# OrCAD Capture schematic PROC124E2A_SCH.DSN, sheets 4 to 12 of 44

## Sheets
4 12. SOC POWER SUPPLY PMIC: size C; title: SOC POWER SUPPLY PMIC
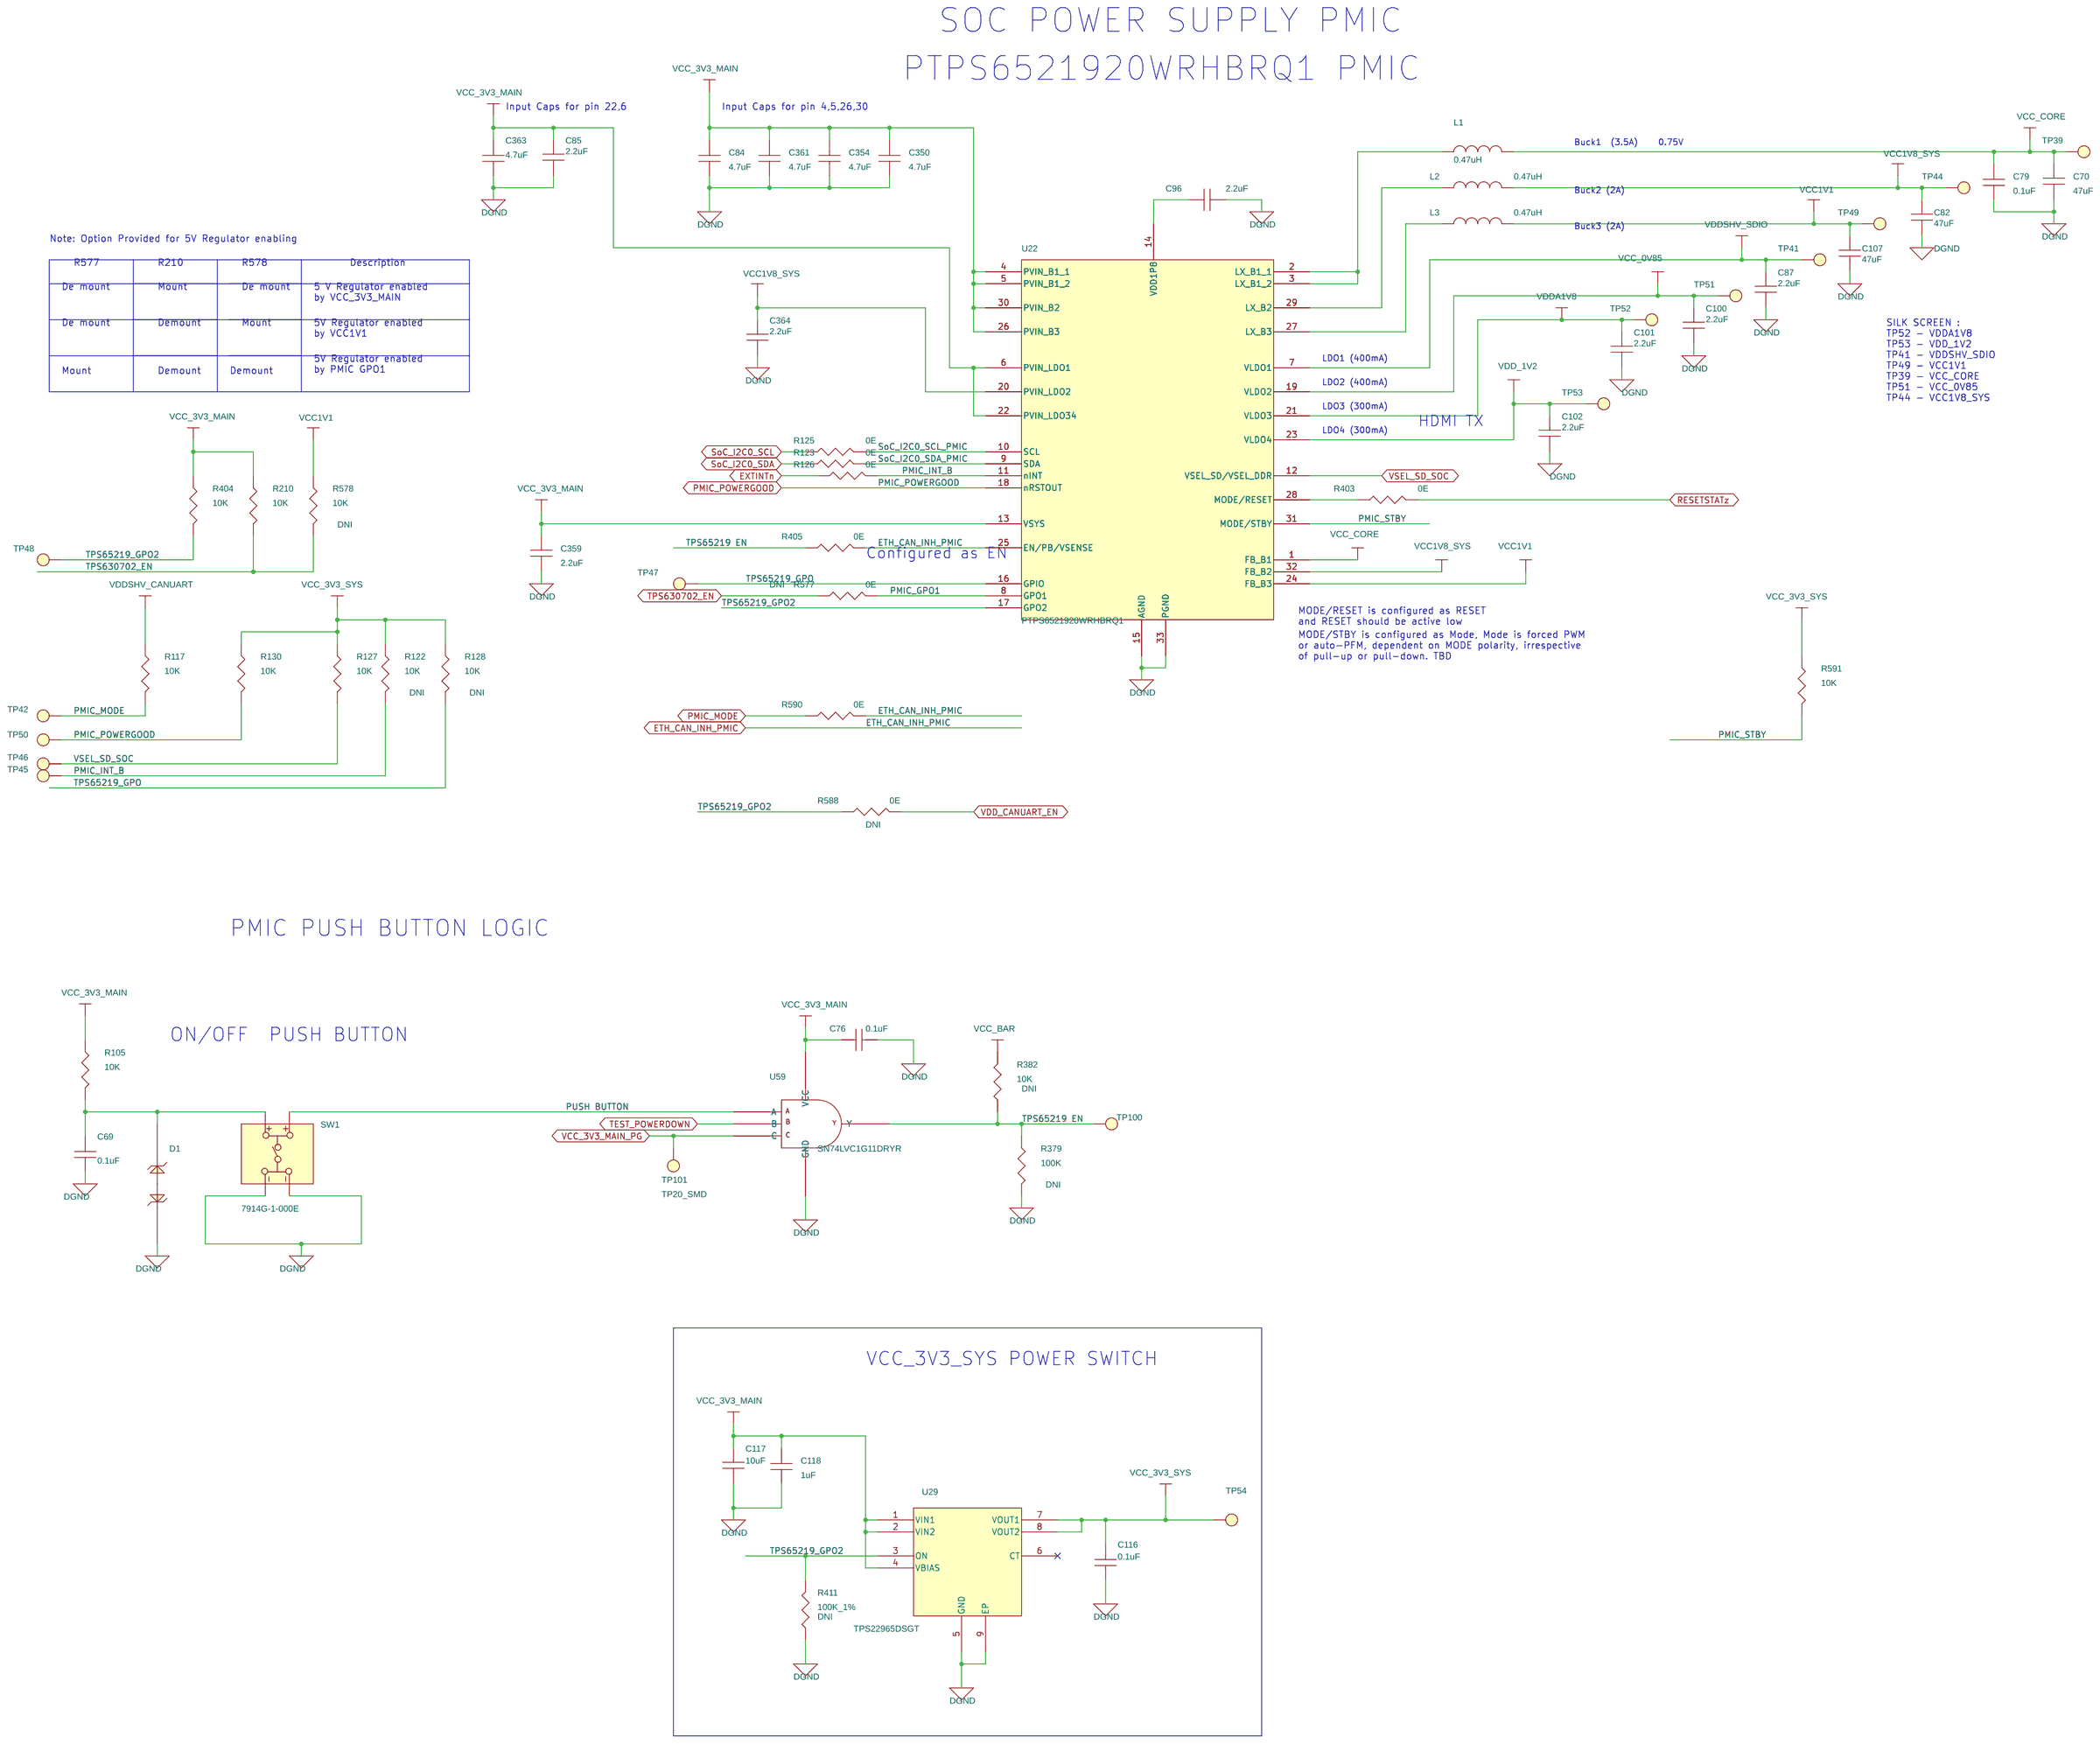
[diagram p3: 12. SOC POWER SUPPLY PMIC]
5 01. TABLE OF CONTENTS: title: TABLE OF CONTENTS
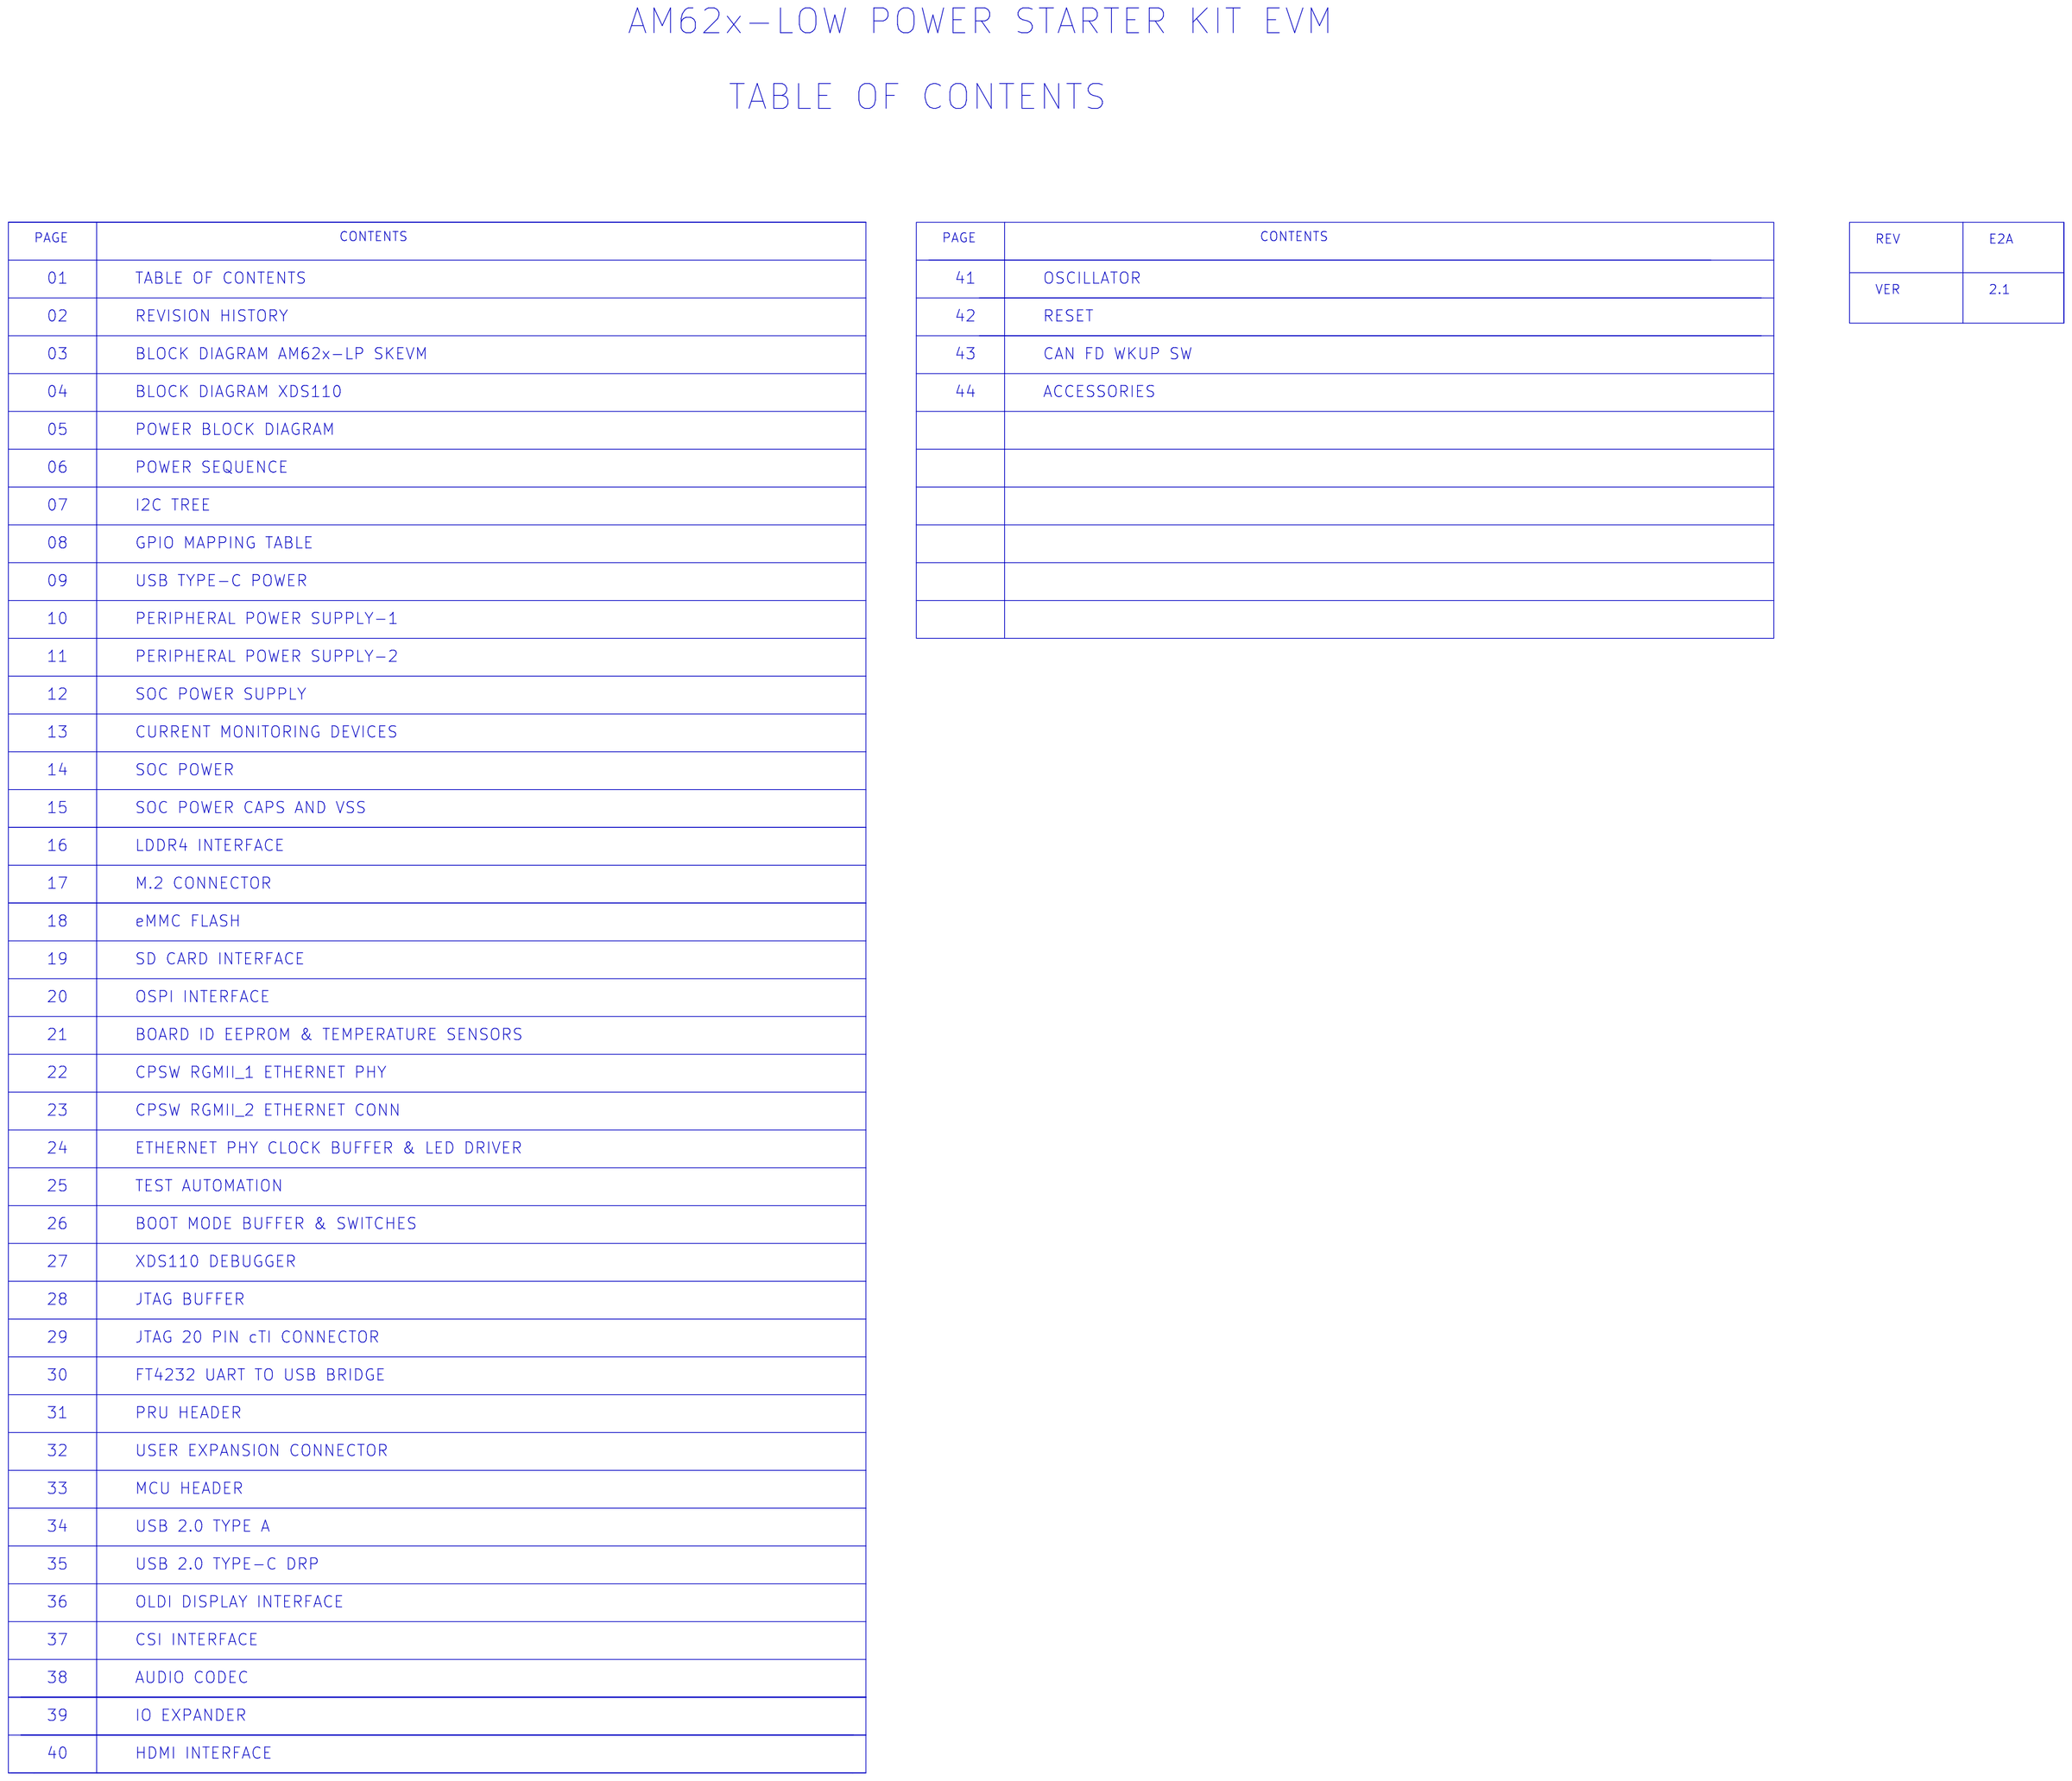
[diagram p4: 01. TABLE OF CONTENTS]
6 02. REVISION HISTORY: title: REVISION HISTORY
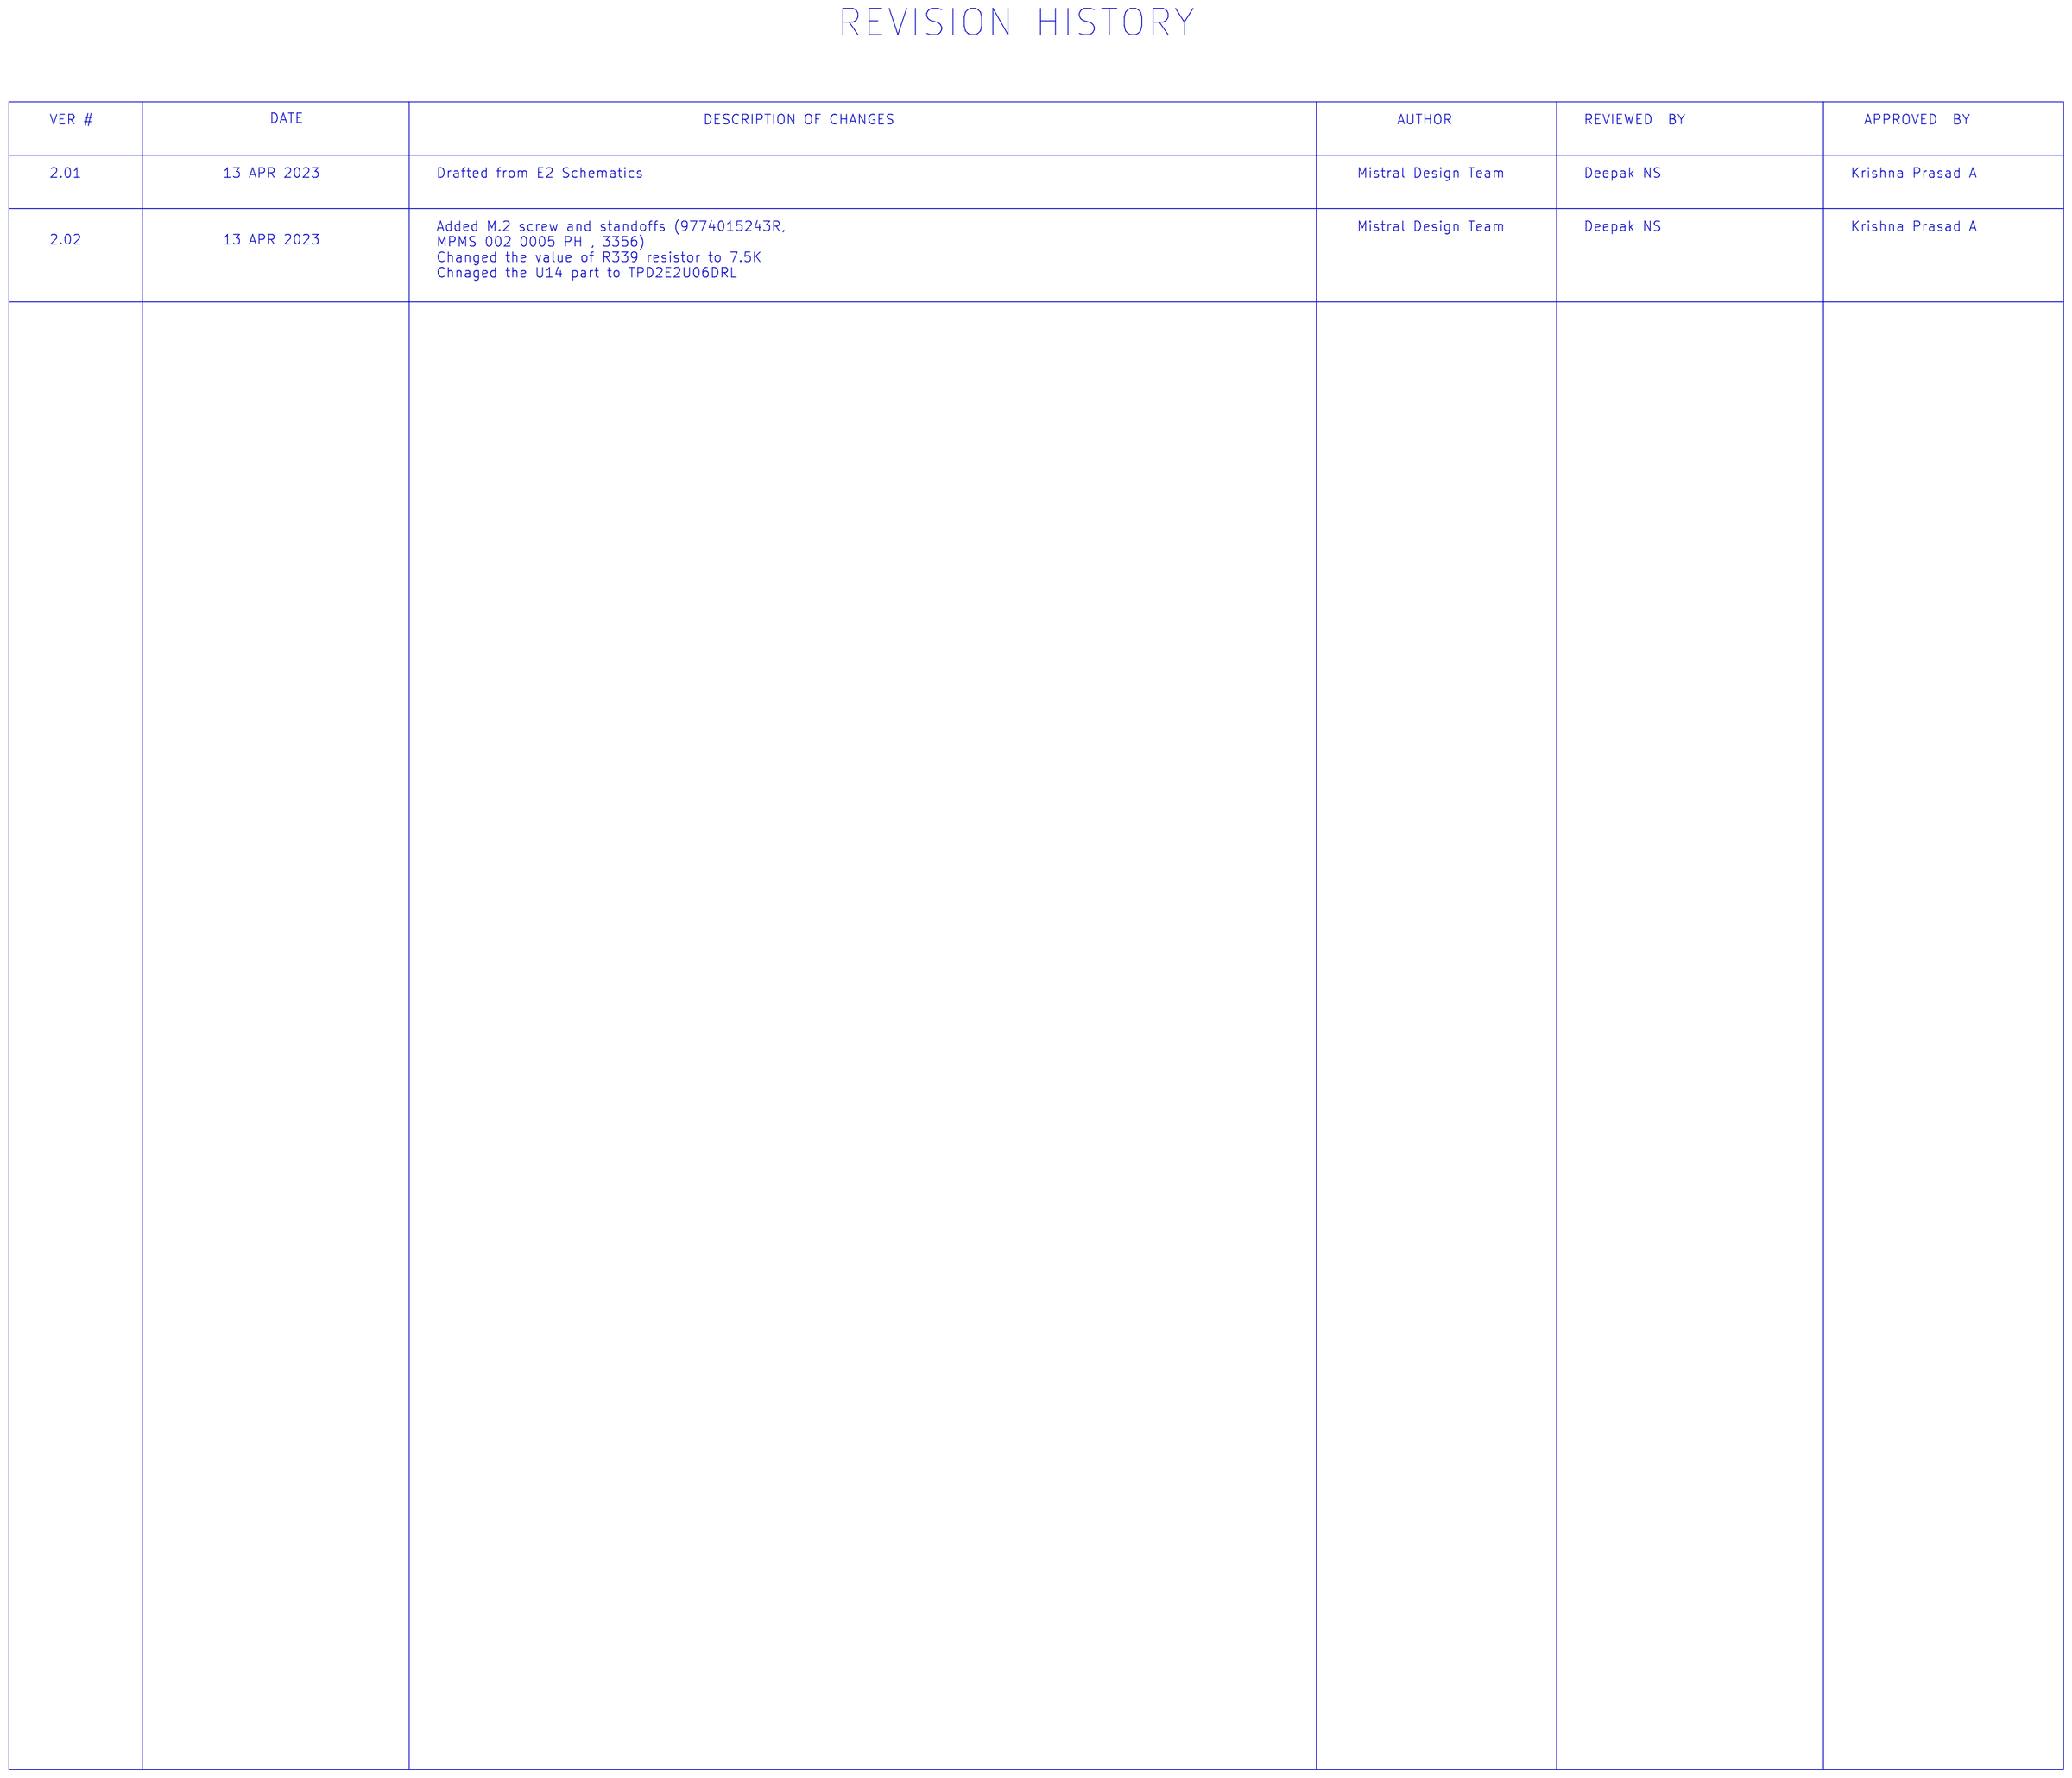
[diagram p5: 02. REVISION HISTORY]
7 03. BLOCK DGM AM62X-LP-SKEVM: title: BLOCK DIAGRAM AM62Q-LP_ SKEVM
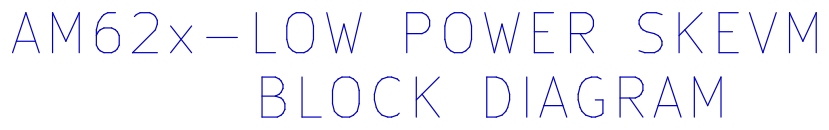
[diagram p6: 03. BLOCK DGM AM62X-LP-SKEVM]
8 04. BLOCK DIAGRAM_XDS110: title: BLOCK DIAGRAM_XDS110
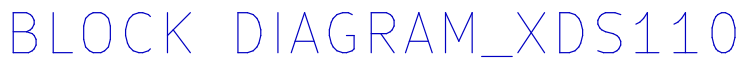
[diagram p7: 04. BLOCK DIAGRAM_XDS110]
9 05. POWER BLOCK DGM: title: POWER BLOCK DGM
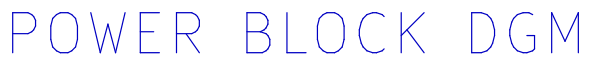
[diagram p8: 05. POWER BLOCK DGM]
10 06. POWER SEQUENCE: title: POWER SEQUENCE
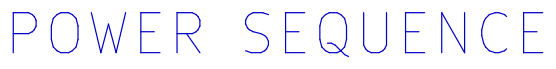
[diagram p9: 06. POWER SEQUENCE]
11 07. I2C TREE: title: I2C TREE
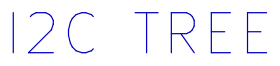
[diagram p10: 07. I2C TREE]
12 08. GPIO MAPPING TABLE: title: GPIO MAPPING TABLE

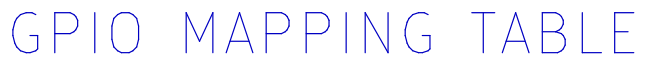
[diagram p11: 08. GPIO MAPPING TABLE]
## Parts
C69  0.1uF  [CAP0201_0-5]
C70  47uF  [CAP1206_2]
C76  0.1uF  [CAP0402_0-75]
C79  0.1uF  [CAP0201_0-5]
C82  47uF  [CAP1206_2]
C84  4.7uF  [CAP0402_0-75]
C85  2.2uF  [CAP0201_0-5]
C87  2.2uF  [CAP0201_0-5]
C96  2.2uF  [CAP0201_0-5]
C100  2.2uF  [CAP0201_0-5]
C101  2.2uF  [CAP0201_0-5]
C102  2.2uF  [CAP0201_0-5]
C107  47uF  [CAP1206_2]
C116  0.1uF  [CAP0201_0-5]
C117  10uF  [CAP0402_0-75]
C118  1uF  [CAP0201_0-5]
C350  4.7uF  [CAP0402_0-75]
C354  4.7uF  [CAP0402_0-75]
C359  2.2uF  [CAP0201_0-5]
C361  4.7uF  [CAP0402_0-75]
C363  4.7uF  [CAP0402_0-75]
C364  2.2uF  [CAP0201_0-5]
D1  TPD1E10B06DPYR  [DIO_DFN0402_0-5]
L1  0.47uH  [IND1008_1-2]
L2  0.47uH  [IND0806_1-2]
L3  0.47uH  [IND0806_1-2]
R105  10K  [RES0201_0-5]
R117  10K  [RES0201_0-5]
R122  10K  [RES0201_0-5]
R123  0E  [RES0201_0-5]
R125  0E  [RES0201_0-5]
R126  0E  [RES0201_0-5]
R127  10K  [RES0201_0-5]
R128  10K  [RES0201_0-5]
R130  10K  [RES0201_0-5]
R210  10K  [RES0201_0-5]
R379  100K  [RES0201_0-5]
R382  10K  [RES0201_0-5]
R403  0E  [RES0201_0-5]
R404  10K  [RES0201_0-5]
R405  0E  [RES0201_0-5]
R411  100K_1%  [RES0402_0-5]
R577  0E  [RES0201_0-5]
R578  10K  [RES0201_0-5]
R588  0E  [RES0201_0-5]
R590  0E  [RES0201_0-5]
R591  10K  [RES0201_0-5]
SW1  7914G-1-000E  [SW4_100X216_200X200_SMD_4-2]
TP39  TP20_SMD  [TP20_SMD]
TP41  TP20_SMD  [TP20_SMD]
TP42  TP20_SMD  [TP20_SMD]
TP44  TP20_SMD  [TP20_SMD]
TP45  TP20_SMD  [TP20_SMD]
TP46  TP20_SMD  [TP20_SMD]
TP47  TP20_SMD  [TP20_SMD]
TP48  TP20_SMD  [TP20_SMD]
TP49  TP20_SMD  [TP20_SMD]
TP50  TP20_SMD  [TP20_SMD]
TP51  TP20_SMD  [TP20_SMD]
TP52  TP20_SMD  [TP20_SMD]
TP53  TP20_SMD  [TP20_SMD]
TP54  TP20_SMD  [TP20_SMD]
TP100  TP20_SMD  [TP20_SMD]
TP101  TP20_SMD  [TP20_SMD]
U22  PTPS6521920WRHBRQ1  [QFN32_19-68_200X200_1_EP3-8]
U29  TPS22965DSGT  [WSON8_19-68_80X80_0-8]
U59  SN74LVC1G11DRYR  [SON6_SN74LVC2G17_40X60_0-6]

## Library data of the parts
C69 C116 = CAP: CAP CERAMIC 0.1uF 16V 10% X5R 0201; Alt_Mfr_name: YAGEO AMERICA; Alt_Mfr_part_number: CC0402KRX5R8BB104; Chkd/date: MANIRAJA/230118; Crtd /date: MANIRAJA/230118; Custom_Duty: 15%; Customs_HS_Code: 85322990; Distributor_name: DIGIKEY; Distributor_part_number: 490-14305-1-ND; Footprint Path: Y:\MIS_DATABASE\Library\ALTIUM_TOOL\PCB_FOOTPRINTS\Altium_Footprint_Lib.PcbLib; Height: 0.33MM; Library Path: Y:\MIS_DATABASE\Library\ALTIUM_TOOL\SCHEMATICS_PARTS\MS_DISCRETE_Library.schlib; Mfr_name: MURATA; Mfr_part_number: GRM033R61C104KE14D; Mistral Part No: 120009030072-R; Package: 0201; Part_type: CAPACITORS\CERAMIC; Project: TI_MAXIE_CPB; RoHS: RoHS; Temperature: -55°C+85°C; Tolerance: 10%; Voltage: 16V; Wattage: NA; Weight: 0.33mg; Datasheet: Y:\MIS_DATABASE\DATASHEETS\CAPACITORS\GRM033R61C104KE14.PDF
C70 = CAP: CAP CERAMIC 47uF 10V 10% X5R 1206; Chkd/date: MANIRAJA/260219; Crtd /date: JEBRAN/090316; Custom_Duty: 15%; Customs_HS_Code: 85322990; Distributor_name: DIGIKEY; Distributor_part_number: 490-9673-1-ND; Footprint Path: Y:\MIS_DATABASE\Library\ALTIUM_TOOL\PCB_FOOTPRINTS\Altium_Footprint_Lib.PcbLib; Height: 1.80MM; Library Path: Y:\MIS_DATABASE\Library\ALTIUM_TOOL\SCHEMATICS_PARTS\MS_DISCRETE_Library.schlib; Manufacturer: MURATA; Mfr_name: MURATA; Mfr_part_number: GRM31CR61A476KE15L; Mistral Part No: 120019020018-R; Package: 1206; Part_type: CAPACITORS\CERAMIC; Project: RCI_DLS_CARD; RoHS: RoHS; Temperature: -55°C+85°C; Tolerance: 10%; Voltage: 10V; Wattage: NA; Weight: 40mg; Datasheet: Y:\MIS_DATABASE\DATASHEETS\CAPACITORS\MURATA-GXX-SER_NOV17.PDF
C76 = CAP: CAP CERAMIC 0.1uF 50V 10% X7R 0402; Alt_Mfr_name: YAGEO AMERICA; Alt_Mfr_part_number: CC0402KRX5R8BB104; Chkd/date: MANIRAJA/261020; Crtd /date: ALVY/211020; Custom_Duty: 15%; Customs_HS_Code: 85322990; Distributor_name: DIGIKEY; Distributor_part_number: 490-10700-1-ND; Footprint Path: Y:\MIS_DATABASE\Library\ALTIUM_TOOL\PCB_FOOTPRINTS\Altium_Footprint_Lib.PcbLib; Height: 0.55MM; Library Path: Y:\MIS_DATABASE\Library\ALTIUM_TOOL\SCHEMATICS_PARTS\MS_DISCRETE_Library.schlib; Mfr_name: MURATA; Mfr_part_number: GRM155R71H104KE14D; Mistral Part No: 120011100014-R; Package: 0402; Part_type: CAPACITORS\CERAMIC; Project: J7_CP; RoHS: RoHS; Temperature: -55°C+125°C; Tolerance: 10%; Voltage: 50V; Wattage: NA; Weight: 3.1mg; Datasheet: Y:\MIS_DATABASE\DATASHEETS\CAPACITORS\GRM155R71H104KE14.PDF
C79 = CAP: CAP CERAMIC 0.1uF 16V 10% X5R 0201; Chkd/date: MANIRAJA/230118; Crtd /date: MANIRAJA/230118; Custom_Duty: 15%; Customs_HS_Code: 85322990; Distributor_name: DIGIKEY; Distributor_part_number: 490-14305-1-ND; Footprint Path: Y:\MIS_DATABASE\Library\ALTIUM_TOOL\PCB_FOOTPRINTS\Altium_Footprint_Lib.PcbLib; Height: 0.33MM; Library Path: Y:\MIS_DATABASE\Library\ALTIUM_TOOL\SCHEMATICS_PARTS\MS_DISCRETE_Library.schlib; Mfr_name: MURATA; Mfr_part_number: GRM033R61C104KE14D; Mistral Part No: 120009030072-R; Package: 0201; Part_type: CAPACITORS\CERAMIC; Project: TI_MAXIE_CPB; RoHS: RoHS; Temperature: -55°C+85°C; Tolerance: 10%; Voltage: 16V; Wattage: NA; Weight: 0.33mg; Datasheet: Y:\MIS_DATABASE\DATASHEETS\CAPACITORS\GRM033R61C104KE14.PDF
C82 C107 = CAP: CAP CERAMIC 47uF 10V 10% X5R 1206; Chkd/date: MANIRAJA/260219; Crtd /date: JEBRAN/090316; Custom_Duty: 15%; Customs_HS_Code: 85322990; Distributor_name: DIGIKEY; Distributor_part_number: 490-9673-1-ND; Footprint Path: Y:\MIS_DATABASE\Library\ALTIUM_TOOL\PCB_FOOTPRINTS\Altium_Footprint_Lib.PcbLib; Height: 1.80MM; Library Path: Y:\MIS_DATABASE\Library\ALTIUM_TOOL\SCHEMATICS_PARTS\MS_DISCRETE_Library.schlib; Mfr_name: MURATA; Mfr_part_number: GRM31CR61A476KE15L; Mistral Part No: 120019020018-R; Package: 1206; Part_type: CAPACITORS\CERAMIC; Project: RCI_DLS_CARD; RoHS: RoHS; Temperature: -55°C+85°C; Tolerance: 10%; Voltage: 10V; Wattage: NA; Weight: 40mg; Datasheet: Y:\MIS_DATABASE\DATASHEETS\CAPACITORS\MURATA-GXX-SER_NOV17.PDF
C84 C350 C354 C361 C363 = CAP: CAP CERAMIC 4.7uF 10V 20% X5R 0402; Chkd/date: MANIRAJA/110718; Crtd /date: ALVY/110718; Custom_Duty: 15%; Customs_HS_Code: 85322990; Distributor_name: DIGIKEY; Distributor_part_number: 490-14306-1-ND; Footprint Path: Y:\MIS_DATABASE\Library\ALTIUM_TOOL\PCB_FOOTPRINTS\Altium_Footprint_Lib.PcbLib; Height: 0.65MM; Library Path: Y:\MIS_DATABASE\Library\ALTIUM_TOOL\SCHEMATICS_PARTS\MS_DISCRETE_Library.schlib; Mfr_name: MURATA; Mfr_part_number: GRM155R61A475MEAAD; Mistral Part No: 120012060002-R; Package: 0402; Part_type: CAPACITORS\CERAMIC; Project: TI_J7SVB_PCIE_ADD-ON-CARD; RoHS: RoHS; Temperature: -55°C+85°C; Tolerance: 20%; Voltage: 10V; Wattage: NA; Weight: 14mg; Datasheet: Y:\MIS_DATABASE\DATASHEETS\CAPACITORS\GRM155R61A475MEAAD.PDF
C85 C87 C96 C100-C102 C364 = CAP: CAP CERAMIC 2.2uF 10V 10% X5R 0201; Chkd/date: MANIRAJA/220918; Crtd /date: MANIRAJA/220918; Custom_Duty: 15%; Customs_HS_Code: 85322990; Distributor_name: DIGIKEY; Distributor_part_number: 490-13227-1-ND; Footprint Path: Y:\MIS_DATABASE\Library\ALTIUM_TOOL\PCB_FOOTPRINTS\Altium_Footprint_Lib.PcbLib; Height: 0.39MM; Library Path: Y:\MIS_DATABASE\Library\ALTIUM_TOOL\SCHEMATICS_PARTS\MS_DISCRETE_Library.schlib; Mfr_name: MURATA; Mfr_part_number: GRM033R61A225KE47D; Mistral Part No: 120018090044-R; Package: 0201; Part_type: CAPACITORS\CERAMIC; Project: TI_60GHz-AOP; RoHS: RoHS; Temperature: -55°C+85°C; Tolerance: 10%; Voltage: 10V; Wattage: NA; Weight: 0.33mg; Datasheet: Y:\MIS_DATABASE\DATASHEETS\CAPACITORS\GRM033R61A225KE47D.PDF
C117 = CAP: CAP CERAMIC 10uF 10V 20% X5R 0402; Chkd/date: MANIRAJA/300520; Crtd /date: ALVY/260520; Custom_Duty: 15%; Customs_HS_Code: 85322990; Distributor_name: DIGIKEY; Distributor_part_number: 490-GRM155R61A106ME11DTR-ND; Footprint Path: Y:\MIS_DATABASE\Library\ALTIUM_TOOL\PCB_FOOTPRINTS\Altium_Footprint_Lib.PcbLib; Height: 0.55MM; Library Path: Y:\MIS_DATABASE\Library\ALTIUM_TOOL\SCHEMATICS_PARTS\MS_DISCRETE_Library.schlib; Mfr_name: MURATA; Mfr_part_number: GRM155R61A106ME11D; Mistral Part No: 120013110019-R; Package: 0402; Part_type: CAPACITORS\CERAMIC; Project: QCS610_NANOSOM; RoHS: RoHS; Temperature: -55°C+85°C; Tolerance: 20%; Voltage: 10V; Wattage: NA; Weight: 3.1mg; Datasheet: Y:\MIS_DATABASE\DATASHEETS\CAPACITORS\MURATA-GXX-SER_NOV17.PDF
C118 = CAP: CAP CERAMIC 1uF 16V 20% X5R 0201; Chkd/date: MANIRAJA/300520; Crtd /date: ALVY/260520; Custom_Duty: 15%; Customs_HS_Code: 85322990; Distributor_name: DIGIKEY; Distributor_part_number: 490-18654-1-ND; Footprint Path: Y:\MIS_DATABASE\Library\ALTIUM_TOOL\PCB_FOOTPRINTS\Altium_Footprint_Lib.PcbLib; Height: 0.39MM; Library Path: Y:\MIS_DATABASE\Library\ALTIUM_TOOL\SCHEMATICS_PARTS\MS_DISCRETE_Library.schlib; Mfr_name: MURATA; Mfr_part_number: GRM033R61C105ME15D; Mistral Part No: 120018090038-R; Package: 0201; Part_type: CAPACITORS\CERAMIC; Project: QCS610_NANOSOM; RoHS: RoHS; Temperature: -55°C+85°C; Tolerance: 20%; Voltage: 16V; Wattage: NA; Weight: 0.33mg; Datasheet: Y:\MIS_DATABASE\DATASHEETS\CAPACITORS\GRM033R61C105ME15.PDF
C359 = CAP: CAP CERAMIC 2.2uF 10V 10% X5R 0201; Alt_Mfr_name: YAGEO AMERICA; Alt_Mfr_part_number: CC0402KRX5R8BB104; Chkd/date: MANIRAJA/220918; Crtd /date: MANIRAJA/220918; Custom_Duty: 15%; Customs_HS_Code: 85322990; Distributor_name: DIGIKEY; Distributor_part_number: 490-13227-1-ND; Footprint Path: Y:\MIS_DATABASE\Library\ALTIUM_TOOL\PCB_FOOTPRINTS\Altium_Footprint_Lib.PcbLib; Height: 0.39MM; Library Path: Y:\MIS_DATABASE\Library\ALTIUM_TOOL\SCHEMATICS_PARTS\MS_DISCRETE_Library.schlib; Mfr_name: MURATA; Mfr_part_number: GRM033R61A225KE47D; Mistral Part No: 120018090044-R; Package: 0201; Part_type: CAPACITORS\CERAMIC; Project: TI_60GHz-AOP; RoHS: RoHS; Temperature: -55°C+85°C; Tolerance: 10%; Voltage: 10V; Wattage: NA; Weight: 0.33mg; Datasheet: Y:\MIS_DATABASE\DATASHEETS\CAPACITORS\GRM033R61A225KE47D.PDF
D1 = DIODE_SOD323: DIODE 1CH ESD PROTECTION X1SON2; Chkd/date: MANIRAJA/040420; Crtd /date: VASANTHA/181114; Custom_Duty: 15%; Customs_HS_Code: 85423100; Distributor_name: DIGIKEY; Distributor_part_number: 296-30406-1-ND; Footprint Path: Y:\MIS_DATABASE\Library\ALTIUM_TOOL\PCB_FOOTPRINTS\Altium_Footprint_Lib.PcbLib; Height: 0.45MM; Library Path: Y:\MIS_DATABASE\Library\ALTIUM_TOOL\SCHEMATICS_PARTS\MS_DISCRETE_Library.schlib; Mfr_name: TEXAS INSTRUMENTS; Mistral Part No: 130014110022-R; Package: X1SON2; Part_type: DIODE; Project: GALILEO_EVM; RoHS: RoHS; Temperature: -40°C+125°C; Tolerance: NA; Voltage: NA; Wattage: NA; Weight: 1mg; Datasheet: Y:\MIS_DATABASE\DATASHEETS\ICS\INTERFACE\TPD1E10B06-SER.PDF
L1 = INDUCTOR: IND CHIP 0.47uH 4.9A 20% 1008; Chkd/date: ALVY/110322; Crtd /date: TAMILARASU/100322; Custom_Duty: 24%; Customs_HS_Code: 85437099; Distributor_name: DIGIKEY; Distributor_part_number: 490-13049-1-ND; Footprint Path: Y:\MIS_DATABASE\Library\ALTIUM_TOOL\PCB_FOOTPRINTS\Altium_Footprint_Lib.PcbLib; Height: 1.20MM; Library Path: Y:\MIS_DATABASE\Library\ALTIUM_TOOL\SCHEMATICS_PARTS\MS_DISCRETE_Library.schlib; Mfr_name: MURATA; Mfr_part_number: DFE252012F-R47M=P2; Mistral Part No: 130022030019-R; Package: 1008; Project: TI_AM62Q_SKEVM_xNAND_BRD; RoHS: RoHS; Temperature: -40°C+125°C; Tolerance: 20%; Voltage: NA; Wattage: NA; Weight: NA; Datasheet: Y:\MIS_DATABASE\DATASHEETS\DISCRETES\INDUCTORS\DFE252012F.PDF
L2 L3 = INDUCTOR: IND CHIP 0.47uH 4.5A 20% 0806; Chkd/date: MANIRAJA/121020; Crtd /date: ALVY/121020; Custom_Duty: 24%; Customs_HS_Code: 85437099; Distributor_name: DIGIKEY; Distributor_part_number: DFE201612E-R47M=P2-ND; Footprint Path: Y:\MIS_DATABASE\Library\ALTIUM_TOOL\PCB_FOOTPRINTS\Altium_Footprint_Lib.PcbLib; Height: 1.20MM; Library Path: Y:\MIS_DATABASE\Library\ALTIUM_TOOL\SCHEMATICS_PARTS\MS_DISCRETE_Library.schlib; Mfr_name: MURATA; Mfr_part_number: DFE201612E-R47M=P2; Mistral Part No: 130020100030-R; Package: 0806; Project: AM64X_SKEVM; RoHS: RoHS; Temperature: -40°C+125°C; Tolerance: 20%; Voltage: NA; Wattage: NA; Weight: 18.8mg; Datasheet: Y:\MIS_DATABASE\DATASHEETS\DISCRETES\INDUCTORS\DFE201612E.PDF
R105 R117 R127 R130 R210 R404 R591 = RESISTOR: RES 10K 1/20W 5% 0201; Chkd/date: MANIRAJA/050517; Crtd /date: MANIRAJA/050517; Custom_Duty: 15%; Customs_HS_Code: 85332119; Distributor_name: DIGIKEY; Distributor_part_number: 311-10KNCT-ND; Footprint Path: Y:\MIS_DATABASE\Library\ALTIUM_TOOL\PCB_FOOTPRINTS\Altium_Footprint_Lib.PcbLib; Height: 0.26MM; Library Path: Y:\MIS_DATABASE\Library\ALTIUM_TOOL\SCHEMATICS_PARTS\MS_DISCRETE_Library.schlib; Mfr_name: YAGEO AMERICA; Mfr_part_number: RC0201JR-0710KL; Mistral Part No: 110010070051-R; Package: 0201; Part_type: RESISTORS\FIXED; Project: GOLDEN-I LITE; RoHS: RoHS; Temperature: -55°C+125°C; Tolerance: 5%; Voltage: NA; Wattage: 1/20W; Weight: 0.17mg; Datasheet: Y:\MIS_DATABASE\DATASHEETS\RESISTORS\RCXXXXL-SER_MAR18.PDF
R122 R128 R382 R578 = RESISTOR: RES 10K 1/20W 5% 0201; Assembly_Instruction: DNI; Chkd/date: MANIRAJA/050517; Crtd /date: MANIRAJA/050517; Custom_Duty: 15%; Customs_HS_Code: 85332119; Distributor_name: DIGIKEY; Distributor_part_number: 311-10KNCT-ND; Footprint Path: Y:\MIS_DATABASE\Library\ALTIUM_TOOL\PCB_FOOTPRINTS\Altium_Footprint_Lib.PcbLib; Height: 0.26MM; Library Path: Y:\MIS_DATABASE\Library\ALTIUM_TOOL\SCHEMATICS_PARTS\MS_DISCRETE_Library.schlib; Mfr_name: YAGEO AMERICA; Mfr_part_number: RC0201JR-0710KL; Mistral Part No: 110010070051-R; Package: 0201; Part_type: RESISTORS\FIXED; Project: GOLDEN-I LITE; RoHS: RoHS; Temperature: -55°C+125°C; Tolerance: 5%; Voltage: NA; Wattage: 1/20W; Weight: 0.17mg; Datasheet: Y:\MIS_DATABASE\DATASHEETS\RESISTORS\RCXXXXL-SER_MAR18.PDF
R123 R125 R403 = RESISTOR: RES 0E 1/20W JUMPER 0201; Chkd/date: MANIRAJA/290421; Crtd /date: ALVY/290421; Custom_Duty: 15%; Customs_HS_Code: 85332119; Distributor_name: DIGIKEY; Distributor_part_number: P15979CT-ND; Footprint Path: Y:\MIS_DATABASE\Library\ALTIUM_TOOL\PCB_FOOTPRINTS\Altium_Footprint_Lib.PcbLib; Height: 0.26MM; Library Path: Y:\MIS_DATABASE\Library\ALTIUM_TOOL\SCHEMATICS_PARTS\MS_DISCRETE_Library.schlib; Mfr_name: PANASONIC-ECG; Mfr_part_number: ERJ-1GN0R00C; Mistral Part No: 110009030078-R; Package: 0201; Part_type: RESISTORS\FIXED; Project: SRMS-SAR_BRD; RoHS: RoHS; Temperature: -55°C+125°C; Tolerance: NA; Voltage: NA; Wattage: 1/20W; Weight: 0.15mg; Datasheet: Y:\MIS_DATABASE\DATASHEETS\RESISTORS\PAN-ERJSER_NOV17.PDF
R126 R405 R590 = RESISTOR: RES 0E 1/20W 5% 0201; Chkd/date: NAVEED/301214; Crtd /date: MUDDU/120710; Custom_Duty: 15%; Customs_HS_Code: 85332119; Distributor_name: DIGIKEY; Distributor_part_number: 311-0.0NCT-ND; Footprint Path: Y:\MIS_DATABASE\Library\ALTIUM_TOOL\PCB_FOOTPRINTS\Altium_Footprint_Lib.PcbLib; Height: 0.26MM; Library Path: Y:\MIS_DATABASE\Library\ALTIUM_TOOL\SCHEMATICS_PARTS\MS_DISCRETE_Library.schlib; Mfr_name: YAGEO AMERICA; Mfr_part_number: RC0201JR-070RL; Mistral Part No: 110010070067-R; Package: 0201; Part_type: RESISTORS\FIXED; Project: PB_BUGBASE; RoHS: RoHS; Temperature: -55°C+125°C; Tolerance: 5%; Voltage: NA; Wattage: 1/20W; Weight: 0.17mg; Datasheet: Y:\MIS_DATABASE\DATASHEETS\RESISTORS\RCXXXXL-SER_MAR18.PDF
R379 = RESISTOR: RES 100K 1/20W 5% 0201; Assembly_Instruction: DNI; Chkd/date: PRAVEEN/080922; Crtd /date: TAMILARASU/080922; Custom_Duty: 15%; Customs_HS_Code: 85332119; Distributor_name: DIGIKEY; Distributor_part_number: P123223CT-ND; Footprint Path: Y:\MIS_DATABASE\Library\ALTIUM_TOOL\PCB_FOOTPRINTS\Altium_Footprint_Lib.PcbLib; Height: 0.26MM; Library Path: Y:\MIS_DATABASE\Library\ALTIUM_TOOL\SCHEMATICS_PARTS\MS_DISCRETE_Library.schlib; Mfr_name: PANASONIC-ECG; Mfr_part_number: ERJ-1GNJ104C; Mistral Part No: 110022090005-R; Package: 0201; Part_type: RESISTORS\FIXED; Project: SK AM62Q LP EVM BRD; RoHS: RoHS; Temperature: -55°C+125°C; Tolerance: 5%; Voltage: NA; Wattage: 1/20W; Weight: 0.15mg; Datasheet: Y:\MIS_DATABASE\DATASHEETS\RESISTORS\PAN-ERJSER_NOV17.PDF
R411 = RESISTOR: RES 100K 1/10W 1% 0402; Assembly_Instruction: DNI; Chkd/date: VASANTHA/201216; Crtd /date: MAZHAR/130306; Custom_Duty: 15%; Customs_HS_Code: 85332119; Distributor_name: DIGIKEY; Distributor_part_number: P100KLCT-ND; Footprint Path: Y:\MIS_DATABASE\Library\ALTIUM_TOOL\PCB_FOOTPRINTS\Altium_Footprint_Lib.PcbLib; Height: 0.40MM; Library Path: Y:\MIS_DATABASE\Library\ALTIUM_TOOL\SCHEMATICS_PARTS\MS_DISCRETE_Library.schlib; Mfr_name: PANASONIC-ECG; Mfr_part_number: ERJ-2RKF1003X; Mistral Part No: 110009030187-R; Package: 0402; Part_type: RESISTORS\FIXED; Project: J32; RoHS: RoHS; Temperature: -55°C+155°C; Tolerance: 1%; Voltage: NA; Wattage: 1/10W; Weight: 0.8mg; Datasheet: Y:\MIS_DATABASE\DATASHEETS\RESISTORS\PAN-ERJSER_NOV17.PDF
R577 R588 = RESISTOR: RES 0E 1/20W 5% 0201; Assembly_Instruction: DNI; Chkd/date: NAVEED/301214; Crtd /date: MUDDU/120710; Custom_Duty: 15%; Customs_HS_Code: 85332119; Distributor_name: DIGIKEY; Distributor_part_number: 311-0.0NCT-ND; Footprint Path: Y:\MIS_DATABASE\Library\ALTIUM_TOOL\PCB_FOOTPRINTS\Altium_Footprint_Lib.PcbLib; Height: 0.26MM; Library Path: Y:\MIS_DATABASE\Library\ALTIUM_TOOL\SCHEMATICS_PARTS\MS_DISCRETE_Library.schlib; Mfr_name: YAGEO AMERICA; Mfr_part_number: RC0201JR-070RL; Mistral Part No: 110010070067-R; Package: 0201; Part_type: RESISTORS\FIXED; Project: PB_BUGBASE; RoHS: RoHS; Temperature: -55°C+125°C; Tolerance: 5%; Voltage: NA; Wattage: 1/20W; Weight: 0.17mg; Datasheet: Y:\MIS_DATABASE\DATASHEETS\RESISTORS\RCXXXXL-SER_MAR18.PDF
SW1 = 7914G-1-000E__7914G: SWITCH SPST-NO 4MM SQ SMD 7914G; Chkd/date: VASANTHA/271216; Crtd /date: BAVISH/051010; Custom_Duty: 24%; Customs_HS_Code: 85369090; Distributor_name: DIGIKEY; Distributor_part_number: 7914G-000ECT-ND; Height: 4.19MM; Library Ref: 7914G-1-000E _7914G; Mfr_name: BOURNS; Mistral Part No: 130015110004-R; Package: 7914G; Part_type: ELECTRO-MECHANICAL\SWITCH; Project: AAAUC; RoHS: RoHS; Temperature: -55°C+125°C; Tolerance: NA; Voltage: NA; Wattage: NA; Weight: NA; Datasheet: Y:\MIS_DATABASE\DATASHEETS\ICS\DIGITAL\COMBINATIONAL\7914G-1-000E.PDF
TP39 TP41 TP44 TP47-TP49 TP51-TP53 TP101 = TESTPOINT: TESTPOINT CIR 20 SMD; Chkd/date: SHREESHAIL/171006; Crtd /date: MAZHAR/171006; Custom_Duty: NA; Customs_HS_Code: NA; Distributor_name: NA; Distributor_part_number: NA; Footprint Path: Y:\MIS_DATABASE\Library\ALTIUM_TOOL\PCB_FOOTPRINTS\Altium_Footprint_Lib.PcbLib; Height: NA; Library Path: Y:\MIS_DATABASE\Library\ALTIUM_TOOL\SCHEMATICS_PARTS\MS_DISCRETE_Library.schlib; MECHANICAL 3D STEP FILE: NA; Manufacturer: LOCAL; Mfr_name: LOCAL; Mistral Part No: NA; Package: SMD; Project: BT MODULE_CSRBC04; RoHS: NA; Temperature: NA; Tolerance: NA; Voltage: NA; Wattage: NA; Weight: NA; Datasheet: NA
TP42 TP45 TP46 TP50 TP54 TP100 = TESTPOINT: TESTPOINT CIR 20 SMD; Chkd/date: SHREESHAIL/171006; Crtd /date: MAZHAR/171006; Custom_Duty: NA; Customs_HS_Code: NA; Distributor_name: NA; Distributor_part_number: NA; Footprint Path: Y:\MIS_DATABASE\Library\ALTIUM_TOOL\PCB_FOOTPRINTS\Altium_Footprint_Lib.PcbLib; Height: NA; Library Path: Y:\MIS_DATABASE\Library\ALTIUM_TOOL\SCHEMATICS_PARTS\MS_DISCRETE_Library.schlib; MECHANICAL 3D STEP FILE: NA; Mfr_name: LOCAL; Mistral Part No: NA; Package: SMD; Project: BT MODULE_CSRBC04; RoHS: NA; Temperature: NA; Tolerance: NA; Voltage: NA; Wattage: NA; Weight: NA; Datasheet: NA
U22 = TPS65219_QFN32: IC INTEGRATED POWER MANAGEMENT FOR ARM CORTEX-A53 PROCESSOR AND FPGA QFN32; Chkd/date: PRAVEEN/130123; Crtd /date: SHANKAR/110123; Custom_Duty: 15%; Customs_HS_Code: 85423100; Distributor_name: NA; Distributor_part_number: NA; Footprint Path: Y:\MIS_DATABASE\Library\ALTIUM_TOOL\PCB_FOOTPRINTS\Altium_Footprint_Lib.PcbLib; Height: 1.00MM; Library Path: Y:\MIS_DATABASE\Library\ALTIUM_TOOL\SCHEMATICS_PARTS\MS_MISCPOWER_Library.schlib; Mfr_name: TEXAS INSTRUMENTS; Mistral Part No: 142023010008-R; Package: QFN32; Part_type: ICS\POWER\MANAGEMENT; Project: AM62Q-LP_EVM; RoHS: NA; Temperature: -40°C+125°C; Tolerance: NA; Voltage: NA; Wattage: NA; Weight: NA; Datasheet: Y:\MIS_DATABASE\DATASHEETS\ICS\POWER\TPS65219.PDF
U29 = TPS22965DSGT_WSON8: IC 5.7V 6A 1-CHANNEL 16mE ON-RESISTANCE LOAD SWITCH WSON8; Chkd/date: MANIRAJA/080817; Crtd /date: VASANTHA/280714; Custom_Duty: 15%; Customs_HS_Code: 85423100; Distributor_name: DIGIKEY; Distributor_part_number: 296-34943-1-ND; Footprint Path: Y:\MIS_DATABASE\Library\ALTIUM_TOOL\PCB_FOOTPRINTS\Altium_Footprint_Lib.PcbLib; Height: 0.80MM; Library Path: Y:\MIS_DATABASE\Library\ALTIUM_TOOL\SCHEMATICS_PARTS\MS_MISCPOWER_Library.schlib; Mfr_name: TEXAS INSTRUMENTS; Mistral Part No: 142014070020-R; Package: WSON8; Part_type: ICS\POWER\DRIVER; Project: DC_MIST_DIGITAL CARD; RoHS: RoHS; Temperature: -40°C+105°C; Tolerance: NA; Voltage: NA; Wattage: NA; Weight: 11mg; Datasheet: Y:\MIS_DATABASE\DATASHEETS\ICS\POWER\TPS22965-SER.PDF
U59 = SN74LVC1G11DCKR_SC70-6: IC SINGLE 3-INPUT POSITIVE-AND GATE SON6; Chkd/date: MANIRAJA/270121; Crtd /date: ALVY/270121; Custom_Duty: 15%; Customs_HS_Code: 85423100; Distributor_name: DIGIKEY; Distributor_part_number: 296-30120-1-ND; Footprint Path: Y:\MIS_DATABASE\Library\ALTIUM_TOOL\PCB_FOOTPRINTS\Altium_Footprint_Lib.PcbLib; Height: 0.60MM; Library Path: Y:\MIS_DATABASE\Library\ALTIUM_TOOL\SCHEMATICS_PARTS\MS_GATE_Library.schlib; Mfr_name: TEXAS INSTRUMENTS; Mistral Part No: 141021010013-R; Package: SON6; Part_type: ICS\DIGITAL\GATES; Project: AM64X_SKEVM; RoHS: RoHS; Temperature: -40°C+125°C; Tolerance: NA; Voltage: NA; Wattage: NA; Weight: 33mg; Datasheet: Y:\MIS_DATABASE\DATASHEETS\ICS\DIGITAL\GATES\SN74LVC1G_NOV16.PDF

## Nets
DGND: C69.1 C70.2 C76.2 C79.1 C82.2 C84.1 C85.2 C87.2 C96.2 C100.2 C101.2 C102.2 C107.2 C116.1 C117.2 C118.1 C350.1 C354.1 C359.2 C361.1 C363.1 C364.2 D1.1 R379.2 R411.1 SW1.1 SW1.4 U22.15(AGND) U22.33(PGND) U29.5(GND) U29.9(EP) U59.2(GND) ; also on sheet 1 2 3 13 14 15 16 17 18 19 20 21 22 23 24 25 26 27 28 29 30 31 32 33 34 35 36 37 38 39 40 41 42 43
VCC1V1: C107.1 L3.2 R578.2 TP49.1(TP) U22.24(FB_B3) ; also on sheet 16
VCC1V8_SYS: C82.1 C364.1 L2.2 TP44.1(TP) U22.20(PVIN_LDO2) U22.32(FB_B2) ; also on sheet 16 19 20 22 25 34 37 39 40 42
VCC_0V85: C100.1 TP51.1(TP) U22.19(VLDO2) ; also on sheet 16
VCC_3V3_MAIN: C76.1 C84.2 C85.1 C117.1 C118.2 C350.2 C354.2 C359.1 C361.2 C363.2 R105.1 R210.2 R382.1 R404.2 U22.4(PVIN_B1_1) U22.5(PVIN_B1_2) U22.6(PVIN_LDO1) U22.13(VSYS) U22.22(PVIN_LDO34) U22.26(PVIN_B3) U22.30(PVIN_B2) U29.1(VIN1) U29.2(VIN2) U29.4(VBIAS) U59.5(VCC) ; also on sheet 15 17
VCC_3V3_MAIN_PG: TP101.1(TP) U59.6(C) ; also on sheet 15
VCC_3V3_SYS: C116.2 R122.2 R127.2 R128.2 R130.2 R591.2 TP54.1(TP) U29.7(VOUT1) U29.8(VOUT2) ; also on sheet 1 15 16 19 20 21 23 24 26 27 29 30 31 32 33 34 36 37 38 39 40 41 42 43
VCC_CORE: C70.1 C79.2 L1.2 TP39.1(TP) U22.1(FB_B1) ; also on sheet 16
VDD_1V2: C102.1 TP53.1(TP) U22.23(VLDO4) ; also on sheet 41
VDD_CANUART_EN: R588.2 ; also on sheet 17
VDDA1V8: C101.1 TP52.1(TP) U22.21(VLDO3) ; also on sheet 16
VDDSHV_CANUART: R117.2 ; also on sheet 2 17 31 32
VDDSHV_SDIO: C87.1 TP41.1(TP) U22.7(VLDO1) ; also on sheet 17 21
ETH_CAN_INH_PMIC: R405.2 R590.2 U22.25(EN/PB/VSENSE) ; also on sheet 32
EXTINTn: R126.1 ; also on sheet 42
PMIC_GPO1: R577.2 U22.8(GPO1)
PMIC_INT_B: R122.1 R126.2 TP45.1(TP) U22.11(nINT)
PMIC_MODE: R117.1 R590.1 TP42.1(TP) ; also on sheet 32
PMIC_POWERGOOD: R130.1 TP50.1(TP) U22.18(nRSTOUT) ; also on sheet 42
PMIC_STBY: R591.1 U22.31(MODE/STBY)
PUSH BUTTON: SW1.3 U59.1(A)
RESETSTATz: R403.1 ; also on sheet 1 20 21 22 24 27 32 37 38 39 40 41 42
SoC_I2C0_SCL: R125.1 ; also on sheet 13 23 32 33 37 42
SoC_I2C0_SCL_PMIC: R125.2 U22.10(SCL)
SoC_I2C0_SDA: R123.1 ; also on sheet 13 23 32 33 37 42
SoC_I2C0_SDA_PMIC: R123.2 U22.9(SDA)
TEST_POWERDOWN: U59.3(B) ; also on sheet 14 26 28
TPS65219 EN: R379.1 R382.2 R405.1 TP100.1(TP) U59.4(Y)
TPS65219_GPO: R128.1 TP47.1(TP) U22.16(GPIO)
TPS65219_GPO2: R404.1 R411.2 R588.1 TP48.1(TP) U22.17(GPO2) U29.3(ON)
TPS630702_EN: R210.1 R577.1 R578.1 ; also on sheet 14
VSEL_SD_SOC: R127.1 TP46.1(TP) U22.12(VSEL_SD/VSEL_DDR) ; also on sheet 32
N19361213: R403.2 U22.28(MODE/RESET)
N19361868: L3.1 U22.27(LX_B3)
N19361874: L2.1 U22.29(LX_B2)
N19361880: L1.1 U22.2(LX_B1_1) U22.3(LX_B1_2)
N19361937: C69.2 D1.2 R105.2 SW1.2
N19362078: C96.1 U22.14(VDD1P8)

Not connected (* = marked no-connect by the designer): U29 6(CT)*

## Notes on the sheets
sheet 4
- SOC POWER SUPPLY PMIC
- PTPS6521920WRHBRQ1 PMIC
- Input Caps for pin 22,6
- Input Caps for pin 4,5,26,30
- Buck1  (3.5A)
- 0.75V
- Buck2 (2A)
- Buck3 (2A)
- Note: Option Provided for 5V Regulator enabling
- R577
- R210
- R578
- Description
- De mount
- Mount
- De mount
- 5 V Regulator enabled
  by VCC_3V3_MAIN
- De mount
- Demount
- Mount
- 5V Regulator enabled
  by VCC1V1
- SILK SCREEN :
  TP52 - VDDA1V8
  TP53 - VDD_1V2
  TP41 - VDDSHV_SDIO
  TP49 - VCC1V1
  TP39 - VCC_CORE
  TP51 - VCC_0V85
  TP44 - VCC1V8_SYS
- 5V Regulator enabled
  by PMIC GPO1
- LDO1 (400mA)
- Mount
- Demount
- Demount
- LDO2 (400mA)
- LDO3 (300mA)
- HDMI TX
- LDO4 (300mA)
- Configured as EN
- MODE/RESET is configured as RESET
  and RESET should be active low
- MODE/STBY is configured as Mode, Mode is forced PWM
  or auto-PFM, dependent on MODE polarity, irrespective
  of pull-up or pull-down. TBD
- PMIC PUSH BUTTON LOGIC
- ON/OFF  PUSH BUTTON
- VCC_3V3_SYS POWER SWITCH
sheet 5
- AM62x-LOW POWER STARTER KIT EVM
- TABLE OF CONTENTS
- PAGE
- CONTENTS
- PAGE
- CONTENTS
- REV
- E2A
- 01
- TABLE OF CONTENTS
- 41
- OSCILLATOR
- VER
- 2.1
- 02
- REVISION HISTORY
- 42
- RESET
- 03
- BLOCK DIAGRAM AM62x-LP SKEVM
- 43
- CAN FD WKUP SW
- 04
- BLOCK DIAGRAM XDS110
- 44
- ACCESSORIES
- 05
- POWER BLOCK DIAGRAM
- 06
- POWER SEQUENCE
- 07
- I2C TREE
- 08
- GPIO MAPPING TABLE
- 09
- USB TYPE-C POWER
- 10
- PERIPHERAL POWER SUPPLY-1
- 11
- PERIPHERAL POWER SUPPLY-2
- 12
- SOC POWER SUPPLY
- 13
- CURRENT MONITORING DEVICES
- 14
- SOC POWER
- 15
- SOC POWER CAPS AND VSS
- 16
- LDDR4 INTERFACE
- 17
- M.2 CONNECTOR
- 18
- eMMC FLASH
- 19
- SD CARD INTERFACE
- 20
- OSPI INTERFACE
- 21
- BOARD ID EEPROM & TEMPERATURE SENSORS
- 22
- CPSW RGMII_1 ETHERNET PHY
- 23
- CPSW RGMII_2 ETHERNET CONN
- 24
- ETHERNET PHY CLOCK BUFFER & LED DRIVER
- 25
- TEST AUTOMATION
- 26
- BOOT MODE BUFFER & SWITCHES
- 27
- XDS110 DEBUGGER
- 28
- JTAG BUFFER
- 29
- JTAG 20 PIN cTI CONNECTOR
- 30
- FT4232 UART TO USB BRIDGE
- 31
- PRU HEADER
- 32
- USER EXPANSION CONNECTOR
- 33
- MCU HEADER
- 34
- USB 2.0 TYPE A
- 35
- USB 2.0 TYPE-C DRP
- 36
- OLDI DISPLAY INTERFACE
- 37
- CSI INTERFACE
- 38
- AUDIO CODEC
- 39
- IO EXPANDER
- 40
- HDMI INTERFACE
sheet 6
- REVISION HISTORY
- VER #
- DATE
- DESCRIPTION OF CHANGES
- AUTHOR
- REVIEWED  BY
- APPROVED  BY
- 2.01
- 13 APR 2023
- Drafted from E2 Schematics
- Mistral Design Team
- Deepak NS
- Krishna Prasad A
- 2.02
- 13 APR 2023
- Added M.2 screw and standoffs (9774015243R,
  MPMS 002 0005 PH , 3356)
  Changed the value of R339 resistor to 7.5K
  Chnaged the U14 part to TPD2E2U06DRL
- Mistral Design Team
- Deepak NS
- Krishna Prasad A
sheet 7
- AM62x-LOW POWER SKEVM
          BLOCK DIAGRAM
sheet 8
- BLOCK DIAGRAM_XDS110
sheet 9
- POWER BLOCK DGM
sheet 10
- POWER SEQUENCE
sheet 11
- I2C TREE
sheet 12
- GPIO MAPPING TABLE
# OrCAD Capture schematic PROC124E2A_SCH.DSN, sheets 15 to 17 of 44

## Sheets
15 11. PERIPHERAL POWER SUPPLY-2: size C; title: PERIPHERAL POWER SUPPLY-2
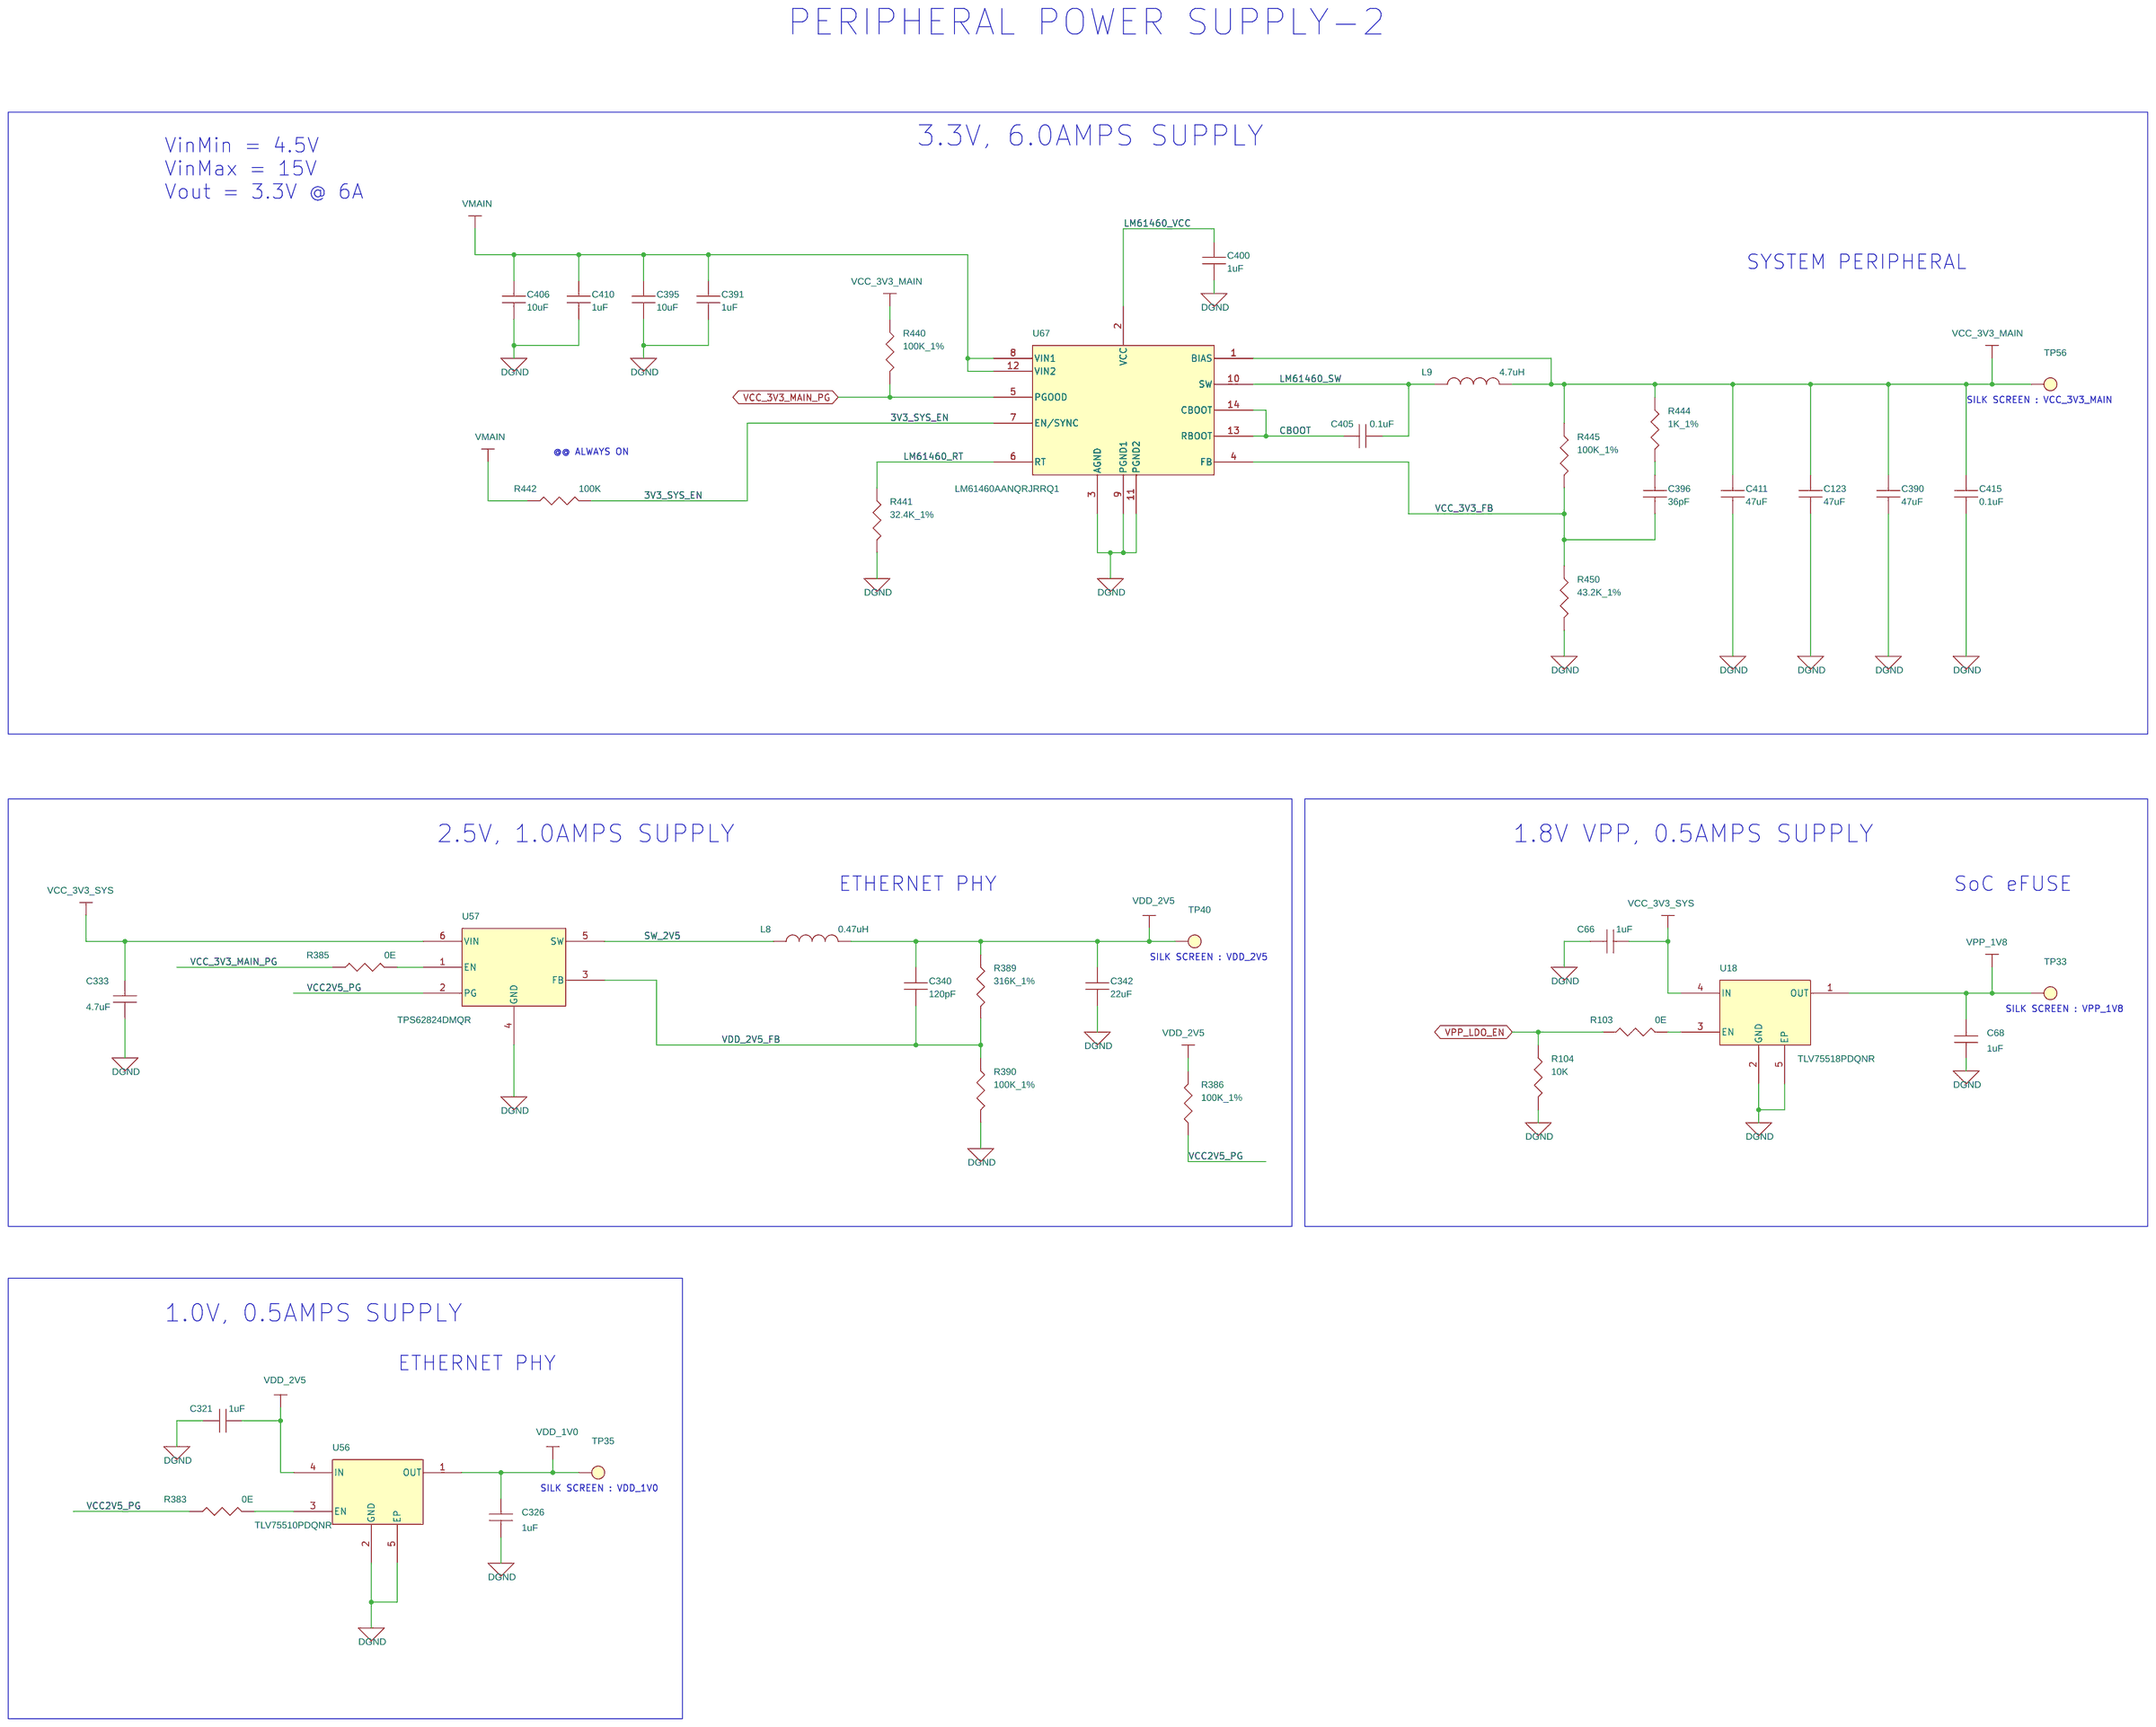
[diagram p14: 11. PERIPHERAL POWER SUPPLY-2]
16 13. CURRENT MONITORING DEVICES: size C; title: CURRENT MONITORING DEVICES
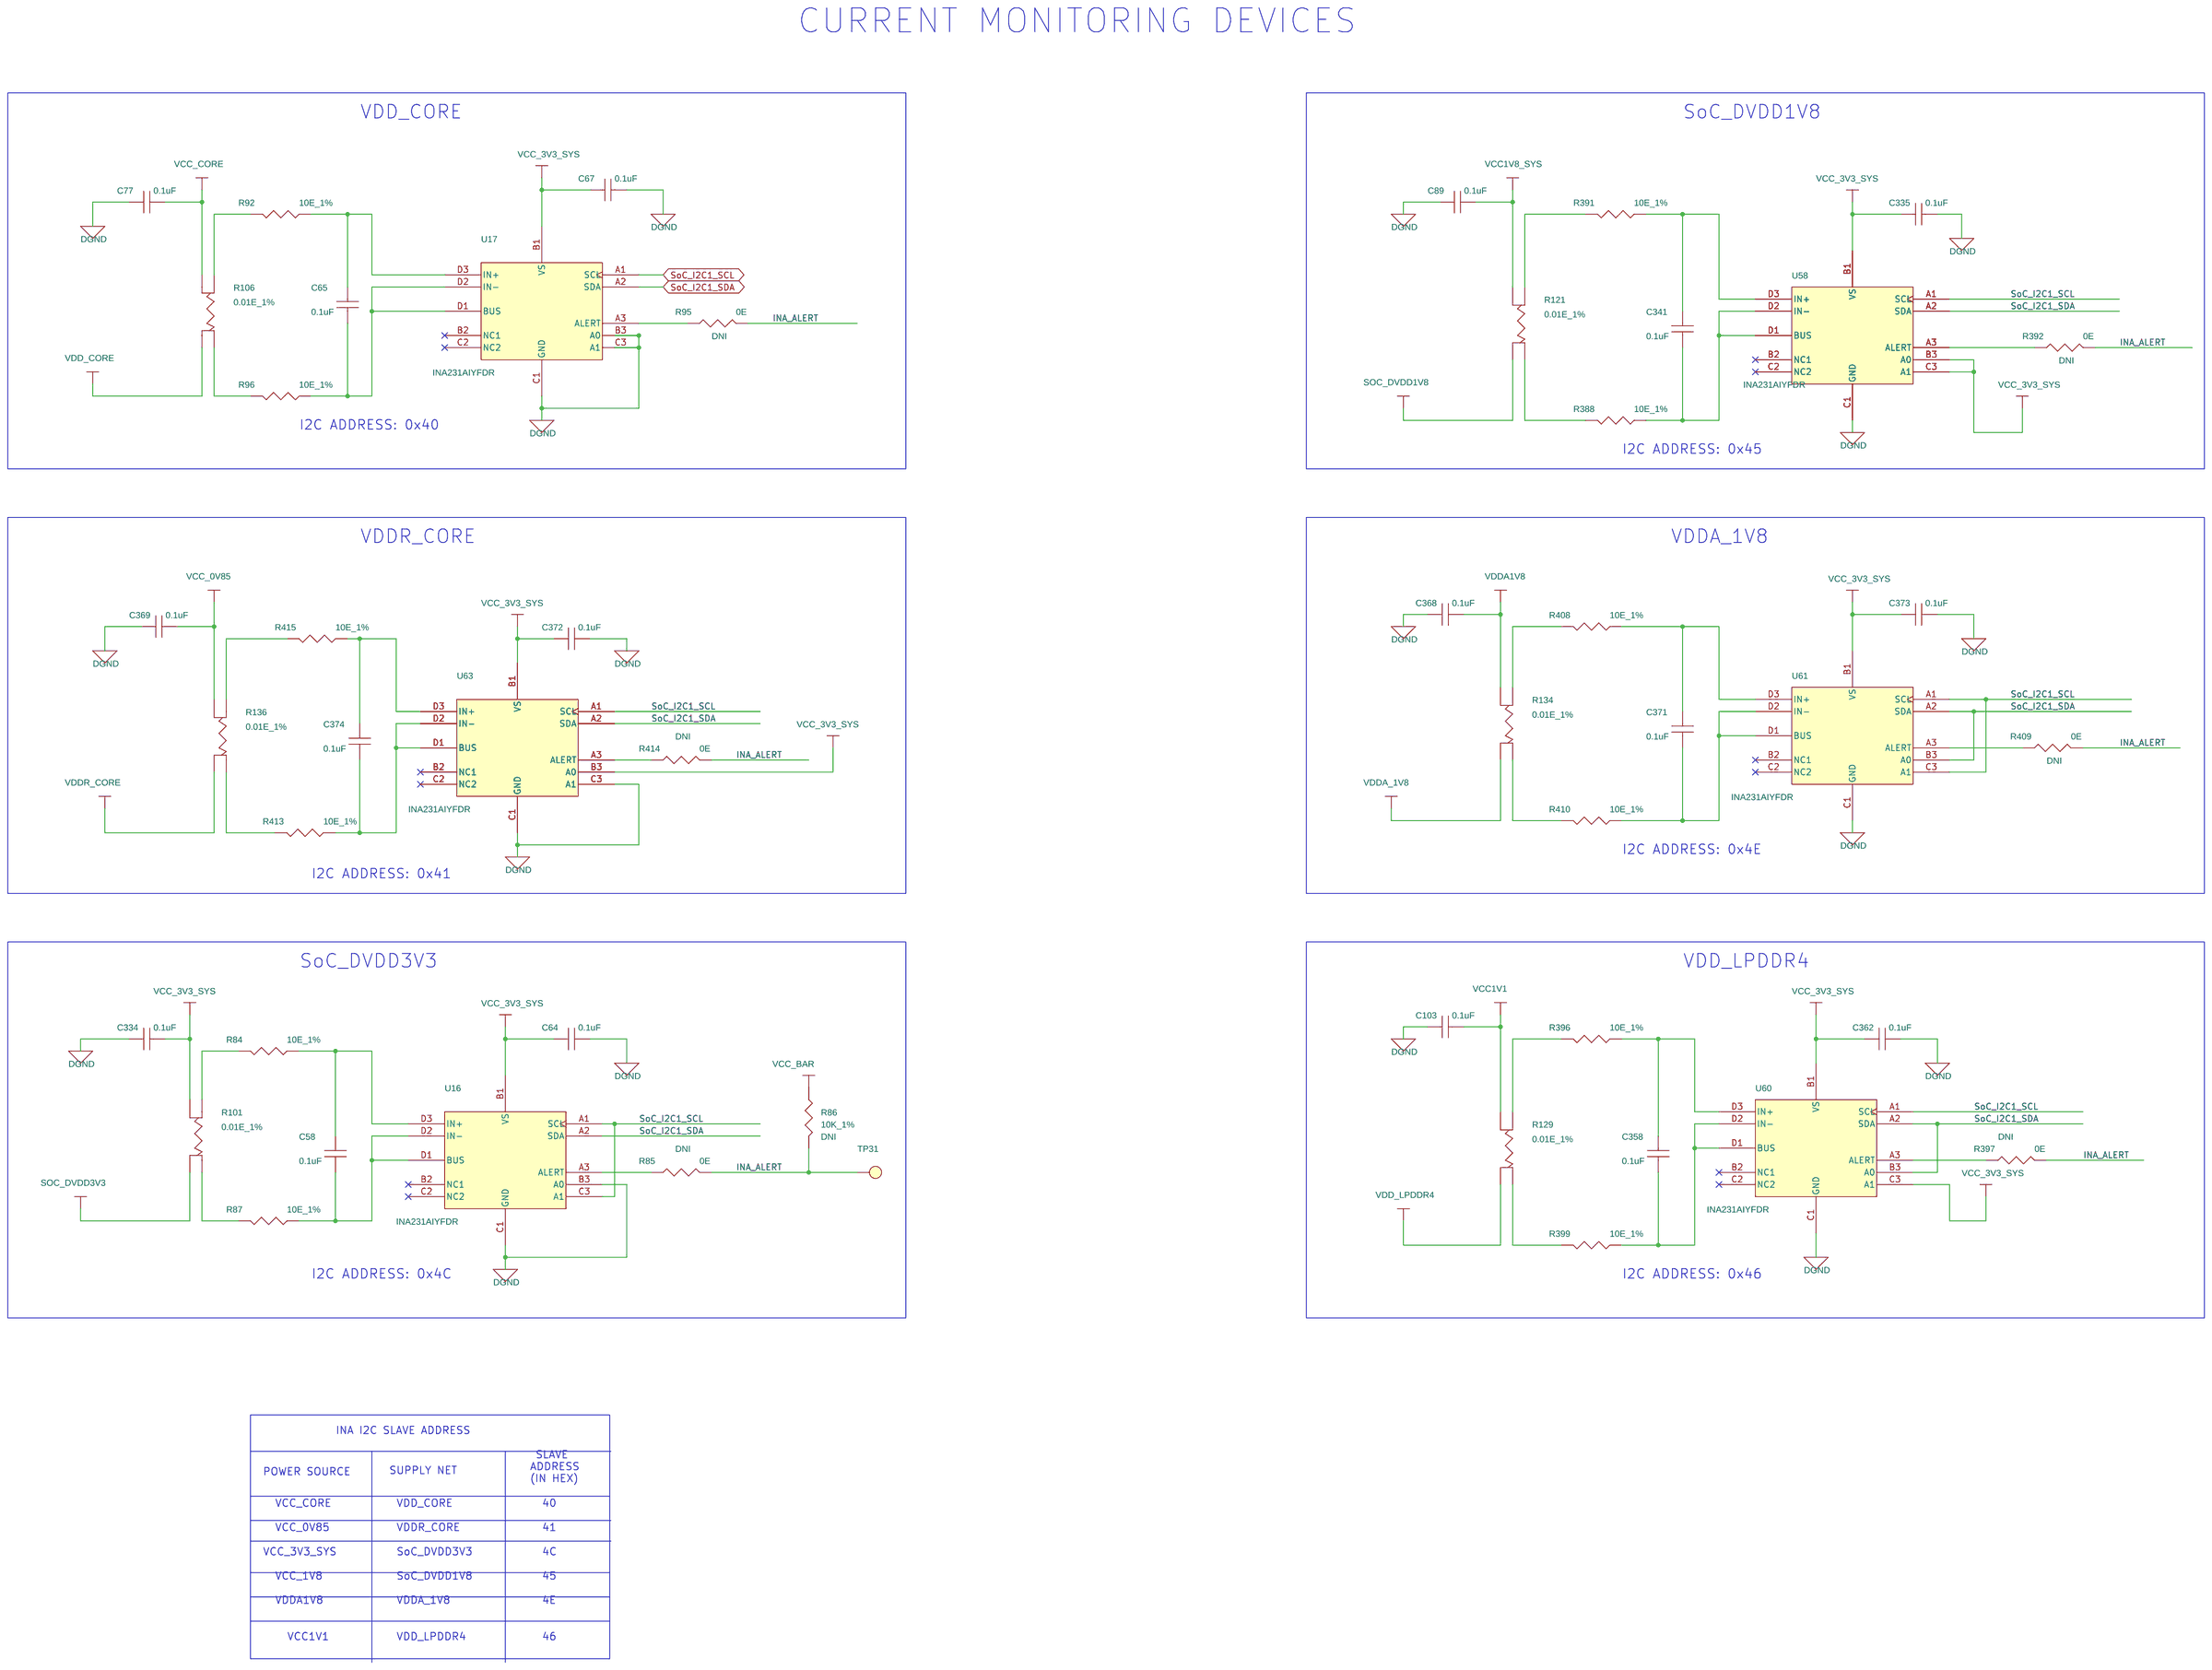
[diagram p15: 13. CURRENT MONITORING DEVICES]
17 14. SOC POWER: size C; title: SOC POWER

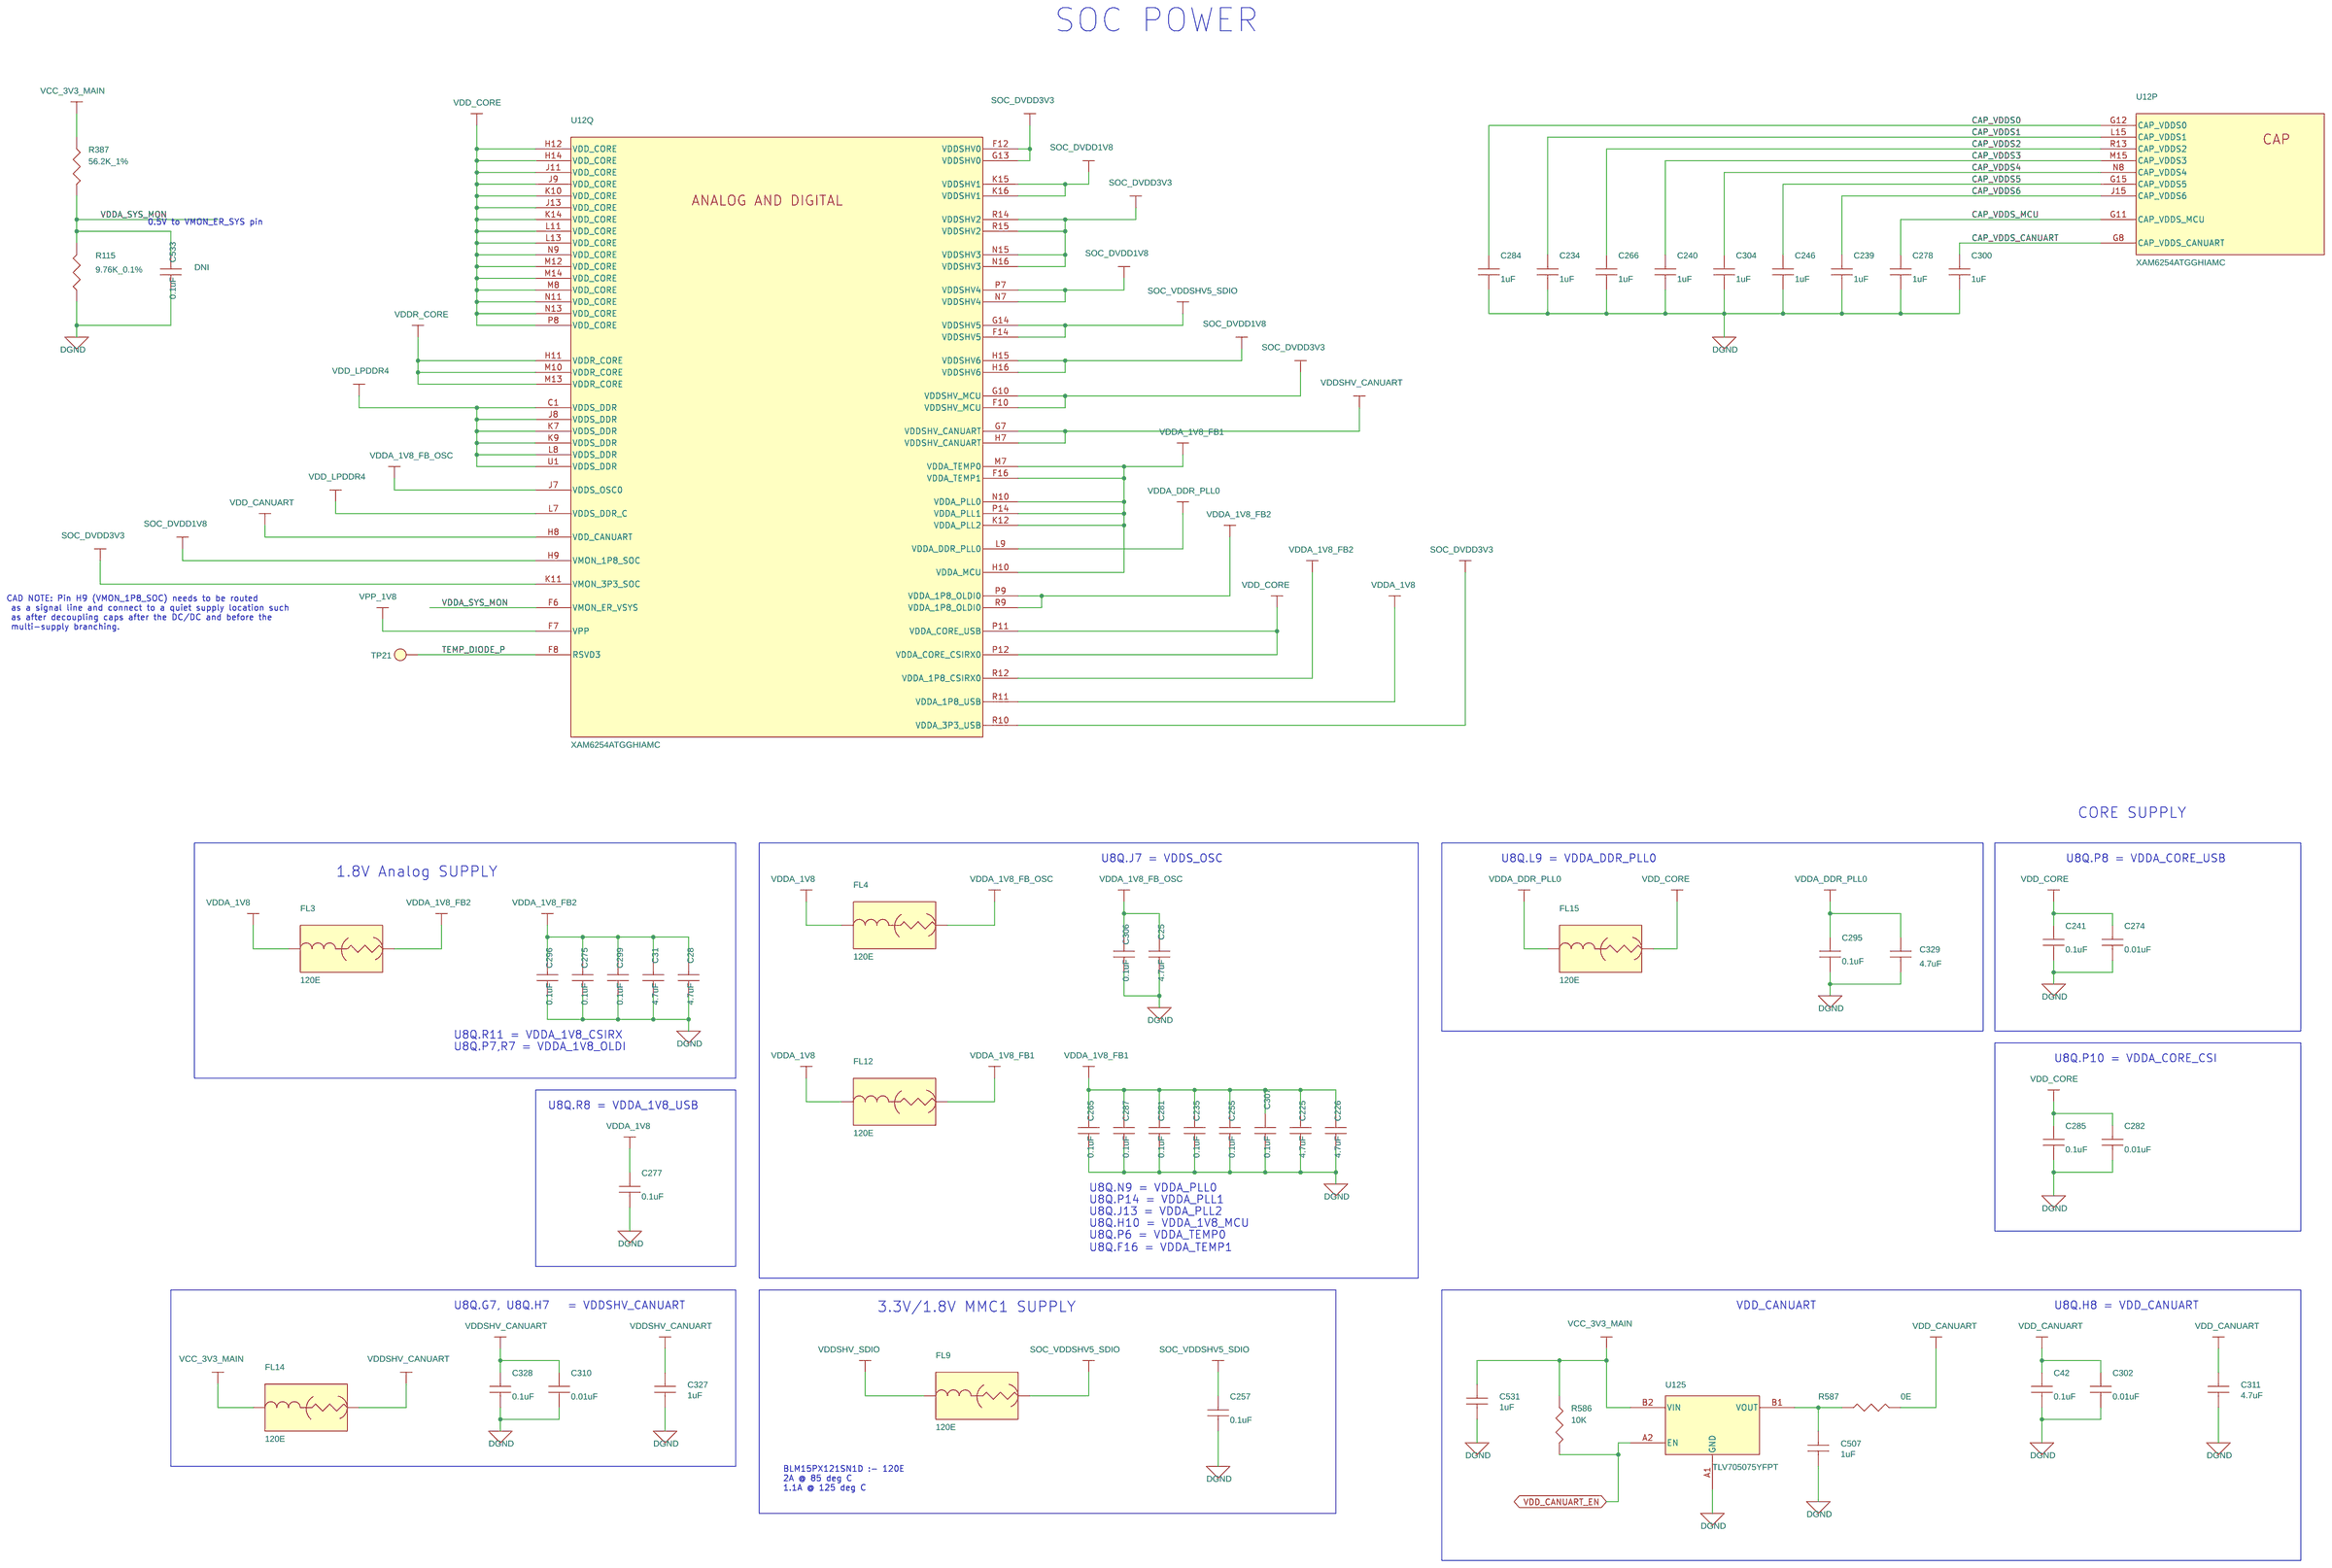
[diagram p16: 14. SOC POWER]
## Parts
sheet 11. PERIPHERAL POWER SUPPLY-2
C66  1uF  [CAP0201_0-5]
C68  1uF  [CAP0201_0-5]
C123  47uF  [CAP1210_2-75]
C321  1uF  [CAP0201_0-5]
C326  1uF  [CAP0201_0-5]
C333  4.7uF  [CAP0603_1]
C340  120pF  [CAP0201_0-5]
C342  22uF  [CAP0603_1]
C390  47uF  [CAP1210_2-75]
C391  1uF  [CAP0805_1-5]
C395  10uF  [CAP0805_1-5]
C396  36pF  [CAP0402_0-75]
C400  1uF  [CAP0201_0-5]
C405  0.1uF  [CAP0402_0-75]
C406  10uF  [CAP0805_1-5]
C410  1uF  [CAP0805_1-5]
C411  47uF  [CAP1210_2-75]
C415  0.1uF  [CAP0402_0-75]
L8  0.47uH  [IND0806_1-2]
L9  4.7uH  [IND_XAL6060_260X270_SMD_6-1]
R103  0E  [RES0201_0-5]
R104  10K  [RES0201_0-5]
R383  0E  [RES0201_0-5]
R385  0E  [RES0201_0-5]
R386  100K_1%  [RES0402_0-5]
R389  316K_1%  [RES0402_0-5]
R390  100K_1%  [RES0402_0-5]
R440  100K_1%  [RES0402_0-5]
R441  32.4K_1%  [RES0402_0-5]
R442  100K  [RES0201_0-5]
R444  1K_1%  [RES0402_0-5]
R445  100K_1%  [RES0402_0-5]
R450  43.2K_1%  [RES0402_0-5]
TP33  TP20_SMD  [TP20_SMD]
TP35  TP20_SMD  [TP20_SMD]
TP40  TP20_SMD  [TP20_SMD]
TP56  TP20_SMD  [TP20_SMD]
U18  TLV75518PDQNR  [X2SON4_TLV71318P_40X40_0-4]
U56  TLV75510PDQNR  [X2SON4_TLV71318P_40X40_0-4]
U57  TPS62824DMQR  [VSONHR6_TPS62826_60X60_1]
U67  LM61460AANQRJRRQ1  [VQFNHR14_LM61460_160X140_1]
sheet 13. CURRENT MONITORING DEVICES
C58  0.1uF  [CAP0402_0-75]
C64  0.1uF  [CAP0402_0-75]
C65  0.1uF  [CAP0402_0-75]
C67  0.1uF  [CAP0402_0-75]
C77  0.1uF  [CAP0402_0-75]
C89  0.1uF  [CAP0402_0-75]
C103  0.1uF  [CAP0402_0-75]
C334  0.1uF  [CAP0402_0-75]
C335  0.1uF  [CAP0402_0-75]
C341  0.1uF  [CAP0402_0-75]
C358  0.1uF  [CAP0402_0-75]
C362  0.1uF  [CAP0402_0-75]
C368  0.1uF  [CAP0402_0-75]
C369  0.1uF  [CAP0402_0-75]
C371  0.1uF  [CAP0402_0-75]
C372  0.1uF  [CAP0402_0-75]
C373  0.1uF  [CAP0402_0-75]
C374  0.1uF  [CAP0402_0-75]
R84  10E_1%  [RES0402_0-5]
R85  0E  [RES0201_0-5]
R86  10K_1%  [RES0201_0-5]
R87  10E_1%  [RES0402_0-5]
R92  10E_1%  [RES0402_0-5]
R95  0E  [RES0201_0-5]
R96  10E_1%  [RES0402_0-5]
R101  0.01E_1%  [RES_KRL3216T4_1206-4_0-7]
R106  0.01E_1%  [RES_KRL3216T4_1206-4_0-7]
R121  0.01E_1%  [RES_KRL3216T4_1206-4_0-7]
R129  0.01E_1%  [RES_KRL3216T4_1206-4_0-7]
R134  0.01E_1%  [RES_KRL3216T4_1206-4_0-7]
R136  0.01E_1%  [RES_KRL3216T4_1206-4_0-7]
R388  10E_1%  [RES0402_0-5]
R391  10E_1%  [RES0402_0-5]
R392  0E  [RES0201_0-5]
R396  10E_1%  [RES0402_0-5]
R397  0E  [RES0201_0-5]
R399  10E_1%  [RES0402_0-5]
R408  10E_1%  [RES0402_0-5]
R409  0E  [RES0201_0-5]
R410  10E_1%  [RES0402_0-5]
R413  10E_1%  [RES0402_0-5]
R414  0E  [RES0201_0-5]
R415  10E_1%  [RES0402_0-5]
TP31  TP20_SMD  [TP20_SMD]
U16  INA231AIYFDR  [DSBGA12_15-74_60X70_0-4]
U17  INA231AIYFDR  [DSBGA12_15-74_60X70_0-4]
U58  INA231AIYFDR  [DSBGA12_15-74_60X70_0-4]
U60  INA231AIYFDR  [DSBGA12_15-74_60X70_0-4]
U61  INA231AIYFDR  [DSBGA12_15-74_60X70_0-4]
U63  INA231AIYFDR  [DSBGA12_15-74_60X70_0-4]
sheet 14. SOC POWER
C25  4.7uF  [CAP0402_0-75]
C28  4.7uF  [CAP0402_0-75]
C31  4.7uF  [CAP0402_0-75]
C42  0.1uF  [CAP0201_0-5]
C225  4.7uF  [CAP0402_0-75]
C226  4.7uF  [CAP0402_0-75]
C234  1uF  [CAP0201_0-5]
C235  0.1uF  [CAP0201_0-5]
C239  1uF  [CAP0201_0-5]
C240  1uF  [CAP0201_0-5]
C241  0.1uF  [CAP0201_0-5]
C246  1uF  [CAP0201_0-5]
C255  0.1uF  [CAP0201_0-5]
C257  0.1uF  [CAP0201_0-5]
C265  0.1uF  [CAP0201_0-5]
C266  1uF  [CAP0201_0-5]
C274  0.01uF  [CAP0201_0-5]
C275  0.1uF  [CAP0201_0-5]
C277  0.1uF  [CAP0201_0-5]
C278  1uF  [CAP0201_0-5]
C281  0.1uF  [CAP0201_0-5]
C282  0.01uF  [CAP0201_0-5]
C284  1uF  [CAP0201_0-5]
C285  0.1uF  [CAP0201_0-5]
C287  0.1uF  [CAP0201_0-5]
C295  0.1uF  [CAP0201_0-5]
C296  0.1uF  [CAP0201_0-5]
C299  0.1uF  [CAP0201_0-5]
C300  1uF  [CAP0201_0-5]
C302  0.01uF  [CAP0201_0-5]
C304  1uF  [CAP0201_0-5]
C306  0.1uF  [CAP0201_0-5]
C307  0.1uF  [CAP0201_0-5]
C310  0.01uF  [CAP0201_0-5]
C311  4.7uF  [CAP0402_0-75]
C327  1uF  [CAP0201_0-5]
C328  0.1uF  [CAP0201_0-5]
C329  4.7uF  [CAP0402_0-75]
C507  1uF  [CAP0201_0-5]
C531  1uF  [CAP0201_0-5]
C533  0.1uF  [CAP0201_0-5]
FL3  120E  [EMIFIL_BLM15A_0402_0-6]
FL4  120E  [EMIFIL_BLM15A_0402_0-6]
FL9  120E  [EMIFIL_BLM15A_0402_0-6]
FL12  120E  [EMIFIL_BLM15A_0402_0-6]
FL14  120E  [EMIFIL_BLM15A_0402_0-6]
FL15  120E  [EMIFIL_BLM15A_0402_0-6]
R115  9.76K_0.1%  [RES0402_0-5]
R387  56.2K_1%  [RES0402_0-5]
R586  10K  [RES0201_0-5]
R587  0E  [RES0402_0-5]
TP21  TP20_SMD  [TP20_SMD]
U125  TLV705075YFPT  [DSBGA4_15-74_30X30_0-5]
sheet 31. PRU HEADER
U12  XAM6254ATGGHIAMC  [FCBGA441_31-49_680X680_2-6]  (sections A,B,C,D,E,F,G,H,I,J,K,L,M,N,O,P,Q,R)

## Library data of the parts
C66 C68 C234 C239 C240 C246 C266 C278 C284 C300 C304 C321 C326 C327 C400 = CAP: CAP CERAMIC 1uF 16V 20% X5R 0201; Chkd/date: MANIRAJA/300520; Crtd /date: ALVY/260520; Custom_Duty: 15%; Customs_HS_Code: 85322990; Distributor_name: DIGIKEY; Distributor_part_number: 490-18654-1-ND; Footprint Path: Y:\MIS_DATABASE\Library\ALTIUM_TOOL\PCB_FOOTPRINTS\Altium_Footprint_Lib.PcbLib; Height: 0.39MM; Library Path: Y:\MIS_DATABASE\Library\ALTIUM_TOOL\SCHEMATICS_PARTS\MS_DISCRETE_Library.schlib; Mfr_name: MURATA; Mfr_part_number: GRM033R61C105ME15D; Mistral Part No: 120018090038-R; Package: 0201; Part_type: CAPACITORS\CERAMIC; Project: QCS610_NANOSOM; RoHS: RoHS; Temperature: -55°C+85°C; Tolerance: 20%; Voltage: 16V; Wattage: NA; Weight: 0.33mg; Datasheet: Y:\MIS_DATABASE\DATASHEETS\CAPACITORS\GRM033R61C105ME15.PDF
C123 C390 C411 = CAP: CAP CERAMIC 47uF 16V 10% X6S 1210; Chkd/date: ALVY/010721; Crtd /date: MANIRAJA/010721; Custom_Duty: 15%; Customs_HS_Code: 85322990; Distributor_name: DIGIKEY; Distributor_part_number: 490-10531-1-ND; Footprint Path: Y:\MIS_DATABASE\Library\ALTIUM_TOOL\PCB_FOOTPRINTS\Altium_Footprint_Lib.PcbLib; Height: 2.70MM; Library Path: Y:\MIS_DATABASE\Library\ALTIUM_TOOL\SCHEMATICS_PARTS\MS_DISCRETE_Library.schlib; Mfr_name: MURATA; Mfr_part_number: GRM32EC81C476KE15L; Mistral Part No: 120021070001-R; Package: 1210; Part_type: CAPACITORS\CERAMIC; Project: TI_AM263X_CC; RoHS: RoHS; Temperature: -55°C+105°C; Tolerance: 10%; Voltage: 16V; Wattage: NA; Weight: 100mg; Datasheet: Y:\MIS_DATABASE\DATASHEETS\CAPACITORS\GRM32EC81C476KE15.PDF
C333 = CAP: CAP CERAMIC 4.7uF 35V 20% X5R 0603; Chkd/date: MANIRAJA/120520; Crtd /date: ALVY/120520; Custom_Duty: 15%; Customs_HS_Code: 85322990; Distributor_name: DIGIKEY; Distributor_part_number: 490-11995-1-ND; Footprint Path: Y:\MIS_DATABASE\Library\ALTIUM_TOOL\PCB_FOOTPRINTS\Altium_Footprint_Lib.PcbLib; Height: 1.00MM; Library Path: Y:\MIS_DATABASE\Library\ALTIUM_TOOL\SCHEMATICS_PARTS\MS_DISCRETE_Library.schlib; Mfr_name: MURATA; Mfr_part_number: GRM188R6YA475ME15D; Mistral Part No: 120020050017-R; Package: 0603; Part_type: CAPACITORS\CERAMIC; Project: SD865_NANOSOM; RoHS: RoHS; Temperature: -55°C+85°C; Tolerance: 20%; Voltage: 35V; Wattage: NA; Weight: 6.3mg; Datasheet: Y:\MIS_DATABASE\DATASHEETS\CAPACITORS\GRM188R6YA475ME15.PDF
C340 = CAP: CAP CERAMIC 120pF 25V 10% X7R 0201; Chkd/date: ALVY/260821; Crtd /date: MANIRAJA/260821; Custom_Duty: 15%; Customs_HS_Code: 85322990; Distributor_name: DIGIKEY; Distributor_part_number: 490-3173-1-ND; Footprint Path: Y:\MIS_DATABASE\Library\ALTIUM_TOOL\PCB_FOOTPRINTS\Altium_Footprint_Lib.PcbLib; Height: 0.33MM; Library Path: Y:\MIS_DATABASE\Library\ALTIUM_TOOL\SCHEMATICS_PARTS\MS_DISCRETE_Library.schlib; Mfr_name: MURATA; Mfr_part_number: GRM033R71E121KA01D; Mistral Part No: 120021080009-R; Package: 0201; Part_type: CAPACITORS\CERAMIC; Project: TI_AM62x SKEVM_BRD; RoHS: RoHS; Temperature: -55°C+125°C; Tolerance: 10%; Voltage: 25V; Wattage: NA; Weight: 0.33mg; Datasheet: Y:\MIS_DATABASE\DATASHEETS\CAPACITORS\GRM033R71E121KA01.PDF
C342 = CAP: CAP CERAMIC 22uF 10V 20% X5R 0603; Chkd/date: MANIRAJA/230118; Crtd /date: MANIRAJA/230118; Custom_Duty: 15%; Customs_HS_Code: 85322990; Distributor_name: DIGIKEY; Distributor_part_number: 490-10476-1-ND; Footprint Path: Y:\MIS_DATABASE\Library\ALTIUM_TOOL\PCB_FOOTPRINTS\Altium_Footprint_Lib.PcbLib; Height: 1.00MM; Library Path: Y:\MIS_DATABASE\Library\ALTIUM_TOOL\SCHEMATICS_PARTS\MS_DISCRETE_Library.schlib; Mfr_name: MURATA; Mfr_part_number: GRM188R61A226ME15D; Mistral Part No: 120014100009-R; Package: 0603; Part_type: CAPACITORS\CERAMIC; Project: TI_MAXIE_CPB; RoHS: RoHS; Temperature: -55°C+85°C; Tolerance: 20%; Voltage: 10V; Wattage: NA; Weight: 6.3mg; Datasheet: Y:\MIS_DATABASE\DATASHEETS\CAPACITORS\GRM188R61A226ME15.PDF
C391 C410 = CAP: CAP CERAMIC 1uF 100V 10% X7S 0805; Chkd/date: MANIRAJA/160921; Crtd /date: ALVY/150921; Custom_Duty: 15%; Customs_HS_Code: 85322990; Distributor_name: DIGIKEY; Distributor_part_number: 490-14464-1-ND; Footprint Path: Y:\MIS_DATABASE\Library\ALTIUM_TOOL\PCB_FOOTPRINTS\Altium_Footprint_Lib.PcbLib; Height: 1.45MM; Library Path: Y:\MIS_DATABASE\Library\ALTIUM_TOOL\SCHEMATICS_PARTS\MS_DISCRETE_Library.schlib; Mfr_name: MURATA; Mfr_part_number: GRM21BC72A105KE01L; Mistral Part No: 120013030002-R; Package: 0805; Part_type: CAPACITORS\CERAMIC; Project: TI_AM62x SKEVM_BRD; RoHS: RoHS; Temperature: -55°C+125°C; Tolerance: 10%; Voltage: 100V; Wattage: NA; Weight: 6.4mg; Datasheet: Y:\MIS_DATABASE\DATASHEETS\CAPACITORS\GRM21BC72A105KE01.PDF
C395 C406 = CAP: CAP CERAMIC 10uF 50V 10% X5R 0805; Chkd/date: MANIRAJA/010321; Crtd /date: ALVY/010321; Custom_Duty: 15%; Customs_HS_Code: 85322990; Distributor_name: DIGIKEY; Distributor_part_number: 490-18663-1-ND; Footprint Path: Y:\MIS_DATABASE\Library\ALTIUM_TOOL\PCB_FOOTPRINTS\Altium_Footprint_Lib.PcbLib; Height: 1.45MM; Library Path: Y:\MIS_DATABASE\Library\ALTIUM_TOOL\SCHEMATICS_PARTS\MS_DISCRETE_Library.schlib; Mfr_name: MURATA; Mfr_part_number: GRM21BR61H106KE43L; Mistral Part No: 120021030002-R; Package: 0805; Part_type: CAPACITORS\CERAMIC; Project: J7ES_SK_BRD; RoHS: RoHS; Temperature: -55°C+85°C; Tolerance: 10%; Voltage: 50V; Wattage: NA; Weight: 6.4mg; Datasheet: Y:\MIS_DATABASE\DATASHEETS\CAPACITORS\GRM21BR61H106KE43.PDF
C396 = CAP: CAP CERAMIC 36pF 50V 2% HI-Q C0G(NP0) 0402; Chkd/date: MANIRAJA/061021; Crtd /date: ALVY/051021; Custom_Duty: 15%; Customs_HS_Code: 85322990; Distributor_name: DIGIKEY; Distributor_part_number: 490-GJM1555C1H360GB01DTR-ND; Footprint Path: Y:\MIS_DATABASE\Library\ALTIUM_TOOL\PCB_FOOTPRINTS\Altium_Footprint_Lib.PcbLib; Height: 0.55MM; Library Path: Y:\MIS_DATABASE\Library\ALTIUM_TOOL\SCHEMATICS_PARTS\MS_DISCRETE_Library.schlib; Mfr_name: MURATA; Mfr_part_number: GJM1555C1H360GB01D; Mistral Part No: 120021100002-R; Package: 0402; Part_type: CAPACITORS\CERAMIC; Project: TI_AM62x SKEVM_BRD; RoHS: RoHS; Temperature: -55°C+125°C; Tolerance: 2%; Voltage: 50V; Wattage: NA; Weight: 1.5mg; Datasheet: Y:\MIS_DATABASE\DATASHEETS\CAPACITORS\GJM1555C1H360GB01.PDF
C405 C415 = CAP: CAP CERAMIC 0.1uF 50V 10% X7R 0402; Chkd/date: MANIRAJA/261020; Crtd /date: ALVY/211020; Custom_Duty: 15%; Customs_HS_Code: 85322990; Distributor_name: DIGIKEY; Distributor_part_number: 490-10700-1-ND; Footprint Path: Y:\MIS_DATABASE\Library\ALTIUM_TOOL\PCB_FOOTPRINTS\Altium_Footprint_Lib.PcbLib; Height: 0.55MM; Library Path: Y:\MIS_DATABASE\Library\ALTIUM_TOOL\SCHEMATICS_PARTS\MS_DISCRETE_Library.schlib; Mfr_name: MURATA; Mfr_part_number: GRM155R71H104KE14D; Mistral Part No: 120011100014-R; Package: 0402; Part_type: CAPACITORS\CERAMIC; Project: J7_CP; RoHS: RoHS; Temperature: -55°C+125°C; Tolerance: 10%; Voltage: 50V; Wattage: NA; Weight: 3.1mg; Datasheet: Y:\MIS_DATABASE\DATASHEETS\CAPACITORS\GRM155R71H104KE14.PDF
L8 = INDUCTOR: IND CHIP 0.47uH 4.5A 20% 0806; Chkd/date: MANIRAJA/121020; Crtd /date: ALVY/121020; Custom_Duty: 24%; Customs_HS_Code: 85437099; Distributor_name: DIGIKEY; Distributor_part_number: DFE201612E-R47M=P2-ND; Footprint Path: Y:\MIS_DATABASE\Library\ALTIUM_TOOL\PCB_FOOTPRINTS\Altium_Footprint_Lib.PcbLib; Height: 1.20MM; Library Path: Y:\MIS_DATABASE\Library\ALTIUM_TOOL\SCHEMATICS_PARTS\MS_DISCRETE_Library.schlib; Mfr_name: MURATA; Mfr_part_number: DFE201612E-R47M=P2; Mistral Part No: 130020100030-R; Package: 0806; Project: AM64X_SKEVM; RoHS: RoHS; Temperature: -40°C+125°C; Tolerance: 20%; Voltage: NA; Wattage: NA; Weight: 18.8mg; Datasheet: Y:\MIS_DATABASE\DATASHEETS\DISCRETES\INDUCTORS\DFE201612E.PDF
L9 = INDUCTOR: IND POWER 4.7uH 11A 20% SMD; Chkd/date: VASANTHA/090317; Crtd /date: MANIRAJA/090317; Custom_Duty: 15%; Customs_HS_Code: 85412900; Distributor_name: MOUSER; Distributor_part_number: 994-XAL6060-472MEB; Footprint Path: Y:\MIS_DATABASE\Library\ALTIUM_TOOL\PCB_FOOTPRINTS\Altium_Footprint_Lib.PcbLib; Height: 6.10MM; Library Path: Y:\MIS_DATABASE\Library\ALTIUM_TOOL\SCHEMATICS_PARTS\MS_DISCRETE_Library.schlib; Mfr_name: COILCRAFT; Mfr_part_number: XAL6060-472MEB; Mistral Part No: 130015090013-R; Package: SMD; Project: OCTBTS_3000; RoHS: RoHS; Temperature: -40°C+125°C; Tolerance: 20%; Voltage: NA; Wattage: NA; Weight: 1600g; Datasheet: Y:\MIS_DATABASE\DATASHEETS\DISCRETES\INDUCTORS\XAL6060-SER.PDF
R103 R383 R385 = RESISTOR: RES 0E 1/20W 5% 0201; Chkd/date: NAVEED/301214; Crtd /date: MUDDU/120710; Custom_Duty: 15%; Customs_HS_Code: 85332119; Distributor_name: DIGIKEY; Distributor_part_number: 311-0.0NCT-ND; Footprint Path: Y:\MIS_DATABASE\Library\ALTIUM_TOOL\PCB_FOOTPRINTS\Altium_Footprint_Lib.PcbLib; Height: 0.26MM; Library Path: Y:\MIS_DATABASE\Library\ALTIUM_TOOL\SCHEMATICS_PARTS\MS_DISCRETE_Library.schlib; Mfr_name: YAGEO AMERICA; Mfr_part_number: RC0201JR-070RL; Mistral Part No: 110010070067-R; Package: 0201; Part_type: RESISTORS\FIXED; Project: PB_BUGBASE; RoHS: RoHS; Temperature: -55°C+125°C; Tolerance: 5%; Voltage: NA; Wattage: 1/20W; Weight: 0.17mg; Datasheet: Y:\MIS_DATABASE\DATASHEETS\RESISTORS\RCXXXXL-SER_MAR18.PDF
R104 R586 = RESISTOR: RES 10K 1/20W 5% 0201; Chkd/date: MANIRAJA/050517; Crtd /date: MANIRAJA/050517; Custom_Duty: 15%; Customs_HS_Code: 85332119; Distributor_name: DIGIKEY; Distributor_part_number: 311-10KNCT-ND; Footprint Path: Y:\MIS_DATABASE\Library\ALTIUM_TOOL\PCB_FOOTPRINTS\Altium_Footprint_Lib.PcbLib; Height: 0.26MM; Library Path: Y:\MIS_DATABASE\Library\ALTIUM_TOOL\SCHEMATICS_PARTS\MS_DISCRETE_Library.schlib; Mfr_name: YAGEO AMERICA; Mfr_part_number: RC0201JR-0710KL; Mistral Part No: 110010070051-R; Package: 0201; Part_type: RESISTORS\FIXED; Project: GOLDEN-I LITE; RoHS: RoHS; Temperature: -55°C+125°C; Tolerance: 5%; Voltage: NA; Wattage: 1/20W; Weight: 0.17mg; Datasheet: Y:\MIS_DATABASE\DATASHEETS\RESISTORS\RCXXXXL-SER_MAR18.PDF
R386 R390 R440 R445 = RESISTOR: RES 100K 1/10W 1% 0402; Chkd/date: VASANTHA/201216; Crtd /date: MAZHAR/130306; Custom_Duty: 15%; Customs_HS_Code: 85332119; Distributor_name: DIGIKEY; Distributor_part_number: P100KLCT-ND; Footprint Path: Y:\MIS_DATABASE\Library\ALTIUM_TOOL\PCB_FOOTPRINTS\Altium_Footprint_Lib.PcbLib; Height: 0.40MM; Library Path: Y:\MIS_DATABASE\Library\ALTIUM_TOOL\SCHEMATICS_PARTS\MS_DISCRETE_Library.schlib; Mfr_name: PANASONIC-ECG; Mfr_part_number: ERJ-2RKF1003X; Mistral Part No: 110009030187-R; Package: 0402; Part_type: RESISTORS\FIXED; Project: J32; RoHS: RoHS; Temperature: -55°C+155°C; Tolerance: 1%; Voltage: NA; Wattage: 1/10W; Weight: 0.8mg; Datasheet: Y:\MIS_DATABASE\DATASHEETS\RESISTORS\PAN-ERJSER_NOV17.PDF
R389 = RESISTOR: RES 316K 1/10W 1% 0402; Chkd/date: MAZHAR/110310; Crtd /date: MUDDU/080310; Custom_Duty: 15%; Customs_HS_Code: 85332119; Distributor_name: DIGIKEY; Distributor_part_number: P316KLCT-ND; Footprint Path: Y:\MIS_DATABASE\Library\ALTIUM_TOOL\PCB_FOOTPRINTS\Altium_Footprint_Lib.PcbLib; Height: 0.40MM; Library Path: Y:\MIS_DATABASE\Library\ALTIUM_TOOL\SCHEMATICS_PARTS\MS_DISCRETE_Library.schlib; Mfr_name: PANASONIC-ECG; Mfr_part_number: ERJ-2RKF3163X; Mistral Part No: 110010030027-R; Package: 0402; Part_type: RESISTORS\FIXED; Project: VME_DSP_SUITE; RoHS: RoHS; Temperature: -55°C+155°C; Tolerance: 1%; Voltage: NA; Wattage: 1/10W; Weight: 0.8mg; Datasheet: Y:\MIS_DATABASE\DATASHEETS\RESISTORS\PAN-ERJSER_NOV17.PDF
R441 = RESISTOR: RES 32.4K 1/16W 1% 0402; Chkd/date: MANIRAJA/080420; Crtd /date: ALVY/080420; Custom_Duty: 15%; Customs_HS_Code: 85332119; Distributor_name: DIGIKEY; Distributor_part_number: 541-32.4KLCT-ND; Footprint Path: Y:\MIS_DATABASE\Library\ALTIUM_TOOL\PCB_FOOTPRINTS\Altium_Footprint_Lib.PcbLib; Height: 0.40MM; Library Path: Y:\MIS_DATABASE\Library\ALTIUM_TOOL\SCHEMATICS_PARTS\MS_DISCRETE_Library.schlib; Mfr_name: VISHAY; Mfr_part_number: CRCW040232K4FKED; Mistral Part No: 110020040003-R; Package: 0402; Part_type: RESISTORS\FIXED; Project: HSDTRS_FEE_BRD; RoHS: RoHS; Temperature: -55°C+155°C; Tolerance: 1%; Voltage: NA; Wattage: 1/16W; Weight: 0.65mg; Datasheet: Y:\MIS_DATABASE\DATASHEETS\RESISTORS\CRCW0603.PDF
R442 = RESISTOR: RES 100K 1/20W 5% 0201; Chkd/date: PRAVEEN/080922; Crtd /date: TAMILARASU/080922; Custom_Duty: 15%; Customs_HS_Code: 85332119; Distributor_name: DIGIKEY; Distributor_part_number: P123223CT-ND; Footprint Path: Y:\MIS_DATABASE\Library\ALTIUM_TOOL\PCB_FOOTPRINTS\Altium_Footprint_Lib.PcbLib; Height: 0.26MM; Library Path: Y:\MIS_DATABASE\Library\ALTIUM_TOOL\SCHEMATICS_PARTS\MS_DISCRETE_Library.schlib; Mfr_name: PANASONIC-ECG; Mfr_part_number: ERJ-1GNJ104C; Mistral Part No: 110022090005-R; Package: 0201; Part_type: RESISTORS\FIXED; Project: SK AM62Q LP EVM BRD; RoHS: RoHS; Temperature: -55°C+125°C; Tolerance: 5%; Voltage: NA; Wattage: 1/20W; Weight: 0.15mg; Datasheet: Y:\MIS_DATABASE\DATASHEETS\RESISTORS\PAN-ERJSER_NOV17.PDF
R444 = RESISTOR: RES 1K 1/10W 1% 0402; Chkd/date: VASANTHA/281216; Crtd /date: MAZHAR/150506; Custom_Duty: 15%; Customs_HS_Code: 85332119; Distributor_name: DIGIKEY; Distributor_part_number: P1.00KLCT-ND; Footprint Path: Y:\MIS_DATABASE\Library\ALTIUM_TOOL\PCB_FOOTPRINTS\Altium_Footprint_Lib.PcbLib; Height: 0.40MM; Library Path: Y:\MIS_DATABASE\Library\ALTIUM_TOOL\SCHEMATICS_PARTS\MS_DISCRETE_Library.schlib; Mfr_name: PANASONIC-ECG; Mfr_part_number: ERJ-2RKF1001X; Mistral Part No: 110009030411-R; Package: 0402; Part_type: RESISTORS\FIXED; Project: VOCERA; RoHS: RoHS; Temperature: -55°C+155°C; Tolerance: 1%; Voltage: NA; Wattage: 1/10W; Weight: 0.8mg; Datasheet: Y:\MIS_DATABASE\DATASHEETS\RESISTORS\PAN-ERJSER_NOV17.PDF
R450 = RESISTOR: RES 43.2K 1/16W 1% 0402; Chkd/date: MANIRAJA/250821; Crtd /date: ALVY/250821; Custom_Duty: 15%; Customs_HS_Code: 85332119; Distributor_name: DIGIKEY; Distributor_part_number: 541-43.2KLCT-ND; Footprint Path: Y:\MIS_DATABASE\Library\ALTIUM_TOOL\PCB_FOOTPRINTS\Altium_Footprint_Lib.PcbLib; Height: 0.40MM; Library Path: Y:\MIS_DATABASE\Library\ALTIUM_TOOL\SCHEMATICS_PARTS\MS_DISCRETE_Library.schlib; Mfr_name: VISHAY; Mfr_part_number: CRCW040243K2FKED; Mistral Part No: 110021080019-R; Package: 0402; Part_type: RESISTORS\FIXED; Project: TI_AM62x SKEVM_BRD; RoHS: RoHS; Temperature: -55°C+155°C; Tolerance: 1%; Voltage: NA; Wattage: 1/16W; Weight: 0.65mg; Datasheet: Y:\MIS_DATABASE\DATASHEETS\RESISTORS\CRCW0603.PDF
TP33 TP35 TP40 TP56 = TESTPOINT: TESTPOINT CIR 20 SMD; Chkd/date: SHREESHAIL/171006; Crtd /date: MAZHAR/171006; Custom_Duty: NA; Customs_HS_Code: NA; Distributor_name: NA; Distributor_part_number: NA; Footprint Path: Y:\MIS_DATABASE\Library\ALTIUM_TOOL\PCB_FOOTPRINTS\Altium_Footprint_Lib.PcbLib; Height: NA; Library Path: Y:\MIS_DATABASE\Library\ALTIUM_TOOL\SCHEMATICS_PARTS\MS_DISCRETE_Library.schlib; MECHANICAL 3D STEP FILE: NA; Manufacturer: LOCAL; Mfr_name: LOCAL; Mistral Part No: NA; Package: SMD; Project: BT MODULE_CSRBC04; RoHS: NA; Temperature: NA; Tolerance: NA; Voltage: NA; Wattage: NA; Weight: NA; Datasheet: NA
U18 = TLV71318PDQNR_X2SON4: IC 500mA LOW IQ LDO REGULATOR X2SON-4; Chkd/date: MANIRAJA/170620; Crtd /date: ALVY/160620; Custom_Duty: 15%; Customs_HS_Code: 85423100; Distributor_name: DIGIKEY; Distributor_part_number: 296-51790-1-ND; Footprint Path: Y:\MIS_DATABASE\Library\ALTIUM_TOOL\PCB_FOOTPRINTS\Altium_Footprint_Lib.PcbLib; Height: 0.40MM; Library Path: Y:\MIS_DATABASE\Library\ALTIUM_TOOL\SCHEMATICS_PARTS\MS_MISCPOWER_Library.schlib; Mfr_name: TEXAS INSTRUMENTS; Mistral Part No: 142020060013-R; Package: X2SON-4; Part_type: ICS\POWER\VOLTAGE REGULATOR; Project: AM64x-GP_EVM BRD; RoHS: RoHS; Temperature: -40°C+125°C; Tolerance: NA; Voltage: NA; Wattage: NA; Weight: 1.1mg; Datasheet: Y:\MIS_DATABASE\DATASHEETS\ICS\POWER\TLV755P.PDF
U56 = TLV71318PDQNR_X2SON4: IC 500mA 1V LOW IQ LDO REGULATOR X2SON-4; Chkd/date: MANIRAJA/240821; Crtd /date: ALVY/240821; Custom_Duty: 15%; Customs_HS_Code: 85423100; Distributor_name: DIGIKEY; Distributor_part_number: 296-51782-1-ND; Footprint Path: Y:\MIS_DATABASE\Library\ALTIUM_TOOL\PCB_FOOTPRINTS\Altium_Footprint_Lib.PcbLib; Height: 0.40MM; Library Path: Y:\MIS_DATABASE\Library\ALTIUM_TOOL\SCHEMATICS_PARTS\MS_MISCPOWER_Library.schlib; Mfr_name: TEXAS INSTRUMENTS; Mistral Part No: 142021080018-R; Package: X2SON-4; Part_type: ICS\POWER\VOLTAGE REGULATOR; Project: TI_AM62x SKEVM_BRD; RoHS: RoHS; Temperature: -40°C+125°C; Tolerance: NA; Voltage: NA; Wattage: NA; Weight: 1.1mg; Datasheet: Y:\MIS_DATABASE\DATASHEETS\ICS\POWER\TLV755P.PDF
U57 = TPS62827DMQR_VSONHR6: IC 1A ADJ STEP-DOWN CONVERTER WITH 1% OUTPUT ACCURACY VSON-HR6; Chkd/date: ALVY/071021; Crtd /date: MANIRAJA/071021; Custom_Duty: 15%; Customs_HS_Code: 85423100; Distributor_name: NA; Distributor_part_number: NA; Footprint Path: Y:\MIS_DATABASE\Library\ALTIUM_TOOL\PCB_FOOTPRINTS\Altium_Footprint_Lib.PcbLib; Height: 1.00MM; Library Path: Y:\MIS_DATABASE\Library\ALTIUM_TOOL\SCHEMATICS_PARTS\MS_MISCPOWER_Library.schlib; Mfr_name: TEXAS INSTRUMENTS; Mistral Part No: 142021100006-R; Package: VSON-HR6; Part_type: ICS\POWER\DC-DC CONVERTER; Project: TI_AM62x SKEVM_BRD; RoHS: RoHS; Temperature: -40°C+125°C; Tolerance: NA; Voltage: NA; Wattage: NA; Weight: NA; Datasheet: Y:\MIS_DATABASE\DATASHEETS\ICS\POWER\TPS6282XX-DEC2020.PDF
U67 = LM61460_VQFNHR14: IC 6A ADJ AUTO LOW EMI SYNCHRONOUS STEP DOWN DC-DC CONVERTER VQFN-HR14; Chkd/date: ALVY/040221; Crtd /date: MANIRAJA/030221; Custom_Duty: 15%; Customs_HS_Code: 85423100; Distributor_name: DIGIKEY; Distributor_part_number: 296-LM61460AANQRJRRQ1TR-ND; Footprint Path: Y:\MIS_DATABASE\Library\ALTIUM_TOOL\PCB_FOOTPRINTS\Altium_Footprint_Lib.PcbLib; Height: 1.00MM; Library Path: Y:\MIS_DATABASE\Library\ALTIUM_TOOL\SCHEMATICS_PARTS\MS_MISCPOWER_Library.schlib; Mfr_name: TEXAS INSTRUMENTS; Mistral Part No: 142021020006-R; Package: VQFN-HR14; Part_type: ICS\POWER\DC-DC CONVERTER; Project: J7ES_SK_BRD; RoHS: RoHS; Temperature: -40°C+150°C; Tolerance: NA; Voltage: NA; Wattage: NA; Weight: NA; Datasheet: Y:\MIS_DATABASE\DATASHEETS\ICS\POWER\LM61460-Q1.PDF
C58 C64 C65 C67 C77 C89 C103 C334 C335 C341 C358 C362 C368 C369 C371-C374 = CAP: CAP CERAMIC 0.1uF 50V 10% X7R 0402; Alt_Mfr_name: YAGEO AMERICA; Alt_Mfr_part_number: CC0402KRX5R8BB104; Chkd/date: MANIRAJA/261020; Crtd /date: ALVY/211020; Custom_Duty: 15%; Customs_HS_Code: 85322990; Distributor_name: DIGIKEY; Distributor_part_number: 490-10700-1-ND; Footprint Path: Y:\MIS_DATABASE\Library\ALTIUM_TOOL\PCB_FOOTPRINTS\Altium_Footprint_Lib.PcbLib; Height: 0.55MM; Library Path: Y:\MIS_DATABASE\Library\ALTIUM_TOOL\SCHEMATICS_PARTS\MS_DISCRETE_Library.schlib; Mfr_name: MURATA; Mfr_part_number: GRM155R71H104KE14D; Mistral Part No: 120011100014-R; Package: 0402; Part_type: CAPACITORS\CERAMIC; Project: J7_CP; RoHS: RoHS; Temperature: -55°C+125°C; Tolerance: 10%; Voltage: 50V; Wattage: NA; Weight: 3.1mg; Datasheet: Y:\MIS_DATABASE\DATASHEETS\CAPACITORS\GRM155R71H104KE14.PDF
R84 R87 R92 R96 R388 R391 R396 R399 R408 R410 R413 R415 = RESISTOR: RES 10E 1/16W 1% 0402; Chkd/date: MANIRAJA/070218; Crtd /date: ALVY/070218; Custom_Duty: 15%; Customs_HS_Code: 85332119; Distributor_name: DIGIKEY; Distributor_part_number: 311-10.0LRCT-ND; Footprint Path: Y:\MIS_DATABASE\Library\ALTIUM_TOOL\PCB_FOOTPRINTS\Altium_Footprint_Lib.PcbLib; Height: 0.40MM; Library Path: Y:\MIS_DATABASE\Library\ALTIUM_TOOL\SCHEMATICS_PARTS\MS_DISCRETE_Library.schlib; Mfr_name: YAGEO AMERICA; Mfr_part_number: RC0402FR-0710RL; Mistral Part No: 110018020004-R; Package: 0402; Part_type: RESISTORS\FIXED; Project: TI_MAXIE_CPB; RoHS: RoHS; Temperature: -55°C+155°C; Tolerance: 1%; Voltage: NA; Wattage: 1/16W; Weight: 0.65mg; Datasheet: Y:\MIS_DATABASE\DATASHEETS\RESISTORS\RCXXXXL-SER_MAR18.PDF
R85 R95 R392 R397 R409 R414 = RESISTOR: RES 0E 1/20W 5% 0201; Assembly_Instruction: DNI; Chkd/date: NAVEED/301214; Crtd /date: MUDDU/120710; Custom_Duty: 15%; Customs_HS_Code: 85332119; Distributor_name: DIGIKEY; Distributor_part_number: 311-0.0NCT-ND; Footprint Path: Y:\MIS_DATABASE\Library\ALTIUM_TOOL\PCB_FOOTPRINTS\Altium_Footprint_Lib.PcbLib; Height: 0.26MM; Library Path: Y:\MIS_DATABASE\Library\ALTIUM_TOOL\SCHEMATICS_PARTS\MS_DISCRETE_Library.schlib; Mfr_name: YAGEO AMERICA; Mfr_part_number: RC0201JR-070RL; Mistral Part No: 110010070067-R; Package: 0201; Part_type: RESISTORS\FIXED; Project: PB_BUGBASE; RoHS: RoHS; Temperature: -55°C+125°C; Tolerance: 5%; Voltage: NA; Wattage: 1/20W; Weight: 0.17mg; Datasheet: Y:\MIS_DATABASE\DATASHEETS\RESISTORS\RCXXXXL-SER_MAR18.PDF
R86 = RESISTOR: RES 10K 1/20W 1% 0201; Assembly_Instruction: DNI; Chkd/date: VASANTHA/270117; Crtd /date: MANIRAJA/270117; Custom_Duty: 15%; Customs_HS_Code: 85332119; Distributor_name: DIGIKEY; Distributor_part_number: 311-10.0KMCT-ND; Footprint Path: Y:\MIS_DATABASE\Library\ALTIUM_TOOL\PCB_FOOTPRINTS\Altium_Footprint_Lib.PcbLib; Height: 0.26MM; Library Path: Y:\MIS_DATABASE\Library\ALTIUM_TOOL\SCHEMATICS_PARTS\MS_DISCRETE_Library.schlib; Mfr_name: YAGEO AMERICA; Mfr_part_number: RC0201FR-0710KL; Mistral Part No: 110011040018-R; Package: 0201; Part_type: RESISTORS\FIXED; Project: GOLDEN-I LITE; RoHS: RoHS; Temperature: -55°C+125°C; Tolerance: 1%; Voltage: NA; Wattage: 1/20W; Weight: 0.17mg; Datasheet: Y:\MIS_DATABASE\DATASHEETS\RESISTORS\RCXXXXL-SER_MAR18.PDF
R101 R106 R121 R129 R134 R136 = RESISTOR-4TERM: RES 0.01E 1W 1% 1206-4; Chkd/date: MANIRAJA/060318; Crtd /date: MANIRAJA/060318; Custom_Duty: 15%; Customs_HS_Code: 85332119; Distributor_name: DIGIKEY; Distributor_part_number: 408-1974-1-ND; Footprint Path: Y:\MIS_DATABASE\Library\ALTIUM_TOOL\PCB_FOOTPRINTS\Altium_Footprint_Lib.PcbLib; Height: 0.70MM; Library Path: Y:\MIS_DATABASE\Library\ALTIUM_TOOL\SCHEMATICS_PARTS\MS_DISCRETE_Library.schlib; Manufacturer: SUSUMU; Mfr_name: SUSUMU; Mfr_part_number: KRL3216T4A-M-R010-F-T1; Mistral Part No: 110018030003-R; Package: 1206-4; Part_type: RESISTORS\FIXED; Project: GRACO SMART MODULE; RoHS: RoHS; Temperature: -55°C+155°C; Tolerance: 1%; Voltage: NA; Wattage: 1W; Weight: 16.2mg; Datasheet: Y:\MIS_DATABASE\DATASHEETS\RESISTORS\KRL-SERIES.PDF
TP21 TP31 = TESTPOINT: TESTPOINT CIR 20 SMD; Chkd/date: SHREESHAIL/171006; Crtd /date: MAZHAR/171006; Custom_Duty: NA; Customs_HS_Code: NA; Distributor_name: NA; Distributor_part_number: NA; Footprint Path: Y:\MIS_DATABASE\Library\ALTIUM_TOOL\PCB_FOOTPRINTS\Altium_Footprint_Lib.PcbLib; Height: NA; Library Path: Y:\MIS_DATABASE\Library\ALTIUM_TOOL\SCHEMATICS_PARTS\MS_DISCRETE_Library.schlib; MECHANICAL 3D STEP FILE: NA; Mfr_name: LOCAL; Mistral Part No: NA; Package: SMD; Project: BT MODULE_CSRBC04; RoHS: NA; Temperature: NA; Tolerance: NA; Voltage: NA; Wattage: NA; Weight: NA; Datasheet: NA
U16 U17 U58 U60 U61 U63 = INA231_DSBGA12: IC HIGH OR LOW SIDE MEASUREMENT BI-DIR CURRENT AND POWER MONITOR WITH 1.8V I2C INTERFACE DSBGA12; Chkd/date: MANIRAJA/250821; Crtd /date: ALVY/250821; Custom_Duty: 15%; Customs_HS_Code: 85423100; Distributor_name: DIGIKEY; Distributor_part_number: 296-49645-1-ND; Footprint Path: Y:\MIS_DATABASE\Library\ALTIUM_TOOL\PCB_FOOTPRINTS\Altium_Footprint_Lib.PcbLib; Height: 0.40MM; Library Path: Y:\MIS_DATABASE\Library\ALTIUM_TOOL\SCHEMATICS_PARTS\MS_MISCPOWER_Library.schlib; Mfr_name: TEXAS INSTRUMENTS; Mistral Part No: 142021080022-R; Package: DSBGA12; Part_type: ICS\POWER\MANAGEMENT; Project: TI_AM62x SVB_BRD; RoHS: RoHS; Temperature: -40°C+125°C; Tolerance: NA; Voltage: NA; Wattage: NA; Weight: 200mg; Datasheet: Y:\MIS_DATABASE\DATASHEETS\ICS\POWER\INA231XXX.PDF
C25 C28 C31 C225 C226 C311 C329 = CAP: CAP CERAMIC 4.7uF 10V 20% X5R 0402; Chkd/date: MANIRAJA/110718; Crtd /date: ALVY/110718; Custom_Duty: 15%; Customs_HS_Code: 85322990; Distributor_name: DIGIKEY; Distributor_part_number: 490-14306-1-ND; Footprint Path: Y:\MIS_DATABASE\Library\ALTIUM_TOOL\PCB_FOOTPRINTS\Altium_Footprint_Lib.PcbLib; Height: 0.65MM; Library Path: Y:\MIS_DATABASE\Library\ALTIUM_TOOL\SCHEMATICS_PARTS\MS_DISCRETE_Library.schlib; Mfr_name: MURATA; Mfr_part_number: GRM155R61A475MEAAD; Mistral Part No: 120012060002-R; Package: 0402; Part_type: CAPACITORS\CERAMIC; Project: TI_J7SVB_PCIE_ADD-ON-CARD; RoHS: RoHS; Temperature: -55°C+85°C; Tolerance: 20%; Voltage: 10V; Wattage: NA; Weight: 14mg; Datasheet: Y:\MIS_DATABASE\DATASHEETS\CAPACITORS\GRM155R61A475MEAAD.PDF
C42 C235 C241 C255 C257 C265 C275 C277 C281 C285 C287 C295 C296 C299 C306 C307 C328 = CAP: CAP CERAMIC 0.1uF 16V 10% X5R 0201; Chkd/date: MANIRAJA/230118; Crtd /date: MANIRAJA/230118; Custom_Duty: 15%; Customs_HS_Code: 85322990; Distributor_name: DIGIKEY; Distributor_part_number: 490-14305-1-ND; Footprint Path: Y:\MIS_DATABASE\Library\ALTIUM_TOOL\PCB_FOOTPRINTS\Altium_Footprint_Lib.PcbLib; Height: 0.33MM; Library Path: Y:\MIS_DATABASE\Library\ALTIUM_TOOL\SCHEMATICS_PARTS\MS_DISCRETE_Library.schlib; Mfr_name: MURATA; Mfr_part_number: GRM033R61C104KE14D; Mistral Part No: 120009030072-R; Package: 0201; Part_type: CAPACITORS\CERAMIC; Project: TI_MAXIE_CPB; RoHS: RoHS; Temperature: -55°C+85°C; Tolerance: 10%; Voltage: 16V; Wattage: NA; Weight: 0.33mg; Datasheet: Y:\MIS_DATABASE\DATASHEETS\CAPACITORS\GRM033R61C104KE14.PDF
C274 C282 C302 C310 = CAP: CAP CERAMIC 0.01uF 25V 10% X5R 0201; Chkd/date: MANIRAJA/230118; Crtd /date: MANIRAJA/230118; Custom_Duty: 15%; Customs_HS_Code: 85322990; Distributor_name: DIGIKEY; Distributor_part_number: GRM033R61E103KA12J-ND; Footprint Path: Y:\MIS_DATABASE\Library\ALTIUM_TOOL\PCB_FOOTPRINTS\Altium_Footprint_Lib.PcbLib; Height: 0.33MM; Library Path: Y:\MIS_DATABASE\Library\ALTIUM_TOOL\SCHEMATICS_PARTS\MS_DISCRETE_Library.schlib; Mfr_name: MURATA; Mfr_part_number: GRM033R61E103KA12J; Mistral Part No: 120018010007-R; Package: 0201; Part_type: CAPACITORS\CERAMIC; Project: TI_MAXIE_CPB; RoHS: RoHS; Temperature: -55°C+85°C; Tolerance: 10%; Voltage: 25V; Wattage: NA; Weight: 0.33mg; Datasheet: Y:\MIS_DATABASE\DATASHEETS\CAPACITORS\GRM033R61E103KA12.PDF
C507 C531 = CAP: CAP CERAMIC 1uF 10V 20% X5R 0201; Chkd/date: NAVEED/070415; Crtd /date: VASANTHA/230314; Custom_Duty: 15%; Customs_HS_Code: 85322990; Distributor_name: DIGIKEY; Distributor_part_number: 1276-1324-1-ND; Footprint Path: Y:\MIS_DATABASE\Library\ALTIUM_TOOL\PCB_FOOTPRINTS\Altium_Footprint_Lib.PcbLib; Height: 0.35MM; Library Path: Y:\MIS_DATABASE\Library\ALTIUM_TOOL\SCHEMATICS_PARTS\MS_DISCRETE_Library.schlib; Mfr_name: SAMSUNG; Mfr_part_number: CL03A105MP3NSNC; Mistral Part No: 120015030003-R; Package: 0201; Part_type: CAPACITORS\CERAMIC; Project: DUET BOARDS; RoHS: RoHS; Temperature: -55°C+85°C; Tolerance: 20%; Voltage: 10V; Wattage: NA; Weight: 0.17mg; Datasheet: Y:\MIS_DATABASE\DATASHEETS\CAPACITORS\CL03A105MP3NSNC.PDF
C533 = CAP: CAP CERAMIC 0.1uF 16V 10% X5R 0201; Assembly_Instruction: DNI; Chkd/date: MANIRAJA/230118; Crtd /date: MANIRAJA/230118; Custom_Duty: 15%; Customs_HS_Code: 85322990; Distributor_name: DIGIKEY; Distributor_part_number: 490-14305-1-ND; Footprint Path: Y:\MIS_DATABASE\Library\ALTIUM_TOOL\PCB_FOOTPRINTS\Altium_Footprint_Lib.PcbLib; Height: 0.33MM; Library Path: Y:\MIS_DATABASE\Library\ALTIUM_TOOL\SCHEMATICS_PARTS\MS_DISCRETE_Library.schlib; Mfr_name: MURATA; Mfr_part_number: GRM033R61C104KE14D; Mistral Part No: 120009030072-R; Package: 0201; Part_type: CAPACITORS\CERAMIC; Project: TI_MAXIE_CPB; RoHS: RoHS; Temperature: -55°C+85°C; Tolerance: 10%; Voltage: 16V; Wattage: NA; Weight: 0.33mg; Datasheet: Y:\MIS_DATABASE\DATASHEETS\CAPACITORS\GRM033R61C104KE14.PDF
FL3 FL4 FL9 FL12 FL14 FL15 = EMIFILTER_IND: IND FERRITE BEAD CHIP 120E 2A 0402; Chkd/date: NAVEED/241114; Crtd /date: USMAN/170613; Custom_Duty: 24%; Customs_HS_Code: 85369090; Distributor_name: DIGIKEY; Distributor_part_number: 490-9656-1-ND; Footprint Path: Y:\MIS_DATABASE\Library\ALTIUM_TOOL\PCB_FOOTPRINTS\Altium_Footprint_Lib.PcbLib; Height: 0.55MM; Library Path: Y:\MIS_DATABASE\Library\ALTIUM_TOOL\SCHEMATICS_PARTS\MS_FILTER_Library.schlib; Mfr_name: MURATA; Mfr_part_number: BLM15PX121SN1D; Mistral Part No: 130013060022-R; Package: 0402; Part_type: INDUCTOR; Project: GEN_3-8; RoHS: RoHS; Temperature: -55°C+125°C; Tolerance: 25%; Voltage: NA; Wattage: NA; Weight: 1mg; Datasheet: Y:\MIS_DATABASE\DATASHEETS\DISCRETES\INDUCTORS\BLM15-SN1-SER.PDF
R115 = RESISTOR: RES 9.76K 1/16W 0.1% 0402; Chkd/date: MANIRAJA/190419; Crtd /date: MANIRAJA/190419; Custom_Duty: 15%; Customs_HS_Code: 85332119; Distributor_name: DIGIKEY; Distributor_part_number: P9.76KDCCT-ND; Footprint Path: Y:\MIS_DATABASE\Library\ALTIUM_TOOL\PCB_FOOTPRINTS\Altium_Footprint_Lib.PcbLib; Height: 0.40MM; Library Path: Y:\MIS_DATABASE\Library\ALTIUM_TOOL\SCHEMATICS_PARTS\MS_DISCRETE_Library.schlib; Manufacturer: VISHAY; Mfr_name: PANASONIC-ECG; Mfr_part_number: ERA-2AEB9761X; Mistral Part No: 110019040291-R; Package: 0402; Part_type: RESISTORS\FIXED; Project: TI_J7ES_EVM_FUSION2_SER_CAP; RoHS: RoHS; Temperature: -55°C+155°C; Tolerance: 0.1%; Voltage: NA; Wattage: 1/16W; Weight: 0.6mg; Datasheet: Y:\MIS_DATABASE\DATASHEETS\RESISTORS\ERA-1A.PDF
R387 = RESISTOR: RES 56.2K 1/16W 1% 0402; Chkd/date: PRAVEEN/090922; Crtd /date: TAMILARASU/090922; Custom_Duty: 15%; Customs_HS_Code: 85332119; Distributor_name: DIGIKEY; Distributor_part_number: RMCF0402FT56K2CT-ND; Footprint Path: Y:\MIS_DATABASE\Library\ALTIUM_TOOL\PCB_FOOTPRINTS\Altium_Footprint_Lib.PcbLib; Height: 0.40MM; Library Path: Y:\MIS_DATABASE\Library\ALTIUM_TOOL\SCHEMATICS_PARTS\MS_DISCRETE_Library.schlib; Mfr_name: STACKPOLE ELECTRONICS; Mfr_part_number: RMCF0402FT56K2; Mistral Part No: 110022090013-R; Package: 0402; Part_type: RESISTORS\FIXED; Project: SK AM62Q LP EVM BRD; RoHS: RoHS; Temperature: -55°C+155°C; Tolerance: 1%; Voltage: NA; Wattage: 1/16W; Weight: NA; Datasheet: Y:\MIS_DATABASE\DATASHEETS\RESISTORS\RMCF-SER_JUL18.PDF
R587 = RESISTOR: RES 0E 1/10W JUMPER 0402; Chkd/date: VASANTHA/061216; Crtd /date: NAVEED/201014; Custom_Duty: 15%; Customs_HS_Code: 85332119; Distributor_name: DIGIKEY; Distributor_part_number: P0.0JCT-ND; Footprint Path: Y:\MIS_DATABASE\Library\ALTIUM_TOOL\PCB_FOOTPRINTS\Altium_Footprint_Lib.PcbLib; Height: 0.40MM; IBISSP_MODLES: VALUE REPEATING 2 TIME; Library Path: Y:\MIS_DATABASE\Library\ALTIUM_TOOL\SCHEMATICS_PARTS\MS_DISCRETE_Library.schlib; Mfr_name: PANASONIC-ECG; Mfr_part_number: ERJ-2GE0R00X; Mistral Part No: 110018030052-R; Package: 0402; Part_type: RESISTORS\FIXED; Project: AEGIS POM; RoHS: RoHS; Temperature: -55°C+155°C; Tolerance: NA; Voltage: NA; Wattage: 1/10W; Weight: 0.8mg; Datasheet: Y:\MIS_DATABASE\DATASHEETS\RESISTORS\PAN-ERJSER_NOV17.PDF
U125 = TLV7050_DSBGA4: IC 200mA 0.75V LOW IQ LOW-DROPOUT REGULATOR DSBGA4; Chkd/date: ALVY/300522; Crtd /date: TAMILARASU/300522; Custom_Duty: 15%; Customs_HS_Code: 85423100; Distributor_name: DIGIKEY; Distributor_part_number: 296-TLV705075YFPTCT-ND; Footprint Path: Y:\MIS_DATABASE\Library\ALTIUM_TOOL\PCB_FOOTPRINTS\Altium_Footprint_Lib.PcbLib; Height: 0.50MM; Library Path: Y:\MIS_DATABASE\Library\ALTIUM_TOOL\SCHEMATICS_PARTS\MS_MISCPOWER_Library.schlib; Mfr_name: TEXAS INSTRUMENTS; Mistral Part No: 142022050034-R; Package: DSBGA4; Part_type: ICS\POWER\VOLTAGE REGULATOR; Project: TI_AM62A_SK_EVM; RoHS: RoHS; Temperature: -40°C+125°C; Tolerance: NA; Voltage: NA; Wattage: NA; Weight: 200mg; Datasheet: Y:\MIS_DATABASE\DATASHEETS\ICS\POWER\TLV705X.PDF
U12 = AM62Q_SoC_FCBGA441: IC AM62Q SoC MICROPROCESSOR FCBGA441; Chkd/date: MANIRAJA/211021; Crtd /date: ALVY/211021; Custom_Duty: 15%; Customs_HS_Code: 85423100; Distributor_name: NA; Distributor_part_number: NA; Footprint Path: Y:\MIS_DATABASE\Library\ALTIUM_TOOL\PCB_FOOTPRINTS\Altium_Footprint_Lib.PcbLib; Height: 2.57MM; Library Path: Y:\MIS_DATABASE\Library\ALTIUM_TOOL\SCHEMATICS_PARTS\MS_MICROPROCESSOR_Library.schlib; Mfr_name: TEXAS INSTRUMENTS; Mistral Part No: 141221100001; Package: FCBGA441; Part_type: ICS\DIGITAL\MICROPROCESSOR; Project: TI_AM62Q_BRD; RoHS: NA; Temperature: NA; Tolerance: NA; Voltage: NA; Wattage: NA; Weight: NA; Datasheet: Y:\MIS_DATABASE\DATASHEETS\ICS\DIGITAL\MICROCONTROLLER\AM62Q-SoC.PDF

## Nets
3V3_SYS_EN: R442.2 U67.7(EN/SYNC)
DGND: C25.2 C28.2 C31.2 C42.2 C64.2 C66.2 C67.2 C68.1 C77.1 C89.1 C103.1 C123.2 C225.2 C226.2 C234.2 C235.2 C239.2 C240.2 C241.2 C246.2 C255.2 C257.2 C265.2 C266.2 C274.2 C275.2 C277.2 C278.2 C281.2 C282.2 C284.2 C285.2 C287.2 C295.2 C296.2 C299.2 C300.2 C302.2 C304.2 C306.2 C307.2 C310.2 C311.2 C321.2 C326.2 C327.2 C328.2 C329.2 C333.2 C334.1 C335.2 C342.2 C362.2 C368.1 C369.1 C372.2 C373.2 C390.2 C391.2 C395.2 C400.2 C406.2 C410.2 C411.2 C415.2 C507.2 C531.2 C533.2 R104.2 R115.2 R390.2 R441.2 R450.2 U16.B3(A0) U16.C1(GND) U17.B3(A0) U17.C1(GND) U17.C3(A1) U18.2(GND) U18.5(EP) U56.2(GND) U56.5(EP) U57.4(GND) U58.C1(GND) U60.C1(GND) U61.C1(GND) U63.C1(GND) U63.C3(A1) U67.3(AGND) U67.9(PGND1) U67.11(PGND2) U125.A1(GND) ; also on sheet 1 2 3 4 13 14 18 19 20 21 22 23 24 25 26 27 28 29 30 31 32 33 34 35 36 37 38 39 40 41 42 43
VCC1V1: C103.2 R129.2 ; also on sheet 4
VCC1V8_SYS: C89.2 R121.2 ; also on sheet 4 19 20 22 25 34 37 39 40 42
VCC2V5_PG: R383.1 R386.1 U57.2(PG)
VCC_0V85: C369.2 R136.2 ; also on sheet 4
VCC_3V3_FB: C396.2 R445.2 R450.1 U67.4(FB)
VCC_3V3_MAIN: C123.1 C390.1 C411.1 C415.1 C531.1 FL14.1 L9.2 R387.1 R440.1 R444.1 R445.1 R586.1 TP56.1(TP) U67.1(BIAS) U125.B2(VIN) ; also on sheet 4
VCC_3V3_MAIN_PG: R385.1 R440.2 U67.5(PGOOD) ; also on sheet 4
VCC_3V3_SYS: C64.1 C66.1 C67.1 C333.1 C334.2 C335.1 C362.1 C372.1 C373.1 R86.2 R101.2 U16.B1(VS) U17.B1(VS) U18.4(IN) U57.6(VIN) U58.B1(VS) U58.B3(A0) U58.C3(A1) U60.B1(VS) U60.C3(A1) U61.B1(VS) U63.B1(VS) U63.B3(A0) ; also on sheet 1 4 19 20 21 23 24 26 27 29 30 31 32 33 34 36 37 38 39 40 41 42 43
VCC_CORE: C77.2 R106.2 ; also on sheet 4
VDD_1V0: C326.1 TP35.1(TP) U56.1(OUT) ; also on sheet 1 24
VDD_2V5: C321.1 C340.1 C342.1 L8.2 R386.2 R389.1 TP40.1(TP) U56.4(IN) ; also on sheet 1 24
VDD_2V5_FB: C340.2 R389.2 R390.1 U57.3(FB)
VDD_CANUART: C42.1 C302.1 C311.1 R587.2 U12.H8(VDD_CANUART)
VDD_CANUART_EN: R586.2 U125.A2(EN) ; also on sheet 4
VDD_CORE: C241.1 C274.1 C282.1 C285.1 FL15.2 R106.3 U12.H12(VDD_CORE) U12.H14(VDD_CORE) U12.J9(VDD_CORE) U12.J11(VDD_CORE) U12.J13(VDD_CORE) U12.K10(VDD_CORE) U12.K14(VDD_CORE) U12.L11(VDD_CORE) U12.L13(VDD_CORE) U12.M8(VDD_CORE) U12.M12(VDD_CORE) U12.M14(VDD_CORE) U12.N9(VDD_CORE) U12.N11(VDD_CORE) U12.N13(VDD_CORE) U12.P8(VDD_CORE) U12.P11(VDDA_CORE_USB) U12.P12(VDDA_CORE_CSIRX0) ; also on sheet 18
VDD_LPDDR4: R129.3 U12.C1(VDDS_DDR) U12.J8(VDDS_DDR) U12.K7(VDDS_DDR) U12.K9(VDDS_DDR) U12.L7(VDDS_DDR_C) U12.L8(VDDS_DDR) U12.U1(VDDS_DDR) ; also on sheet 3 18
VDDA1V8: C368.2 R134.2 ; also on sheet 4
VDDA_1V8: C277.1 FL3.1 FL4.1 FL12.1 R134.3 U12.R11(VDDA_1P8_USB)
VDDA_1V8_FB1: C225.1 C226.1 C235.1 C255.1 C265.1 C281.1 C287.1 C307.1 FL12.2 U12.F16(VDDA_TEMP1) U12.H10(VDDA_MCU) U12.K12(VDDA_PLL2) U12.M7(VDDA_TEMP0) U12.N10(VDDA_PLL0) U12.P14(VDDA_PLL1)
VDDA_1V8_FB2: C28.1 C31.1 C275.1 C296.1 C299.1 FL3.2 U12.P9(VDDA_1P8_OLDI0) U12.R9(VDDA_1P8_OLDI0) U12.R12(VDDA_1P8_CSIRX0)
VDDA_1V8_FB_OSC: C25.1 C306.1 FL4.2 U12.J7(VDDS_OSC0)
VDDA_DDR_PLL0: C295.1 C329.1 FL15.1 U12.L9(VDDA_DDR_PLL0)
VDDA_SYS_MON: C533.1 R115.1 R387.2 U12.F6(VMON_ER_VSYS)
VDDR_CORE: R136.3 U12.H11(VDDR_CORE) U12.M10(VDDR_CORE) U12.M13(VDDR_CORE) ; also on sheet 18 36
VDDSHV_CANUART: C310.1 C327.1 C328.1 FL14.2 U12.G7(VDDSHV_CANUART) U12.H7(VDDSHV_CANUART) ; also on sheet 2 4 31 32
VDDSHV_SDIO: FL9.1 ; also on sheet 4 21
CAP_VDDS0: C284.1 U12.G12(CAP_VDDS0)
CAP_VDDS1: C234.1 U12.L15(CAP_VDDS1)
CAP_VDDS2: C266.1 U12.R13(CAP_VDDS2)
CAP_VDDS3: C240.1 U12.M15(CAP_VDDS3)
CAP_VDDS4: C304.1 U12.N8(CAP_VDDS4)
CAP_VDDS5: C246.1 U12.G15(CAP_VDDS5)
CAP_VDDS6: C239.1 U12.J15(CAP_VDDS6)
CAP_VDDS_CANUART: C300.1 U12.G8(CAP_VDDS_CANUART)
CAP_VDDS_MCU: C278.1 U12.G11(CAP_VDDS_MCU)
CBOOT: C405.1 U67.13(RBOOT) U67.14(CBOOT)
INA_ALERT: R85.2 R86.1 R95.2 R392.2 R397.2 R409.2 R414.2 TP31.1(TP)
LM61460_RT: R441.1 U67.6(RT)
LM61460_SW: C405.2 L9.1 U67.10(SW)
LM61460_VCC: C400.1 U67.2(VCC)
SOC_DVDD1V8: R121.3 U12.H9(VMON_1P8_SOC) U12.H15(VDDSHV6) U12.H16(VDDSHV6) U12.K15(VDDSHV1) U12.K16(VDDSHV1) U12.N7(VDDSHV4) U12.P7(VDDSHV4) ; also on sheet 3 18
SoC_DVDD3V3: R101.3 U12.F10(VDDSHV_MCU) U12.F12(VDDSHV0) U12.G10(VDDSHV_MCU) U12.G13(VDDSHV0) U12.K11(VMON_3P3_SOC) U12.N15(VDDSHV3) U12.N16(VDDSHV3) U12.R10(VDDA_3P3_USB) U12.R14(VDDSHV2) U12.R15(VDDSHV2) ; also on sheet 18
SOC_I2C1_SCL: U16.A1(SCL) U16.C3(A1) U17.A1(SCL) U58.A1(SCL) U60.A1(SCL) U61.A1(SCL) U61.C3(A1) U63.A1(SCL) ; also on sheet 23 26 39 40 41 42
SOC_I2C1_SDA: U16.A2(SDA) U17.A2(SDA) U58.A2(SDA) U60.A2(SDA) U60.B3(A0) U61.A2(SDA) U61.B3(A0) U63.A2(SDA) ; also on sheet 23 26 39 40 41 42
SoC_VDDSHV5_SDIO: C257.1 FL9.2 U12.F14(VDDSHV5) U12.G14(VDDSHV5)
SW_2V5: L8.1 U57.5(SW)
TEMP_DIODE_P: TP21.1(TP) U12.F8(RSVD3)
VMAIN: C391.1 C395.1 C406.1 C410.1 R442.1 U67.8(VIN1) U67.12(VIN2) ; also on sheet 13 14 26
VPP_1V8: C68.2 TP33.1(TP) U12.F7(VPP) U18.1(OUT)
VPP_LDO_EN: R103.1 R104.1 ; also on sheet 39
N16839912: C341.1 R391.1 U58.D3(IN+)
N16839940: C371.1 R408.1 U61.D3(IN+)
N16839975: C358.1 R396.1 U60.D3(IN+)
N17012627: R385.2 U57.1(EN)
N17140854: R383.2 U56.3(EN)
N17153379: R92.2 R106.1
N17153381: R96.2 R106.4
N17153415: R136.1 R415.2
N17153417: R136.4 R413.2
N17153507: R84.2 R101.1
N17153509: R87.2 R101.4
N17153511: C58.2 R87.1 U16.D1(BUS) U16.D2(IN-)
N17153515: C58.1 R84.1 U16.D3(IN+)
N17153617: R121.1 R391.2
N17153619: R121.4 R388.2
N17153623: R134.1 R408.2
N17153625: R134.4 R410.2
N17153667: R129.1 R396.2
N17153669: R129.4 R399.2
N17153681: C65.1 R92.1 U17.D3(IN+)
N17153685: C65.2 R96.1 U17.D1(BUS) U17.D2(IN-)
N17153701: C374.2 R413.1 U63.D1(BUS) U63.D2(IN-)
N17153703: C374.1 R415.1 U63.D3(IN+)
N17153749: C341.2 R388.1 U58.D1(BUS) U58.D2(IN-)
N17153787: C371.2 R410.1 U61.D1(BUS) U61.D2(IN-)
N17153799: C358.2 R399.1 U60.D1(BUS) U60.D2(IN-)
N17153878: R414.1 U63.A3(ALERT)
N17153949: R392.1 U58.A3(ALERT)
N17153951: R409.1 U61.A3(ALERT)
N17154063: R397.1 U60.A3(ALERT)
N17277957: C396.1 R444.2
N17337952: R103.2 U18.3(EN)
N18516151: R95.1 U17.A3(ALERT)
N18520654: R85.1 U16.A3(ALERT)
N22163762: C507.1 R587.1 U125.B1(VOUT)

Not connected (* = marked no-connect by the designer): U16 B2(NC1)* C2(NC2)*; U17 B2(NC1)* C2(NC2)*; U58 B2(NC1)* C2(NC2)*; U60 B2(NC1)* C2(NC2)*; U61 B2(NC1)* C2(NC2)*; U63 B2(NC1)* C2(NC2)*

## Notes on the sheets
sheet 15
- PERIPHERAL POWER SUPPLY-2
- 3.3V, 6.0AMPS SUPPLY
- VinMin = 4.5V
  VinMax = 15V
  Vout = 3.3V @ 6A
- SYSTEM PERIPHERAL
- SILK SCREEN : VCC_3V3_MAIN
- @@ ALWAYS ON
- 2.5V, 1.0AMPS SUPPLY
- 1.8V VPP, 0.5AMPS SUPPLY
- ETHERNET PHY
- SoC eFUSE
- SILK SCREEN : VDD_2V5
- SILK SCREEN : VPP_1V8
- 1.0V, 0.5AMPS SUPPLY
- ETHERNET PHY
- SILK SCREEN : VDD_1V0
sheet 16
- CURRENT MONITORING DEVICES
- VDD_CORE
- SoC_DVDD1V8
- I2C ADDRESS: 0x40
- I2C ADDRESS: 0x45
- VDDR_CORE
- VDDA_1V8
- I2C ADDRESS: 0x4E
- I2C ADDRESS: 0x41
- SoC_DVDD3V3
- VDD_LPDDR4
- I2C ADDRESS: 0x4C
- I2C ADDRESS: 0x46
- INA I2C SLAVE ADDRESS
- SLAVE
  ADDRESS
  (IN HEX)
- POWER SOURCE
- SUPPLY NET
- VCC_CORE
- VDD_CORE
- 40
- VCC_0V85
- VDDR_CORE
- 41
- VCC_3V3_SYS
- SoC_DVDD3V3
- 4C
- VCC_1V8
- SoC_DVDD1V8
- 45
- VDDA1V8
- VDDA_1V8
- 4E
- VCC1V1
- VDD_LPDDR4
- 46
sheet 17
- SOC POWER
- 0.5V to VMON_ER_SYS pin
- CAD NOTE: Pin H9 (VMON_1P8_SOC) needs to be routed
   as a signal line and connect to a quiet supply location such
   as after decoupling caps after the DC/DC and before the
   multi-supply branching.
- CORE SUPPLY
- U8Q.J7 = VDDS_OSC
- U8Q.L9 = VDDA_DDR_PLL0
- U8Q.P8 = VDDA_CORE_USB
- 1.8V Analog SUPPLY
- U8Q.R11 = VDDA_1V8_CSIRX
- U8Q.P7,R7 = VDDA_1V8_OLDI
- U8Q.P10 = VDDA_CORE_CSI
- U8Q.R8 = VDDA_1V8_USB
- U8Q.N9 = VDDA_PLL0
- U8Q.P14 = VDDA_PLL1
- U8Q.J13 = VDDA_PLL2
- U8Q.H10 = VDDA_1V8_MCU
- U8Q.P6 = VDDA_TEMP0
  U8Q.F16 = VDDA_TEMP1
- U8Q.G7, U8Q.H7   = VDDSHV_CANUART
- 3.3V/1.8V MMC1 SUPPLY
- VDD_CANUART
- U8Q.H8 = VDD_CANUART
- BLM15PX121SN1D :- 120E
  2A @ 85 deg C
  1.1A @ 125 deg C
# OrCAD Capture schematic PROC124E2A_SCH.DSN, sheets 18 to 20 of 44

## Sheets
18 15. SOC POWER CAPS: size C; title: SOC POWER CAPS & SOC VSS
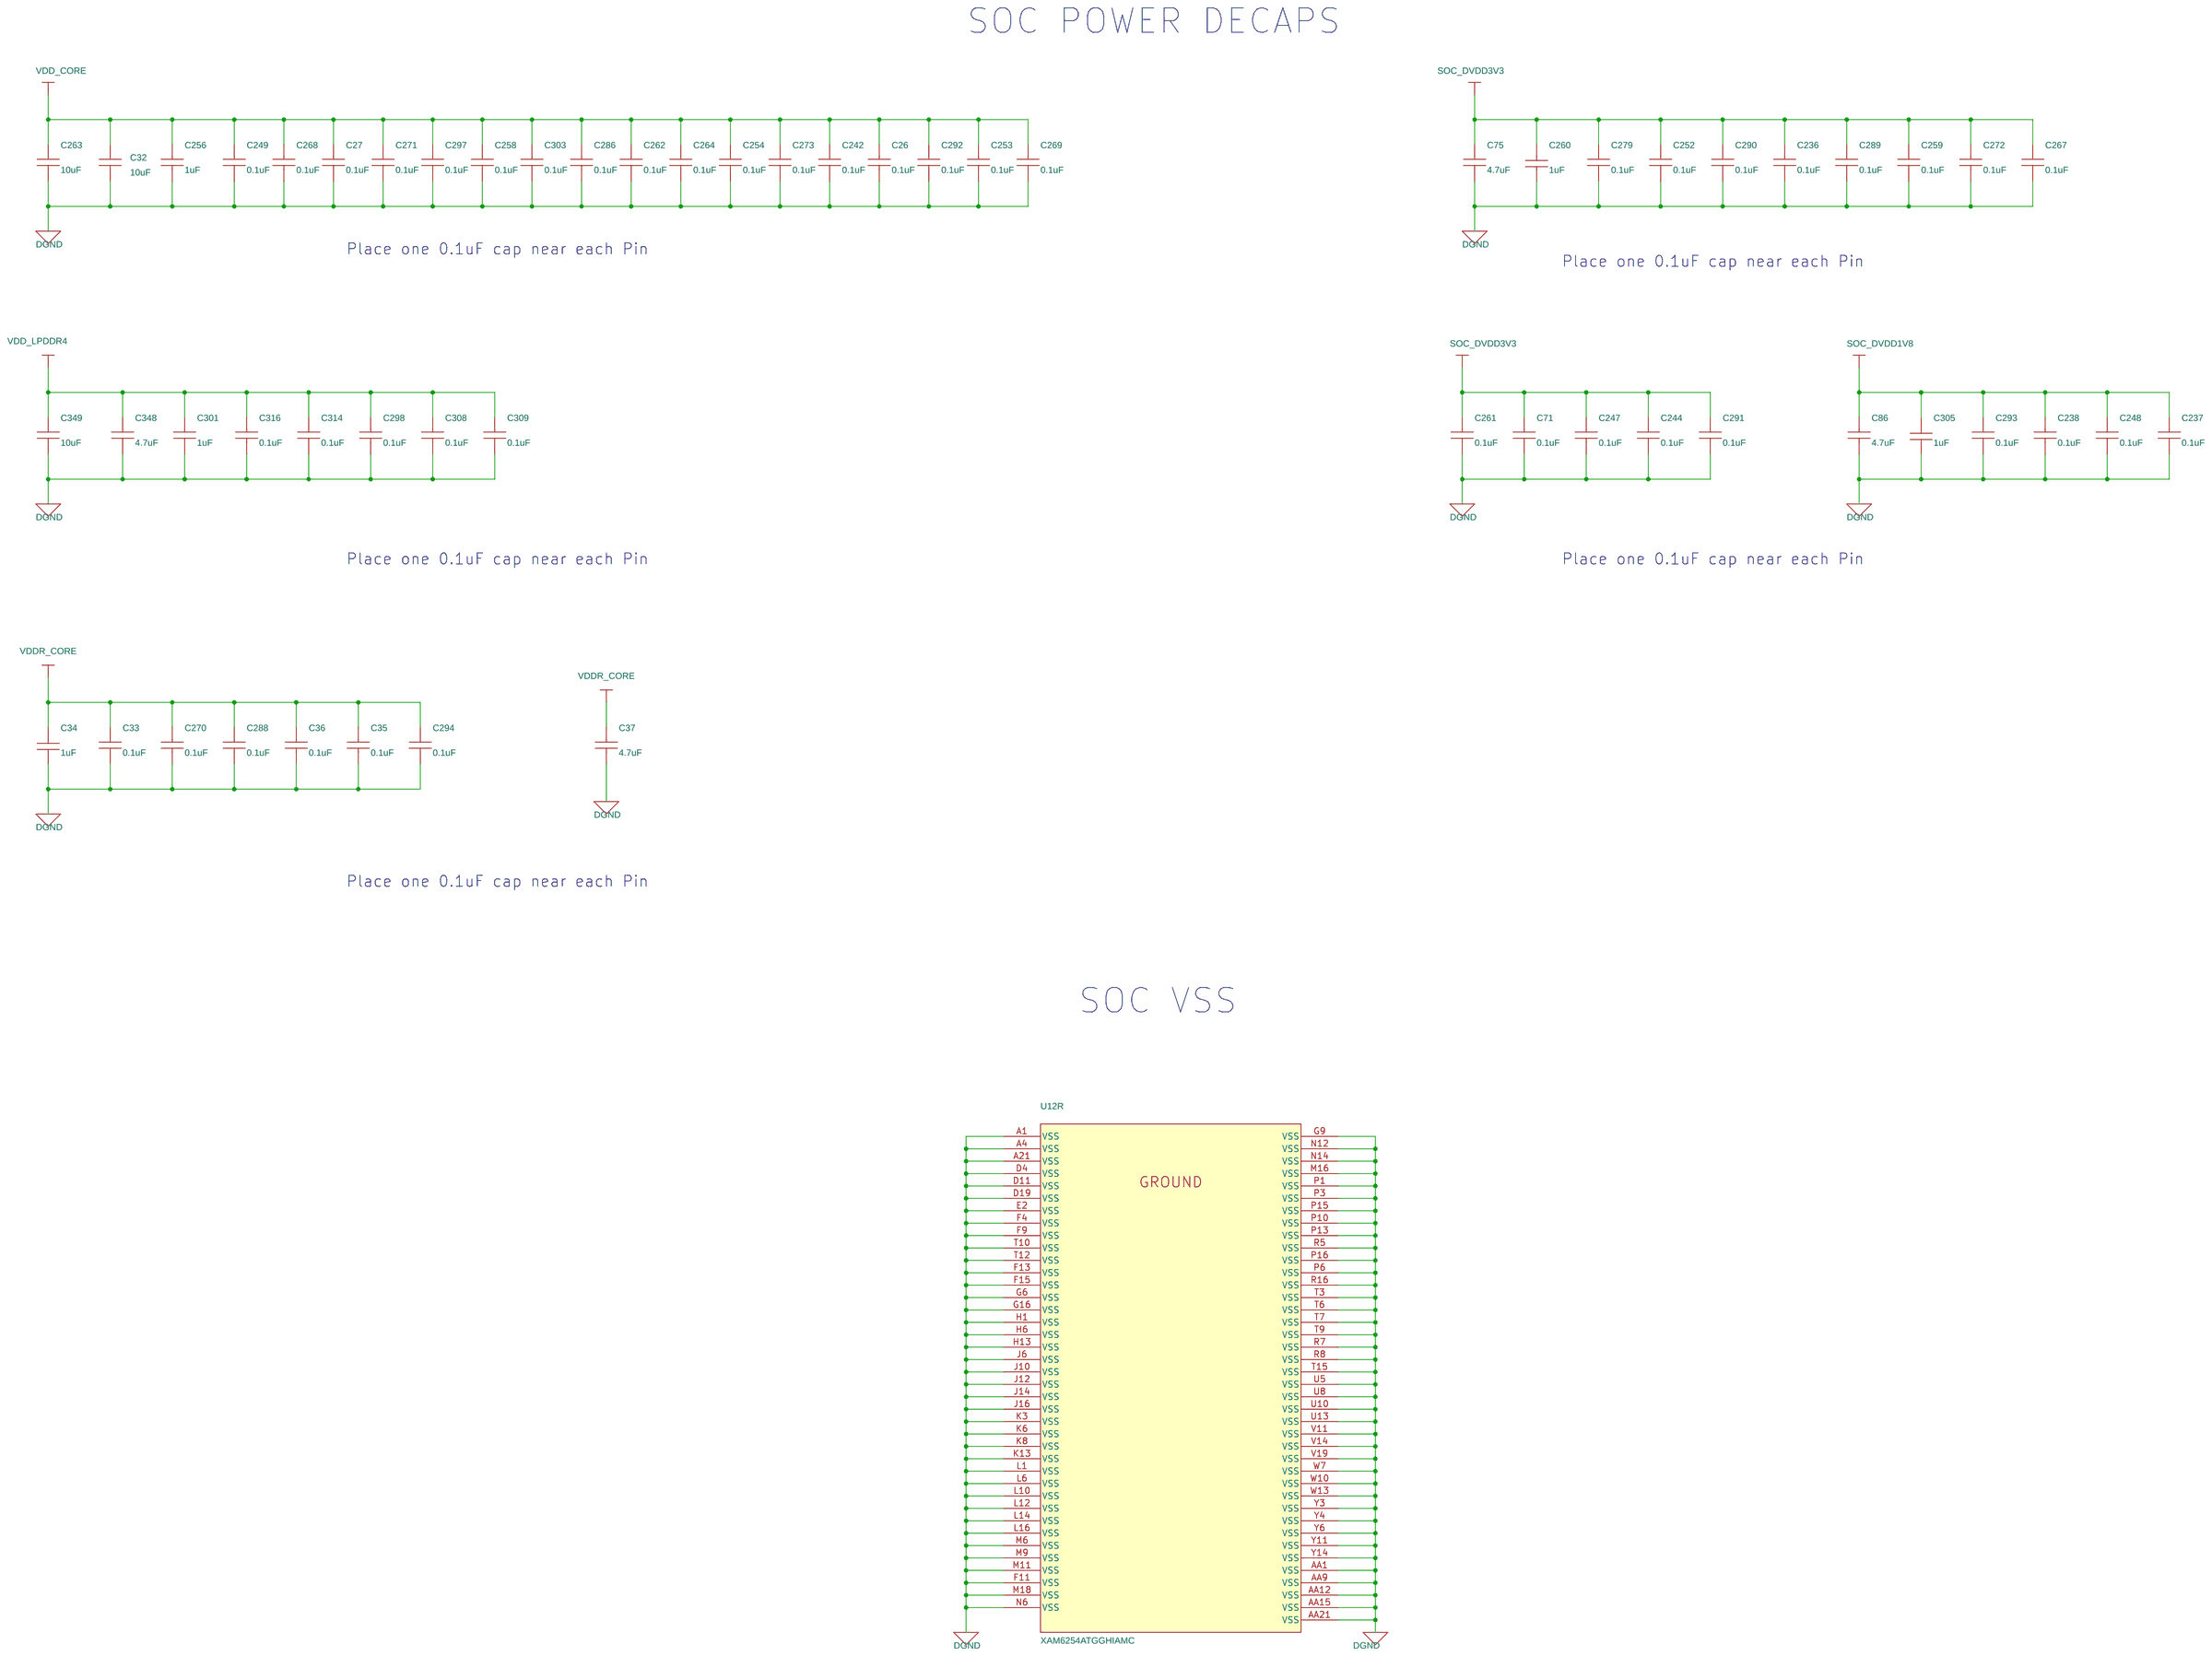
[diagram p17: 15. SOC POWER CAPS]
19 17. M.2 CONNECTOR: size C; title: M.2 CONNECTOR I/F
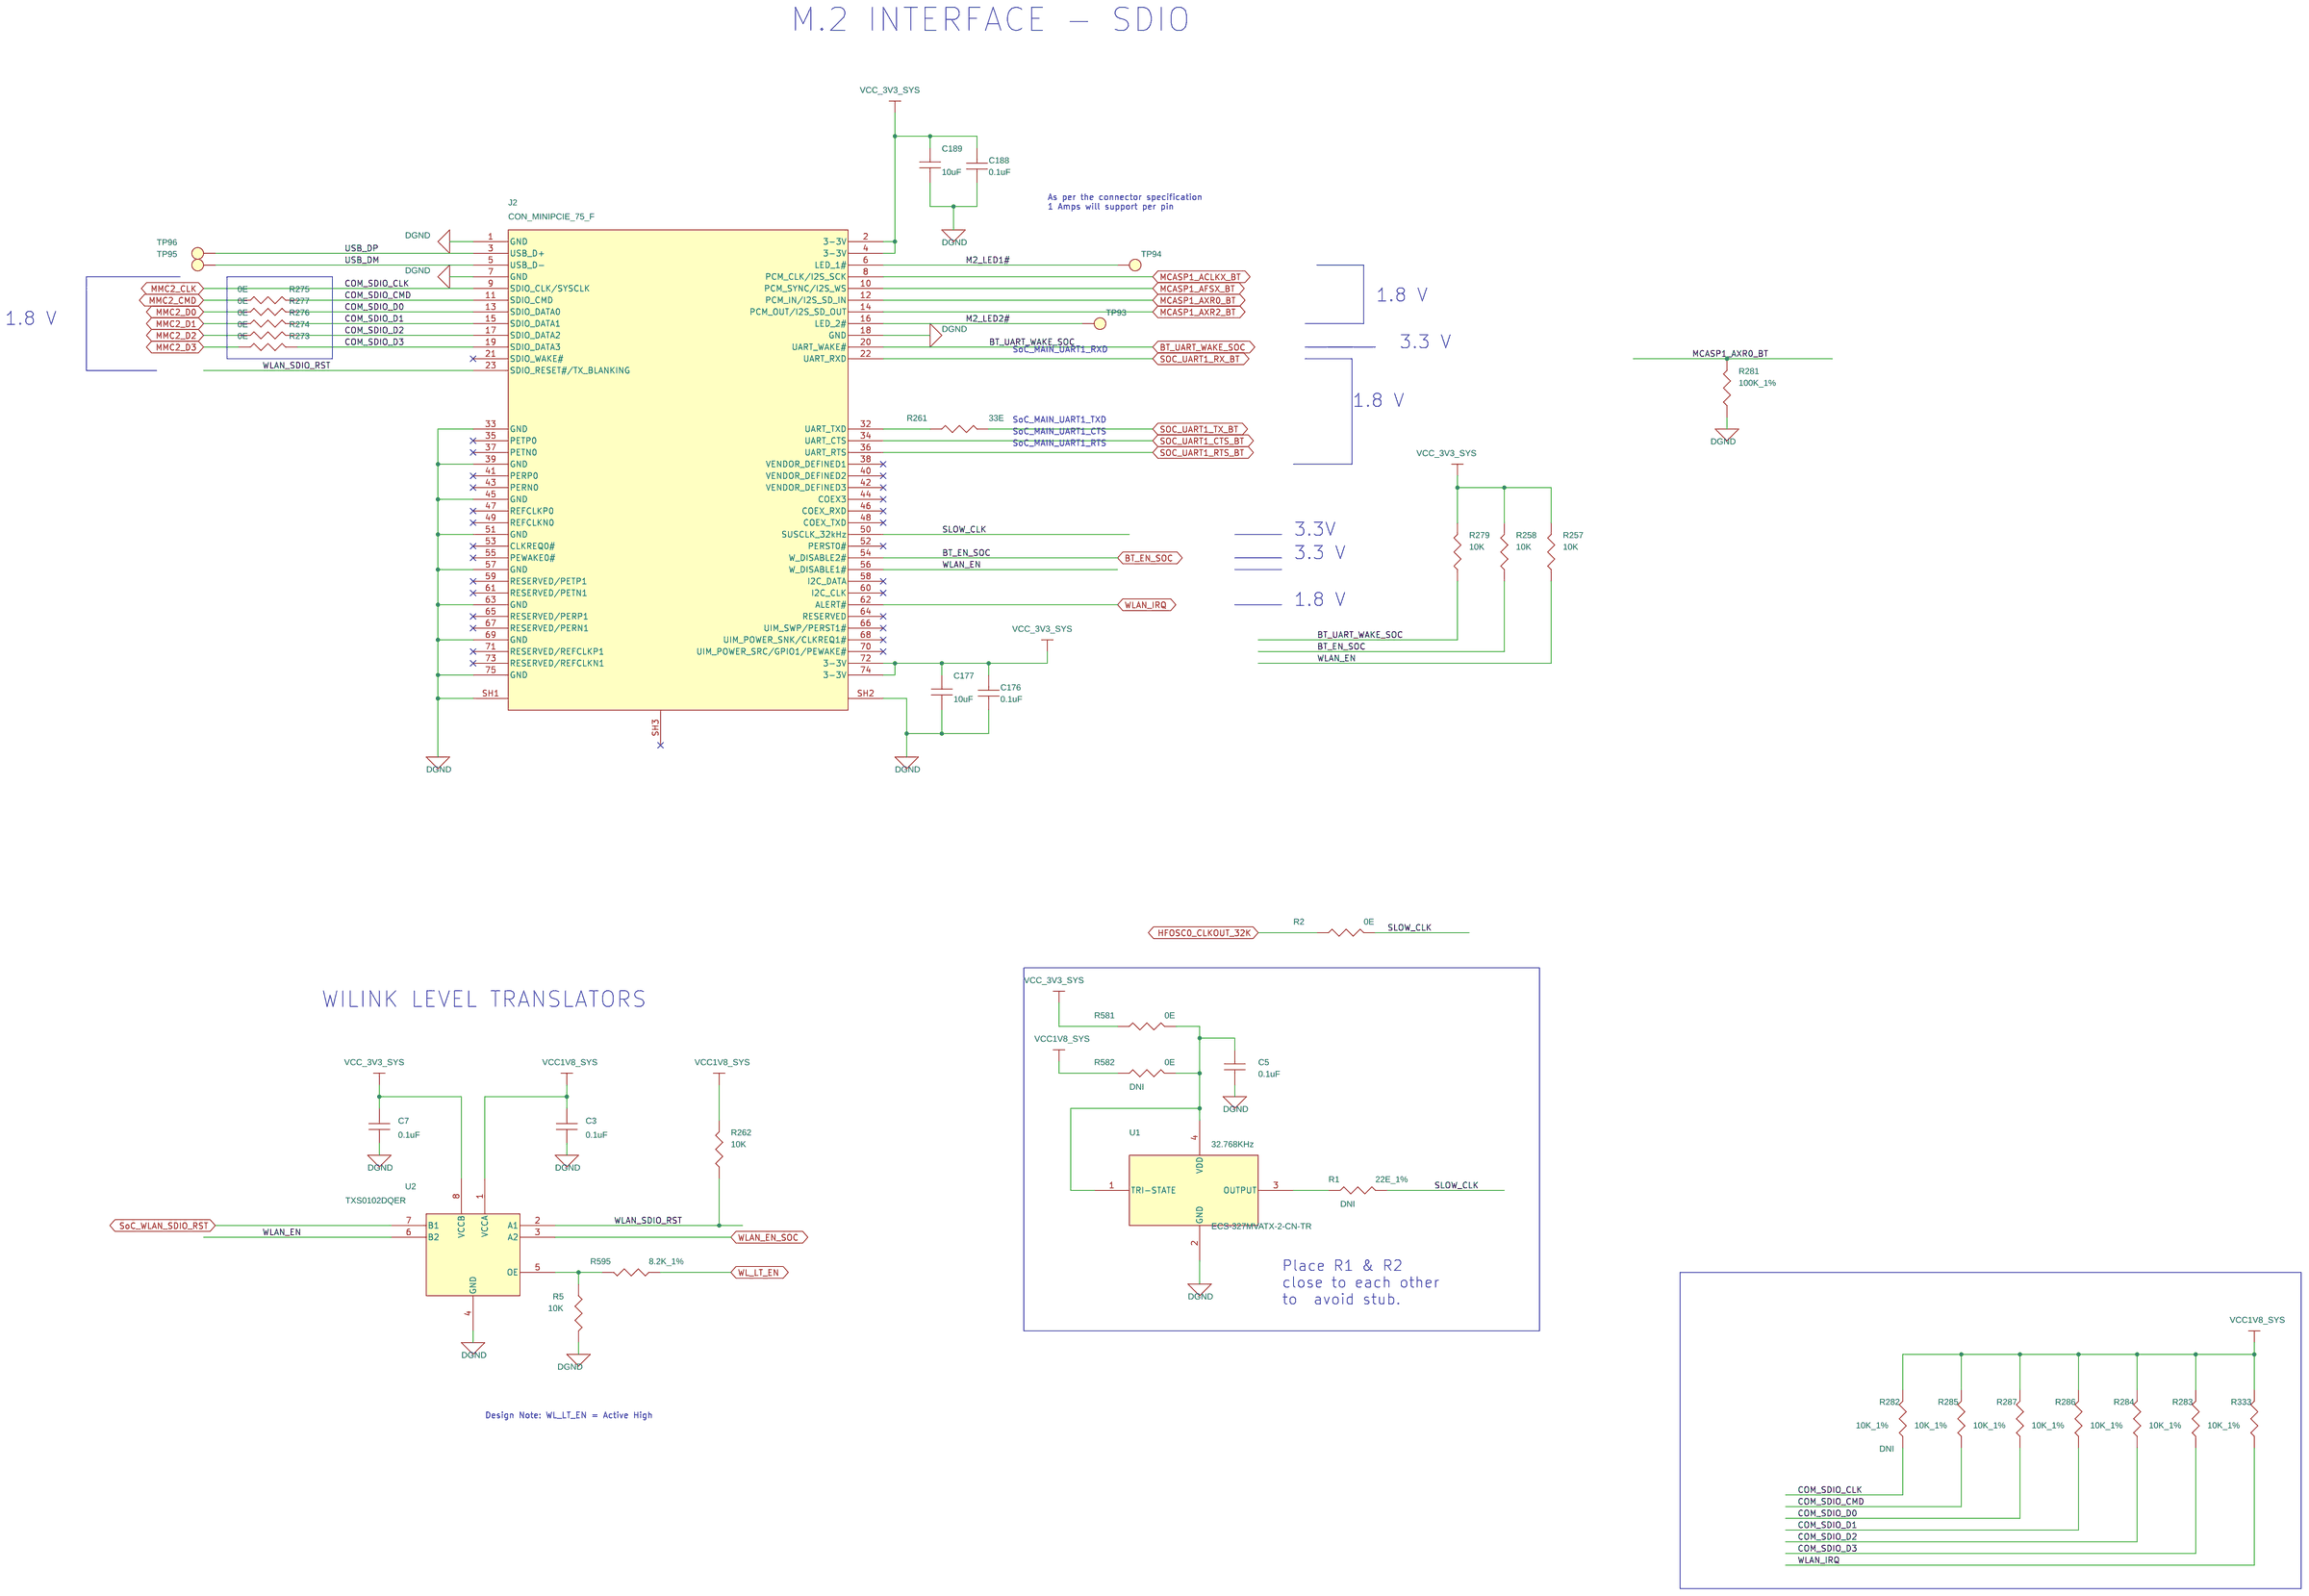
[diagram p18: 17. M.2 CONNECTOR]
20 18. eMMC FLASH: size C; title: eMMC FLASH INTERFACE

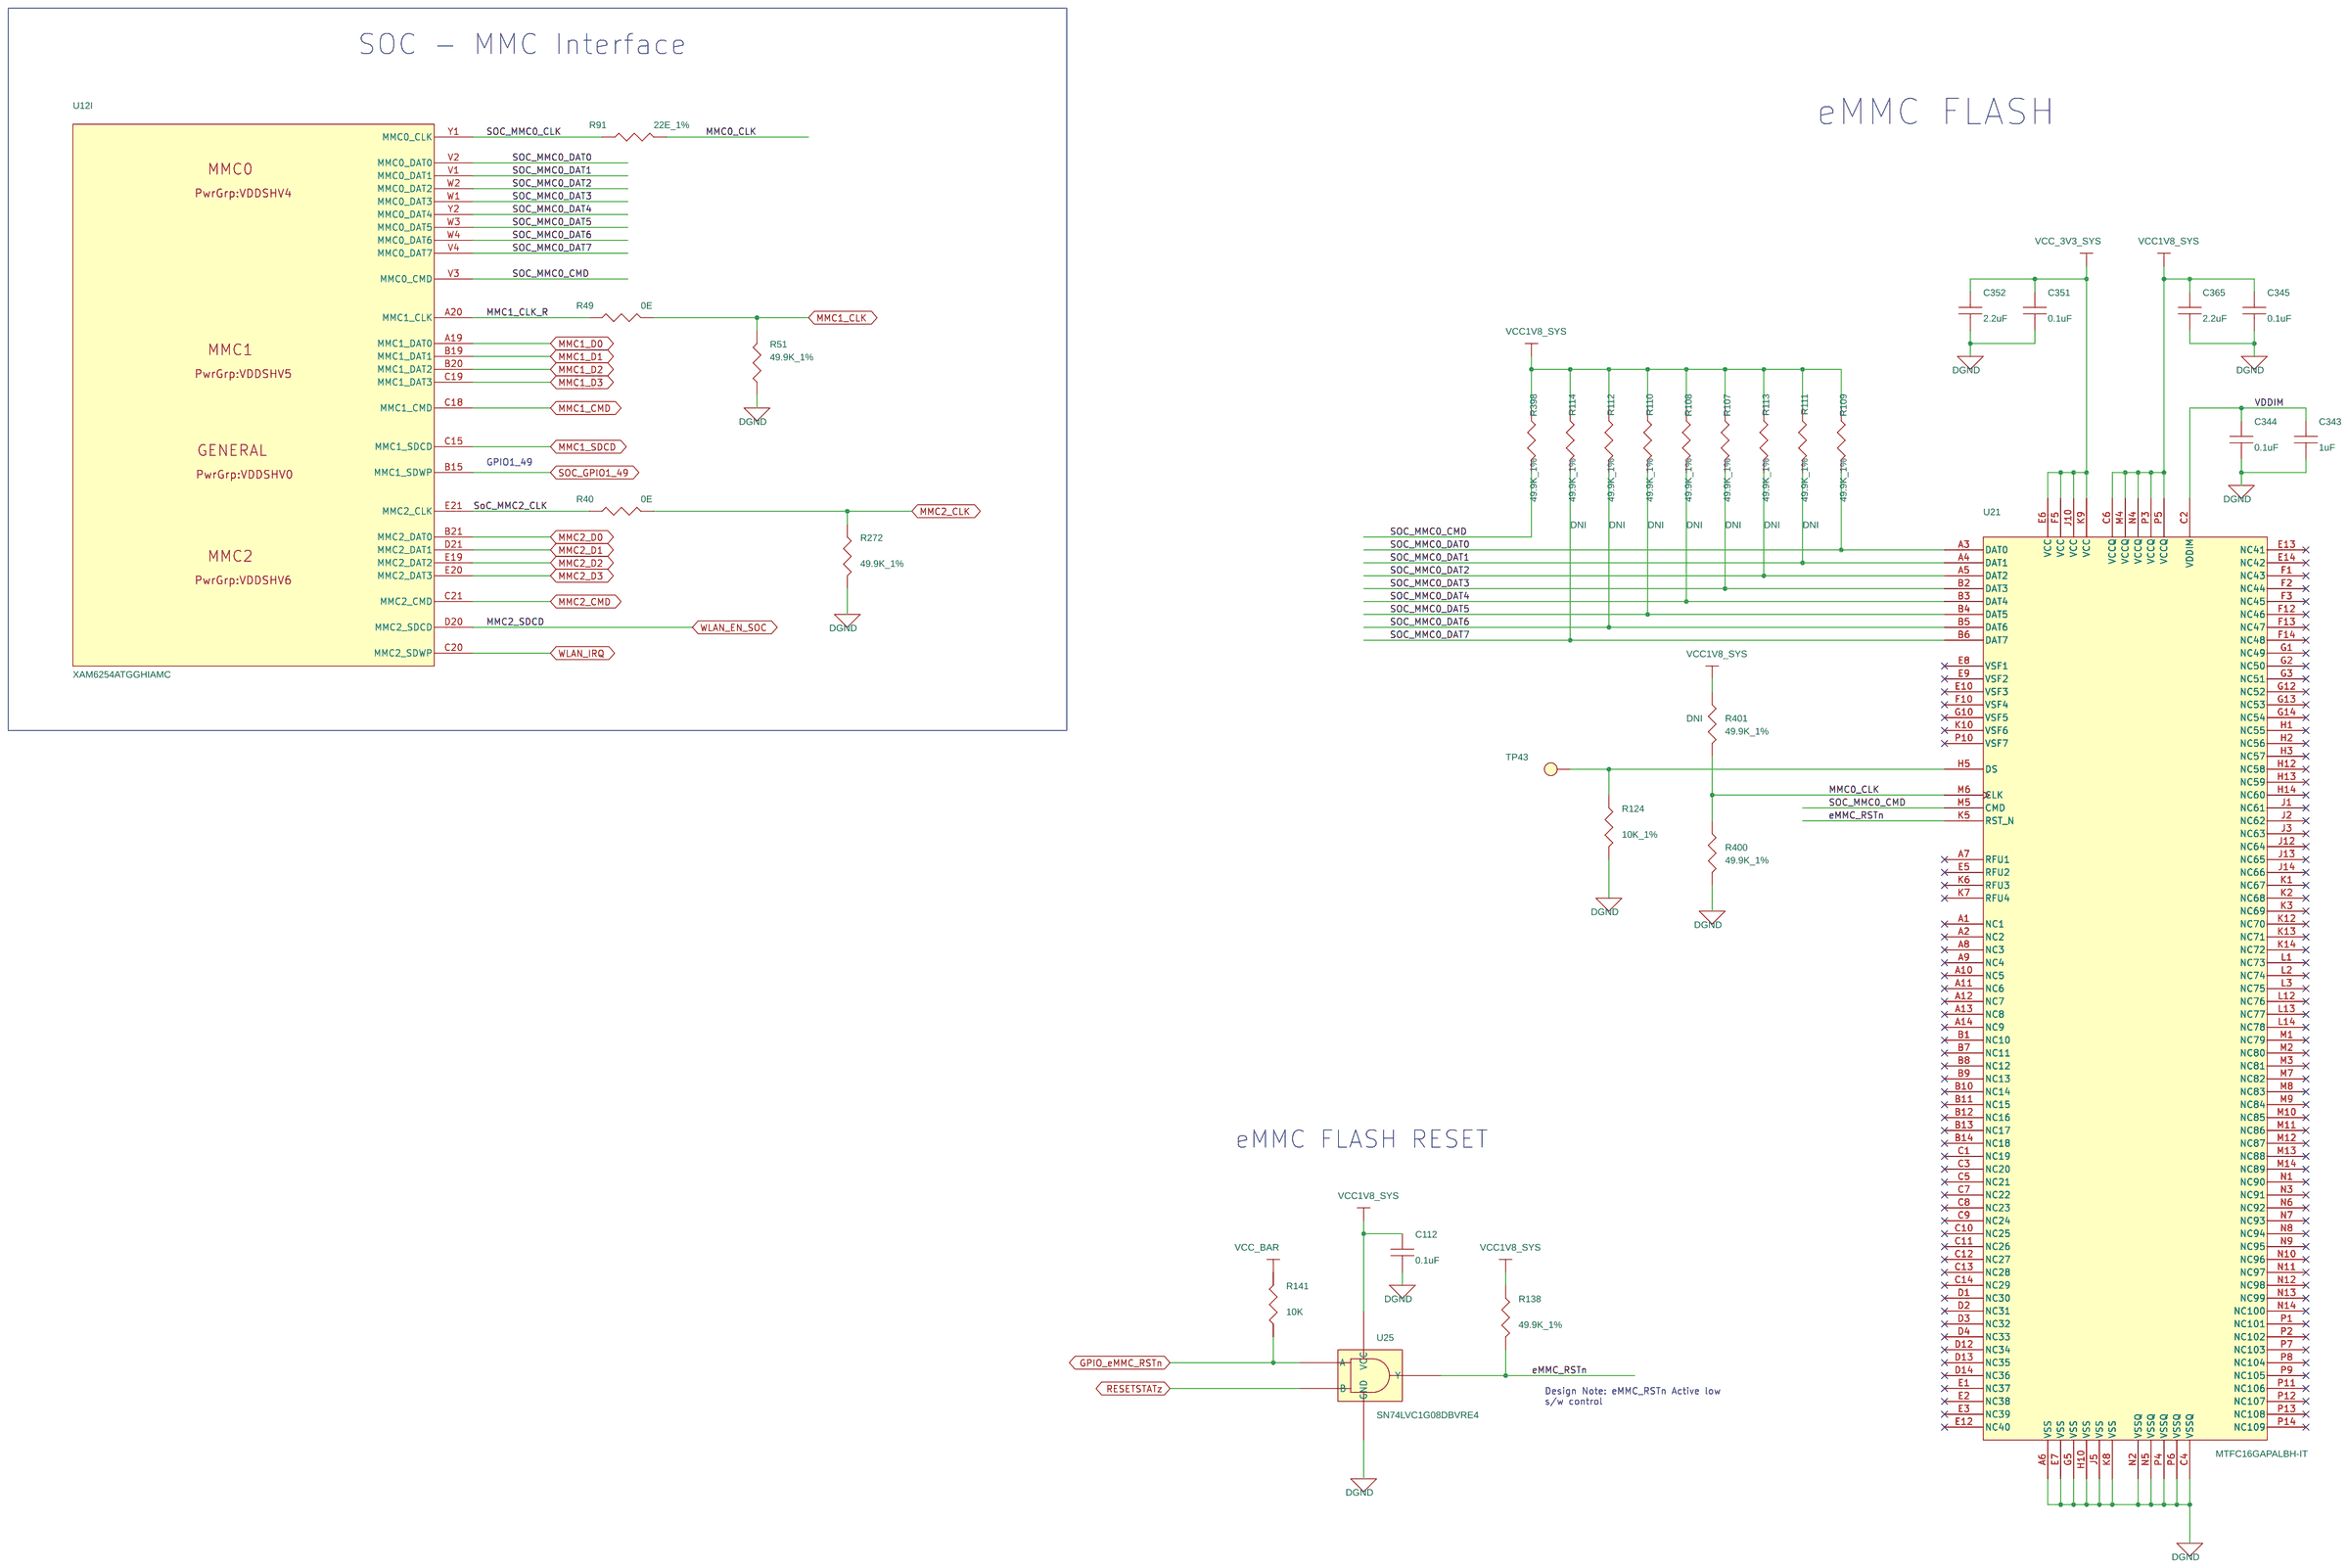
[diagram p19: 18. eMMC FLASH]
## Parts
sheet 15. SOC POWER CAPS
C26  0.1uF  [CAP0201_0-5]
C27  0.1uF  [CAP0201_0-5]
C32  10uF  [CAP0402_0-75]
C33  0.1uF  [CAP0201_0-5]
C34  1uF  [CAP0201_0-5]
C35  0.1uF  [CAP0201_0-5]
C36  0.1uF  [CAP0201_0-5]
C37  4.7uF  [CAP0402_0-75]
C71  0.1uF  [CAP0201_0-5]
C75  4.7uF  [CAP0402_0-75]
C86  4.7uF  [CAP0402_0-75]
C236  0.1uF  [CAP0201_0-5]
C237  0.1uF  [CAP0201_0-5]
C238  0.1uF  [CAP0201_0-5]
C242  0.1uF  [CAP0201_0-5]
C244  0.1uF  [CAP0201_0-5]
C247  0.1uF  [CAP0201_0-5]
C248  0.1uF  [CAP0201_0-5]
C249  0.1uF  [CAP0201_0-5]
C252  0.1uF  [CAP0201_0-5]
C253  0.1uF  [CAP0201_0-5]
C254  0.1uF  [CAP0201_0-5]
C256  1uF  [CAP0201_0-5]
C258  0.1uF  [CAP0201_0-5]
C259  0.1uF  [CAP0201_0-5]
C260  1uF  [CAP0201_0-5]
C261  0.1uF  [CAP0201_0-5]
C262  0.1uF  [CAP0201_0-5]
C263  10uF  [CAP0402_0-75]
C264  0.1uF  [CAP0201_0-5]
C267  0.1uF  [CAP0201_0-5]
C268  0.1uF  [CAP0201_0-5]
C269  0.1uF  [CAP0201_0-5]
C270  0.1uF  [CAP0201_0-5]
C271  0.1uF  [CAP0201_0-5]
C272  0.1uF  [CAP0201_0-5]
C273  0.1uF  [CAP0201_0-5]
C279  0.1uF  [CAP0201_0-5]
C286  0.1uF  [CAP0201_0-5]
C288  0.1uF  [CAP0201_0-5]
C289  0.1uF  [CAP0201_0-5]
C290  0.1uF  [CAP0201_0-5]
C291  0.1uF  [CAP0201_0-5]
C292  0.1uF  [CAP0201_0-5]
C293  0.1uF  [CAP0201_0-5]
C294  0.1uF  [CAP0201_0-5]
C297  0.1uF  [CAP0201_0-5]
C298  0.1uF  [CAP0201_0-5]
C301  1uF  [CAP0201_0-5]
C303  0.1uF  [CAP0201_0-5]
C305  1uF  [CAP0201_0-5]
C308  0.1uF  [CAP0201_0-5]
C309  0.1uF  [CAP0201_0-5]
C314  0.1uF  [CAP0201_0-5]
C316  0.1uF  [CAP0201_0-5]
C348  4.7uF  [CAP0402_0-75]
C349  10uF  [CAP0402_0-75]
sheet 17. M.2 CONNECTOR
C3  0.1uF  [CAP0201_0-5]
C5  0.1uF  [CAP0201_0-5]
C7  0.1uF  [CAP0201_0-5]
C176  0.1uF  [CAP0201_0-5]
C177  10uF  [CAP0402_0-75]
C188  0.1uF  [CAP0201_0-5]
C189  10uF  [CAP0402_0-75]
J2  CON_MINIPCIE_75_F  [CON_MINIPCI75_2199119-4_S_R_S_3-2_2230]
R1  22E_1%  [RES0201_0-5]
R2  0E  [RES0201_0-5]
R5  10K  [RES0201_0-5]
R257  10K  [RES0201_0-5]
R258  10K  [RES0201_0-5]
R261  33E  [RES0201_0-5]
R262  10K  [RES0201_0-5]
R273  0E  [RES0201_0-5]
R274  0E  [RES0201_0-5]
R275  0E  [RES0201_0-5]
R276  0E  [RES0201_0-5]
R277  0E  [RES0201_0-5]
R279  10K  [RES0201_0-5]
R281  100K_1%  [RES0402_0-5]
R282  10K_1%  [RES0201_0-5]
R283  10K_1%  [RES0201_0-5]
R284  10K_1%  [RES0201_0-5]
R285  10K_1%  [RES0201_0-5]
R286  10K_1%  [RES0201_0-5]
R287  10K_1%  [RES0201_0-5]
R333  10K_1%  [RES0201_0-5]
R581  0E  [RES0201_0-5]
R582  0E  [RES0201_0-5]
R595  8.2K_1%  [RES0201_0-5]
TP93  TP20_SMD  [TP20_SMD]
TP94  TP20_SMD  [TP20_SMD]
TP95  TP20_SMD  [TP20_SMD]
TP96  TP20_SMD  [TP20_SMD]
U1  32.768KHz  [OSC4_ECS-327MVATX-2_100X80_SMD_1]
U2  TXS0102DQER  [X2SON8_TXS0102_40X60_0-4]
sheet 18. eMMC FLASH
C112  0.1uF  [CAP0402_0-75]
C343  1uF  [CAP0201_0-5]
C344  0.1uF  [CAP0402_0-75]
C345  0.1uF  [CAP0402_0-75]
C351  0.1uF  [CAP0402_0-75]
C352  2.2uF  [CAP0402_0-75]
C365  2.2uF  [CAP0402_0-75]
R40  0E  [RES0201_0-5]
R49  0E  [RES0201_0-5]
R51  49.9K_1%  [RES0201_0-5]
R91  22E_1%  [RES0201_0-5]
R107  49.9K_1%  [RES0201_0-5]
R108  49.9K_1%  [RES0201_0-5]
R109  49.9K_1%  [RES0201_0-5]
R110  49.9K_1%  [RES0201_0-5]
R111  49.9K_1%  [RES0201_0-5]
R112  49.9K_1%  [RES0201_0-5]
R113  49.9K_1%  [RES0201_0-5]
R114  49.9K_1%  [RES0201_0-5]
R124  10K_1%  [RES0201_0-5]
R138  49.9K_1%  [RES0201_0-5]
R141  10K  [RES0201_0-5]
R272  49.9K_1%  [RES0201_0-5]
R398  49.9K_1%  [RES0201_0-5]
R400  49.9K_1%  [RES0201_0-5]
R401  49.9K_1%  [RES0201_0-5]
TP43  TP20_SMD  [TP20_SMD]
U21  MTFC16GAPALBH-IT  [VFBGA153_19-68_460X520_1-1]
U25  SN74LVC1G08DBVRE4  [SOT23-5]
sheet 31. PRU HEADER
U12  XAM6254ATGGHIAMC  [FCBGA441_31-49_680X680_2-6]  (sections A,B,C,D,E,F,G,H,I,J,K,L,M,N,O,P,Q,R)

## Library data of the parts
C26 C27 C33 C35 C36 C71 C236-C238 C242 C244 C247-C249 C252-C254 C258 C259 C261 C262 C264 C267-C273 C279 C286 C288-C294 C297 C298 C303 C308 C309 C314 C316 = CAP: CAP CERAMIC 0.1uF 16V 10% X5R 0201; Chkd/date: MANIRAJA/230118; Crtd /date: MANIRAJA/230118; Custom_Duty: 15%; Customs_HS_Code: 85322990; Distributor_name: DIGIKEY; Distributor_part_number: 490-14305-1-ND; Footprint Path: Y:\MIS_DATABASE\Library\ALTIUM_TOOL\PCB_FOOTPRINTS\Altium_Footprint_Lib.PcbLib; Height: 0.33MM; Library Path: Y:\MIS_DATABASE\Library\ALTIUM_TOOL\SCHEMATICS_PARTS\MS_DISCRETE_Library.schlib; Mfr_name: MURATA; Mfr_part_number: GRM033R61C104KE14D; Mistral Part No: 120009030072-R; Package: 0201; Part_type: CAPACITORS\CERAMIC; Project: TI_MAXIE_CPB; RoHS: RoHS; Temperature: -55°C+85°C; Tolerance: 10%; Voltage: 16V; Wattage: NA; Weight: 0.33mg; Datasheet: Y:\MIS_DATABASE\DATASHEETS\CAPACITORS\GRM033R61C104KE14.PDF
C32 C177 C189 C263 C349 = CAP: CAP CERAMIC 10uF 10V 20% X5R 0402; Chkd/date: MANIRAJA/300520; Crtd /date: ALVY/260520; Custom_Duty: 15%; Customs_HS_Code: 85322990; Distributor_name: DIGIKEY; Distributor_part_number: 490-GRM155R61A106ME11DTR-ND; Footprint Path: Y:\MIS_DATABASE\Library\ALTIUM_TOOL\PCB_FOOTPRINTS\Altium_Footprint_Lib.PcbLib; Height: 0.55MM; Library Path: Y:\MIS_DATABASE\Library\ALTIUM_TOOL\SCHEMATICS_PARTS\MS_DISCRETE_Library.schlib; Mfr_name: MURATA; Mfr_part_number: GRM155R61A106ME11D; Mistral Part No: 120013110019-R; Package: 0402; Part_type: CAPACITORS\CERAMIC; Project: QCS610_NANOSOM; RoHS: RoHS; Temperature: -55°C+85°C; Tolerance: 20%; Voltage: 10V; Wattage: NA; Weight: 3.1mg; Datasheet: Y:\MIS_DATABASE\DATASHEETS\CAPACITORS\MURATA-GXX-SER_NOV17.PDF
C34 C256 C260 C301 C305 C343 = CAP: CAP CERAMIC 1uF 16V 20% X5R 0201; Chkd/date: MANIRAJA/300520; Crtd /date: ALVY/260520; Custom_Duty: 15%; Customs_HS_Code: 85322990; Distributor_name: DIGIKEY; Distributor_part_number: 490-18654-1-ND; Footprint Path: Y:\MIS_DATABASE\Library\ALTIUM_TOOL\PCB_FOOTPRINTS\Altium_Footprint_Lib.PcbLib; Height: 0.39MM; Library Path: Y:\MIS_DATABASE\Library\ALTIUM_TOOL\SCHEMATICS_PARTS\MS_DISCRETE_Library.schlib; Mfr_name: MURATA; Mfr_part_number: GRM033R61C105ME15D; Mistral Part No: 120018090038-R; Package: 0201; Part_type: CAPACITORS\CERAMIC; Project: QCS610_NANOSOM; RoHS: RoHS; Temperature: -55°C+85°C; Tolerance: 20%; Voltage: 16V; Wattage: NA; Weight: 0.33mg; Datasheet: Y:\MIS_DATABASE\DATASHEETS\CAPACITORS\GRM033R61C105ME15.PDF
C37 C75 C86 C348 = CAP: CAP CERAMIC 4.7uF 10V 20% X5R 0402; Chkd/date: MANIRAJA/110718; Crtd /date: ALVY/110718; Custom_Duty: 15%; Customs_HS_Code: 85322990; Distributor_name: DIGIKEY; Distributor_part_number: 490-14306-1-ND; Footprint Path: Y:\MIS_DATABASE\Library\ALTIUM_TOOL\PCB_FOOTPRINTS\Altium_Footprint_Lib.PcbLib; Height: 0.65MM; Library Path: Y:\MIS_DATABASE\Library\ALTIUM_TOOL\SCHEMATICS_PARTS\MS_DISCRETE_Library.schlib; Mfr_name: MURATA; Mfr_part_number: GRM155R61A475MEAAD; Mistral Part No: 120012060002-R; Package: 0402; Part_type: CAPACITORS\CERAMIC; Project: TI_J7SVB_PCIE_ADD-ON-CARD; RoHS: RoHS; Temperature: -55°C+85°C; Tolerance: 20%; Voltage: 10V; Wattage: NA; Weight: 14mg; Datasheet: Y:\MIS_DATABASE\DATASHEETS\CAPACITORS\GRM155R61A475MEAAD.PDF
C3 C5 C7 C176 C188 = CAP: CAP CERAMIC 0.1uF 16V 10% X5R 0201; Alt_Mfr_name: YAGEO AMERICA; Alt_Mfr_part_number: CC0402KRX5R8BB104; Chkd/date: MANIRAJA/230118; Crtd /date: MANIRAJA/230118; Custom_Duty: 15%; Customs_HS_Code: 85322990; Distributor_name: DIGIKEY; Distributor_part_number: 490-14305-1-ND; Footprint Path: Y:\MIS_DATABASE\Library\ALTIUM_TOOL\PCB_FOOTPRINTS\Altium_Footprint_Lib.PcbLib; Height: 0.33MM; Library Path: Y:\MIS_DATABASE\Library\ALTIUM_TOOL\SCHEMATICS_PARTS\MS_DISCRETE_Library.schlib; Mfr_name: MURATA; Mfr_part_number: GRM033R61C104KE14D; Mistral Part No: 120009030072-R; Package: 0201; Part_type: CAPACITORS\CERAMIC; Project: TI_MAXIE_CPB; RoHS: RoHS; Temperature: -55°C+85°C; Tolerance: 10%; Voltage: 16V; Wattage: NA; Weight: 0.33mg; Datasheet: Y:\MIS_DATABASE\DATASHEETS\CAPACITORS\GRM033R61C104KE14.PDF
J2 = CON_PCI_75_2199119-4_2230: CON MINIPCI 75POS 0.50MM PITCH FEMALE RT SMD; Chkd/date: ALVY/300521; Crtd /date: ALVY/300521; Custom_Duty: 24%; Customs_HS_Code: 85369090; Distributor_name: DIGIKEY; Distributor_part_number: A115900CT-ND; Footprint Path: Y:\MIS_DATABASE\Library\ALTIUM_TOOL\PCB_FOOTPRINTS\Altium_Footprint_Lib.PcbLib; Height: 3.20MM; Library Path: Y:\MIS_DATABASE\Library\ALTIUM_TOOL\SCHEMATICS_PARTS\MS_CONNECTOR_Library.schlib; Mfr_name: TE CONNECTIVITY; Mfr_part_number: 2199119-4_2230; Mistral Part No: 150021030016-R; Package: SMD; Part_type: CONNECTOR\PCI; Project: VOLTA_CHARGER V5; RoHS: RoHS; Temperature: -40°C+80°C; Tolerance: NA; Voltage: NA; Wattage: NA; Weight: 506mg; Datasheet: Y:\MIS_DATABASE\DATASHEETS\CONNECTORS\2199119.PDF
R1 = RESISTOR: RES 22E 1/20W 1% 0201; Assembly_Instruction: DNI; Chkd/date: PRAVEEN/080922; Crtd /date: TAMILARASU/080922; Custom_Duty: 15%; Customs_HS_Code: 85332119; Distributor_name: DIGIKEY; Distributor_part_number: P122843CT-ND; Footprint Path: Y:\MIS_DATABASE\Library\ALTIUM_TOOL\PCB_FOOTPRINTS\Altium_Footprint_Lib.PcbLib; Height: 0.26MM; Library Path: Y:\MIS_DATABASE\Library\ALTIUM_TOOL\SCHEMATICS_PARTS\MS_DISCRETE_Library.schlib; Mfr_name: PANASONIC-ECG; Mfr_part_number: ERJ-1GNF22R0C; Mistral Part No: 110022090007-R; Package: 0201; Part_type: RESISTORS\FIXED; Project: SK AM62Q LP EVM BRD; RoHS: RoHS; Temperature: -55°C+125°C; Tolerance: 1%; Voltage: NA; Wattage: 1/20W; Weight: 0.15mg; Datasheet: Y:\MIS_DATABASE\DATASHEETS\RESISTORS\PAN-ERJSER_NOV17.PDF
R2 R49 R581 = RESISTOR: RES 0E 1/20W 5% 0201; Chkd/date: NAVEED/301214; Crtd /date: MUDDU/120710; Custom_Duty: 15%; Customs_HS_Code: 85332119; Distributor_name: DIGIKEY; Distributor_part_number: 311-0.0NCT-ND; Footprint Path: Y:\MIS_DATABASE\Library\ALTIUM_TOOL\PCB_FOOTPRINTS\Altium_Footprint_Lib.PcbLib; Height: 0.26MM; Library Path: Y:\MIS_DATABASE\Library\ALTIUM_TOOL\SCHEMATICS_PARTS\MS_DISCRETE_Library.schlib; Mfr_name: YAGEO AMERICA; Mfr_part_number: RC0201JR-070RL; Mistral Part No: 110010070067-R; Package: 0201; Part_type: RESISTORS\FIXED; Project: PB_BUGBASE; RoHS: RoHS; Temperature: -55°C+125°C; Tolerance: 5%; Voltage: NA; Wattage: 1/20W; Weight: 0.17mg; Datasheet: Y:\MIS_DATABASE\DATASHEETS\RESISTORS\RCXXXXL-SER_MAR18.PDF
R5 R141 R257 R258 R262 R279 = RESISTOR: RES 10K 1/20W 5% 0201; Chkd/date: MANIRAJA/050517; Crtd /date: MANIRAJA/050517; Custom_Duty: 15%; Customs_HS_Code: 85332119; Distributor_name: DIGIKEY; Distributor_part_number: 311-10KNCT-ND; Footprint Path: Y:\MIS_DATABASE\Library\ALTIUM_TOOL\PCB_FOOTPRINTS\Altium_Footprint_Lib.PcbLib; Height: 0.26MM; Library Path: Y:\MIS_DATABASE\Library\ALTIUM_TOOL\SCHEMATICS_PARTS\MS_DISCRETE_Library.schlib; Mfr_name: YAGEO AMERICA; Mfr_part_number: RC0201JR-0710KL; Mistral Part No: 110010070051-R; Package: 0201; Part_type: RESISTORS\FIXED; Project: GOLDEN-I LITE; RoHS: RoHS; Temperature: -55°C+125°C; Tolerance: 5%; Voltage: NA; Wattage: 1/20W; Weight: 0.17mg; Datasheet: Y:\MIS_DATABASE\DATASHEETS\RESISTORS\RCXXXXL-SER_MAR18.PDF
R261 = RESISTOR: RES 33E 1/20W 5% 0201; Chkd/date: ALVY/070422; Crtd /date: TAMILARASU/070422; Custom_Duty: 15%; Customs_HS_Code: 85332119; Distributor_name: DIGIKEY; Distributor_part_number: P123303CT-ND; Footprint Path: Y:\MIS_DATABASE\Library\ALTIUM_TOOL\PCB_FOOTPRINTS\Altium_Footprint_Lib.PcbLib; Height: 0.26MM; Library Path: Y:\MIS_DATABASE\Library\ALTIUM_TOOL\SCHEMATICS_PARTS\MS_DISCRETE_Library.schlib; Mfr_name: PANASONIC-ECG; Mfr_part_number: ERJ-1GNJ330C; Mistral Part No: 110010070052-R; Package: 0201; Part_type: RESISTORS\FIXED; Project: TI_AM62x_SKEVM_BRD; RoHS: RoHS; Temperature: -55°C+125°C; Tolerance: 5%; Voltage: NA; Wattage: 1/20W; Weight: 0.15mg; Datasheet: Y:\MIS_DATABASE\DATASHEETS\RESISTORS\PAN-ERJSER_NOV17.PDF
R40 R273-R277 = RESISTOR: RES 0E 1/20W 5% 0201; Chkd/date: NAVEED/301214; Crtd /date: MUDDU/120710; Custom_Duty: 15%; Customs_HS_Code: 85332119; Distributor_name: DIGIKEY; Distributor_part_number: 311-0.0NCT-ND; Footprint Path: Y:\MIS_DATABASE\Library\ALTIUM_TOOL\PCB_FOOTPRINTS\Altium_Footprint_Lib.PcbLib; Height: 0.26MM; Library Path: Y:\MIS_DATABASE\Library\ALTIUM_TOOL\SCHEMATICS_PARTS\MS_DISCRETE_Library.schlib; Mfr_name: YAGEO AMERICA; Mfr_part_number: RC0201JR-070RL; Mistral Part No: 110010070067-R; Package: 0201; Part_type: RESISTORS\FIXED; Project: PB_BUGBASE; RoHS: RoHS; SIGNAL_MODEL: RESISTOR_RES0201_0-5_0E_0E; Temperature: -55°C+125°C; Tolerance: 5%; Voltage: NA; Wattage: 1/20W; Weight: 0.17mg; Datasheet: Y:\MIS_DATABASE\DATASHEETS\RESISTORS\RCXXXXL-SER_MAR18.PDF
R281 = RESISTOR: RES 100K 1/10W 1% 0402; Chkd/date: VASANTHA/201216; Crtd /date: MAZHAR/130306; Custom_Duty: 15%; Customs_HS_Code: 85332119; Distributor_name: DIGIKEY; Distributor_part_number: P100KLCT-ND; Footprint Path: Y:\MIS_DATABASE\Library\ALTIUM_TOOL\PCB_FOOTPRINTS\Altium_Footprint_Lib.PcbLib; Height: 0.40MM; Library Path: Y:\MIS_DATABASE\Library\ALTIUM_TOOL\SCHEMATICS_PARTS\MS_DISCRETE_Library.schlib; Mfr_name: PANASONIC-ECG; Mfr_part_number: ERJ-2RKF1003X; Mistral Part No: 110009030187-R; Package: 0402; Part_type: RESISTORS\FIXED; Project: J32; RoHS: RoHS; Temperature: -55°C+155°C; Tolerance: 1%; Voltage: NA; Wattage: 1/10W; Weight: 0.8mg; Datasheet: Y:\MIS_DATABASE\DATASHEETS\RESISTORS\PAN-ERJSER_NOV17.PDF
R282 = RESISTOR: RES 10K 1/20W 1% 0201; Assembly_Instruction: DNI; Chkd/date: VASANTHA/270117; Crtd /date: MANIRAJA/270117; Custom_Duty: 15%; Customs_HS_Code: 85332119; Distributor_name: DIGIKEY; Distributor_part_number: 311-10.0KMCT-ND; Footprint Path: Y:\MIS_DATABASE\Library\ALTIUM_TOOL\PCB_FOOTPRINTS\Altium_Footprint_Lib.PcbLib; Height: 0.26MM; Library Path: Y:\MIS_DATABASE\Library\ALTIUM_TOOL\SCHEMATICS_PARTS\MS_DISCRETE_Library.schlib; Mfr_name: YAGEO AMERICA; Mfr_part_number: RC0201FR-0710KL; Mistral Part No: 110011040018-R; Package: 0201; Part_type: RESISTORS\FIXED; Project: GOLDEN-I LITE; RoHS: RoHS; Temperature: -55°C+125°C; Tolerance: 1%; Voltage: NA; Wattage: 1/20W; Weight: 0.17mg; Datasheet: Y:\MIS_DATABASE\DATASHEETS\RESISTORS\RCXXXXL-SER_MAR18.PDF
R124 R283-R287 R333 = RESISTOR: RES 10K 1/20W 1% 0201; Chkd/date: VASANTHA/270117; Crtd /date: MANIRAJA/270117; Custom_Duty: 15%; Customs_HS_Code: 85332119; Distributor_name: DIGIKEY; Distributor_part_number: 311-10.0KMCT-ND; Footprint Path: Y:\MIS_DATABASE\Library\ALTIUM_TOOL\PCB_FOOTPRINTS\Altium_Footprint_Lib.PcbLib; Height: 0.26MM; Library Path: Y:\MIS_DATABASE\Library\ALTIUM_TOOL\SCHEMATICS_PARTS\MS_DISCRETE_Library.schlib; Mfr_name: YAGEO AMERICA; Mfr_part_number: RC0201FR-0710KL; Mistral Part No: 110011040018-R; Package: 0201; Part_type: RESISTORS\FIXED; Project: GOLDEN-I LITE; RoHS: RoHS; Temperature: -55°C+125°C; Tolerance: 1%; Voltage: NA; Wattage: 1/20W; Weight: 0.17mg; Datasheet: Y:\MIS_DATABASE\DATASHEETS\RESISTORS\RCXXXXL-SER_MAR18.PDF
R582 = RESISTOR: RES 0E 1/20W 5% 0201; Assembly_Instruction: DNI; Chkd/date: NAVEED/301214; Crtd /date: MUDDU/120710; Custom_Duty: 15%; Customs_HS_Code: 85332119; Distributor_name: DIGIKEY; Distributor_part_number: 311-0.0NCT-ND; Footprint Path: Y:\MIS_DATABASE\Library\ALTIUM_TOOL\PCB_FOOTPRINTS\Altium_Footprint_Lib.PcbLib; Height: 0.26MM; Library Path: Y:\MIS_DATABASE\Library\ALTIUM_TOOL\SCHEMATICS_PARTS\MS_DISCRETE_Library.schlib; Mfr_name: YAGEO AMERICA; Mfr_part_number: RC0201JR-070RL; Mistral Part No: 110010070067-R; Package: 0201; Part_type: RESISTORS\FIXED; Project: PB_BUGBASE; RoHS: RoHS; Temperature: -55°C+125°C; Tolerance: 5%; Voltage: NA; Wattage: 1/20W; Weight: 0.17mg; Datasheet: Y:\MIS_DATABASE\DATASHEETS\RESISTORS\RCXXXXL-SER_MAR18.PDF
R595 = RESISTOR: RES 8.2K 1/20W 1% 0201; Chkd/date: SUHAS/230910; Crtd /date: MUDDU/060710; Custom_Duty: 15%; Customs_HS_Code: 85332119; Distributor_name: DIGIKEY; Distributor_part_number: 541-8.20KAABCT-ND; Footprint Path: Y:\MIS_DATABASE\Library\ALTIUM_TOOL\PCB_FOOTPRINTS\Altium_Footprint_Lib.PcbLib; Height: 0.28MM; Library Path: Y:\MIS_DATABASE\Library\ALTIUM_TOOL\SCHEMATICS_PARTS\MS_DISCRETE_Library.schlib; Mfr_name: VISHAY; Mfr_part_number: CRCW02018K20FKED; Mistral Part No: 110010070001-R; Package: 0201; Part_type: RESISTORS\FIXED; Project: PB_BUGBASE; RoHS: RoHS; Temperature: -55°C+155°C; Tolerance: 1%; Voltage: NA; Wattage: 1/20W; Weight: 0.17mg; Datasheet: Y:\MIS_DATABASE\DATASHEETS\RESISTORS\CRCW0201.PDF
TP43 TP93-TP96 = TESTPOINT: TESTPOINT CIR 20 SMD; Chkd/date: SHREESHAIL/171006; Crtd /date: MAZHAR/171006; Custom_Duty: NA; Customs_HS_Code: NA; Distributor_name: NA; Distributor_part_number: NA; Footprint Path: Y:\MIS_DATABASE\Library\ALTIUM_TOOL\PCB_FOOTPRINTS\Altium_Footprint_Lib.PcbLib; Height: NA; Library Path: Y:\MIS_DATABASE\Library\ALTIUM_TOOL\SCHEMATICS_PARTS\MS_DISCRETE_Library.schlib; MECHANICAL 3D STEP FILE: NA; Mfr_name: LOCAL; Mistral Part No: NA; Package: SMD; Project: BT MODULE_CSRBC04; RoHS: NA; Temperature: NA; Tolerance: NA; Voltage: NA; Wattage: NA; Weight: NA; Datasheet: NA
U1 = OSC4_ASFL3: OSC 32.768KHz CMOS SMD; Chkd/date: ALVY/030620; Crtd /date: MANIRAJA/030620; Custom_Duty: 24%; Customs_HS_Code: 85437099; Distributor_name: DIGIKEY; Distributor_part_number: XC3154CT-ND; Footprint Path: Y:\MIS_DATABASE\Library\ALTIUM_TOOL\PCB_FOOTPRINTS\Altium_Footprint_Lib.PcbLib; Height: 1.00MM; Library Path: Y:\MIS_DATABASE\Library\ALTIUM_TOOL\SCHEMATICS_PARTS\MS_DISCRETE_Library.schlib; Mfr_name: ECS INC; Mfr_part_number: ECS-327MVATX-2-CN-TR; Mistral Part No: 130020060007-R; Package: SMD; Part_type: OSCILLATORS; Project: JETSON_CARRIER_BRD; RoHS: RoHS; Temperature: -40°C+85°C; Tolerance: NA; Voltage: NA; Wattage: NA; Weight: NA; Datasheet: Y:\MIS_DATABASE\DATASHEETS\MISC\CRY_OSC\ECS-327MVATX.PDF
U2 = TXS0102DQX_SON8: IC 2-BIT BI-DIR VOLTAGE-LEVEL TRANSLATOR FOR OPEN-DRAIN AND PUSH-PULL X2SON8; Chkd/date: MANIRAJA/010719; Crtd /date: CHAITHANYA230512; Custom_Duty: 15%; Customs_HS_Code: 85423100; Distributor_name: DIGIKEY; Distributor_part_number: 296-28368-1-ND; Footprint Path: Y:\MIS_DATABASE\Library\ALTIUM_TOOL\PCB_FOOTPRINTS\Altium_Footprint_Lib.PcbLib; Height: 0.40MM; Library Path: Y:\MIS_DATABASE\Library\ALTIUM_TOOL\SCHEMATICS_PARTS\MS_MISCINTERFACE_Library.schlib; Mfr_name: TEXAS INSTRUMENTS; Mistral Part No: 141012050010-R; Package: X2SON8; Part_type: ICS\INTERFACE\LEVEL TRANSLATOR; Project: GEN_3-8_DB; RoHS: RoHS; Temperature: -40°C+85°C; Tolerance: NA; Voltage: NA; Wattage: NA; Weight: 1.2mg; Datasheet: Y:\MIS_DATABASE\DATASHEETS\ICS\INTERFACE\TXS0102-SER.PDF
C112 C344 C345 C351 = CAP: CAP CERAMIC 0.1uF 50V 10% X7R 0402; Alt_Mfr_name: YAGEO AMERICA; Alt_Mfr_part_number: CC0402KRX5R8BB104; Chkd/date: MANIRAJA/261020; Crtd /date: ALVY/211020; Custom_Duty: 15%; Customs_HS_Code: 85322990; Distributor_name: DIGIKEY; Distributor_part_number: 490-10700-1-ND; Footprint Path: Y:\MIS_DATABASE\Library\ALTIUM_TOOL\PCB_FOOTPRINTS\Altium_Footprint_Lib.PcbLib; Height: 0.55MM; Library Path: Y:\MIS_DATABASE\Library\ALTIUM_TOOL\SCHEMATICS_PARTS\MS_DISCRETE_Library.schlib; Mfr_name: MURATA; Mfr_part_number: GRM155R71H104KE14D; Mistral Part No: 120011100014-R; Package: 0402; Part_type: CAPACITORS\CERAMIC; Project: J7_CP; RoHS: RoHS; Temperature: -55°C+125°C; Tolerance: 10%; Voltage: 50V; Wattage: NA; Weight: 3.1mg; Datasheet: Y:\MIS_DATABASE\DATASHEETS\CAPACITORS\GRM155R71H104KE14.PDF
C352 C365 = CAP: CAP CERAMIC 2.2uF 25V 10% X5R 0402; Chkd/date: ALVY/010721; Crtd /date: MANIRAJA/010721; Custom_Duty: 15%; Customs_HS_Code: 85322990; Distributor_name: DIGIKEY; Distributor_part_number: 490-12703-1-ND; Footprint Path: Y:\MIS_DATABASE\Library\ALTIUM_TOOL\PCB_FOOTPRINTS\Altium_Footprint_Lib.PcbLib; Height: 0.70MM; Library Path: Y:\MIS_DATABASE\Library\ALTIUM_TOOL\SCHEMATICS_PARTS\MS_DISCRETE_Library.schlib; Mfr_name: MURATA; Mfr_part_number: GRM155R61E225KE11D; Mistral Part No: 120015120001-R; Package: 0402; Part_type: CAPACITORS\CERAMIC; Project: TI_AM263X_CC; RoHS: RoHS; Temperature: -55°C+85°C; Tolerance: 10%; Voltage: 25V; Wattage: NA; Weight: 1.5mg; Datasheet: Y:\MIS_DATABASE\DATASHEETS\CAPACITORS\GRM155R61E225KE11.PDF
R51 R109 R138 R272 R398 R400 = RESISTOR: RES 49.9K 1/20W 1% 0201; Chkd/date: PRAVEEN/080922; Crtd /date: TAMILARASU/080922; Custom_Duty: 15%; Customs_HS_Code: 85332119; Distributor_name: DIGIKEY; Distributor_part_number: P123047CT-ND; Footprint Path: Y:\MIS_DATABASE\Library\ALTIUM_TOOL\PCB_FOOTPRINTS\Altium_Footprint_Lib.PcbLib; Height: 0.26MM; Library Path: Y:\MIS_DATABASE\Library\ALTIUM_TOOL\SCHEMATICS_PARTS\MS_DISCRETE_Library.schlib; Mfr_name: PANASONIC-ECG; Mfr_part_number: ERJ-1GNF4992C; Mistral Part No: 110022090006-R; Package: 0201; Part_type: RESISTORS\FIXED; Project: SK AM62Q LP EVM BRD; RoHS: RoHS; Temperature: -55°C+125°C; Tolerance: 1%; Voltage: NA; Wattage: 1/20W; Weight: 0.15mg; Datasheet: Y:\MIS_DATABASE\DATASHEETS\RESISTORS\PAN-ERJSER_NOV17.PDF
R91 = RESISTOR: RES 22E 1/20W 1% 0201; Chkd/date: PRAVEEN/080922; Crtd /date: TAMILARASU/080922; Custom_Duty: 15%; Customs_HS_Code: 85332119; Distributor_name: DIGIKEY; Distributor_part_number: P122843CT-ND; Footprint Path: Y:\MIS_DATABASE\Library\ALTIUM_TOOL\PCB_FOOTPRINTS\Altium_Footprint_Lib.PcbLib; Height: 0.26MM; Library Path: Y:\MIS_DATABASE\Library\ALTIUM_TOOL\SCHEMATICS_PARTS\MS_DISCRETE_Library.schlib; Mfr_name: PANASONIC-ECG; Mfr_part_number: ERJ-1GNF22R0C; Mistral Part No: 110022090007-R; Package: 0201; Part_type: RESISTORS\FIXED; Project: SK AM62Q LP EVM BRD; RoHS: RoHS; Temperature: -55°C+125°C; Tolerance: 1%; Voltage: NA; Wattage: 1/20W; Weight: 0.15mg; Datasheet: Y:\MIS_DATABASE\DATASHEETS\RESISTORS\PAN-ERJSER_NOV17.PDF
R107 R108 R110-R114 R401 = RESISTOR: RES 49.9K 1/20W 1% 0201; Assembly_Instruction: DNI; Chkd/date: PRAVEEN/080922; Crtd /date: TAMILARASU/080922; Custom_Duty: 15%; Customs_HS_Code: 85332119; Distributor_name: DIGIKEY; Distributor_part_number: P123047CT-ND; Footprint Path: Y:\MIS_DATABASE\Library\ALTIUM_TOOL\PCB_FOOTPRINTS\Altium_Footprint_Lib.PcbLib; Height: 0.26MM; Library Path: Y:\MIS_DATABASE\Library\ALTIUM_TOOL\SCHEMATICS_PARTS\MS_DISCRETE_Library.schlib; Mfr_name: PANASONIC-ECG; Mfr_part_number: ERJ-1GNF4992C; Mistral Part No: 110022090006-R; Package: 0201; Part_type: RESISTORS\FIXED; Project: SK AM62Q LP EVM BRD; RoHS: RoHS; Temperature: -55°C+125°C; Tolerance: 1%; Voltage: NA; Wattage: 1/20W; Weight: 0.15mg; Datasheet: Y:\MIS_DATABASE\DATASHEETS\RESISTORS\PAN-ERJSER_NOV17.PDF
U21 = MTFC16GAPALBH_TFBGA153: IC 16GB e-MMC MEMORY TFBGA153; Chkd/date: MANIRAJA/070220; Crtd /date: ALVY/070220; Custom_Duty: 15%; Customs_HS_Code: 85423100; Distributor_name: DIGIKEY; Distributor_part_number: MTFC16GAPALBH-IT-ND; Footprint Path: Y:\MIS_DATABASE\Library\ALTIUM_TOOL\PCB_FOOTPRINTS\Altium_Footprint_Lib.PcbLib; Height: 1.10MM; Library Path: Y:\MIS_DATABASE\Library\ALTIUM_TOOL\SCHEMATICS_PARTS\MS_MISCMEMORY_Library.schlib; Mfr_name: MICRON; Mistral Part No: 141120020001-R; Package: TFBGA153; Part_type: ICS\DIGITAL\MEMORY; Project: TI_MAXIE_CPB; RoHS: RoHS; Temperature: -40°C+85°C; Tolerance: NA; Voltage: NA; Wattage: NA; Weight: NA; Datasheet: Y:\MIS_DATABASE\DATASHEETS\ICS\MEMORY\MTFCXX-IT.PDF
U25 = SN74LVC1G08DBVRE4_SOT23-5: IC SINGLE 2-INPUT POSITIVE AND GATE SOT23-5; Chkd/date: SUHAS/221010; Crtd /date: USMAN/151008; Custom_Duty: 15%; Customs_HS_Code: 85423100; Distributor_name: DIGIKEY; Distributor_part_number: SN74LVC1G08DBVRE4-ND; Height: 1.45MM; Mfr_name: TEXAS INSTRUMENTS; Mistral Part No: 141009060026-R; Part_type: ICS\DIGITAL\GATES; Project: KHAN_MAIN; RoHS: Sb/ Br FREE; Temperature: -40°C+85°C; Datasheet: Y:\MIS_DATABASE\DATASHEETS\ICS\DIGITAL\GATES\SN74LVC1G08.PDF
U12 = AM62Q_SoC_FCBGA441: IC AM62Q SoC MICROPROCESSOR FCBGA441; Chkd/date: MANIRAJA/211021; Crtd /date: ALVY/211021; Custom_Duty: 15%; Customs_HS_Code: 85423100; Distributor_name: NA; Distributor_part_number: NA; Footprint Path: Y:\MIS_DATABASE\Library\ALTIUM_TOOL\PCB_FOOTPRINTS\Altium_Footprint_Lib.PcbLib; Height: 2.57MM; Library Path: Y:\MIS_DATABASE\Library\ALTIUM_TOOL\SCHEMATICS_PARTS\MS_MICROPROCESSOR_Library.schlib; Mfr_name: TEXAS INSTRUMENTS; Mistral Part No: 141221100001; Package: FCBGA441; Part_type: ICS\DIGITAL\MICROPROCESSOR; Project: TI_AM62Q_BRD; RoHS: NA; Temperature: NA; Tolerance: NA; Voltage: NA; Wattage: NA; Weight: NA; Datasheet: Y:\MIS_DATABASE\DATASHEETS\ICS\DIGITAL\MICROCONTROLLER\AM62Q-SoC.PDF

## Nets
DGND: C3.1 C5.2 C7.1 C26.2 C27.2 C32.2 C33.2 C34.1 C35.2 C36.2 C37.2 C71.2 C75.2 C86.2 C112.2 C176.1 C177.2 C188.1 C189.2 C236.2 C237.2 C238.2 C242.2 C244.2 C247.2 C248.2 C249.2 C252.2 C253.2 C254.2 C256.2 C258.2 C259.2 C260.1 C261.2 C262.2 C263.2 C264.2 C267.2 C268.2 C269.2 C270.2 C271.2 C272.2 C273.2 C279.2 C286.2 C288.2 C289.2 C290.2 C291.2 C292.2 C293.2 C294.2 C297.2 C298.2 C301.2 C303.2 C305.1 C308.2 C309.2 C314.2 C316.2 C343.2 C344.2 C345.2 C348.2 C349.2 C351.2 C352.2 C365.2 J2.1(GND) J2.7(GND) J2.18(GND) J2.33(GND) J2.39(GND) J2.45(GND) J2.51(GND) J2.57(GND) J2.63(GND) J2.69(GND) J2.75(GND) J2.SH1 J2.SH2 R5.1 R51.2 R124.2 R272.2 R281.1 R400.2 U1.2(GND) U2.4(GND) U12.A1(VSS) U12.A4(VSS) U12.A21(VSS) U12.AA1(VSS) U12.AA9(VSS) U12.AA12(VSS) U12.AA15(VSS) U12.AA21(VSS) U12.D4(VSS) U12.D11(VSS) U12.D19(VSS) U12.E2(VSS) U12.F4(VSS) U12.F9(VSS) U12.F11(VSS) U12.F13(VSS) U12.F15(VSS) U12.G6(VSS) U12.G9(VSS) U12.G16(VSS) U12.H1(VSS) U12.H6(VSS) U12.H13(VSS) U12.J6(VSS) U12.J10(VSS) U12.J12(VSS) U12.J14(VSS) U12.J16(VSS) U12.K3(VSS) U12.K6(VSS) U12.K8(VSS) U12.K13(VSS) U12.L1(VSS) U12.L6(VSS) U12.L10(VSS) U12.L12(VSS) U12.L14(VSS) U12.L16(VSS) U12.M6(VSS) U12.M9(VSS) U12.M11(VSS) U12.M16(VSS) U12.M18(VSS) U12.N6(VSS) U12.N12(VSS) U12.N14(VSS) U12.P1(VSS) U12.P3(VSS) U12.P6(VSS) U12.P10(VSS) U12.P13(VSS) U12.P15(VSS) U12.P16(VSS) U12.R5(VSS) U12.R7(VSS) U12.R8(VSS) U12.R16(VSS) U12.T3(VSS) U12.T6(VSS) U12.T7(VSS) U12.T9(VSS) U12.T10(VSS) U12.T12(VSS) U12.T15(VSS) U12.U5(VSS) U12.U8(VSS) U12.U10(VSS) U12.U13(VSS) U12.V11(VSS) U12.V14(VSS) U12.V19(VSS) U12.W7(VSS) U12.W10(VSS) U12.W13(VSS) U12.Y3(VSS) U12.Y4(VSS) U12.Y6(VSS) U12.Y11(VSS) U12.Y14(VSS) U21.A6(VSS) U21.C4(VSSQ) U21.E7(VSS) U21.G5(VSS) U21.H10(VSS) U21.J5(VSS) U21.K8(VSS) U21.N2(VSSQ) U21.N5(VSSQ) U21.P4(VSSQ) U21.P6(VSSQ) U25.3(GND) ; also on sheet 1 2 3 4 13 14 15 16 17 21 22 23 24 25 26 27 28 29 30 31 32 33 34 35 36 37 38 39 40 41 42 43
VCC1V8_SYS: C3.2 C112.1 C345.1 C365.1 R107.1 R108.1 R109.1 R110.1 R111.1 R112.1 R113.1 R114.1 R138.1 R262.2 R282.2 R283.2 R284.2 R285.2 R286.2 R287.2 R333.2 R398.1 R401.1 R582.1 U2.1(VCCA) U21.C6(VCCQ) U21.M4(VCCQ) U21.N4(VCCQ) U21.P3(VCCQ) U21.P5(VCCQ) U25.5(VCC) ; also on sheet 4 16 22 25 34 37 39 40 42
VCC_3V3_SYS: C7.2 C176.2 C177.1 C188.2 C189.1 C351.1 C352.1 J2.2(3-3V) J2.4(3-3V) J2.72(3-3V) J2.74(3-3V) R141.2 R257.2 R258.2 R279.2 R581.1 U2.8(VCCB) U21.E6(VCC) U21.F5(VCC) U21.J10(VCC) U21.K9(VCC) ; also on sheet 1 4 15 16 21 23 24 26 27 29 30 31 32 33 34 36 37 38 39 40 41 42 43
VDD_CORE: C26.1 C27.1 C32.1 C242.1 C249.1 C253.1 C254.1 C256.1 C258.1 C262.1 C263.1 C264.1 C268.1 C269.1 C271.1 C273.1 C286.1 C292.1 C297.1 C303.1 ; also on sheet 16 17
VDD_LPDDR4: C298.1 C301.1 C308.1 C309.1 C314.1 C316.1 C348.1 C349.1 ; also on sheet 3 16 17
VDDIM: C343.1 C344.1 U21.C2(VDDIM)
VDDR_CORE: C33.1 C34.2 C35.1 C36.1 C37.1 C270.1 C288.1 C294.1 ; also on sheet 16 17 36
BT_EN_SOC: J2.54(W_DISABLE2#) R258.1 ; also on sheet 34
BT_UART_WAKE_SOC: J2.20(UART_WAKE#) R279.1 ; also on sheet 39
COM_SDIO_CMD: J2.11(SDIO_CMD) R275.1 R285.1
COM_SDIO_D0: J2.13(SDIO_DATA0) R277.1 R287.1
COM_SDIO_D1: J2.15(SDIO_DATA1) R276.1 R286.1
COM_SDIO_D2: J2.17(SDIO_DATA2) R274.1 R284.1
COM_SDIO_D3: J2.19(SDIO_DATA3) R273.1 R283.1
eMMC_RSTn: R138.2 U21.K5(RST_N) U25.4(Y)
GPIO_eMMC_RSTn: R141.1 U25.1(A) ; also on sheet 39
HFOSC0_CLKOUT_32K: R2.1 ; also on sheet 32
M2_LED1#: J2.6(LED_1#) TP94.1(TP)
M2_LED2#: J2.16(LED_2#) TP93.1(TP)
MCASP1_ACLKX_BT: J2.8(PCM_CLK/I2S_SCK) ; also on sheet 39
MCASP1_AFSX_BT: J2.10(PCM_SYNC/I2S_WS) ; also on sheet 39
MCASP1_AXR0_BT: J2.12(PCM_IN/I2S_SD_IN) R281.2 ; also on sheet 39
MCASP1_AXR2_BT: J2.14(PCM_OUT/I2S_SD_OUT) ; also on sheet 39
MMC0_CLK: R91.1 R400.1 R401.2 U21.M6(CLK)
MMC1_CLK: R49.1 R51.1 ; also on sheet 21
MMC1_CLK_R: R49.2 U12.A20(MMC1_CLK)
MMC1_CMD: U12.C18(MMC1_CMD) ; also on sheet 21
MMC1_D0: U12.A19(MMC1_DAT0) ; also on sheet 21
MMC1_D1: U12.B19(MMC1_DAT1) ; also on sheet 21
MMC1_D2: U12.B20(MMC1_DAT2) ; also on sheet 21
MMC1_D3: U12.C19(MMC1_DAT3) ; also on sheet 21
MMC1_SDCD: U12.C15(MMC1_SDCD) ; also on sheet 21
MMC2_CLK: J2.9(SDIO_CLK/SYSCLK) R40.2 R272.1 R282.1
MMC2_CMD: R275.2 U12.C21(MMC2_CMD)
MMC2_D0: R277.2 U12.B21(MMC2_DAT0)
MMC2_D1: R276.2 U12.D21(MMC2_DAT1)
MMC2_D2: R274.2 U12.E19(MMC2_DAT2)
MMC2_D3: R273.2 U12.E20(MMC2_DAT3)
RESETSTATz: U25.2(B) ; also on sheet 1 4 21 22 24 27 32 37 38 39 40 41 42
SLOW_CLK: J2.50(SUSCLK_32kHz) R1.2 R2.2
SOC_DVDD1V8: C86.1 C237.1 C238.1 C248.1 C293.1 C305.2 ; also on sheet 3 16 17
SoC_DVDD3V3: C71.1 C75.1 C236.1 C244.1 C247.1 C252.1 C259.1 C260.2 C261.1 C267.1 C272.1 C279.1 C289.1 C290.1 C291.1 ; also on sheet 16 17
SOC_GPIO1_49: U12.B15(MMC1_SDWP) ; also on sheet 38
SOC_MMC0_CLK: R91.2 U12.Y1(MMC0_CLK)
SOC_MMC0_CMD: R398.2 U12.V3(MMC0_CMD) U21.M5(CMD)
SOC_MMC0_DAT0: R109.2 U12.V2(MMC0_DAT0) U21.A3(DAT0)
SOC_MMC0_DAT1: R111.2 U12.V1(MMC0_DAT1) U21.A4(DAT1)
SOC_MMC0_DAT2: R113.2 U12.W2(MMC0_DAT2) U21.A5(DAT2)
SOC_MMC0_DAT3: R107.2 U12.W1(MMC0_DAT3) U21.B2(DAT3)
SOC_MMC0_DAT4: R108.2 U12.Y2(MMC0_DAT4) U21.B3(DAT4)
SOC_MMC0_DAT5: R110.2 U12.W3(MMC0_DAT5) U21.B4(DAT5)
SOC_MMC0_DAT6: R112.2 U12.W4(MMC0_DAT6) U21.B5(DAT6)
SOC_MMC0_DAT7: R114.2 U12.V4(MMC0_DAT7) U21.B6(DAT7)
SoC_MMC2_CLK: R40.1 U12.E21(MMC2_CLK)
SOC_UART1_CTS_BT: J2.34(UART_CTS) ; also on sheet 37
SOC_UART1_RTS_BT: J2.36(UART_RTS) ; also on sheet 37
SOC_UART1_RX_BT: J2.22(UART_RXD) ; also on sheet 37
SOC_UART1_TX_BT: R261.2 ; also on sheet 37
SoC_WLAN_SDIO_RST: U2.7(B1) ; also on sheet 39
USB_DM: J2.5(USB_D-) TP95.1(TP)
USB_DP: J2.3(USB_D+) TP96.1(TP)
WL_LT_EN: R595.1 ; also on sheet 39
WLAN_EN: J2.56(W_DISABLE1#) R257.1 U2.6(B2)
WLAN_EN_SOC: U2.3(A2) U12.D20(MMC2_SDCD)
WLAN_IRQ: J2.62(ALERT#) R333.1 U12.C20(MMC2_SDWP)
WLAN_SDIO_RST: J2.23(SDIO_RESET#/TX_BLANKING) R262.1 U2.2(A1)
N15951745: C5.1 R581.2 R582.2 U1.1(TRI-STATE) U1.4(VDD)
N15952254: R1.1 U1.3(OUTPUT)
N16878497: R124.1 TP43.1(TP) U21.H5(DS)
N21029653: R5.2 R595.2 U2.5(OE)
N21608525: J2.32(UART_TXD) R261.1

Not connected (* = marked no-connect by the designer): J2 21(SDIO_WAKE#)* 35(PETP0)* 37(PETN0)* 38(VENDOR_DEFINED1)* 40(VENDOR_DEFINED2)* 41(PERP0)* 42(VENDOR_DEFINED3)* 43(PERN0)* 44(COEX3)* 46(COEX_RXD)* 47(REFCLKP0)* 48(COEX_TXD)* 49(REFCLKN0)* 52(PERST0#)* 53(CLKREQ0#)* 55(PEWAKE0#)* 58(I2C_DATA)* 59(RESERVED/PETP1)* 60(I2C_CLK)* 61(RESERVED/PETN1)* 64(RESERVED)* 65(RESERVED/PERP1)* 66(UIM_SWP/PERST1#)* 67(RESERVED/PERN1)* 68(UIM_POWER_SNK/CLKREQ1#)* 70(UIM_POWER_SRC/GPIO1/PEWAKE#)* 71(RESERVED/REFCLKP1)* 73(RESERVED/REFCLKN1)* SH3*; U21 A1(NC1)* A2(NC2)* A7(RFU1)* A8(NC3)* A9(NC4)* A10(NC5)* A11(NC6)* A12(NC7)* A13(NC8)* A14(NC9)* B1(NC10)* B7(NC11)* B8(NC12)* B9(NC13)* B10(NC14)* B11(NC15)* B12(NC16)* B13(NC17)* B14(NC18)* C1(NC19)* C3(NC20)* C5(NC21)* C7(NC22)* C8(NC23)* C9(NC24)* C10(NC25)* C11(NC26)* C12(NC27)* C13(NC28)* C14(NC29)* D1(NC30)* D2(NC31)* D3(NC32)* D4(NC33)* D12(NC34)* D13(NC35)* D14(NC36)* E1(NC37)* E2(NC38)* E3(NC39)* E5(RFU2)* E8(VSF1)* E9(VSF2)* E10(VSF3)* E12(NC40)* E13(NC41)* E14(NC42)* F1(NC43)* F2(NC44)* F3(NC45)* F10(VSF4)* F12(NC46)* F13(NC47)* F14(NC48)* G1(NC49)* G2(NC50)* G3(NC51)* G10(VSF5)* G12(NC52)* G13(NC53)* G14(NC54)* H1(NC55)* H2(NC56)* H3(NC57)* H12(NC58)* H13(NC59)* H14(NC60)* J1(NC61)* J2(NC62)* J3(NC63)* J12(NC64)* J13(NC65)* J14(NC66)* K1(NC67)* K2(NC68)* K3(NC69)* K6(RFU3)* K7(RFU4)* K10(VSF6)* K12(NC70)* K13(NC71)* K14(NC72)* L1(NC73)* L2(NC74)* L3(NC75)* L12(NC76)* L13(NC77)* L14(NC78)* M1(NC79)* M2(NC80)* M3(NC81)* M7(NC82)* M8(NC83)* M9(NC84)* M10(NC85)* M11(NC86)* M12(NC87)* M13(NC88)* M14(NC89)* N1(NC90)* N3(NC91)* N6(NC92)* N7(NC93)* N8(NC94)* N9(NC95)* N10(NC96)* N11(NC97)* N12(NC98)* N13(NC99)* N14(NC100)* P1(NC101)* P2(NC102)* P7(NC103)* P8(NC104)* P9(NC105)* P10(VSF7)* P11(NC106)* P12(NC107)* P13(NC108)* P14(NC109)*

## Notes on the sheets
sheet 18
- SOC POWER DECAPS
- Place one 0.1uF cap near each Pin
- Place one 0.1uF cap near each Pin
- Place one 0.1uF cap near each Pin
- Place one 0.1uF cap near each Pin
- Place one 0.1uF cap near each Pin
- SOC VSS
sheet 19
- M.2 INTERFACE - SDIO
- As per the connector specification
  1 Amps will support per pin
- 1.8 V
- 1.8 V
- 3.3 V
- SoC_MAIN_UART1_RXD
- 1.8 V
- SoC_MAIN_UART1_TXD
- SoC_MAIN_UART1_CTS
- SoC_MAIN_UART1_RTS
- 3.3V
- 3.3 V
- 1.8 V
- WILINK LEVEL TRANSLATORS
- Place R1 & R2
  close to each other
  to  avoid stub.
- Design Note: WL_LT_EN = Active High
sheet 20
- SOC - MMC Interface
- eMMC FLASH
- GPIO1_49
- eMMC FLASH RESET
- Design Note: eMMC_RSTn Active low
  s/w control
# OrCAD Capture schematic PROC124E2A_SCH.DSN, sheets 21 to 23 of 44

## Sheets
21 19. SD CARD INTERFACE: size C; title: SD CARD INTERFACE
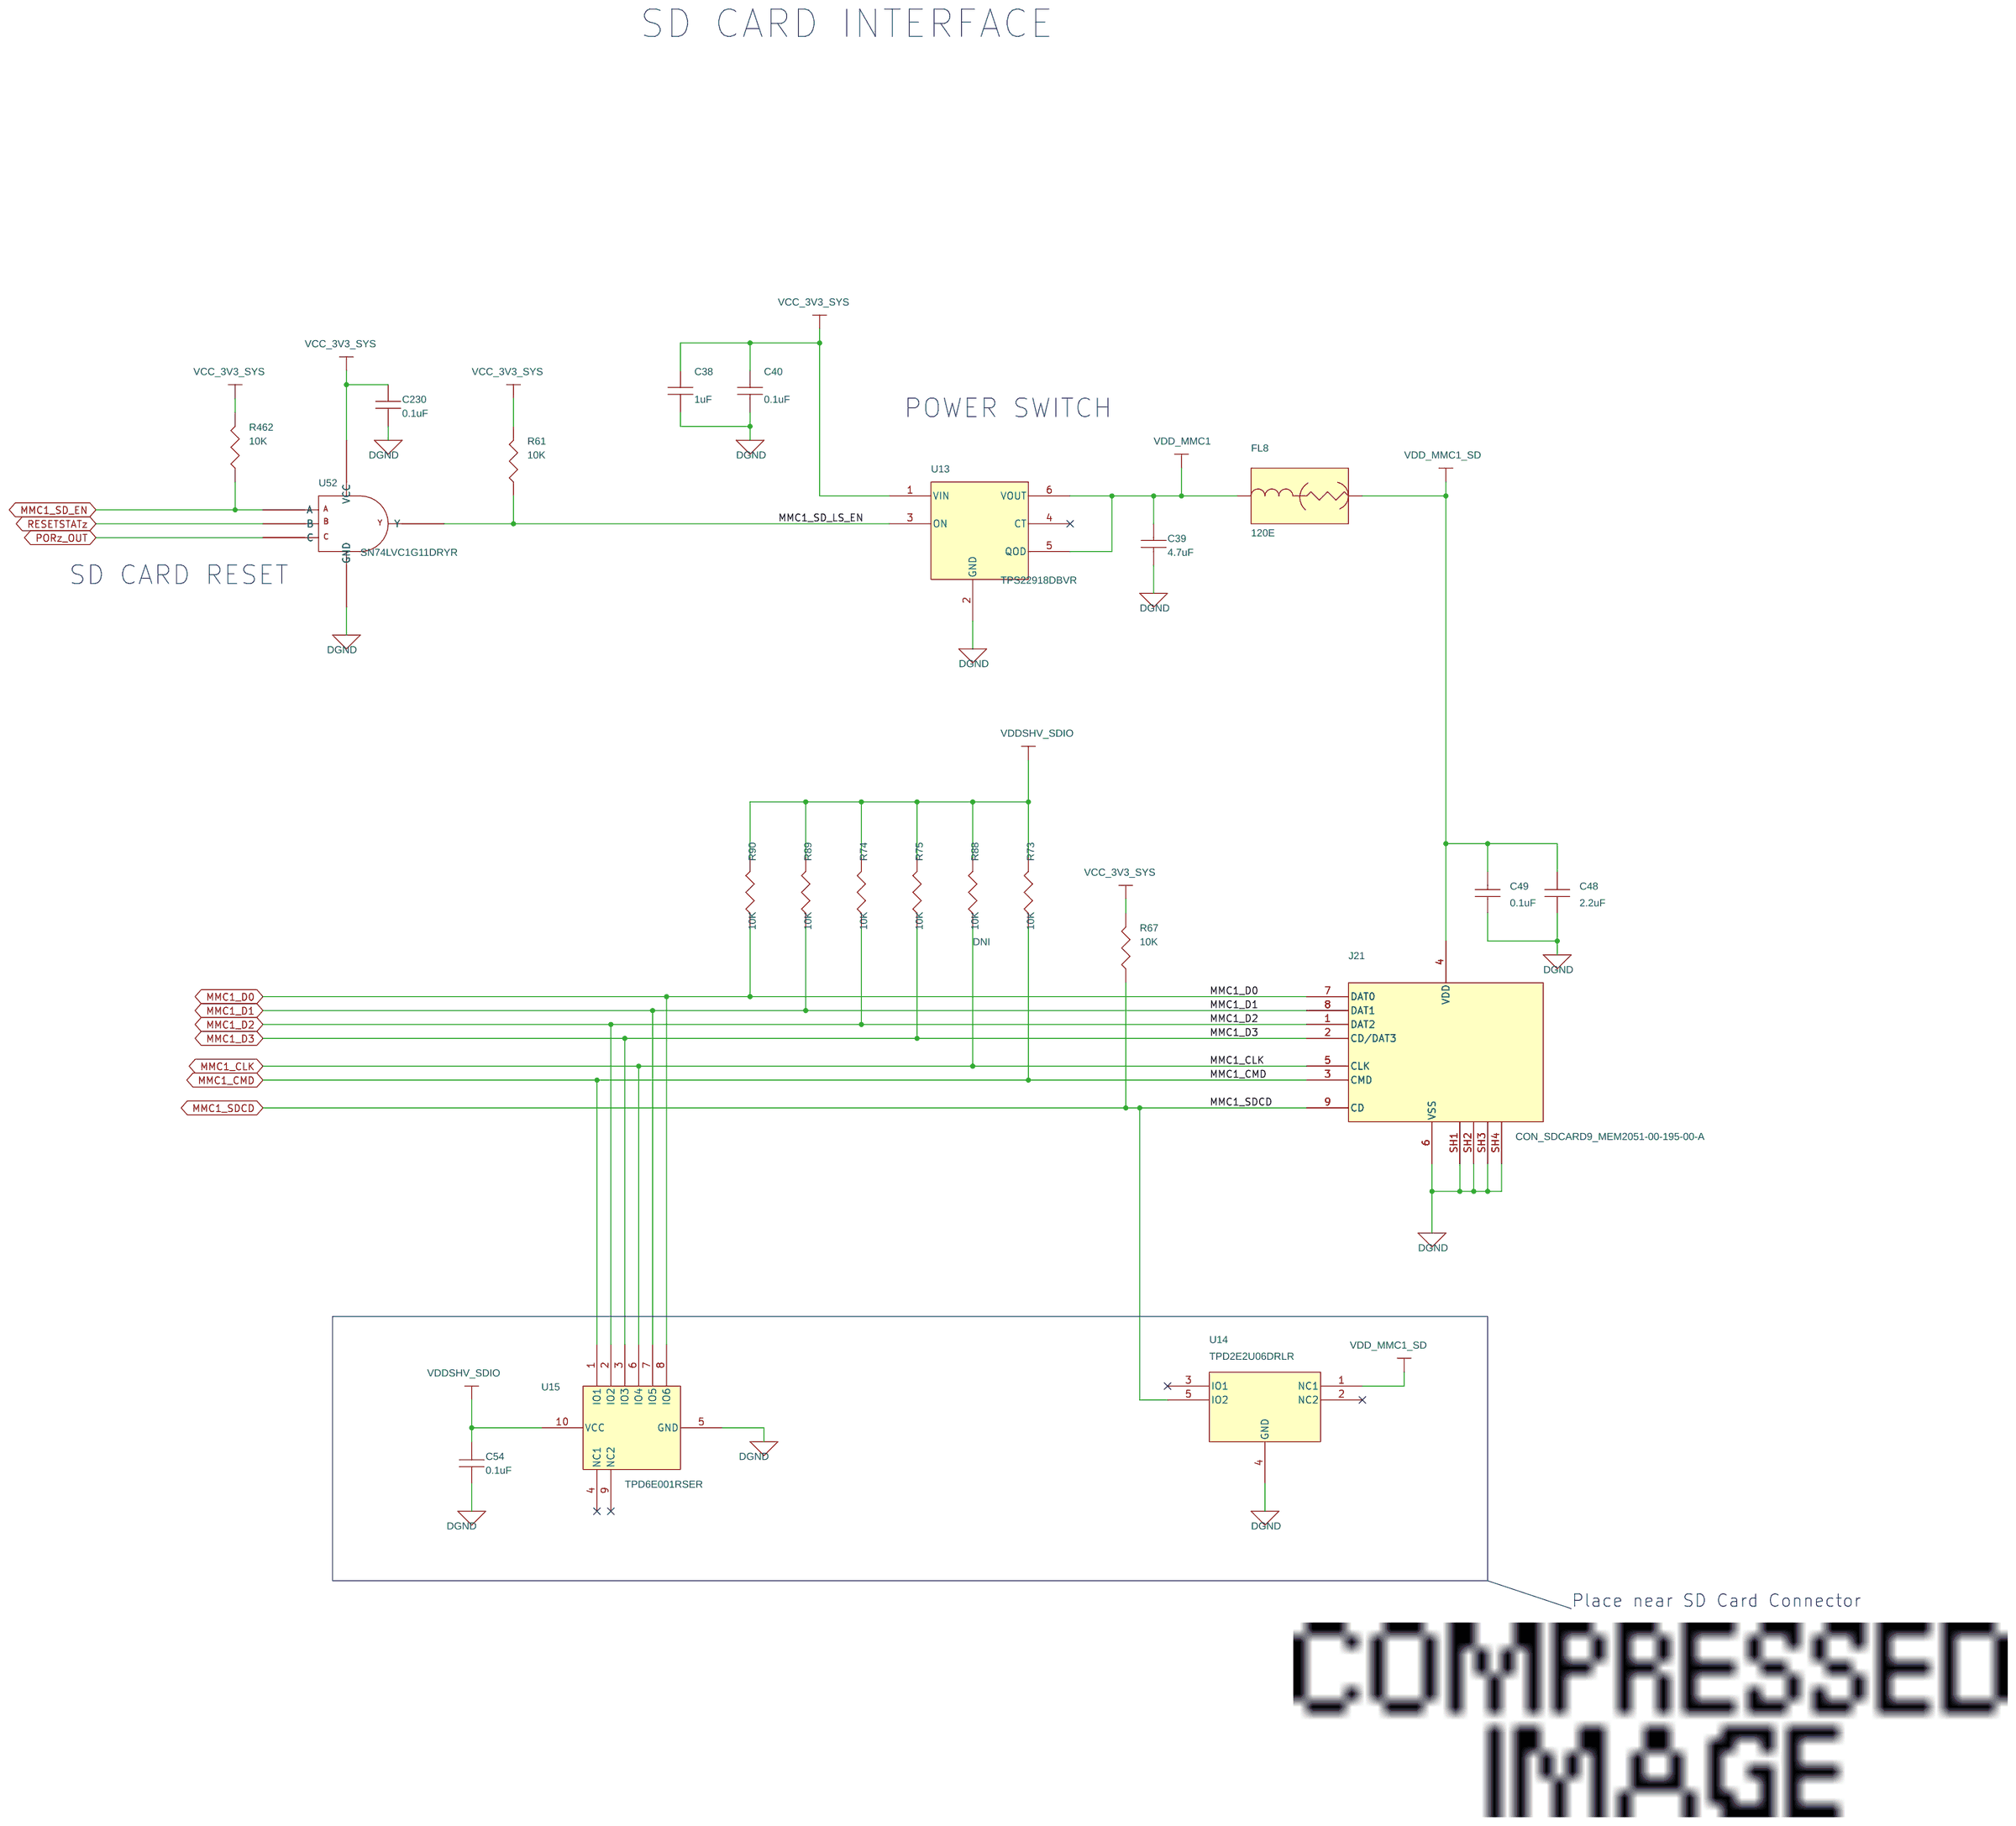
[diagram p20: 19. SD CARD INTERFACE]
22 20. OSPI INTERFACE: size C; title: OSPI INTERFACE
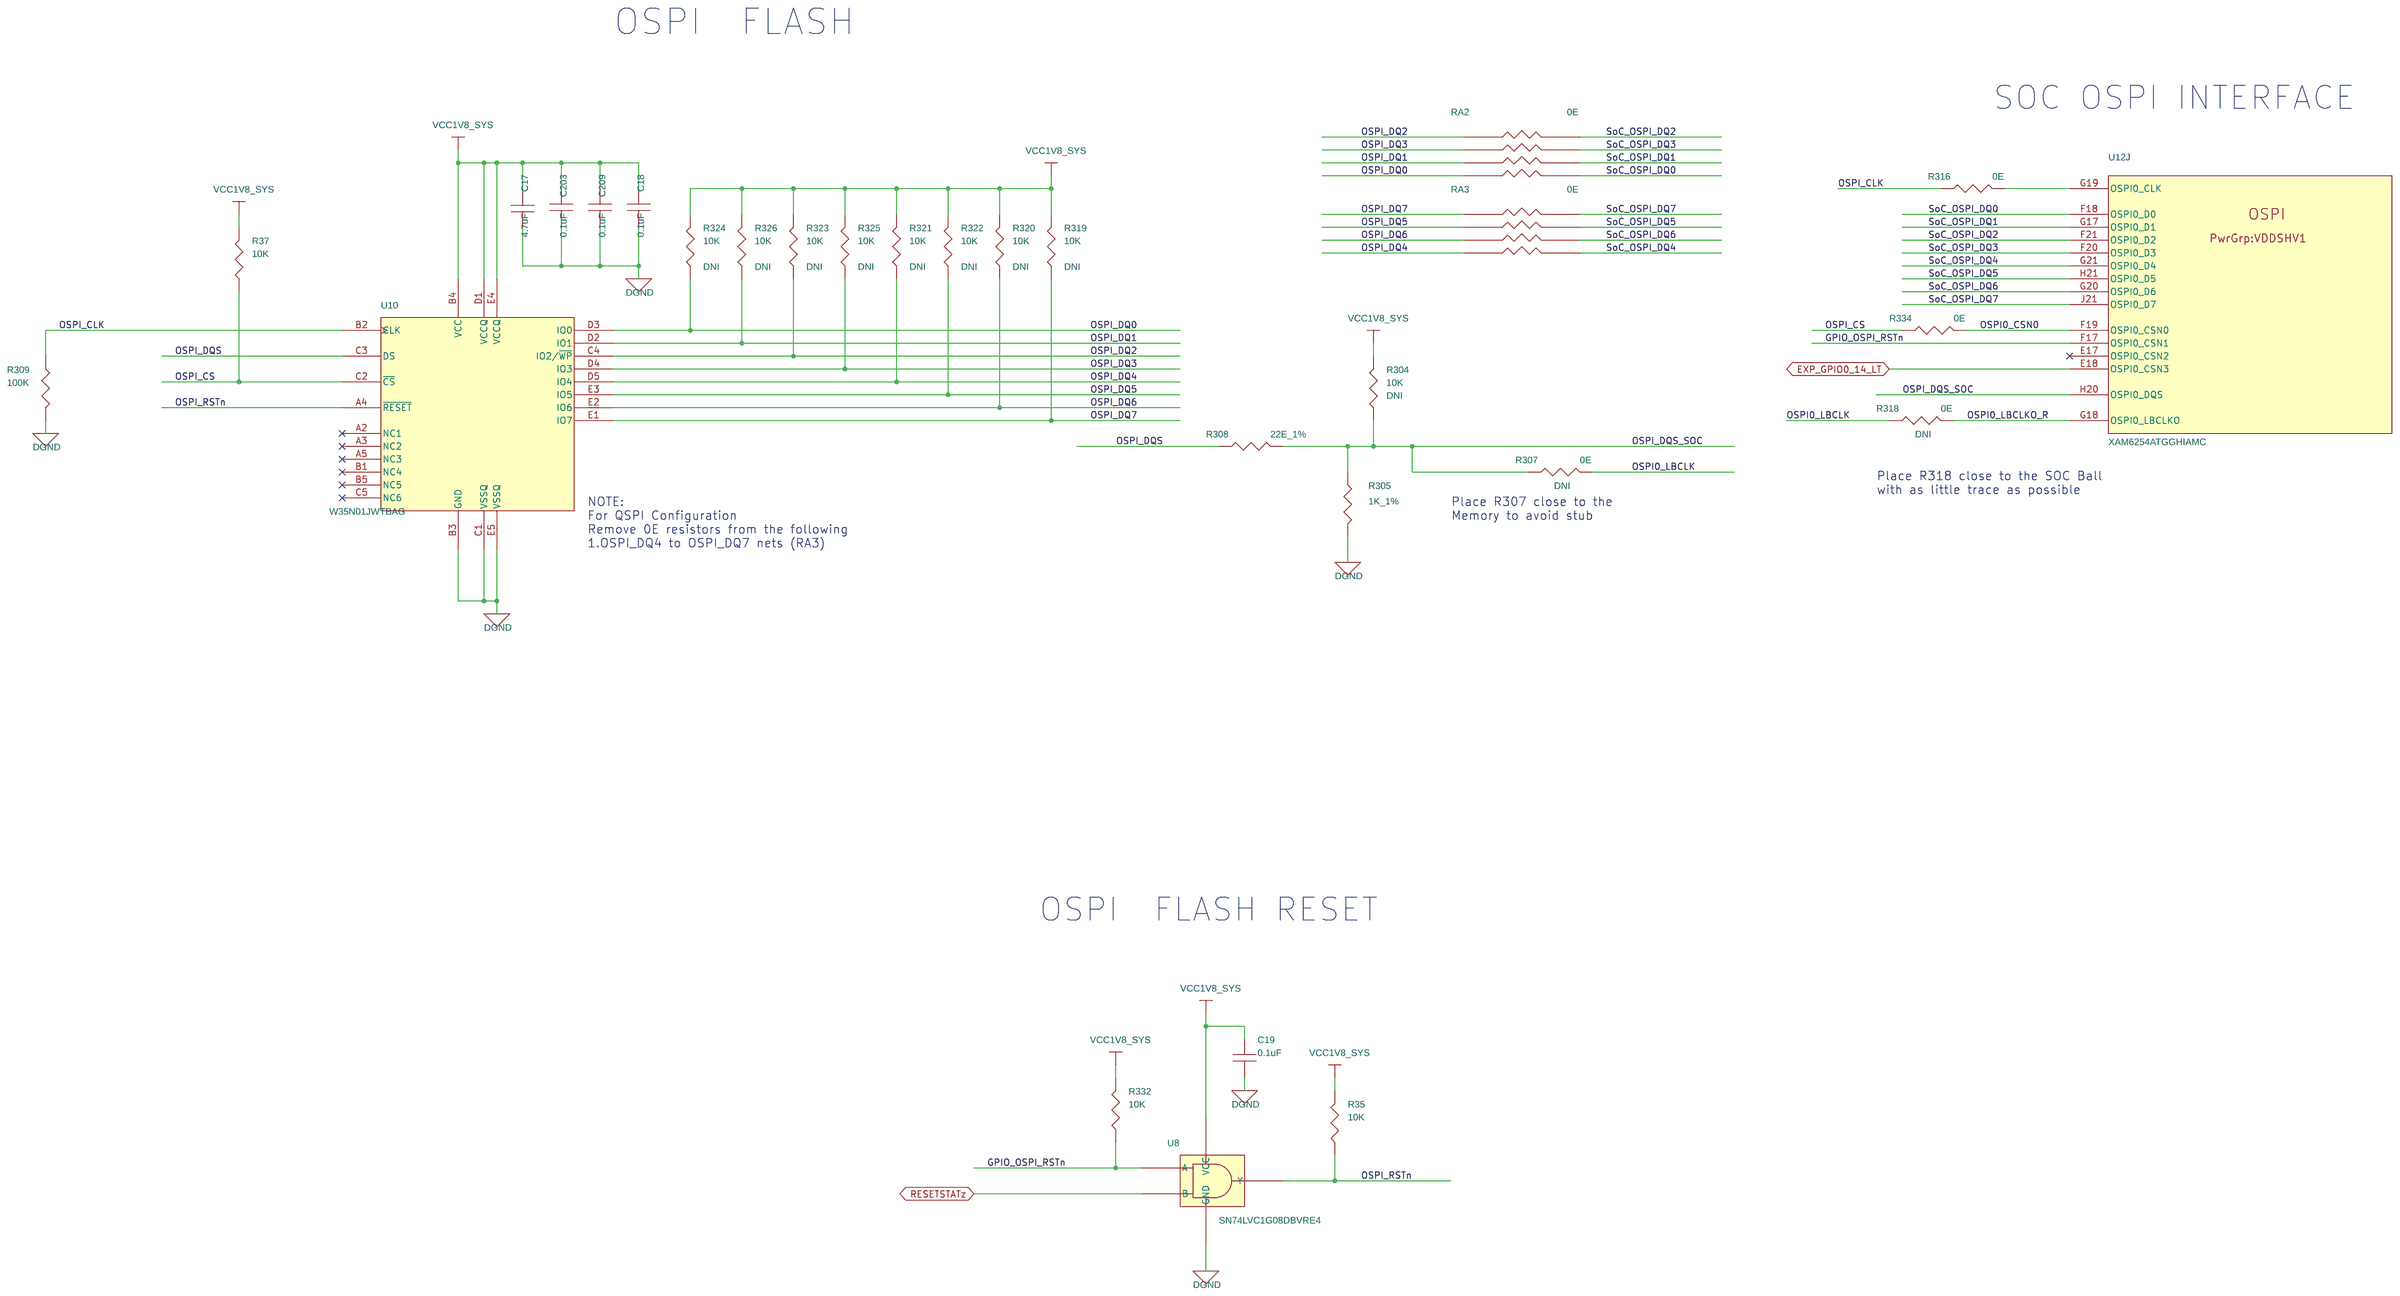
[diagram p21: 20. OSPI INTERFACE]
23 21. BRD ID EEPROM &TEMP SENSORS: size C; title: BOARD ID EEPROM & TEMPERATURE SENSORS

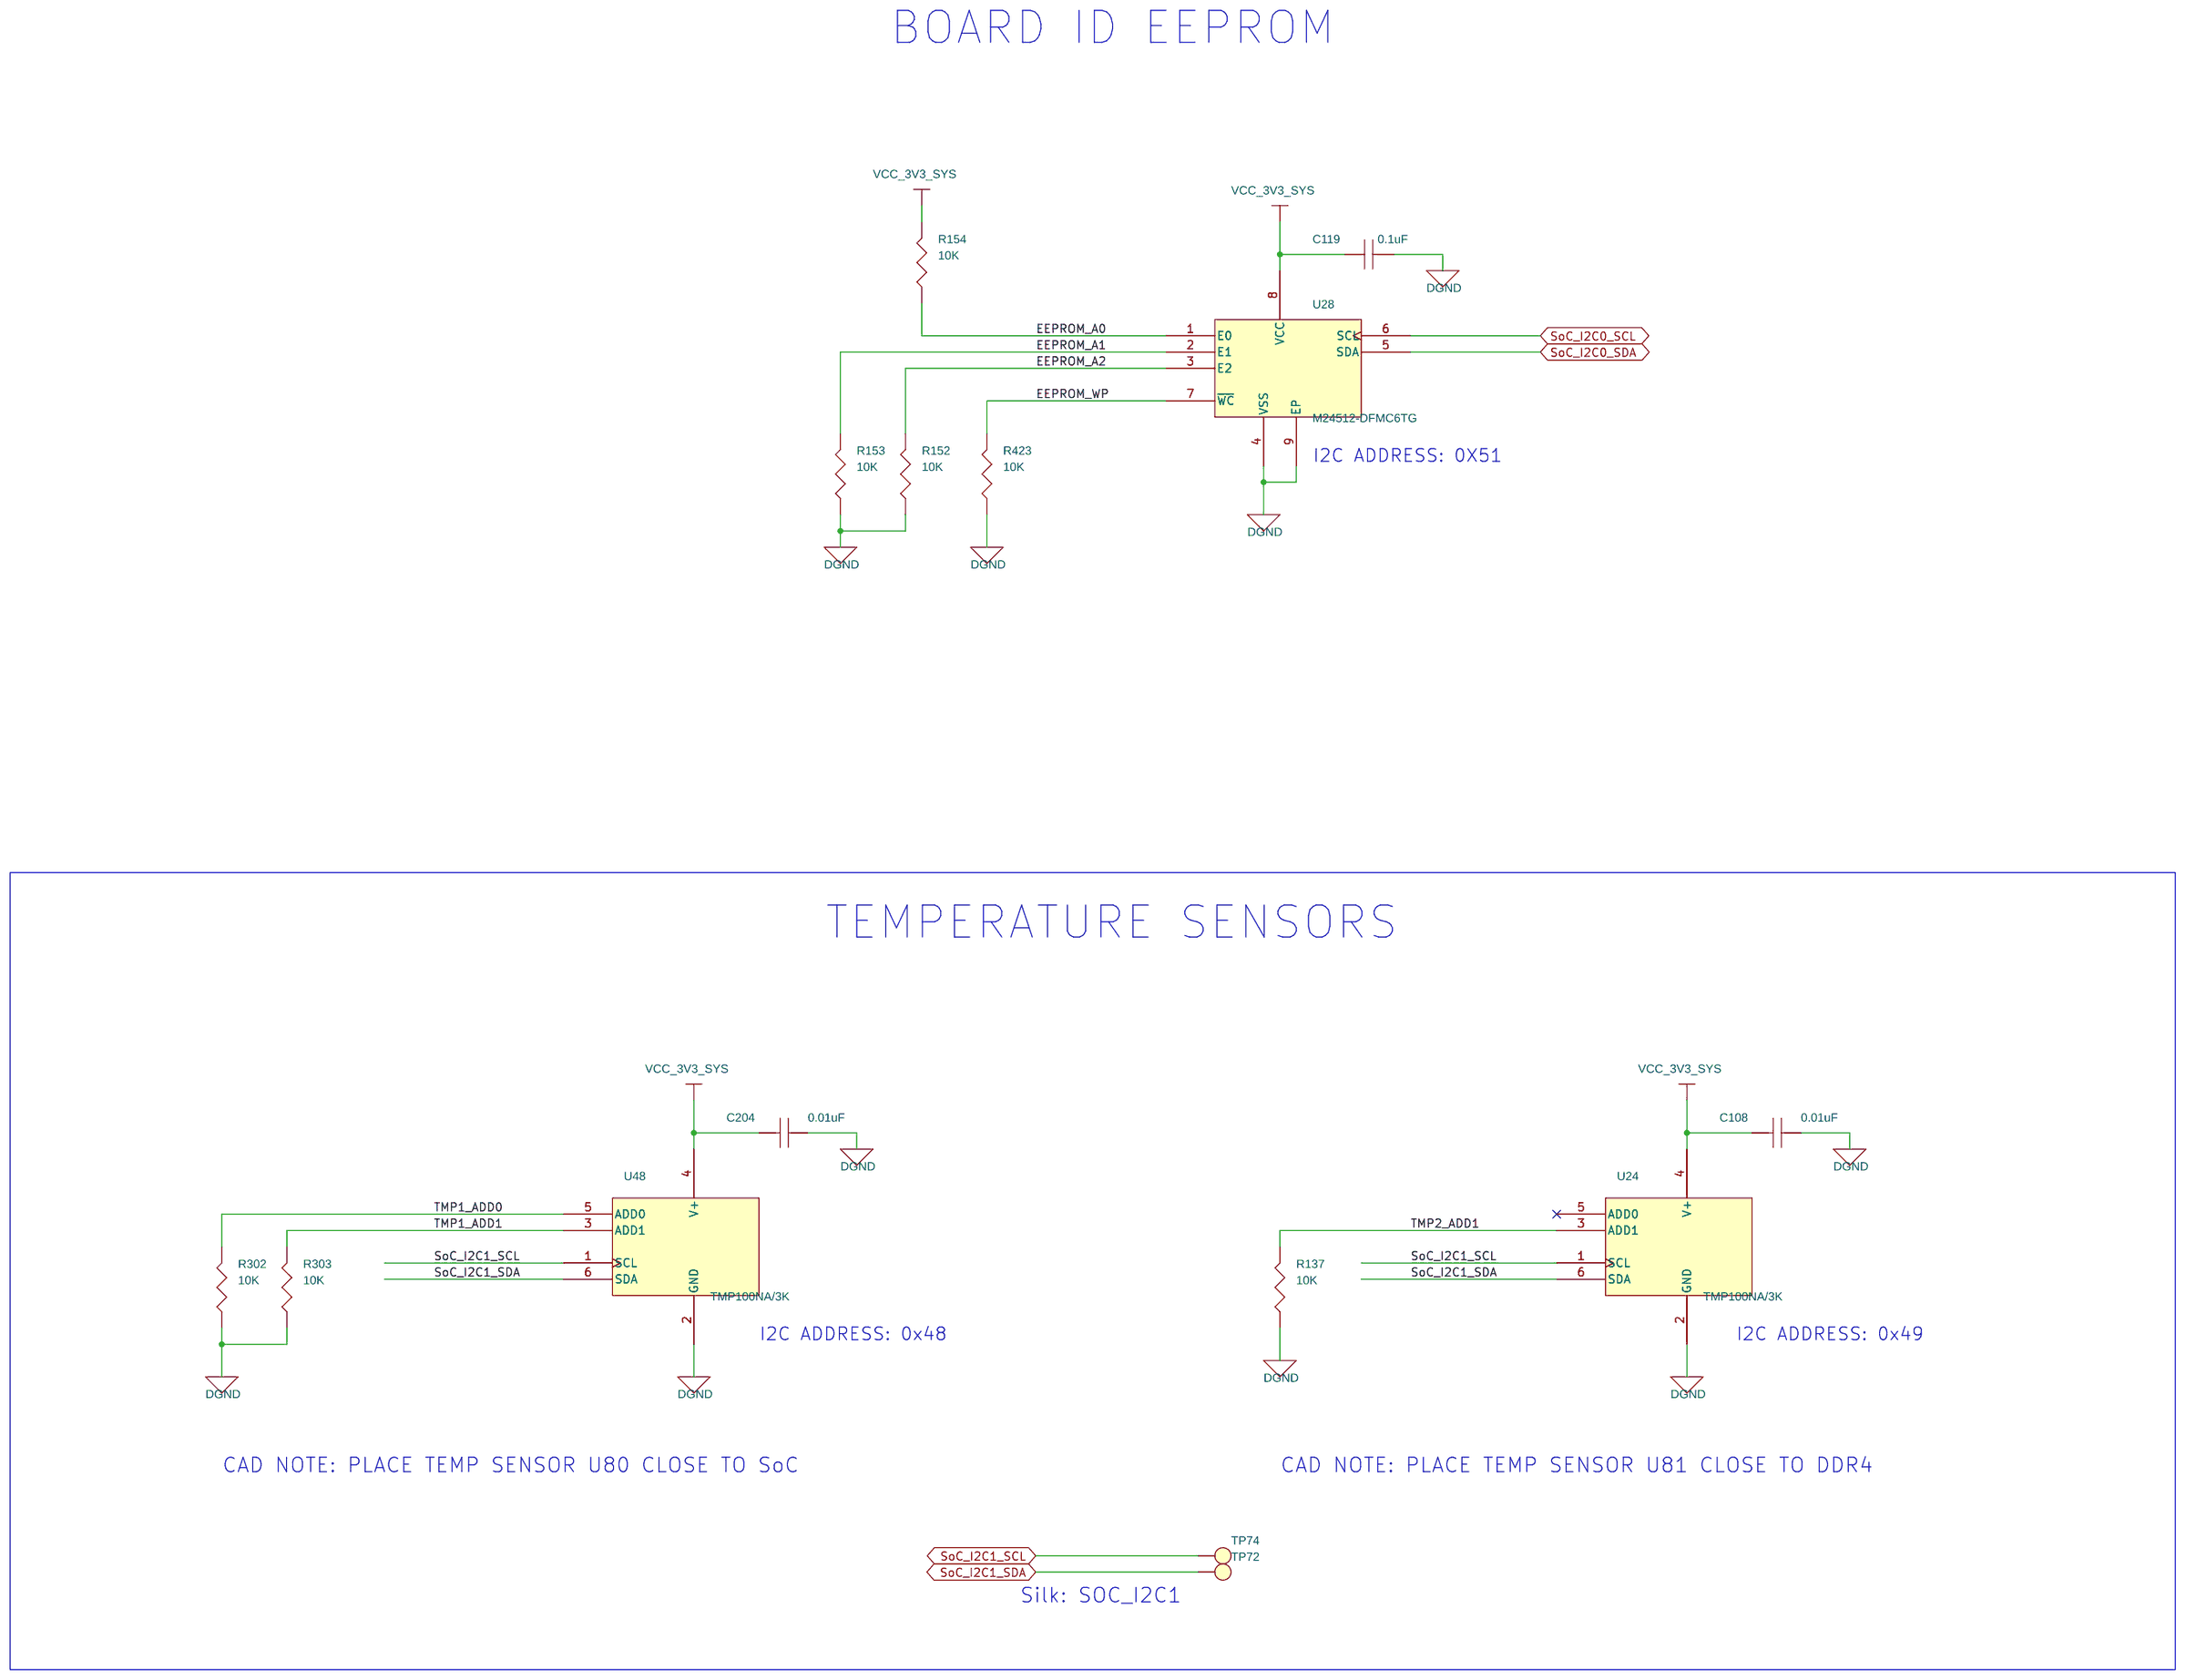
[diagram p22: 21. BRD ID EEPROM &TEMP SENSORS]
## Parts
sheet 19. SD CARD INTERFACE
C38  1uF  [CAP0201_0-5]
C39  4.7uF  [CAP0402_0-75]
C40  0.1uF  [CAP0402_0-75]
C48  2.2uF  [CAP0402_0-75]
C49  0.1uF  [CAP0402_0-75]
C54  0.1uF  [CAP0402_0-75]
C230  0.1uF  [CAP0402_0-75]
FL8  120E  [EMIFIL_BLM15A_0402_0-6]
J21  CON_SDCARD9_MEM2051-00-195-00-A  [CON_SD9_MEM2051-00-195-00_S_R_S_2-1]
R61  10K  [RES0201_0-5]
R67  10K  [RES0201_0-5]
R73  10K  [RES0201_0-5]
R74  10K  [RES0201_0-5]
R75  10K  [RES0201_0-5]
R88  10K  [RES0201_0-5]
R89  10K  [RES0201_0-5]
R90  10K  [RES0201_0-5]
R462  10K  [RES0201_0-5]
U13  TPS22918DBVR  [SOT23-6]
U14  TPD2E2U06DRLR  [SOT553-5_0-6]
U15  TPD6E001RSER  [UQFN10_19-68_80X60_0-6]
U52  SN74LVC1G11DRYR  [SON6_SN74LVC2G17_40X60_0-6]
sheet 20. OSPI INTERFACE
C17  4.7uF  [CAP0402_0-75]
C18  0.1uF  [CAP0402_0-75]
C19  0.1uF  [CAP0402_0-75]
C203  0.1uF  [CAP0402_0-75]
C209  0.1uF  [CAP0402_0-75]
R35  10K  [RES0201_0-5]
R37  10K  [RES0201_0-5]
R304  10K  [RES0201_0-5]
R305  1K_1%  [RES0201_0-5]
R307  0E  [RES0201_0-5]
R308  22E_1%  [RES0201_0-5]
R309  100K  [RES0201_0-5]
R316  0E  [RES0402_0-5]
R318  0E  [RES0201_0-5]
R319  10K  [RES0201_0-5]
R320  10K  [RES0201_0-5]
R321  10K  [RES0201_0-5]
R322  10K  [RES0201_0-5]
R323  10K  [RES0201_0-5]
R324  10K  [RES0201_0-5]
R325  10K  [RES0201_0-5]
R326  10K  [RES0201_0-5]
R332  10K  [RES0201_0-5]
R334  0E  [RES0201_0-5]
RA2  0E  [RESA_EXB_0201-4_0-5]
RA3  0E  [RESA_EXB_0201-4_0-5]
U8  SN74LVC1G08DBVRE4  [SOT23-5]
U10  W35N01JWTBAG  [TPBGA24_39-37_240X320_1-2]
sheet 21. BRD ID EEPROM &TEMP SENSORS
C108  0.01uF  [CAP0201_0-5]
C119  0.1uF  [CAP0402_0-75]
C204  0.01uF  [CAP0201_0-5]
R137  10K  [RES0201_0-5]
R152  10K  [RES0201_0-5]
R153  10K  [RES0201_0-5]
R154  10K  [RES0201_0-5]
R302  10K  [RES0201_0-5]
R303  10K  [RES0201_0-5]
R423  10K  [RES0201_0-5]
TP72  TP20_SMD  [TP20_SMD]
TP74  TP20_SMD  [TP20_SMD]
U24  TMP100NA/3K  [SOT23-6_1-5]
U28  M24512-DFMC6TG  [UFDFPN8_M24512_120X80_0-6]
U48  TMP100NA/3K  [SOT23-6_1-5]
sheet 31. PRU HEADER
U12  XAM6254ATGGHIAMC  [FCBGA441_31-49_680X680_2-6]  (sections A,B,C,D,E,F,G,H,I,J,K,L,M,N,O,P,Q,R)

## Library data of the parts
C38 = CAP: CAP CERAMIC 1uF 16V 20% X5R 0201; Chkd/date: MANIRAJA/300520; Crtd /date: ALVY/260520; Custom_Duty: 15%; Customs_HS_Code: 85322990; Distributor_name: DIGIKEY; Distributor_part_number: 490-18654-1-ND; Footprint Path: Y:\MIS_DATABASE\Library\ALTIUM_TOOL\PCB_FOOTPRINTS\Altium_Footprint_Lib.PcbLib; Height: 0.39MM; Library Path: Y:\MIS_DATABASE\Library\ALTIUM_TOOL\SCHEMATICS_PARTS\MS_DISCRETE_Library.schlib; Mfr_name: MURATA; Mfr_part_number: GRM033R61C105ME15D; Mistral Part No: 120018090038-R; Package: 0201; Part_type: CAPACITORS\CERAMIC; Project: QCS610_NANOSOM; RoHS: RoHS; Temperature: -55°C+85°C; Tolerance: 20%; Voltage: 16V; Wattage: NA; Weight: 0.33mg; Datasheet: Y:\MIS_DATABASE\DATASHEETS\CAPACITORS\GRM033R61C105ME15.PDF
C17 C39 = CAP: CAP CERAMIC 4.7uF 10V 20% X5R 0402; Chkd/date: MANIRAJA/110718; Crtd /date: ALVY/110718; Custom_Duty: 15%; Customs_HS_Code: 85322990; Distributor_name: DIGIKEY; Distributor_part_number: 490-14306-1-ND; Footprint Path: Y:\MIS_DATABASE\Library\ALTIUM_TOOL\PCB_FOOTPRINTS\Altium_Footprint_Lib.PcbLib; Height: 0.65MM; Library Path: Y:\MIS_DATABASE\Library\ALTIUM_TOOL\SCHEMATICS_PARTS\MS_DISCRETE_Library.schlib; Mfr_name: MURATA; Mfr_part_number: GRM155R61A475MEAAD; Mistral Part No: 120012060002-R; Package: 0402; Part_type: CAPACITORS\CERAMIC; Project: TI_J7SVB_PCIE_ADD-ON-CARD; RoHS: RoHS; Temperature: -55°C+85°C; Tolerance: 20%; Voltage: 10V; Wattage: NA; Weight: 14mg; Datasheet: Y:\MIS_DATABASE\DATASHEETS\CAPACITORS\GRM155R61A475MEAAD.PDF
C18 C19 C40 C49 C54 C119 C203 C209 C230 = CAP: CAP CERAMIC 0.1uF 50V 10% X7R 0402; Alt_Mfr_name: YAGEO AMERICA; Alt_Mfr_part_number: CC0402KRX5R8BB104; Chkd/date: MANIRAJA/261020; Crtd /date: ALVY/211020; Custom_Duty: 15%; Customs_HS_Code: 85322990; Distributor_name: DIGIKEY; Distributor_part_number: 490-10700-1-ND; Footprint Path: Y:\MIS_DATABASE\Library\ALTIUM_TOOL\PCB_FOOTPRINTS\Altium_Footprint_Lib.PcbLib; Height: 0.55MM; Library Path: Y:\MIS_DATABASE\Library\ALTIUM_TOOL\SCHEMATICS_PARTS\MS_DISCRETE_Library.schlib; Mfr_name: MURATA; Mfr_part_number: GRM155R71H104KE14D; Mistral Part No: 120011100014-R; Package: 0402; Part_type: CAPACITORS\CERAMIC; Project: J7_CP; RoHS: RoHS; Temperature: -55°C+125°C; Tolerance: 10%; Voltage: 50V; Wattage: NA; Weight: 3.1mg; Datasheet: Y:\MIS_DATABASE\DATASHEETS\CAPACITORS\GRM155R71H104KE14.PDF
C48 = CAP: CAP CERAMIC 2.2uF 25V 10% X5R 0402; Chkd/date: ALVY/010721; Crtd /date: MANIRAJA/010721; Custom_Duty: 15%; Customs_HS_Code: 85322990; Distributor_name: DIGIKEY; Distributor_part_number: 490-12703-1-ND; Footprint Path: Y:\MIS_DATABASE\Library\ALTIUM_TOOL\PCB_FOOTPRINTS\Altium_Footprint_Lib.PcbLib; Height: 0.70MM; Library Path: Y:\MIS_DATABASE\Library\ALTIUM_TOOL\SCHEMATICS_PARTS\MS_DISCRETE_Library.schlib; Mfr_name: MURATA; Mfr_part_number: GRM155R61E225KE11D; Mistral Part No: 120015120001-R; Package: 0402; Part_type: CAPACITORS\CERAMIC; Project: TI_AM263X_CC; RoHS: RoHS; Temperature: -55°C+85°C; Tolerance: 10%; Voltage: 25V; Wattage: NA; Weight: 1.5mg; Datasheet: Y:\MIS_DATABASE\DATASHEETS\CAPACITORS\GRM155R61E225KE11.PDF
FL8 = EMIFILTER_IND: IND FERRITE BEAD CHIP 120E 2A 0402; Chkd/date: NAVEED/241114; Crtd /date: USMAN/170613; Custom_Duty: 24%; Customs_HS_Code: 85369090; Distributor_name: DIGIKEY; Distributor_part_number: 490-9656-1-ND; Footprint Path: Y:\MIS_DATABASE\Library\ALTIUM_TOOL\PCB_FOOTPRINTS\Altium_Footprint_Lib.PcbLib; Height: 0.55MM; Library Path: Y:\MIS_DATABASE\Library\ALTIUM_TOOL\SCHEMATICS_PARTS\MS_FILTER_Library.schlib; Mfr_name: MURATA; Mfr_part_number: BLM15PX121SN1D; Mistral Part No: 130013060022-R; Package: 0402; Part_type: INDUCTOR; Project: GEN_3-8; RoHS: RoHS; Temperature: -55°C+125°C; Tolerance: 25%; Voltage: NA; Wattage: NA; Weight: 1mg; Datasheet: Y:\MIS_DATABASE\DATASHEETS\DISCRETES\INDUCTORS\BLM15-SN1-SER.PDF
J21 = CON_SDCARD9_MEM2075-00-140: CON MICROSD CARD 9POS FEMALE RT SMD; Chkd/date: MANIRAJA/270921; Crtd /date: ALVY/240921; Custom_Duty: 24%; Customs_HS_Code: 85369090; Distributor_name: DIGIKEY; Distributor_part_number: 2073-MEM2051-00-195-00-ACT-ND; Footprint Path: Y:\MIS_DATABASE\Library\ALTIUM_TOOL\PCB_FOOTPRINTS\Altium_Footprint_Lib.PcbLib; Height: 2.05MM; Library Path: Y:\MIS_DATABASE\Library\ALTIUM_TOOL\SCHEMATICS_PARTS\MS_CONNECTOR_Library.schlib; Mfr_name: GCT; Mfr_part_number: MEM2051-00-195-00-A; Mistral Part No: 150021090028-R; Package: SMD; Part_type: CONNECTOR\MEMORY CARD; Project: TI_AM62x SKEVM_BRD; RoHS: RoHS; Temperature: -40°C+85°C; Tolerance: NA; Voltage: NA; Wattage: NA; Weight: 1000mg; Datasheet: Y:\MIS_DATABASE\DATASHEETS\CONNECTORS\MEM2051-00-195-00-A.PDF
R35 R37 R61 R67 R73-R75 R89 R90 R137 R152-R154 R302 R303 R332 R423 R462 = RESISTOR: RES 10K 1/20W 5% 0201; Chkd/date: MANIRAJA/050517; Crtd /date: MANIRAJA/050517; Custom_Duty: 15%; Customs_HS_Code: 85332119; Distributor_name: DIGIKEY; Distributor_part_number: 311-10KNCT-ND; Footprint Path: Y:\MIS_DATABASE\Library\ALTIUM_TOOL\PCB_FOOTPRINTS\Altium_Footprint_Lib.PcbLib; Height: 0.26MM; Library Path: Y:\MIS_DATABASE\Library\ALTIUM_TOOL\SCHEMATICS_PARTS\MS_DISCRETE_Library.schlib; Mfr_name: YAGEO AMERICA; Mfr_part_number: RC0201JR-0710KL; Mistral Part No: 110010070051-R; Package: 0201; Part_type: RESISTORS\FIXED; Project: GOLDEN-I LITE; RoHS: RoHS; Temperature: -55°C+125°C; Tolerance: 5%; Voltage: NA; Wattage: 1/20W; Weight: 0.17mg; Datasheet: Y:\MIS_DATABASE\DATASHEETS\RESISTORS\RCXXXXL-SER_MAR18.PDF
R88 R304 R319-R326 = RESISTOR: RES 10K 1/20W 5% 0201; Assembly_Instruction: DNI; Chkd/date: MANIRAJA/050517; Crtd /date: MANIRAJA/050517; Custom_Duty: 15%; Customs_HS_Code: 85332119; Distributor_name: DIGIKEY; Distributor_part_number: 311-10KNCT-ND; Footprint Path: Y:\MIS_DATABASE\Library\ALTIUM_TOOL\PCB_FOOTPRINTS\Altium_Footprint_Lib.PcbLib; Height: 0.26MM; Library Path: Y:\MIS_DATABASE\Library\ALTIUM_TOOL\SCHEMATICS_PARTS\MS_DISCRETE_Library.schlib; Mfr_name: YAGEO AMERICA; Mfr_part_number: RC0201JR-0710KL; Mistral Part No: 110010070051-R; Package: 0201; Part_type: RESISTORS\FIXED; Project: GOLDEN-I LITE; RoHS: RoHS; Temperature: -55°C+125°C; Tolerance: 5%; Voltage: NA; Wattage: 1/20W; Weight: 0.17mg; Datasheet: Y:\MIS_DATABASE\DATASHEETS\RESISTORS\RCXXXXL-SER_MAR18.PDF
U13 = TPS22918DBVR_SOT23-6: IC ON RESISTANCE LOAD SWITCH SOT23-6; Automotive Alternate_mfr_name: TEXAS INSTRUMENTS; Automotive Alternate_mfr_part_number: TPS22918TDBVRQ1; Chkd/date: VASANTHA/130516; Crtd /date: VASANTHA/130516; Custom_Duty: 15%; Customs_HS_Code: 85423100; Distributor_name: DIGIKEY; Distributor_part_number: TPS22918DBVR-ND; Height: 1.45MM; Mfr_name: TEXAS INSTRUMENTS; Mistral Part No: 142016050007-R; Part_type: ICS\POWER; Project: TMDXCSK8127; RoHS: RoHS; Temperature: -40°C to 105°C; Tolerance: NA; Voltage: NA; Wattage: NA; Weight: NA; Datasheet: Y:\MIS_DATABASE\DATASHEETS\ICS\POWER\TPS22918DBV.PDF
U14 = TPD2E2U06_SOT5X3-5: IC DUAL CHANNEL HIGH SPEED ESD PROTECTION SOT5X3-5; Chkd/date: PRAVEEN/130423; Crtd /date: PRAVEEN/130423; Custom_Duty: 15%; Customs_HS_Code: 85423100; Distributor_name: DIGIKEY; Distributor_part_number: 296-38361-1-ND; Footprint Path: Y:\MIS_DATABASE\Library\ALTIUM_TOOL\PCB_FOOTPRINTS\Altium_Footprint_Lib.PcbLib; Height: 0.60MM; Library Path: Y:\MIS_DATABASE\Library\ALTIUM_TOOL\SCHEMATICS_PARTS\MS_MISCINTERFACE_Library.schlib; Mfr_name: TEXAS INSTRUMENTS; Mistral Part No: 141023040006-R; Package: SOT5X3-5; Part_type: ICS\INTERFACE; Project: SK-AM62Q-LP_EVM; RoHS: RoHS; Temperature: -40°C+125°C; Tolerance: NA; Voltage: NA; Wattage: NA; Weight: 2.8mg; Datasheet: Y:\MIS_DATABASE\DATASHEETS\ICS\INTERFACE\TPD2E2U06.PDF
U15 = TPD6E001RSE_UQFN10: IC 6CH ESD-PROTECTION ARRAY UQFN10; Chkd/date: USMAN/070612; Crtd /date: BAVISH/160811; Custom_Duty: 15%; Customs_HS_Code: 85423100; Distributor_name: DIGIKEY; Distributor_part_number: 296-21888-1-ND; Footprint Path: Y:\MIS_DATABASE\Library\ALTIUM_TOOL\PCB_FOOTPRINTS\Altium_Footprint_Lib.PcbLib; Height: 0.60MM; IBISSP_MODLES: Y:\MIS_DATABASE\IBIS\ICs\INTERFACE\TPD6E001RSE.IBS; Library Path: Y:\MIS_DATABASE\Library\ALTIUM_TOOL\SCHEMATICS_PARTS\MS_MISCINTERFACE_Library.schlib; Mfr_name: TEXAS INSTRUMENTS; Mistral Part No: 141011080020-R; Package: UQFN10; Part_type: ICS\INTERFACE; Project: DM385EVM_BASE-BOARD; RoHS: RoHS; Temperature: -40°C+85°C; Tolerance: NA; Voltage: NA; Wattage: NA; Weight: 7mg; Datasheet: Y:\MIS_DATABASE\DATASHEETS\ICS\INTERFACE\TPD6E001.PDF
U52 = SN74LVC1G11DCKR_SC70-6: IC SINGLE 3-INPUT POSITIVE-AND GATE SON6; Chkd/date: MANIRAJA/270121; Crtd /date: ALVY/270121; Custom_Duty: 15%; Customs_HS_Code: 85423100; Distributor_name: DIGIKEY; Distributor_part_number: 296-30120-1-ND; Footprint Path: Y:\MIS_DATABASE\Library\ALTIUM_TOOL\PCB_FOOTPRINTS\Altium_Footprint_Lib.PcbLib; Height: 0.60MM; Library Path: Y:\MIS_DATABASE\Library\ALTIUM_TOOL\SCHEMATICS_PARTS\MS_GATE_Library.schlib; Mfr_name: TEXAS INSTRUMENTS; Mistral Part No: 141021010013-R; Package: SON6; Part_type: ICS\DIGITAL\GATES; Project: AM64X_SKEVM; RoHS: RoHS; Temperature: -40°C+125°C; Tolerance: NA; Voltage: NA; Wattage: NA; Weight: 33mg; Datasheet: Y:\MIS_DATABASE\DATASHEETS\ICS\DIGITAL\GATES\SN74LVC1G_NOV16.PDF
R305 = RESISTOR: RES 1K 1/20W 1% 0201; Chkd/date: JEBRAN/110815; Crtd /date: JEBRAN/110815; Custom_Duty: 15%; Customs_HS_Code: 85332119; Distributor_name: DIGIKEY; Distributor_part_number: 541-1.00KAABCT-ND; Footprint Path: Y:\MIS_DATABASE\Library\ALTIUM_TOOL\PCB_FOOTPRINTS\Altium_Footprint_Lib.PcbLib; Height: 0.28MM; Library Path: Y:\MIS_DATABASE\Library\ALTIUM_TOOL\SCHEMATICS_PARTS\MS_DISCRETE_Library.schlib; Mfr_name: VISHAY; Mfr_part_number: CRCW02011K00FKED; Mistral Part No: 110015080014-R; Package: 0201; Part_type: RESISTORS\FIXED; Project: OCTASIC_3000; RoHS: RoHS; Temperature: -55°C+155°C; Tolerance: 1%; Voltage: NA; Wattage: 1/20W; Weight: 0.17mg; Datasheet: Y:\MIS_DATABASE\DATASHEETS\RESISTORS\CRCW0201.PDF
R307 R318 = RESISTOR: RES 0E 1/20W 5% 0201; Assembly_Instruction: DNI; Chkd/date: NAVEED/301214; Crtd /date: MUDDU/120710; Custom_Duty: 15%; Customs_HS_Code: 85332119; Distributor_name: DIGIKEY; Distributor_part_number: 311-0.0NCT-ND; Footprint Path: Y:\MIS_DATABASE\Library\ALTIUM_TOOL\PCB_FOOTPRINTS\Altium_Footprint_Lib.PcbLib; Height: 0.26MM; Library Path: Y:\MIS_DATABASE\Library\ALTIUM_TOOL\SCHEMATICS_PARTS\MS_DISCRETE_Library.schlib; Mfr_name: YAGEO AMERICA; Mfr_part_number: RC0201JR-070RL; Mistral Part No: 110010070067-R; Package: 0201; Part_type: RESISTORS\FIXED; Project: PB_BUGBASE; RoHS: RoHS; SIGNAL_MODEL: RESISTOR_RES0201_0-5_0E_0E; Temperature: -55°C+125°C; Tolerance: 5%; Voltage: NA; Wattage: 1/20W; Weight: 0.17mg; Datasheet: Y:\MIS_DATABASE\DATASHEETS\RESISTORS\RCXXXXL-SER_MAR18.PDF
R308 = RESISTOR: RES 22E 1/20W 1% 0201; Chkd/date: PRAVEEN/080922; Crtd /date: TAMILARASU/080922; Custom_Duty: 15%; Customs_HS_Code: 85332119; Distributor_name: DIGIKEY; Distributor_part_number: P122843CT-ND; Footprint Path: Y:\MIS_DATABASE\Library\ALTIUM_TOOL\PCB_FOOTPRINTS\Altium_Footprint_Lib.PcbLib; Height: 0.26MM; Library Path: Y:\MIS_DATABASE\Library\ALTIUM_TOOL\SCHEMATICS_PARTS\MS_DISCRETE_Library.schlib; Mfr_name: PANASONIC-ECG; Mfr_part_number: ERJ-1GNF22R0C; Mistral Part No: 110022090007-R; Package: 0201; Part_type: RESISTORS\FIXED; Project: SK AM62Q LP EVM BRD; RoHS: RoHS; SIGNAL_MODEL: RESISTOR_RES0201_0-5_22E_1%_22E_1%; Temperature: -55°C+125°C; Tolerance: 1%; Voltage: NA; Wattage: 1/20W; Weight: 0.15mg; Datasheet: Y:\MIS_DATABASE\DATASHEETS\RESISTORS\PAN-ERJSER_NOV17.PDF
R309 = RESISTOR: RES 100K 1/20W 5% 0201; Chkd/date: PRAVEEN/080922; Crtd /date: TAMILARASU/080922; Custom_Duty: 15%; Customs_HS_Code: 85332119; Distributor_name: DIGIKEY; Distributor_part_number: P123223CT-ND; Footprint Path: Y:\MIS_DATABASE\Library\ALTIUM_TOOL\PCB_FOOTPRINTS\Altium_Footprint_Lib.PcbLib; Height: 0.26MM; Library Path: Y:\MIS_DATABASE\Library\ALTIUM_TOOL\SCHEMATICS_PARTS\MS_DISCRETE_Library.schlib; Mfr_name: PANASONIC-ECG; Mfr_part_number: ERJ-1GNJ104C; Mistral Part No: 110022090005-R; Package: 0201; Part_type: RESISTORS\FIXED; Project: SK AM62Q LP EVM BRD; RoHS: RoHS; Temperature: -55°C+125°C; Tolerance: 5%; Voltage: NA; Wattage: 1/20W; Weight: 0.15mg; Datasheet: Y:\MIS_DATABASE\DATASHEETS\RESISTORS\PAN-ERJSER_NOV17.PDF
R316 = RESISTOR: RES 0E 1/16W JUMPER 0402; Chkd/date: VASANTHA/201216; Crtd /date: MUDDU/190810; Custom_Duty: 15%; Customs_HS_Code: 85332119; Distributor_name: DIGIKEY; Distributor_part_number: 541-0.0JCT-ND; Footprint Path: Y:\MIS_DATABASE\Library\ALTIUM_TOOL\PCB_FOOTPRINTS\Altium_Footprint_Lib.PcbLib; Height: 0.40MM; Library Path: Y:\MIS_DATABASE\Library\ALTIUM_TOOL\SCHEMATICS_PARTS\MS_DISCRETE_Library.schlib; Mfr_name: VISHAY; Mfr_part_number: CRCW04020000Z0ED; Mistral Part No: 110010080019-R; Package: 0402; Part_type: RESISTORS\FIXED; Project: PB_BUGBASE; RoHS: RoHS; SIGNAL_MODEL: RESISTOR_RES0402_0-5_0E_0E; Temperature: -55°C+155°C; Tolerance: NA; Voltage: NA; Wattage: 1/16W; Weight: 0.65mg; Datasheet: Y:\MIS_DATABASE\DATASHEETS\RESISTORS\CRCW0603.PDF
R334 = RESISTOR: RES 0E 1/20W 5% 0201; Chkd/date: NAVEED/301214; Crtd /date: MUDDU/120710; Custom_Duty: 15%; Customs_HS_Code: 85332119; Distributor_name: DIGIKEY; Distributor_part_number: 311-0.0NCT-ND; Footprint Path: Y:\MIS_DATABASE\Library\ALTIUM_TOOL\PCB_FOOTPRINTS\Altium_Footprint_Lib.PcbLib; Height: 0.26MM; Library Path: Y:\MIS_DATABASE\Library\ALTIUM_TOOL\SCHEMATICS_PARTS\MS_DISCRETE_Library.schlib; Mfr_name: YAGEO AMERICA; Mfr_part_number: RC0201JR-070RL; Mistral Part No: 110010070067-R; Package: 0201; Part_type: RESISTORS\FIXED; Project: PB_BUGBASE; RoHS: RoHS; Temperature: -55°C+125°C; Tolerance: 5%; Voltage: NA; Wattage: 1/20W; Weight: 0.17mg; Datasheet: Y:\MIS_DATABASE\DATASHEETS\RESISTORS\RCXXXXL-SER_MAR18.PDF
RA2 RA3 = RESARR_ISO4: RES ARRAY 0E 31mW JUMPER 0201-4; Chkd/date: MANIRAJA/290918; Crtd /date: MANIRAJA/290918; Custom_Duty: 15%; Customs_HS_Code: 85332119; Distributor_name: DIGIKEY; Distributor_part_number: Y6000CT-ND; Footprint Path: Y:\MIS_DATABASE\Library\ALTIUM_TOOL\PCB_FOOTPRINTS\Altium_Footprint_Lib.PcbLib; Height: 0.45MM; Library Path: Y:\MIS_DATABASE\Library\ALTIUM_TOOL\SCHEMATICS_PARTS\MS_DISCRETE_Library.schlib; Manufacturer: PANASONIC-ECG; Mfr_name: PANASONIC-ECG; Mfr_part_number: EXB-18VR000X; Mistral Part No: 110018090033-R; Package: 0201-4; Part_type: RESISTORS\ARRAY; Project: TI_60GHz-AOP; RoHS: RoHS; SIGNAL_MODEL: RESARR_ISO4_RESA_EXB_0201-4_0-5_0E; Temperature: -55°C+125°C; Tolerance: NA; Voltage: NA; Wattage: 31mW; Weight: 1mg; Datasheet: Y:\MIS_DATABASE\DATASHEETS\RESISTORS\EXB-18V.PDF
U8 = SN74LVC1G08DBVRE4_SOT23-5: IC SINGLE 2-INPUT POSITIVE AND GATE SOT23-5; Chkd/date: SUHAS/221010; Crtd /date: USMAN/151008; Custom_Duty: 15%; Customs_HS_Code: 85423100; Distributor_name: DIGIKEY; Distributor_part_number: SN74LVC1G08DBVRE4-ND; Height: 1.45MM; Mfr_name: TEXAS INSTRUMENTS; Mistral Part No: 141009060026-R; Part_type: ICS\DIGITAL\GATES; Project: KHAN_MAIN; RoHS: Sb/ Br FREE; Temperature: -40°C+85°C; Datasheet: Y:\MIS_DATABASE\DATASHEETS\ICS\DIGITAL\GATES\SN74LVC1G08.PDF
U10 = W35N01JWTB_TFBGA24: IC 1.7-1.95V 1Gb SERIAL SLC NAND FLASH MEMORY OCTAL SPI TFBGA24; Chkd/date: MANIRAJA/090421; Crtd /date: ALVY/080421; Custom_Duty: 15%; Customs_HS_Code: 85423100; Distributor_name: NA; Distributor_part_number: NA; Footprint Path: Y:\MIS_DATABASE\Library\ALTIUM_TOOL\PCB_FOOTPRINTS\Altium_Footprint_Lib.PcbLib; Height: 1.20MM; Library Path: Y:\MIS_DATABASE\Library\ALTIUM_TOOL\SCHEMATICS_PARTS\MS_MISCMEMORY_Library.schlib; Mfr_name: WINBOND; Mistral Part No: 141121040002-R; Package: TFBGA24; Part_type: ICS\DIGITAL\MEMORY; Project: TI_J7AEP SOM BRD; RoHS: RoHS; Temperature: -40°C+105°C; Tolerance: NA; Voltage: NA; Wattage: NA; Weight: NA; Datasheet: Y:\MIS_DATABASE\DATASHEETS\ICS\MEMORY\W35N01JWXX.PDF
C108 C204 = CAP: CAP CERAMIC 0.01uF 25V 10% X5R 0201; Chkd/date: MANIRAJA/230118; Crtd /date: MANIRAJA/230118; Custom_Duty: 15%; Customs_HS_Code: 85322990; Distributor_name: DIGIKEY; Distributor_part_number: GRM033R61E103KA12J-ND; Footprint Path: Y:\MIS_DATABASE\Library\ALTIUM_TOOL\PCB_FOOTPRINTS\Altium_Footprint_Lib.PcbLib; Height: 0.33MM; Library Path: Y:\MIS_DATABASE\Library\ALTIUM_TOOL\SCHEMATICS_PARTS\MS_DISCRETE_Library.schlib; Mfr_name: MURATA; Mfr_part_number: GRM033R61E103KA12J; Mistral Part No: 120018010007-R; Package: 0201; Part_type: CAPACITORS\CERAMIC; Project: TI_MAXIE_CPB; RoHS: RoHS; Temperature: -55°C+85°C; Tolerance: 10%; Voltage: 25V; Wattage: NA; Weight: 0.33mg; Datasheet: Y:\MIS_DATABASE\DATASHEETS\CAPACITORS\GRM033R61E103KA12.PDF
TP72 TP74 = TESTPOINT: TESTPOINT CIR 20 SMD; Chkd/date: SHREESHAIL/171006; Crtd /date: MAZHAR/171006; Custom_Duty: NA; Customs_HS_Code: NA; Distributor_name: NA; Distributor_part_number: NA; Footprint Path: Y:\MIS_DATABASE\Library\ALTIUM_TOOL\PCB_FOOTPRINTS\Altium_Footprint_Lib.PcbLib; Height: NA; Library Path: Y:\MIS_DATABASE\Library\ALTIUM_TOOL\SCHEMATICS_PARTS\MS_DISCRETE_Library.schlib; MECHANICAL 3D STEP FILE: NA; Mfr_name: LOCAL; Mistral Part No: NA; Package: SMD; Project: BT MODULE_CSRBC04; RoHS: NA; Temperature: NA; Tolerance: NA; Voltage: NA; Wattage: NA; Weight: NA; Datasheet: NA
U24 U48 = TMP100NA_3K_SOT23-6: IC TEMPERATURE SENSOR WITH I2C AND SMBUS INTERFACE SOT23-6; Chkd/date: MANIRAJA/290817; Crtd /date: MANIRAJA/290817; Custom_Duty: 15%; Customs_HS_Code: 85423100; Distributor_name: DIGIKEY; Distributor_part_number: 296-26833-1-ND; Height: 1.45MM; Library Ref: TMP100NA/3K_SOT23-6; Mfr_name: TEXAS INSTRUMENTS; Mistral Part No: 141017080030-R; Package: SOT23-6; Part_type: ICS\DIGITAL\PERIPHERAL; Project: TI_MAXIE_CPB; RoHS: RoHS; Temperature: -55°C+125°C; Tolerance: NA; Voltage: NA; Wattage: NA; Weight: 120mg; Datasheet: Y:\MIS_DATABASE\DATASHEETS\ICS\DIGITAL\PERIPHERAL\TMP10XX.PDF
U28 = M24512_UFDFPN8: IC 1.7-5.5V 512Kb I2C SERIAL EEPROM UFDFPN8; Chkd/date: ALVY/240322; Crtd /date: ALVY/240322; Custom_Duty: 15%; Customs_HS_Code: 85423100; Distributor_name: DIGIKEY; Distributor_part_number: 497-15745-1-ND; Footprint Path: Y:\MIS_DATABASE\Library\ALTIUM_TOOL\PCB_FOOTPRINTS\Altium_Footprint_Lib.PcbLib; Height: 0.60MM; Library Path: Y:\MIS_DATABASE\Library\ALTIUM_TOOL\SCHEMATICS_PARTS\MS_MISCMEMORY_Library.schlib; Mfr_name: ST MICROELECTRONICS; Mistral Part No: 141122030005-R; Package: UFDFPN8; Part_type: ICS\DIGITAL\MEMORY; Project: TI_SK-AM62Q-LP EVM_BRD; RoHS: RoHS; Temperature: -40°C+85°C; Tolerance: NA; Voltage: NA; Wattage: NA; Weight: 16mg; Datasheet: Y:\MIS_DATABASE\DATASHEETS\ICS\MEMORY\M24512-W-R-DF.PDF
U12 = AM62Q_SoC_FCBGA441: IC AM62Q SoC MICROPROCESSOR FCBGA441; Chkd/date: MANIRAJA/211021; Crtd /date: ALVY/211021; Custom_Duty: 15%; Customs_HS_Code: 85423100; Distributor_name: NA; Distributor_part_number: NA; Footprint Path: Y:\MIS_DATABASE\Library\ALTIUM_TOOL\PCB_FOOTPRINTS\Altium_Footprint_Lib.PcbLib; Height: 2.57MM; Library Path: Y:\MIS_DATABASE\Library\ALTIUM_TOOL\SCHEMATICS_PARTS\MS_MICROPROCESSOR_Library.schlib; Mfr_name: TEXAS INSTRUMENTS; Mistral Part No: 141221100001; Package: FCBGA441; Part_type: ICS\DIGITAL\MICROPROCESSOR; Project: TI_AM62Q_BRD; RoHS: NA; Temperature: NA; Tolerance: NA; Voltage: NA; Wattage: NA; Weight: NA; Datasheet: Y:\MIS_DATABASE\DATASHEETS\ICS\DIGITAL\MICROCONTROLLER\AM62Q-SoC.PDF

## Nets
DGND: C17.1 C18.2 C19.2 C38.2 C39.2 C40.2 C48.1 C49.1 C54.1 C108.1 C119.2 C203.2 C204.1 C209.2 C230.2 J21.6(VSS) J21.SH1 J21.SH2 J21.SH3 J21.SH4 R137.2 R152.2 R153.2 R302.2 R303.2 R305.2 R309.2 R423.2 U8.3(GND) U10.B3(GND) U10.C1(VSSQ) U10.E5(VSSQ) U13.2(GND) U14.4(GND) U15.5(GND) U24.2(GND) U28.4(VSS) U28.9(EP) U48.2(GND) U52.2(GND) ; also on sheet 1 2 3 4 13 14 15 16 17 18 19 20 24 25 26 27 28 29 30 31 32 33 34 35 36 37 38 39 40 41 42 43
VCC1V8_SYS: C17.2 C18.1 C19.1 C203.1 C209.1 R35.2 R37.2 R304.2 R319.2 R320.2 R321.2 R322.2 R323.2 R324.2 R325.2 R326.2 R332.2 U8.5(VCC) U10.B4(VCC) U10.D1(VCCQ) U10.E4(VCCQ) ; also on sheet 4 16 19 20 25 34 37 39 40 42
VCC_3V3_SYS: C38.1 C40.1 C108.2 C119.1 C204.2 C230.1 R61.2 R67.2 R154.1 R462.2 U13.1(VIN) U24.4(V+) U28.8(VCC) U48.4(V+) U52.5(VCC) ; also on sheet 1 4 15 16 19 20 24 26 27 29 30 31 32 33 34 36 37 38 39 40 41 42 43
VDD_MMC1: C39.1 FL8.1 U13.5(QOD) U13.6(VOUT)
VDD_MMC1_SD: C48.2 C49.2 FL8.2 J21.4(VDD) U14.1(NC1)
VDDSHV_SDIO: C54.2 R73.2 R74.2 R75.2 R88.2 R89.2 R90.2 U15.10(VCC) ; also on sheet 4 17
EEPROM_A0: R154.2 U28.1(E0)
EEPROM_A1: R153.1 U28.2(E1)
EEPROM_A2: R152.1 U28.3(E2)
EEPROM_WP: R423.1 U28.7(~{WC})
EXP_GPIO0_14_LT: U12.E18(OSPI0_CSN3) ; also on sheet 34
GPIO_OSPI_RSTn: R332.1 U8.1(A) U12.F17(OSPI0_CSN1)
MMC1_CLK: J21.5(CLK) R88.1 U15.6(IO4) ; also on sheet 20
MMC1_CMD: J21.3(CMD) R73.1 U15.1(IO1) ; also on sheet 20
MMC1_D0: J21.7(DAT0) R90.1 U15.8(IO6) ; also on sheet 20
MMC1_D1: J21.8(DAT1) R89.1 U15.7(IO5) ; also on sheet 20
MMC1_D2: J21.1(DAT2) R74.1 U15.2(IO2) ; also on sheet 20
MMC1_D3: J21.2(CD/DAT3) R75.1 U15.3(IO3) ; also on sheet 20
MMC1_SD_EN: R462.1 U52.1(A) ; also on sheet 39
MMC1_SD_LS_EN: R61.1 U13.3(ON) U52.4(Y)
MMC1_SDCD: J21.9(CD) R67.1 U14.5(IO2) ; also on sheet 20
OSPI0_CSN0: R334.2 U12.F19(OSPI0_CSN0)
OSPI0_LBCLK: R307.2 R318.1
OSPI0_LBCLKO_R: R318.2 U12.G18(OSPI0_LBCLKO)
OSPI_CLK: R309.1 R316.1 U10.B2(CLK)
OSPI_CS: R37.1 R334.1 U10.C2(~{CS})
OSPI_DQ0: R324.1 RA2.4 U10.D3(IO0)
OSPI_DQ1: R326.1 RA2.3 U10.D2(IO1)
OSPI_DQ2: R323.1 RA2.1 U10.C4(IO2/~{WP})
OSPI_DQ3: R325.1 RA2.2 U10.D4(IO3)
OSPI_DQ4: R321.1 RA3.4 U10.D5(IO4)
OSPI_DQ5: R322.1 RA3.2 U10.E3(IO5)
OSPI_DQ6: R320.1 RA3.3 U10.E2(IO6)
OSPI_DQ7: R319.1 RA3.1 U10.E1(IO7)
OSPI_DQS: R308.1 U10.C3(DS)
OSPI_DQS_SOC: R304.1 R305.1 R307.1 R308.2 U12.H20(OSPI0_DQS)
OSPI_RSTn: R35.1 U8.4(Y) U10.A4(~{RESET})
PORz_OUT: U52.6(C) ; also on sheet 1 24 27 42
RESETSTATz: U8.2(B) U52.3(B) ; also on sheet 1 4 20 24 27 32 37 38 39 40 41 42
SoC_I2C0_SCL: U28.6(SCL) ; also on sheet 4 13 32 33 37 42
SoC_I2C0_SDA: U28.5(SDA) ; also on sheet 4 13 32 33 37 42
SOC_I2C1_SCL: TP74.1(TP) U24.1(SCL) U48.1(SCL) ; also on sheet 16 26 39 40 41 42
SOC_I2C1_SDA: TP72.1(TP) U24.6(SDA) U48.6(SDA) ; also on sheet 16 26 39 40 41 42
SoC_OSPI_DQ0: RA2.5 U12.F18(OSPI0_D0)
SoC_OSPI_DQ1: RA2.6 U12.G17(OSPI0_D1)
SoC_OSPI_DQ2: RA2.8 U12.F21(OSPI0_D2)
SoC_OSPI_DQ3: RA2.7 U12.F20(OSPI0_D3)
SoC_OSPI_DQ4: RA3.5 U12.G21(OSPI0_D4)
SoC_OSPI_DQ5: RA3.7 U12.H21(OSPI0_D5)
SoC_OSPI_DQ6: RA3.6 U12.G20(OSPI0_D6)
SoC_OSPI_DQ7: RA3.8 U12.J21(OSPI0_D7)
TMP1_ADD0: R302.1 U48.5(ADD0)
TMP1_ADD1: R303.1 U48.3(ADD1)
TMP2_ADD1: R137.1 U24.3(ADD1)
N22727847: R316.2 U12.G19(OSPI0_CLK)

Not connected (* = marked no-connect by the designer): U10 A2(NC1)* A3(NC2)* A5(NC3)* B1(NC4)* B5(NC5)* C5(NC6)*; U12 E17(OSPI0_CSN2)*; U13 4(CT)*; U14 2(NC2)* 3(IO1)*; U15 4(NC1)* 9(NC2)*; U24 5(ADD0)*

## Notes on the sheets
sheet 21
- SD CARD INTERFACE
- POWER SWITCH
- SD CARD RESET
- Place near SD Card Connector
sheet 22
- OSPI  FLASH
- SOC OSPI INTERFACE
- Place R318 close to the SOC Ball
  with as little trace as possible
- NOTE:
  For QSPI Configuration
  Remove 0E resistors from the following
  1.OSPI_DQ4 to OSPI_DQ7 nets (RA3)
- Place R307 close to the
  Memory to avoid stub
- OSPI  FLASH RESET
sheet 23
- BOARD ID EEPROM
- I2C ADDRESS: 0X51
- TEMPERATURE SENSORS
- I2C ADDRESS: 0x48
- I2C ADDRESS: 0x49
- CAD NOTE: PLACE TEMP SENSOR U80 CLOSE TO SoC
- CAD NOTE: PLACE TEMP SENSOR U81 CLOSE TO DDR4
- Silk: SOC_I2C1
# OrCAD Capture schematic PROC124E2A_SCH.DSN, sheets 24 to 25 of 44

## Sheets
24 22. CPSW RGMII_1 ETHERNET PHY: size C
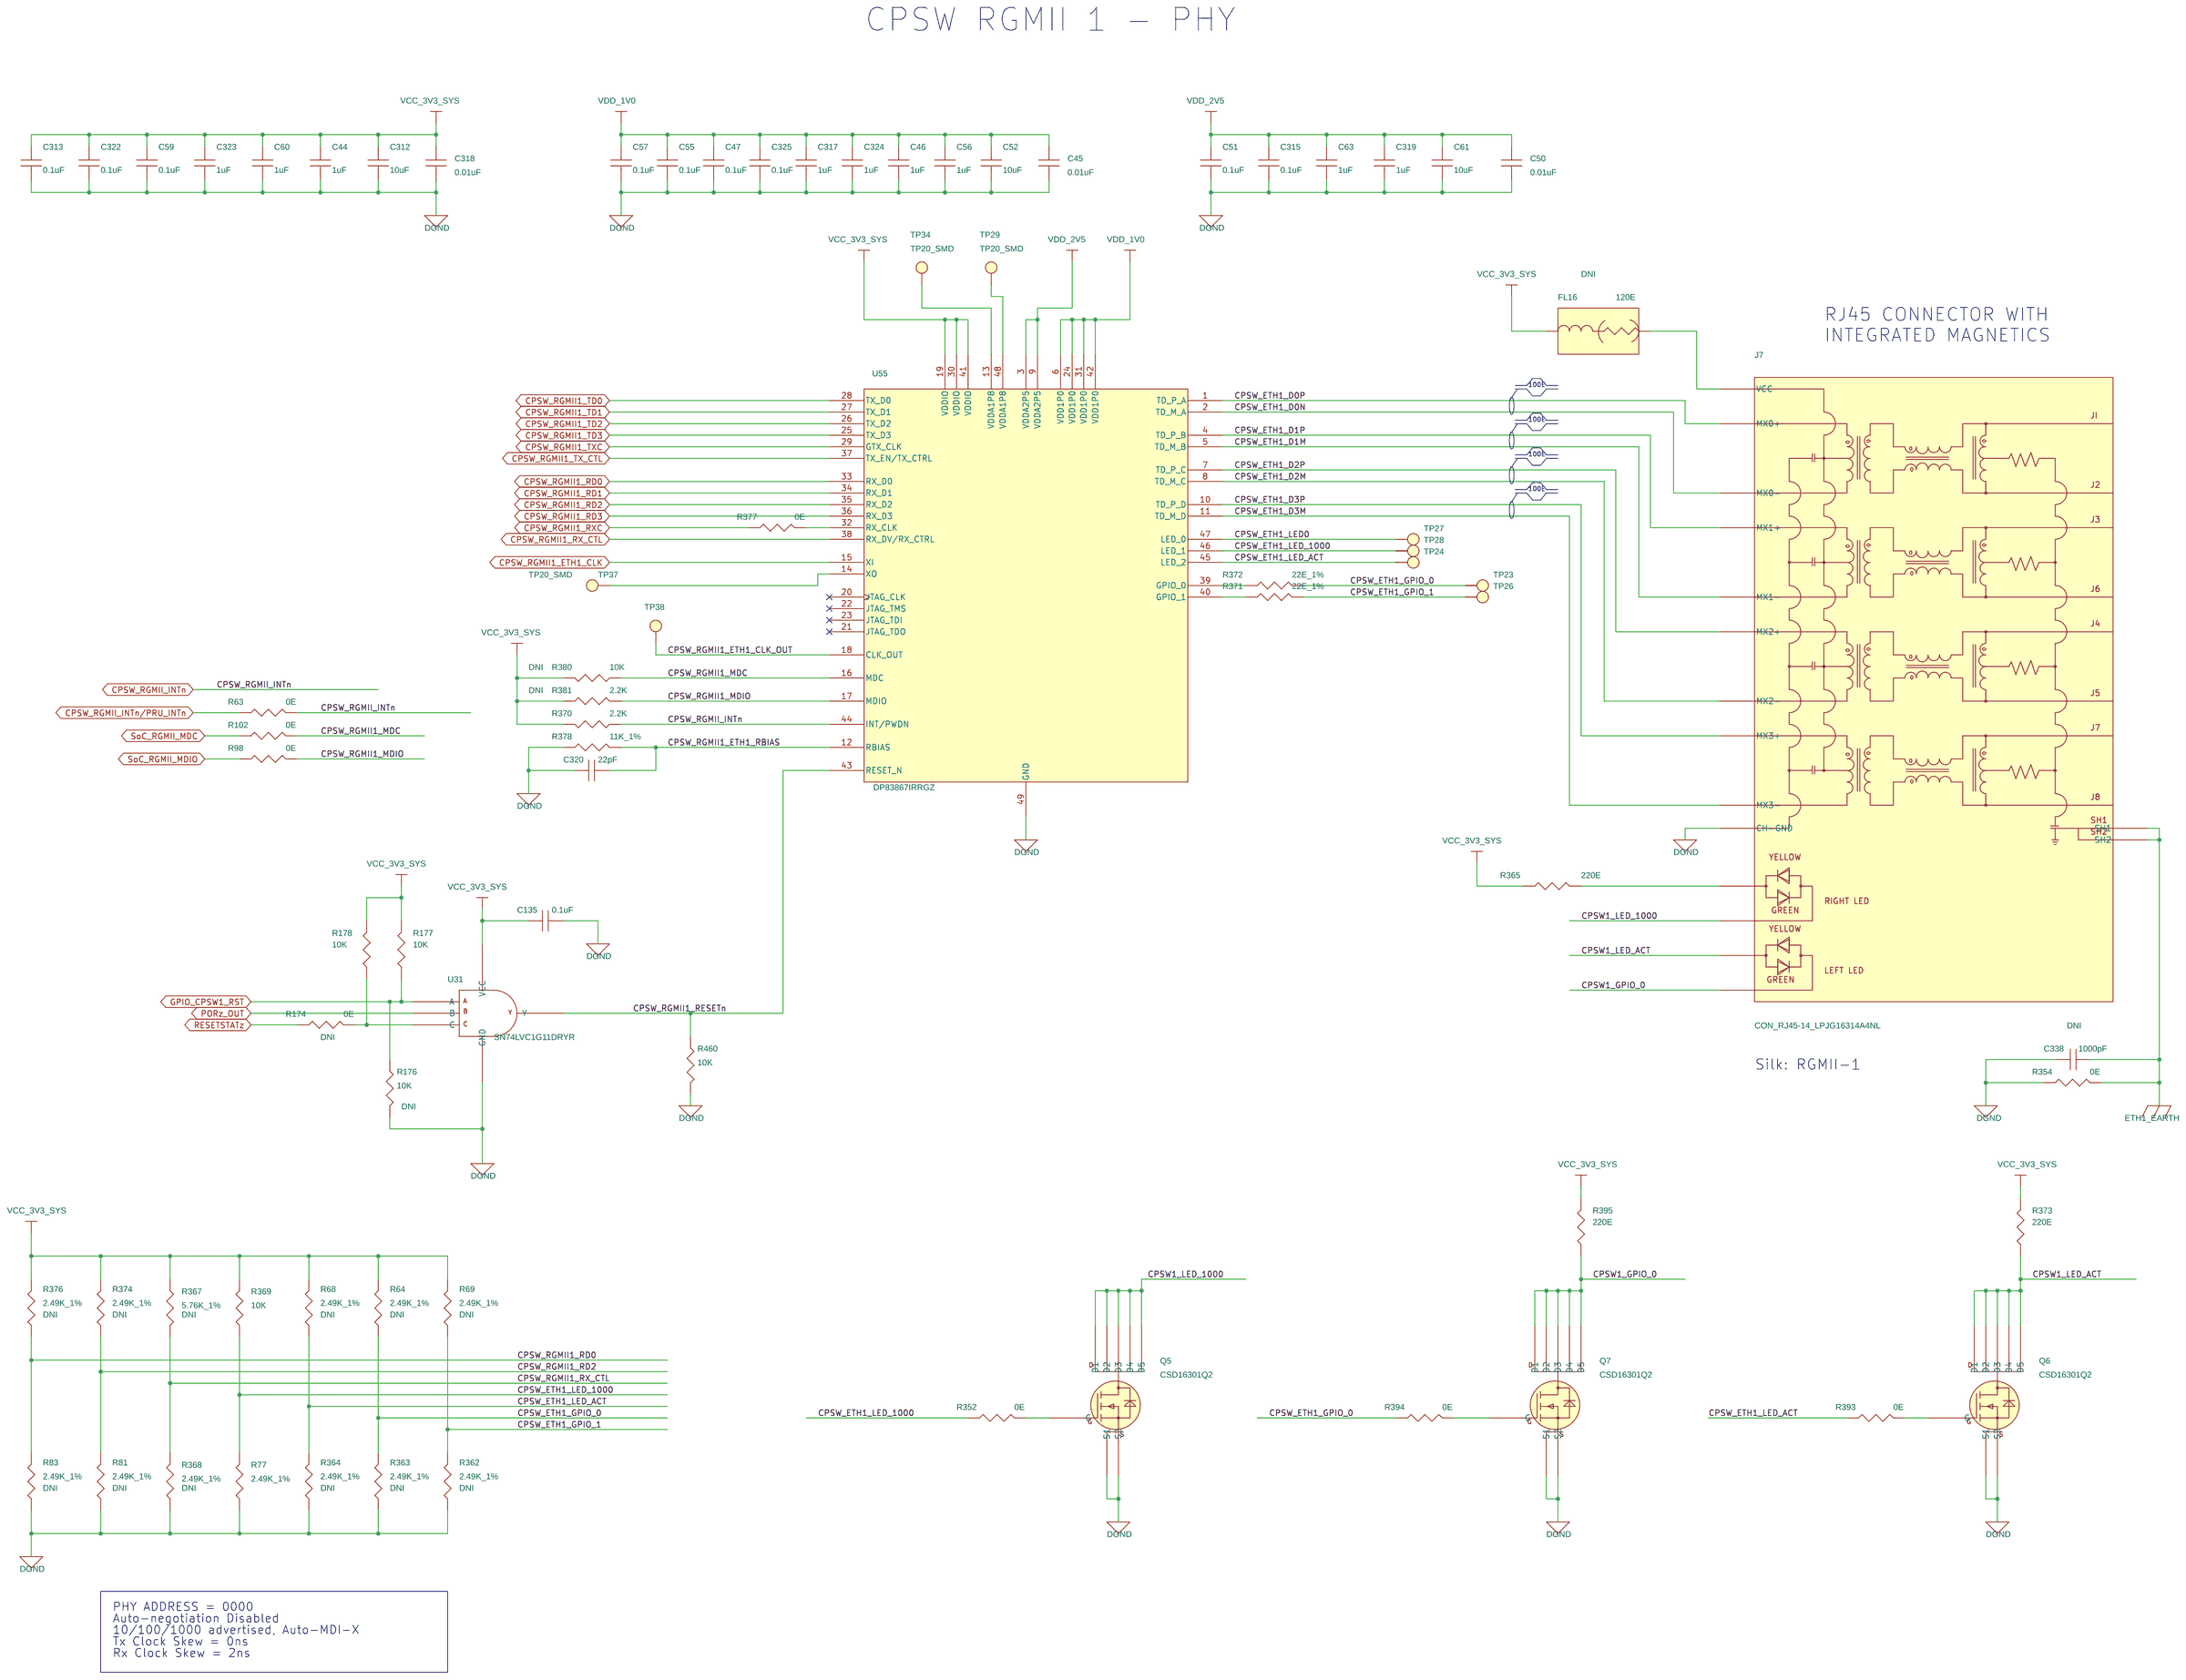
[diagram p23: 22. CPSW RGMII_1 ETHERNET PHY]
25 24. PHY CLK & LED DRIVER: size C; title: ETHERNET PHY CLOCK BUFFER & LED DRIVER

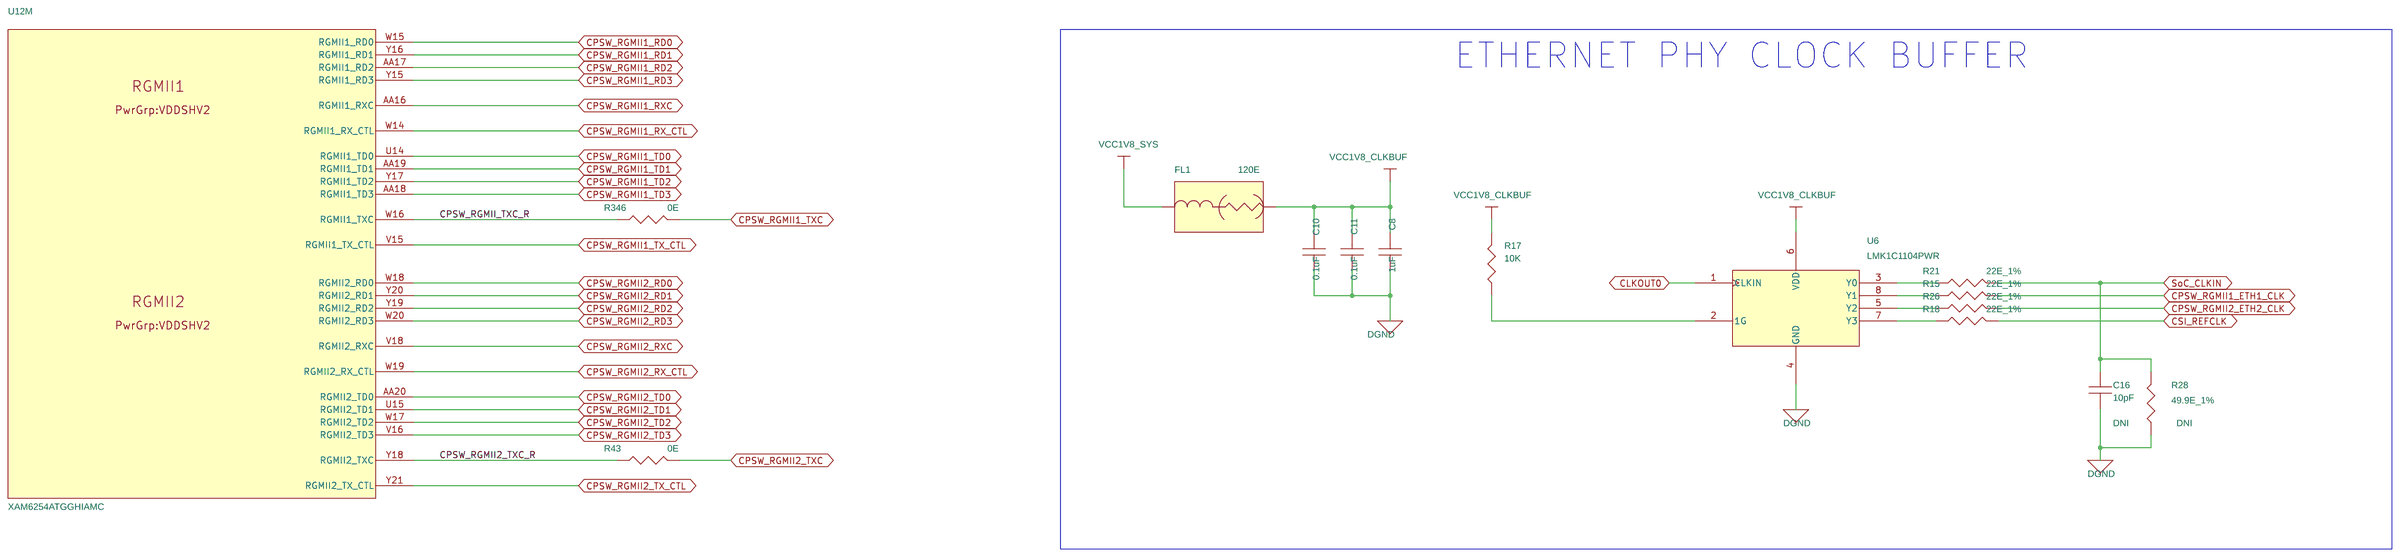
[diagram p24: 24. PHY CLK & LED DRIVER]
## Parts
sheet 22. CPSW RGMII_1 ETHERNET PHY
C44  1uF  [CAP0201_0-5]
C45  0.01uF  [CAP0201_0-5]
C46  1uF  [CAP0201_0-5]
C47  0.1uF  [CAP0201_0-5]
C50  0.01uF  [CAP0201_0-5]
C51  0.1uF  [CAP0201_0-5]
C52  10uF  [CAP0402_0-75]
C55  0.1uF  [CAP0201_0-5]
C56  1uF  [CAP0201_0-5]
C57  0.1uF  [CAP0201_0-5]
C59  0.1uF  [CAP0201_0-5]
C60  1uF  [CAP0201_0-5]
C61  10uF  [CAP0402_0-75]
C63  1uF  [CAP0201_0-5]
C135  0.1uF  [CAP0201_0-5]
C312  10uF  [CAP0402_0-75]
C313  0.1uF  [CAP0201_0-5]
C315  0.1uF  [CAP0201_0-5]
C317  1uF  [CAP0201_0-5]
C318  0.01uF  [CAP0201_0-5]
C319  1uF  [CAP0201_0-5]
C320  22pF  [CAP0201_0-5]
C322  0.1uF  [CAP0201_0-5]
C323  1uF  [CAP0201_0-5]
C324  1uF  [CAP0201_0-5]
C325  0.1uF  [CAP0201_0-5]
C338  1000pF  [CAP1206_1-75]
FL16  120E  [EMIFIL_BLM15A_0402_0-6]
J7  CON_RJ45-14_LPJG16314A4NL  [CON_RJ45-14_LPJG16314A4NL_S_R_T_13-6]
Q5  CSD16301Q2  [WSON6_CSD13202Q2_80X80_0-8]
Q6  CSD16301Q2  [WSON6_CSD13202Q2_80X80_0-8]
Q7  CSD16301Q2  [WSON6_CSD13202Q2_80X80_0-8]
R63  0E  [RES0402_0-5]
R64  2.49K_1%  [RES0402_0-5]
R68  2.49K_1%  [RES0402_0-5]
R69  2.49K_1%  [RES0402_0-5]
R77  2.49K_1%  [RES0402_0-5]
R81  2.49K_1%  [RES0402_0-5]
R83  2.49K_1%  [RES0402_0-5]
R98  0E  [RES0402_0-5]
R102  0E  [RES0402_0-5]
R174  0E  [RES0201_0-5]
R176  10K  [RES0201_0-5]
R177  10K  [RES0201_0-5]
R178  10K  [RES0201_0-5]
R352  0E  [RES0201_0-5]
R354  0E  [RES0603_0-75]
R362  2.49K_1%  [RES0402_0-5]
R363  2.49K_1%  [RES0402_0-5]
R364  2.49K_1%  [RES0402_0-5]
R365  220E  [RES0402_0-5]
R367  5.76K_1%  [RES0402_0-5]
R368  2.49K_1%  [RES0402_0-5]
R369  10K  [RES0201_0-5]
R370  2.2K  [RES0201_0-5]
R371  22E_1%  [RES0201_0-5]
R372  22E_1%  [RES0201_0-5]
R373  220E  [RES0402_0-5]
R374  2.49K_1%  [RES0402_0-5]
R376  2.49K_1%  [RES0402_0-5]
R377  0E  [RES0402_0-5]
R378  11K_1%  [RES0402_0-5]
R380  10K  [RES0201_0-5]
R381  2.2K  [RES0201_0-5]
R393  0E  [RES0201_0-5]
R394  0E  [RES0201_0-5]
R395  220E  [RES0402_0-5]
R460  10K  [RES0201_0-5]
TP23  TP20_SMD  [TP20_SMD]
TP24  TP20_SMD  [TP20_SMD]
TP26  TP20_SMD  [TP20_SMD]
TP27  TP20_SMD  [TP20_SMD]
TP28  TP20_SMD  [TP20_SMD]
TP29  TP20_SMD  [TP20_SMD]
TP34  TP20_SMD  [TP20_SMD]
TP37  TP20_SMD  [TP20_SMD]
TP38  TP20_SMD  [TP20_SMD]
U31  SN74LVC1G11DRYR  [SON6_SN74LVC2G17_40X60_0-6]
U55  DP83867IRRGZ  [QFN48_19-68_280X280_1]
sheet 24. PHY CLK & LED DRIVER
C8  1uF  [CAP0201_0-5]
C10  0.1uF  [CAP0201_0-5]
C11  0.1uF  [CAP0201_0-5]
C16  10pF  [CAP0201_0-5]
FL1  120E  [EMIFIL_BLM15A_0402_0-6]
R15  22E_1%  [RES0201_0-5]
R17  10K  [RES0201_0-5]
R18  22E_1%  [RES0201_0-5]
R21  22E_1%  [RES0201_0-5]
R26  22E_1%  [RES0201_0-5]
R28  49.9E_1%  [RES0402_0-5]
R43  0E  [RES0201_0-5]
R346  0E  [RES0201_0-5]
U6  LMK1C1104PWR  [TSSOP8_25-59_125X180_1-2]
sheet 31. PRU HEADER
U12  XAM6254ATGGHIAMC  [FCBGA441_31-49_680X680_2-6]  (sections A,B,C,D,E,F,G,H,I,J,K,L,M,N,O,P,Q,R)

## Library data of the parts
C8 C44 C46 C56 C60 C63 C317 C319 C323 C324 = CAP: CAP CERAMIC 1uF 16V 20% X5R 0201; Chkd/date: MANIRAJA/300520; Crtd /date: ALVY/260520; Custom_Duty: 15%; Customs_HS_Code: 85322990; Distributor_name: DIGIKEY; Distributor_part_number: 490-18654-1-ND; Footprint Path: Y:\MIS_DATABASE\Library\ALTIUM_TOOL\PCB_FOOTPRINTS\Altium_Footprint_Lib.PcbLib; Height: 0.39MM; Library Path: Y:\MIS_DATABASE\Library\ALTIUM_TOOL\SCHEMATICS_PARTS\MS_DISCRETE_Library.schlib; Mfr_name: MURATA; Mfr_part_number: GRM033R61C105ME15D; Mistral Part No: 120018090038-R; Package: 0201; Part_type: CAPACITORS\CERAMIC; Project: QCS610_NANOSOM; RoHS: RoHS; Temperature: -55°C+85°C; Tolerance: 20%; Voltage: 16V; Wattage: NA; Weight: 0.33mg; Datasheet: Y:\MIS_DATABASE\DATASHEETS\CAPACITORS\GRM033R61C105ME15.PDF
C45 C50 C318 = CAP: CAP CERAMIC 0.01uF 25V 10% X5R 0201; Chkd/date: MANIRAJA/230118; Crtd /date: MANIRAJA/230118; Custom_Duty: 15%; Customs_HS_Code: 85322990; Distributor_name: DIGIKEY; Distributor_part_number: GRM033R61E103KA12J-ND; Footprint Path: Y:\MIS_DATABASE\Library\ALTIUM_TOOL\PCB_FOOTPRINTS\Altium_Footprint_Lib.PcbLib; Height: 0.33MM; Library Path: Y:\MIS_DATABASE\Library\ALTIUM_TOOL\SCHEMATICS_PARTS\MS_DISCRETE_Library.schlib; Mfr_name: MURATA; Mfr_part_number: GRM033R61E103KA12J; Mistral Part No: 120018010007-R; Package: 0201; Part_type: CAPACITORS\CERAMIC; Project: TI_MAXIE_CPB; RoHS: RoHS; Temperature: -55°C+85°C; Tolerance: 10%; Voltage: 25V; Wattage: NA; Weight: 0.33mg; Datasheet: Y:\MIS_DATABASE\DATASHEETS\CAPACITORS\GRM033R61E103KA12.PDF
C10 C11 C47 C51 C55 C57 C59 C135 C313 C315 C322 C325 = CAP: CAP CERAMIC 0.1uF 16V 10% X5R 0201; Alt_Mfr_name: YAGEO AMERICA; Alt_Mfr_part_number: CC0402KRX5R8BB104; Chkd/date: MANIRAJA/230118; Crtd /date: MANIRAJA/230118; Custom_Duty: 15%; Customs_HS_Code: 85322990; Distributor_name: DIGIKEY; Distributor_part_number: 490-14305-1-ND; Footprint Path: Y:\MIS_DATABASE\Library\ALTIUM_TOOL\PCB_FOOTPRINTS\Altium_Footprint_Lib.PcbLib; Height: 0.33MM; Library Path: Y:\MIS_DATABASE\Library\ALTIUM_TOOL\SCHEMATICS_PARTS\MS_DISCRETE_Library.schlib; Mfr_name: MURATA; Mfr_part_number: GRM033R61C104KE14D; Mistral Part No: 120009030072-R; Package: 0201; Part_type: CAPACITORS\CERAMIC; Project: TI_MAXIE_CPB; RoHS: RoHS; Temperature: -55°C+85°C; Tolerance: 10%; Voltage: 16V; Wattage: NA; Weight: 0.33mg; Datasheet: Y:\MIS_DATABASE\DATASHEETS\CAPACITORS\GRM033R61C104KE14.PDF
C52 C61 C312 = CAP: CAP CERAMIC 10uF 10V 20% X5R 0402; Chkd/date: MANIRAJA/300520; Crtd /date: ALVY/260520; Custom_Duty: 15%; Customs_HS_Code: 85322990; Distributor_name: DIGIKEY; Distributor_part_number: 490-GRM155R61A106ME11DTR-ND; Footprint Path: Y:\MIS_DATABASE\Library\ALTIUM_TOOL\PCB_FOOTPRINTS\Altium_Footprint_Lib.PcbLib; Height: 0.55MM; Library Path: Y:\MIS_DATABASE\Library\ALTIUM_TOOL\SCHEMATICS_PARTS\MS_DISCRETE_Library.schlib; Mfr_name: MURATA; Mfr_part_number: GRM155R61A106ME11D; Mistral Part No: 120013110019-R; Package: 0402; Part_type: CAPACITORS\CERAMIC; Project: QCS610_NANOSOM; RoHS: RoHS; Temperature: -55°C+85°C; Tolerance: 20%; Voltage: 10V; Wattage: NA; Weight: 3.1mg; Datasheet: Y:\MIS_DATABASE\DATASHEETS\CAPACITORS\MURATA-GXX-SER_NOV17.PDF
C320 = CAP: CAP CERAMIC 22pF 25V 1% C0G(NP0) 0201; Chkd/date: MANIRAJA/270721; Crtd /date: ALVY/260721; Custom_Duty: 15%; Customs_HS_Code: 85322990; Distributor_name: DIGIKEY; Distributor_part_number: 490-14545-1-ND; Footprint Path: Y:\MIS_DATABASE\Library\ALTIUM_TOOL\PCB_FOOTPRINTS\Altium_Footprint_Lib.PcbLib; Height: 0.33MM; Library Path: Y:\MIS_DATABASE\Library\ALTIUM_TOOL\SCHEMATICS_PARTS\MS_DISCRETE_Library.schlib; Mfr_name: MURATA; Mfr_part_number: GRM0335C1E220FA01D; Mistral Part No: 120021070019-R; Package: 0201; Part_type: CAPACITORS\CERAMIC; Project: TI_AM335x SK_BRD; RoHS: RoHS; Temperature: -55°C+125°C; Tolerance: 1%; Voltage: 25V; Wattage: NA; Weight: 0.33mg; Datasheet: Y:\MIS_DATABASE\DATASHEETS\CAPACITORS\GRM0335C1E220FA01.PDF
C338 = CAP: CAP CERAMIC 1000pF 2KV 10% X7R 1206; Assembly_Instruction: DNI; Chkd/date: SHREESHAIL/291106; Crtd /date: MAZHAR/281106; Custom_Duty: 15%; Customs_HS_Code: 85322990; Distributor_name: DIGIKEY; Distributor_part_number: 478-2956-1-ND; Footprint Path: Y:\MIS_DATABASE\Library\ALTIUM_TOOL\PCB_FOOTPRINTS\Altium_Footprint_Lib.PcbLib; Height: 1.52MM; Library Path: Y:\MIS_DATABASE\Library\ALTIUM_TOOL\SCHEMATICS_PARTS\MS_DISCRETE_Library.schlib; Mfr_name: AVX CORPORATION; Mfr_part_number: 1206GC102KAT1A; Mistral Part No: 120015080006-R; Package: 1206; Part_type: CAPACITORS\CERAMIC; Project: ADR1B; RoHS: RoHS; Temperature: -55°C+125°C; Tolerance: 10%; Voltage: 2KV; Wattage: NA; Weight: 16.2mg; Datasheet: Y:\MIS_DATABASE\DATASHEETS\CAPACITORS\AVX_HV-MLC.PDF
FL16 = EMIFILTER_IND: IND FERRITE BEAD CHIP 120E 2A 0402; Assembly_Instruction: DNI; Chkd/date: NAVEED/241114; Crtd /date: USMAN/170613; Custom_Duty: 24%; Customs_HS_Code: 85369090; Distributor_name: DIGIKEY; Distributor_part_number: 490-9656-1-ND; Footprint Path: Y:\MIS_DATABASE\Library\ALTIUM_TOOL\PCB_FOOTPRINTS\Altium_Footprint_Lib.PcbLib; Height: 0.55MM; Library Path: Y:\MIS_DATABASE\Library\ALTIUM_TOOL\SCHEMATICS_PARTS\MS_FILTER_Library.schlib; Mfr_name: MURATA; Mfr_part_number: BLM15PX121SN1D; Mistral Part No: 130013060022-R; Package: 0402; Part_type: INDUCTOR; Project: GEN_3-8; RoHS: RoHS; Temperature: -55°C+125°C; Tolerance: 25%; Voltage: NA; Wattage: NA; Weight: 1mg; Datasheet: Y:\MIS_DATABASE\DATASHEETS\DISCRETES\INDUCTORS\BLM15-SN1-SER.PDF
J7 = CON_RJ45-14_LPJG16314A4NL: CON RJ-45 FEMALE 14POS RT TH; Chkd/date: VASANTHA/150714; Crtd /date: BALACHANDAR/120614; Custom_Duty: 24%; Customs_HS_Code: 85369090; Distributor_name: NA; Distributor_part_number: NA; Footprint Path: Y:\MIS_DATABASE\Library\ALTIUM_TOOL\PCB_FOOTPRINTS\Altium_Footprint_Lib.PcbLib; Height: 13.60MM; Library Path: Y:\MIS_DATABASE\Library\ALTIUM_TOOL\SCHEMATICS_PARTS\MS_CONNECTOR_Library.schlib; Mfr_name: LINK-PP; Mfr_part_number: LPJG16314A4NL; Mistral Part No: 150014060029-R; Package: THRU-HOLE; Part_type: CONNECTOR\JACK; Project: AEGIS; RoHS: RoHS; Temperature: -0°C+70°C; Tolerance: NA; Voltage: NA; Wattage: NA; Weight: NA; Datasheet: Y:\MIS_DATABASE\DATASHEETS\CONNECTORS\LPJG16314A4NL.PDF
Q5-Q7 = MOSFET_CSD17313Q2: IC MOSFET N-CHANNEL NEXFET 25V WSON6; Chkd/date: ALVY/071220; Crtd /date: MANIRAJA/071220; Custom_Duty: 15%; Customs_HS_Code: 85423100; Distributor_name: DIGIKEY; Distributor_part_number: 296-25260-1-ND; Footprint Path: Y:\MIS_DATABASE\Library\ALTIUM_TOOL\PCB_FOOTPRINTS\Altium_Footprint_Lib.PcbLib; Height: 0.80MM; Library Path: Y:\MIS_DATABASE\Library\ALTIUM_TOOL\SCHEMATICS_PARTS\MS_MOSFET_Library.schlib; Manufacturer: TEXAS INSTRUMENTS; Mfr_name: TEXAS INSTRUMENTS; Mistral Part No: 142020120008-R; Package: WSON6; Part_type: ICS\POWER\MOSFET; Project: TI_AM243x LP EVM; RoHS: RoHS; Temperature: -55°C+150°C; Tolerance: NA; Voltage: NA; Wattage: NA; Weight: 8.7mg; Datasheet: Y:\MIS_DATABASE\DATASHEETS\ICS\POWER\CSD16301Q2.PDF
R63 R98 R102 = RESISTOR: RES 0E 1/16W JUMPER 0402; Chkd/date: VASANTHA/201216; Crtd /date: MUDDU/190810; Custom_Duty: 15%; Customs_HS_Code: 85332119; Distributor_name: DIGIKEY; Distributor_part_number: 541-0.0JCT-ND; Footprint Path: Y:\MIS_DATABASE\Library\ALTIUM_TOOL\PCB_FOOTPRINTS\Altium_Footprint_Lib.PcbLib; Height: 0.40MM; Library Path: Y:\MIS_DATABASE\Library\ALTIUM_TOOL\SCHEMATICS_PARTS\MS_DISCRETE_Library.schlib; Mfr_name: VISHAY; Mfr_part_number: CRCW04020000Z0ED; Mistral Part No: 110010080019-R; Package: 0402; Part_type: RESISTORS\FIXED; Project: PB_BUGBASE; RoHS: RoHS; Temperature: -55°C+155°C; Tolerance: NA; Voltage: NA; Wattage: 1/16W; Weight: 0.65mg; Datasheet: Y:\MIS_DATABASE\DATASHEETS\RESISTORS\CRCW0603.PDF
R64 R68 R69 R81 R83 R362-R364 R368 R374 R376 = RESISTOR: RES 2.49K 1/16W 1% 0402; Assembly_Instruction: DNI; Chkd/date: VASANTHA/270516; Crtd /date: VASANTHA/270516; Custom_Duty: 15%; Customs_HS_Code: 85332119; Distributor_name: DIGIKEY; Distributor_part_number: 311-2.49KLRCT-ND; Footprint Path: Y:\MIS_DATABASE\Library\ALTIUM_TOOL\PCB_FOOTPRINTS\Altium_Footprint_Lib.PcbLib; Height: 0.40MM; Library Path: Y:\MIS_DATABASE\Library\ALTIUM_TOOL\SCHEMATICS_PARTS\MS_DISCRETE_Library.schlib; Mfr_name: YAGEO AMERICA; Mfr_part_number: RC0402FR-072K49L; Mistral Part No: 110016050020-R; Package: 0402; Part_type: RESISTORS\FIXED; Project: TMDXCSKCC; RoHS: RoHS; Temperature: -55°C+155°C; Tolerance: 1%; Voltage: NA; Wattage: 1/16W; Weight: 0.65mg; Datasheet: Y:\MIS_DATABASE\DATASHEETS\RESISTORS\RCXXXXL-SER_MAR18.PDF
R77 = RESISTOR: RES 2.49K 1/16W 1% 0402; Chkd/date: VASANTHA/270516; Crtd /date: VASANTHA/270516; Custom_Duty: 15%; Customs_HS_Code: 85332119; Distributor_name: DIGIKEY; Distributor_part_number: 311-2.49KLRCT-ND; Footprint Path: Y:\MIS_DATABASE\Library\ALTIUM_TOOL\PCB_FOOTPRINTS\Altium_Footprint_Lib.PcbLib; Height: 0.40MM; Library Path: Y:\MIS_DATABASE\Library\ALTIUM_TOOL\SCHEMATICS_PARTS\MS_DISCRETE_Library.schlib; Mfr_name: YAGEO AMERICA; Mfr_part_number: RC0402FR-072K49L; Mistral Part No: 110016050020-R; Package: 0402; Part_type: RESISTORS\FIXED; Project: TMDXCSKCC; RoHS: RoHS; Temperature: -55°C+155°C; Tolerance: 1%; Voltage: NA; Wattage: 1/16W; Weight: 0.65mg; Datasheet: Y:\MIS_DATABASE\DATASHEETS\RESISTORS\RCXXXXL-SER_MAR18.PDF
R174 = RESISTOR: RES 0E 1/20W 5% 0201; Assembly_Instruction: DNI; Chkd/date: NAVEED/301214; Crtd /date: MUDDU/120710; Custom_Duty: 15%; Customs_HS_Code: 85332119; Distributor_name: DIGIKEY; Distributor_part_number: 311-0.0NCT-ND; Footprint Path: Y:\MIS_DATABASE\Library\ALTIUM_TOOL\PCB_FOOTPRINTS\Altium_Footprint_Lib.PcbLib; Height: 0.26MM; Library Path: Y:\MIS_DATABASE\Library\ALTIUM_TOOL\SCHEMATICS_PARTS\MS_DISCRETE_Library.schlib; Mfr_name: YAGEO AMERICA; Mfr_part_number: RC0201JR-070RL; Mistral Part No: 110010070067-R; Package: 0201; Part_type: RESISTORS\FIXED; Project: PB_BUGBASE; RoHS: RoHS; Temperature: -55°C+125°C; Tolerance: 5%; Voltage: NA; Wattage: 1/20W; Weight: 0.17mg; Datasheet: Y:\MIS_DATABASE\DATASHEETS\RESISTORS\RCXXXXL-SER_MAR18.PDF
R176 R380 = RESISTOR: RES 10K 1/20W 5% 0201; Assembly_Instruction: DNI; Chkd/date: MANIRAJA/050517; Crtd /date: MANIRAJA/050517; Custom_Duty: 15%; Customs_HS_Code: 85332119; Distributor_name: DIGIKEY; Distributor_part_number: 311-10KNCT-ND; Footprint Path: Y:\MIS_DATABASE\Library\ALTIUM_TOOL\PCB_FOOTPRINTS\Altium_Footprint_Lib.PcbLib; Height: 0.26MM; Library Path: Y:\MIS_DATABASE\Library\ALTIUM_TOOL\SCHEMATICS_PARTS\MS_DISCRETE_Library.schlib; Mfr_name: YAGEO AMERICA; Mfr_part_number: RC0201JR-0710KL; Mistral Part No: 110010070051-R; Package: 0201; Part_type: RESISTORS\FIXED; Project: GOLDEN-I LITE; RoHS: RoHS; Temperature: -55°C+125°C; Tolerance: 5%; Voltage: NA; Wattage: 1/20W; Weight: 0.17mg; Datasheet: Y:\MIS_DATABASE\DATASHEETS\RESISTORS\RCXXXXL-SER_MAR18.PDF
R17 R177 R178 R369 R460 = RESISTOR: RES 10K 1/20W 5% 0201; Chkd/date: MANIRAJA/050517; Crtd /date: MANIRAJA/050517; Custom_Duty: 15%; Customs_HS_Code: 85332119; Distributor_name: DIGIKEY; Distributor_part_number: 311-10KNCT-ND; Footprint Path: Y:\MIS_DATABASE\Library\ALTIUM_TOOL\PCB_FOOTPRINTS\Altium_Footprint_Lib.PcbLib; Height: 0.26MM; Library Path: Y:\MIS_DATABASE\Library\ALTIUM_TOOL\SCHEMATICS_PARTS\MS_DISCRETE_Library.schlib; Mfr_name: YAGEO AMERICA; Mfr_part_number: RC0201JR-0710KL; Mistral Part No: 110010070051-R; Package: 0201; Part_type: RESISTORS\FIXED; Project: GOLDEN-I LITE; RoHS: RoHS; Temperature: -55°C+125°C; Tolerance: 5%; Voltage: NA; Wattage: 1/20W; Weight: 0.17mg; Datasheet: Y:\MIS_DATABASE\DATASHEETS\RESISTORS\RCXXXXL-SER_MAR18.PDF
R352 R393 R394 = RESISTOR: RES 0E 1/20W 5% 0201; Chkd/date: NAVEED/301214; Crtd /date: MUDDU/120710; Custom_Duty: 15%; Customs_HS_Code: 85332119; Distributor_name: DIGIKEY; Distributor_part_number: 311-0.0NCT-ND; Footprint Path: Y:\MIS_DATABASE\Library\ALTIUM_TOOL\PCB_FOOTPRINTS\Altium_Footprint_Lib.PcbLib; Height: 0.26MM; Library Path: Y:\MIS_DATABASE\Library\ALTIUM_TOOL\SCHEMATICS_PARTS\MS_DISCRETE_Library.schlib; Mfr_name: YAGEO AMERICA; Mfr_part_number: RC0201JR-070RL; Mistral Part No: 110010070067-R; Package: 0201; Part_type: RESISTORS\FIXED; Project: PB_BUGBASE; RoHS: RoHS; Temperature: -55°C+125°C; Tolerance: 5%; Voltage: NA; Wattage: 1/20W; Weight: 0.17mg; Datasheet: Y:\MIS_DATABASE\DATASHEETS\RESISTORS\RCXXXXL-SER_MAR18.PDF
R354 = RESISTOR: RES 0E 1/10W 5% 0603; Chkd/date: MANIRAJA/051217; Crtd /date: BAVISH/180211; Custom_Duty: 15%; Customs_HS_Code: 85332119; Distributor_name: DIGIKEY; Distributor_part_number: 311-0.0GRCT-ND; Footprint Path: Y:\MIS_DATABASE\Library\ALTIUM_TOOL\PCB_FOOTPRINTS\Altium_Footprint_Lib.PcbLib; Height: 0.55MM; Library Path: Y:\MIS_DATABASE\Library\ALTIUM_TOOL\SCHEMATICS_PARTS\MS_DISCRETE_Library.schlib; Mfr_name: YAGEO AMERICA; Mfr_part_number: RC0603JR-070RL; Mistral Part No: 110011020013-R; Package: 0603; Part_type: RESISTORS\FIXED; Project: KENNEL; RoHS: RoHS; Temperature: -55°C+155°C; Tolerance: 5%; Voltage: NA; Wattage: 1/10W; Weight: 2mg; Datasheet: Y:\MIS_DATABASE\DATASHEETS\RESISTORS\RCXXXXL-SER_MAR18.PDF
R365 R373 R395 = RESISTOR: RES 220E 1/10W 5% 0402; Chkd/date: VASANTHA/291216; Crtd /date: GEETHA/260406; Custom_Duty: 15%; Customs_HS_Code: 85332119; Distributor_name: DIGIKEY; Distributor_part_number: P220JCT-ND; Footprint Path: Y:\MIS_DATABASE\Library\ALTIUM_TOOL\PCB_FOOTPRINTS\Altium_Footprint_Lib.PcbLib; Height: 0.40MM; Library Path: Y:\MIS_DATABASE\Library\ALTIUM_TOOL\SCHEMATICS_PARTS\MS_DISCRETE_Library.schlib; Mfr_name: PANASONIC-ECG; Mfr_part_number: ERJ-2GEJ221X; Mistral Part No: 110009030506-R; Package: 0402; Part_type: RESISTORS\FIXED; Project: RED EYE; RoHS: RoHS; Temperature: -55°C+155°C; Tolerance: 5%; Voltage: NA; Wattage: 1/10W; Weight: 0.8mg; Datasheet: Y:\MIS_DATABASE\DATASHEETS\RESISTORS\PAN-ERJSER_NOV17.PDF
R367 = RESISTOR: RES 5.76K 1/10W 1% 0402; Assembly_Instruction: DNI; Chkd/date: MAZHAR/150709; Crtd /date: USMAN/220808; Custom_Duty: 15%; Customs_HS_Code: 85332119; Distributor_name: DIGIKEY; Distributor_part_number: P5.76KLCT-ND; Footprint Path: Y:\MIS_DATABASE\Library\ALTIUM_TOOL\PCB_FOOTPRINTS\Altium_Footprint_Lib.PcbLib; Height: 0.40MM; Library Path: Y:\MIS_DATABASE\Library\ALTIUM_TOOL\SCHEMATICS_PARTS\MS_DISCRETE_Library.schlib; Mfr_name: PANASONIC-ECG; Mfr_part_number: ERJ-2RKF5761X; Mistral Part No: 110009030945-R; Package: 0402; Part_type: RESISTORS\FIXED; Project: CPB; RoHS: RoHS; Temperature: -55°C+155°C; Tolerance: 1%; Voltage: NA; Wattage: 1/10W; Weight: 0.8mg; Datasheet: Y:\MIS_DATABASE\DATASHEETS\RESISTORS\PAN-ERJSER_NOV17.PDF
R370 = RESISTOR: RES 2.2K 1/20W 5% 0201; Chkd/date: MANIRAJA/310821; Crtd /date: ALVY/310821; Custom_Duty: 15%; Customs_HS_Code: 85332119; Distributor_name: DIGIKEY; Distributor_part_number: P123277CT-ND; Footprint Path: Y:\MIS_DATABASE\Library\ALTIUM_TOOL\PCB_FOOTPRINTS\Altium_Footprint_Lib.PcbLib; Height: 0.26MM; Library Path: Y:\MIS_DATABASE\Library\ALTIUM_TOOL\SCHEMATICS_PARTS\MS_DISCRETE_Library.schlib; Mfr_name: PANASONIC-ECG; Mfr_part_number: ERJ-1GNJ222C; Mistral Part No: 110009030427-R; Package: 0201; Part_type: RESISTORS\FIXED; Project: TI_AM335x SK_BRD; RoHS: RoHS; Temperature: -55°C+125°C; Tolerance: 5%; Voltage: NA; Wattage: 1/20W; Weight: 0.15mg; Datasheet: Y:\MIS_DATABASE\DATASHEETS\RESISTORS\PAN-ERJSER_NOV17.PDF
R15 R18 R21 R26 R371 R372 = RESISTOR: RES 22E 1/20W 1% 0201; Chkd/date: PRAVEEN/080922; Crtd /date: TAMILARASU/080922; Custom_Duty: 15%; Customs_HS_Code: 85332119; Distributor_name: DIGIKEY; Distributor_part_number: P122843CT-ND; Footprint Path: Y:\MIS_DATABASE\Library\ALTIUM_TOOL\PCB_FOOTPRINTS\Altium_Footprint_Lib.PcbLib; Height: 0.26MM; Library Path: Y:\MIS_DATABASE\Library\ALTIUM_TOOL\SCHEMATICS_PARTS\MS_DISCRETE_Library.schlib; Mfr_name: PANASONIC-ECG; Mfr_part_number: ERJ-1GNF22R0C; Mistral Part No: 110022090007-R; Package: 0201; Part_type: RESISTORS\FIXED; Project: SK AM62Q LP EVM BRD; RoHS: RoHS; Temperature: -55°C+125°C; Tolerance: 1%; Voltage: NA; Wattage: 1/20W; Weight: 0.15mg; Datasheet: Y:\MIS_DATABASE\DATASHEETS\RESISTORS\PAN-ERJSER_NOV17.PDF
R377 = RESISTOR: RES 0E 1/16W JUMPER 0402; Chkd/date: VASANTHA/201216; Crtd /date: MUDDU/190810; Custom_Duty: 15%; Customs_HS_Code: 85332119; Distributor_name: DIGIKEY; Distributor_part_number: 541-0.0JCT-ND; Footprint Path: Y:\MIS_DATABASE\Library\ALTIUM_TOOL\PCB_FOOTPRINTS\Altium_Footprint_Lib.PcbLib; Height: 0.40MM; Library Path: Y:\MIS_DATABASE\Library\ALTIUM_TOOL\SCHEMATICS_PARTS\MS_DISCRETE_Library.schlib; Mfr_name: VISHAY; Mfr_part_number: CRCW04020000Z0ED; Mistral Part No: 110010080019-R; Package: 0402; Part_type: RESISTORS\FIXED; Project: PB_BUGBASE; RoHS: RoHS; SIGNAL_MODEL: RESISTOR_RES0402_0-5_0E_0E; Temperature: -55°C+155°C; Tolerance: NA; Voltage: NA; Wattage: 1/16W; Weight: 0.65mg; Datasheet: Y:\MIS_DATABASE\DATASHEETS\RESISTORS\CRCW0603.PDF
R378 = RESISTOR: RES 11K 1/16W 1% 0402; Chkd/date: VASANTHA/251115; Crtd /date: VASANTHA/251115; Custom_Duty: 15%; Customs_HS_Code: 85332119; Distributor_name: DIGIKEY; Distributor_part_number: 311-11.0KLRCT-ND; Footprint Path: Y:\MIS_DATABASE\Library\ALTIUM_TOOL\PCB_FOOTPRINTS\Altium_Footprint_Lib.PcbLib; Height: 0.40MM; Library Path: Y:\MIS_DATABASE\Library\ALTIUM_TOOL\SCHEMATICS_PARTS\MS_DISCRETE_Library.schlib; Mfr_name: YAGEO AMERICA; Mfr_part_number: RC0402FR-0711KL; Mistral Part No: 110015110012-R; Package: 0402; Part_type: RESISTORS\FIXED; Project: TI_VLAN_SWITCH; RoHS: RoHS; Temperature: -55°C+155°C; Tolerance: 1%; Voltage: NA; Wattage: 1/16W; Weight: 0.65mg; Datasheet: Y:\MIS_DATABASE\DATASHEETS\RESISTORS\RCXXXXL-SER_MAR18.PDF
R381 = RESISTOR: RES 2.2K 1/20W 5% 0201; Assembly_Instruction: DNI; Chkd/date: VASANTHA/010117; Crtd /date: MAZHAR/010605; Custom_Duty: 15%; Customs_HS_Code: 85332119; Distributor_name: DIGIKEY; Distributor_part_number: P2.2KAGCT-ND; Footprint Path: Y:\MIS_DATABASE\Library\ALTIUM_TOOL\PCB_FOOTPRINTS\Altium_Footprint_Lib.PcbLib; Height: 0.26MM; Library Path: Y:\MIS_DATABASE\Library\ALTIUM_TOOL\SCHEMATICS_PARTS\MS_DISCRETE_Library.schlib; Mfr_name: PANASONIC-ECG; Mfr_part_number: ERJ-1GEJ222C; Mistral Part No: 110009030427-R; Package: 0201; Part_type: RESISTORS\FIXED; Project: G4SLIM; RoHS: RoHS; Temperature: -55°C+125°C; Tolerance: 5%; Voltage: NA; Wattage: 1/20W; Weight: 0.15mg; Datasheet: Y:\MIS_DATABASE\DATASHEETS\RESISTORS\PAN-ERJXGE-FEB06.PDF
TP23 TP24 TP26-TP28 TP38 = TESTPOINT: TESTPOINT CIR 20 SMD; Chkd/date: SHREESHAIL/171006; Crtd /date: MAZHAR/171006; Custom_Duty: NA; Customs_HS_Code: NA; Distributor_name: NA; Distributor_part_number: NA; Footprint Path: Y:\MIS_DATABASE\Library\ALTIUM_TOOL\PCB_FOOTPRINTS\Altium_Footprint_Lib.PcbLib; Height: NA; Library Path: Y:\MIS_DATABASE\Library\ALTIUM_TOOL\SCHEMATICS_PARTS\MS_DISCRETE_Library.schlib; MECHANICAL 3D STEP FILE: NA; Mfr_name: LOCAL; Mistral Part No: NA; Package: SMD; Project: BT MODULE_CSRBC04; RoHS: NA; Temperature: NA; Tolerance: NA; Voltage: NA; Wattage: NA; Weight: NA; Datasheet: NA
TP29 TP34 TP37 = TESTPOINT: TESTPOINT CIR 20 SMD; Chkd/date: SHREESHAIL/171006; Crtd /date: MAZHAR/171006; Custom_Duty: NA; Customs_HS_Code: NA; Distributor_name: NA; Distributor_part_number: NA; Footprint Path: Y:\MIS_DATABASE\Library\ALTIUM_TOOL\PCB_FOOTPRINTS\Altium_Footprint_Lib.PcbLib; Height: NA; Library Path: Y:\MIS_DATABASE\Library\ALTIUM_TOOL\SCHEMATICS_PARTS\MS_DISCRETE_Library.schlib; MECHANICAL 3D STEP FILE: NA; Manufacturer: LOCAL; Mfr_name: LOCAL; Mistral Part No: NA; Package: SMD; Project: BT MODULE_CSRBC04; RoHS: NA; Temperature: NA; Tolerance: NA; Voltage: NA; Wattage: NA; Weight: NA; Datasheet: NA
U31 = SN74LVC1G11DCKR_SC70-6: IC SINGLE 3-INPUT POSITIVE-AND GATE SON6; Chkd/date: MANIRAJA/270121; Crtd /date: ALVY/270121; Custom_Duty: 15%; Customs_HS_Code: 85423100; Distributor_name: DIGIKEY; Distributor_part_number: 296-30120-1-ND; Footprint Path: Y:\MIS_DATABASE\Library\ALTIUM_TOOL\PCB_FOOTPRINTS\Altium_Footprint_Lib.PcbLib; Height: 0.60MM; Library Path: Y:\MIS_DATABASE\Library\ALTIUM_TOOL\SCHEMATICS_PARTS\MS_GATE_Library.schlib; Mfr_name: TEXAS INSTRUMENTS; Mistral Part No: 141021010013-R; Package: SON6; Part_type: ICS\DIGITAL\GATES; Project: AM64X_SKEVM; RoHS: RoHS; Temperature: -40°C+125°C; Tolerance: NA; Voltage: NA; Wattage: NA; Weight: 33mg; Datasheet: Y:\MIS_DATABASE\DATASHEETS\ICS\DIGITAL\GATES\SN74LVC1G_NOV16.PDF
U55 = DP83867IRRGZ_VQFN48: IC HIGH IMMUNITY 10/100/1000 Mb/s ETHERNET PHY LAYER TRANSCEIVER VQFN48; Chkd/date: MANIRAJA/110817; Crtd /date: MANIRAJA/110817; Custom_Duty: 15%; Customs_HS_Code: 85423100; Distributor_name: DIGIKEY; Distributor_part_number: DP83867IRRGZT-ND; Height: 1.00MM; Mfr_name: TEXAS INSTRUMENTS; Mistral Part No: 143017080002-R; Package: VQFN48; Part_type: ICS\TELECOM\TRANSCEIVER; Project: TI_SVB_CONTROLLER CARD; RoHS: RoHS; Temperature: -40°C+85°C; Tolerance: NA; Voltage: NA; Wattage: NA; Weight: NA; Datasheet: Y:\MIS_DATABASE\DATASHEETS\ICS\DIGITAL\BUSTRANSCEIVER\DP83867I.PDF
C16 = CAP: CAP CERAMIC 10pF 25V 5% HI-Q C0G(NP0) 0201; Assembly_Instruction: DNI; Chkd/date: VASANTHA/081216; Crtd /date: MANIRAJA/081216; Custom_Duty: 15%; Customs_HS_Code: 85322990; Distributor_name: DIGIKEY; Distributor_part_number: 490-13312-1-ND; Footprint Path: Y:\MIS_DATABASE\Library\ALTIUM_TOOL\PCB_FOOTPRINTS\Altium_Footprint_Lib.PcbLib; Height: 0.33MM; Library Path: Y:\MIS_DATABASE\Library\ALTIUM_TOOL\SCHEMATICS_PARTS\MS_DISCRETE_Library.schlib; Mfr_name: MURATA; Mfr_part_number: GJM0335C1E100JB01D; Mistral Part No: 120016120010-R; Package: 0201; Part_type: CAPACITORS\CERAMIC; Project: OCTBTS5200; RoHS: RoHS; Temperature: -55°C+125°C; Tolerance: 5%; Voltage: 25V; Wattage: NA; Weight: 0.33mg; Datasheet: Y:\MIS_DATABASE\DATASHEETS\CAPACITORS\MURATA-GXX-SER_NOV17.PDF
FL1 = EMIFILTER_IND: IND FERRITE BEAD CHIP 120E 2A 0402; Chkd/date: NAVEED/241114; Crtd /date: USMAN/170613; Custom_Duty: 24%; Customs_HS_Code: 85369090; Distributor_name: DIGIKEY; Distributor_part_number: 490-9656-1-ND; Footprint Path: Y:\MIS_DATABASE\Library\ALTIUM_TOOL\PCB_FOOTPRINTS\Altium_Footprint_Lib.PcbLib; Height: 0.55MM; Library Path: Y:\MIS_DATABASE\Library\ALTIUM_TOOL\SCHEMATICS_PARTS\MS_FILTER_Library.schlib; Mfr_name: MURATA; Mfr_part_number: BLM15PX121SN1D; Mistral Part No: 130013060022-R; Package: 0402; Part_type: INDUCTOR; Project: GEN_3-8; RoHS: RoHS; Temperature: -55°C+125°C; Tolerance: 25%; Voltage: NA; Wattage: NA; Weight: 1mg; Datasheet: Y:\MIS_DATABASE\DATASHEETS\DISCRETES\INDUCTORS\BLM15-SN1-SER.PDF
R28 = RESISTOR: RES 49.9E 1/16W 1% 0402; Assembly_Instruction: DNI; Chkd/date: MANIRAJA/210519; Crtd /date: MANIRAJA/210519; Custom_Duty: 15%; Customs_HS_Code: 85332119; Distributor_name: DIGIKEY; Distributor_part_number: 541-3967-1-ND; Footprint Path: Y:\MIS_DATABASE\Library\ALTIUM_TOOL\PCB_FOOTPRINTS\Altium_Footprint_Lib.PcbLib; Height: 0.35MM; Library Path: Y:\MIS_DATABASE\Library\ALTIUM_TOOL\SCHEMATICS_PARTS\MS_DISCRETE_Library.schlib; Mfr_name: VISHAY; Mfr_part_number: CRCW040249R9FKEDC; Mistral Part No: 110009030846-R; Package: 0402; Part_type: RESISTORS\FIXED; Project: RFSU_RFTJ_CARD; RoHS: RoHS; Temperature: -55°C+155°C; Tolerance: 1%; Voltage: NA; Wattage: 1/16W; Weight: 0.65mg; Datasheet: Y:\MIS_DATABASE\DATASHEETS\RESISTORS\CRCW_C-SER.PDF
R43 = RESISTOR: RES 0E 1/20W 5% 0201; Chkd/date: NAVEED/301214; Crtd /date: MUDDU/120710; Custom_Duty: 15%; Customs_HS_Code: 85332119; Distributor_name: DIGIKEY; Distributor_part_number: 311-0.0NCT-ND; Footprint Path: Y:\MIS_DATABASE\Library\ALTIUM_TOOL\PCB_FOOTPRINTS\Altium_Footprint_Lib.PcbLib; Height: 0.26MM; Library Path: Y:\MIS_DATABASE\Library\ALTIUM_TOOL\SCHEMATICS_PARTS\MS_DISCRETE_Library.schlib; Mfr_name: YAGEO AMERICA; Mfr_part_number: RC0201JR-070RL; Mistral Part No: 110010070067-R; Package: 0201; Part_type: RESISTORS\FIXED; Project: PB_BUGBASE; RoHS: RoHS; SIGNAL_MODEL: RESISTOR_RES0402_0-5_0E_0E; Temperature: -55°C+125°C; Tolerance: 5%; Voltage: NA; Wattage: 1/20W; Weight: 0.17mg; Datasheet: Y:\MIS_DATABASE\DATASHEETS\RESISTORS\RCXXXXL-SER_MAR18.PDF
R346 = RESISTOR: RES 0E 1/20W 5% 0201; Chkd/date: NAVEED/301214; Crtd /date: MUDDU/120710; Custom_Duty: 15%; Customs_HS_Code: 85332119; Distributor_name: DIGIKEY; Distributor_part_number: 311-0.0NCT-ND; Footprint Path: Y:\MIS_DATABASE\Library\ALTIUM_TOOL\PCB_FOOTPRINTS\Altium_Footprint_Lib.PcbLib; Height: 0.26MM; Library Path: Y:\MIS_DATABASE\Library\ALTIUM_TOOL\SCHEMATICS_PARTS\MS_DISCRETE_Library.schlib; Mfr_name: YAGEO AMERICA; Mfr_part_number: RC0201JR-070RL; Mistral Part No: 110010070067-R; Package: 0201; Part_type: RESISTORS\FIXED; Project: PB_BUGBASE; RoHS: RoHS; SIGNAL_MODEL: RESISTOR_RES0201_0-5_0E_0E; Temperature: -55°C+125°C; Tolerance: 5%; Voltage: NA; Wattage: 1/20W; Weight: 0.17mg; Datasheet: Y:\MIS_DATABASE\DATASHEETS\RESISTORS\RCXXXXL-SER_MAR18.PDF
U6 = LMK1C1104_TSSOP8: IC LVCMOS CLOCK BUFFER TSSOP8; Chkd/date: MANIRAJA/190520; Crtd /date: ALVY/190520; Custom_Duty: 15%; Customs_HS_Code: 85423100; Distributor_name: DIGIKEY; Distributor_part_number: 296-LMK1C1104PWRCT-ND; Footprint Path: Y:\MIS_DATABASE\Library\ALTIUM_TOOL\PCB_FOOTPRINTS\Altium_Footprint_Lib.PcbLib; Height: 1.20MM; Library Path: Y:\MIS_DATABASE\Library\ALTIUM_TOOL\SCHEMATICS_PARTS\MS_COMBINATIONAL_Library.schlib; Manufacturer: TEXAS INSTRUMENTS; Mfr_name: TEXAS INSTRUMENTS; Mistral Part No: 141020050011-R; Package: TSSOP8; Part_type: ICS\DIGITAL\COMBINATIONAL; Project: RETROFIT-RAD2; RoHS: RoHS; Temperature: -40°C+125°C; Tolerance: NA; Voltage: NA; Wattage: NA; Weight: 34.2mg; Datasheet: Y:\MIS_DATABASE\DATASHEETS\ICS\DIGITAL\COMBINATIONAL\LMK1C1104.PDF
U12 = AM62Q_SoC_FCBGA441: IC AM62Q SoC MICROPROCESSOR FCBGA441; Chkd/date: MANIRAJA/211021; Crtd /date: ALVY/211021; Custom_Duty: 15%; Customs_HS_Code: 85423100; Distributor_name: NA; Distributor_part_number: NA; Footprint Path: Y:\MIS_DATABASE\Library\ALTIUM_TOOL\PCB_FOOTPRINTS\Altium_Footprint_Lib.PcbLib; Height: 2.57MM; Library Path: Y:\MIS_DATABASE\Library\ALTIUM_TOOL\SCHEMATICS_PARTS\MS_MICROPROCESSOR_Library.schlib; Mfr_name: TEXAS INSTRUMENTS; Mistral Part No: 141221100001; Package: FCBGA441; Part_type: ICS\DIGITAL\MICROPROCESSOR; Project: TI_AM62Q_BRD; RoHS: NA; Temperature: NA; Tolerance: NA; Voltage: NA; Wattage: NA; Weight: NA; Datasheet: Y:\MIS_DATABASE\DATASHEETS\ICS\DIGITAL\MICROCONTROLLER\AM62Q-SoC.PDF

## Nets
DGND: C8.1 C10.1 C11.1 C16.2 C44.2 C45.2 C46.2 C47.2 C50.2 C51.2 C52.2 C55.2 C56.2 C57.2 C59.2 C60.2 C61.2 C63.2 C135.2 C312.2 C313.2 C315.2 C317.2 C318.2 C319.2 C320.1 C322.2 C323.2 C324.2 C325.2 C338.2 J7.1(CH-GND) Q5.4(S1) Q5.7(S2) Q6.4(S1) Q6.7(S2) Q7.4(S1) Q7.7(S2) R28.1 R77.1 R81.1 R83.1 R176.2 R354.2 R362.1 R363.1 R364.1 R368.1 R378.2 R460.2 U6.4(GND) U31.2(GND) U55.49(GND) ; also on sheet 1 2 3 4 13 14 15 16 17 18 19 20 21 22 23 26 27 28 29 30 31 32 33 34 35 36 37 38 39 40 41 42 43
VCC1V8_CLKBUF: C8.2 C10.2 C11.2 FL1.2 R17.2 U6.6(VDD) ; also on sheet 42
VCC1V8_SYS: FL1.1 ; also on sheet 4 16 19 20 22 34 37 39 40 42
VCC_3V3_SYS: C44.1 C59.1 C60.1 C135.1 C312.1 C313.1 C318.1 C322.1 C323.1 FL16.1 R64.2 R68.2 R69.2 R177.2 R178.2 R365.1 R367.1 R369.2 R370.2 R373.2 R374.2 R376.2 R380.2 R381.1 R395.2 U31.5(VCC) U55.19(VDDIO) U55.30(VDDIO) U55.41(VDDIO) ; also on sheet 1 4 15 16 19 20 21 23 26 27 29 30 31 32 33 34 36 37 38 39 40 41 42 43
VDD_1V0: C45.1 C46.1 C47.1 C52.1 C55.1 C56.1 C57.1 C317.1 C324.1 C325.1 U55.6(VDD1P0) U55.24(VDD1P0) U55.31(VDD1P0) U55.42(VDD1P0) ; also on sheet 1 15
VDD_2V5: C50.1 C51.1 C61.1 C63.1 C315.1 C319.1 U55.3(VDDA2P5) U55.9(VDDA2P5) ; also on sheet 1 15
CLKOUT0: U6.1(CLKIN) ; also on sheet 42
CPSW1_GPIO_0: J7.14 Q7.1(D1) Q7.2(D2) Q7.5(D3) Q7.6(D4) Q7.8(D5) R395.1
CPSW1_LED_1000: J7.12 Q5.1(D1) Q5.2(D2) Q5.5(D3) Q5.6(D4) Q5.8(D5)
CPSW1_LED_ACT: J7.13 Q6.1(D1) Q6.2(D2) Q6.5(D3) Q6.6(D4) Q6.8(D5) R373.1
CPSW_ETH1_D0N: J7.10(MX0-) U55.2(TD_M_A)
CPSW_ETH1_D0P: J7.9(MX0+) U55.1(TD_P_A)
CPSW_ETH1_D1M: J7.8(MX1-) U55.5(TD_M_B)
CPSW_ETH1_D1P: J7.7(MX1+) U55.4(TD_P_B)
CPSW_ETH1_D2M: J7.6(MX2-) U55.8(TD_M_C)
CPSW_ETH1_D2P: J7.5(MX2+) U55.7(TD_P_C)
CPSW_ETH1_D3M: J7.4(MX3-) U55.11(TD_M_D)
CPSW_ETH1_D3P: J7.3(MX3+) U55.10(TD_P_D)
CPSW_ETH1_GPIO_0: R64.1 R363.2 R372.1 R394.1 TP23.1(TP)
CPSW_ETH1_GPIO_1: R69.1 R362.2 R371.1 TP26.1(TP)
CPSW_ETH1_LED0: TP27.1(TP) U55.47(LED_0)
CPSW_ETH1_LED_1000: R77.2 R352.1 R369.1 TP28.1(TP) U55.46(LED_1)
CPSW_ETH1_LED_ACT: R68.1 R364.2 R393.1 TP24.1(TP) U55.45(LED_2)
CPSW_RGMII1_ETH1_CLK: R15.2 U55.15(XI)
CPSW_RGMII1_ETH1_CLK_OUT: TP38.1(TP) U55.18(CLK_OUT)
CPSW_RGMII1_ETH1_RBIAS: C320.2 R378.1 U55.12(RBIAS)
CPSW_RGMII1_MDC: R102.2 R380.1 U55.16(MDC)
CPSW_RGMII1_MDIO: R98.2 R381.2 U55.17(MDIO)
CPSW_RGMII1_RD0: R83.2 R376.1 U12.W15(RGMII1_RD0) U55.33(RX_D0)
CPSW_RGMII1_RD1: U12.Y16(RGMII1_RD1) U55.34(RX_D1)
CPSW_RGMII1_RD2: R81.2 R374.1 U12.AA17(RGMII1_RD2) U55.35(RX_D2)
CPSW_RGMII1_RD3: U12.Y15(RGMII1_RD3) U55.36(RX_D3)
CPSW_RGMII1_RESETn: R460.1 U31.4(Y) U55.43(RESET_N)
CPSW_RGMII1_RX_CTL: R367.2 R368.2 U12.W14(RGMII1_RX_CTL) U55.38(RX_DV/RX_CTRL)
CPSW_RGMII1_RXC: R377.1 U12.AA16(RGMII1_RXC)
CPSW_RGMII1_TD0: U12.U14(RGMII1_TD0) U55.28(TX_D0)
CPSW_RGMII1_TD1: U12.AA19(RGMII1_TD1) U55.27(TX_D1)
CPSW_RGMII1_TD2: U12.Y17(RGMII1_TD2) U55.26(TX_D2)
CPSW_RGMII1_TD3: U12.AA18(RGMII1_TD3) U55.25(TX_D3)
CPSW_RGMII1_TX_CTL: U12.V15(RGMII1_TX_CTL) U55.37(TX_EN/TX_CTRL)
CPSW_RGMII1_TXC: R346.2 U55.29(GTX_CLK)
CPSW_RGMII2_ETH2_CLK: R26.2 ; also on sheet 1
CPSW_RGMII2_RD0: U12.W18(RGMII2_RD0) ; also on sheet 1
CPSW_RGMII2_RD1: U12.Y20(RGMII2_RD1) ; also on sheet 1
CPSW_RGMII2_RD2: U12.Y19(RGMII2_RD2) ; also on sheet 1
CPSW_RGMII2_RD3: U12.W20(RGMII2_RD3) ; also on sheet 1
CPSW_RGMII2_RX_CTL: U12.W19(RGMII2_RX_CTL) ; also on sheet 1
CPSW_RGMII2_RXC: U12.V18(RGMII2_RXC) ; also on sheet 1
CPSW_RGMII2_TD0: U12.AA20(RGMII2_TD0) ; also on sheet 1
CPSW_RGMII2_TD1: U12.U15(RGMII2_TD1) ; also on sheet 1
CPSW_RGMII2_TD2: U12.W17(RGMII2_TD2) ; also on sheet 1
CPSW_RGMII2_TD3: U12.V16(RGMII2_TD3) ; also on sheet 1
CPSW_RGMII2_TX_CTL: U12.Y21(RGMII2_TX_CTL) ; also on sheet 1
CPSW_RGMII2_TXC: R43.2 ; also on sheet 1
CPSW_RGMII2_TXC_R: R43.1 U12.Y18(RGMII2_TXC)
CPSW_RGMII_INTn: R63.2 R370.1 U55.44(INT/PWDN) ; also on sheet 1
CPSW_RGMII_INTn/PRU_INTn: R63.1 ; also on sheet 32 42
CPSW_RGMII_TXC_R: R346.1 U12.W16(RGMII1_TXC)
CSI_REFCLK: R18.2 ; also on sheet 38
ETH1_EARTH: C338.1 J7.15(SH1) J7.16(SH2) R354.1
GPIO_CPSW1_RST: R176.1 R177.1 U31.1(A) ; also on sheet 39
PORz_OUT: U31.3(B) ; also on sheet 1 21 27 42
RESETSTATz: R174.1 ; also on sheet 1 4 20 21 22 27 32 37 38 39 40 41 42
SoC_CLKIN: C16.1 R21.2 R28.2 ; also on sheet 34
SoC_RGMII_MDC: R102.1 ; also on sheet 1 32
SoC_RGMII_MDIO: R98.1 ; also on sheet 1 32
N16943223: R17.1 U6.2(1G)
N17110597: TP34.1(TP) U55.13(VDDA1P8)
N17133547: FL16.2 J7.2(VCC)
N17137240: J7.11 R365.2
N17167245: R377.2 U55.32(RX_CLK)
N17269599: R174.2 R178.1 U31.6(C)
N17653582: Q5.3(G) R352.2
N17796705: Q6.3(G) R393.2
N17796716: Q7.3(G) R394.2
N18576337: R372.2 U55.39(GPIO_0)
N18576340: R371.2 U55.40(GPIO_1)
N20900570: R21.1 U6.3(Y0)
N20900572: R15.1 U6.8(Y1)
N20900574: R26.1 U6.5(Y2)
N20900809: R18.1 U6.7(Y3)
N21016640: TP29.1(TP) U55.48(VDDA1P8)
N21079949: TP37.1(TP) U55.14(XO)

Not connected (* = marked no-connect by the designer): U55 20(JTAG_CLK)* 21(JTAG_TDO)* 22(JTAG_TMS)* 23(JTAG_TDI)*

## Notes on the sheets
sheet 24
- CPSW RGMII 1 - PHY
- RJ45 CONNECTOR WITH
  INTEGRATED MAGNETICS
- 100E
- 100E
- 100E
- 100E
- Silk: RGMII-1
- PHY ADDRESS = 0000
- Auto-negotiation Disabled
- 10/100/1000 advertised, Auto-MDI-X
- Tx Clock Skew = 0ns
- Rx Clock Skew = 2ns
sheet 25
- ETHERNET PHY CLOCK BUFFER
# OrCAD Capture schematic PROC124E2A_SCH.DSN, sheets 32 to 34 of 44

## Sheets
32 31. PRU HEADER: size C; title: PRU HEADER
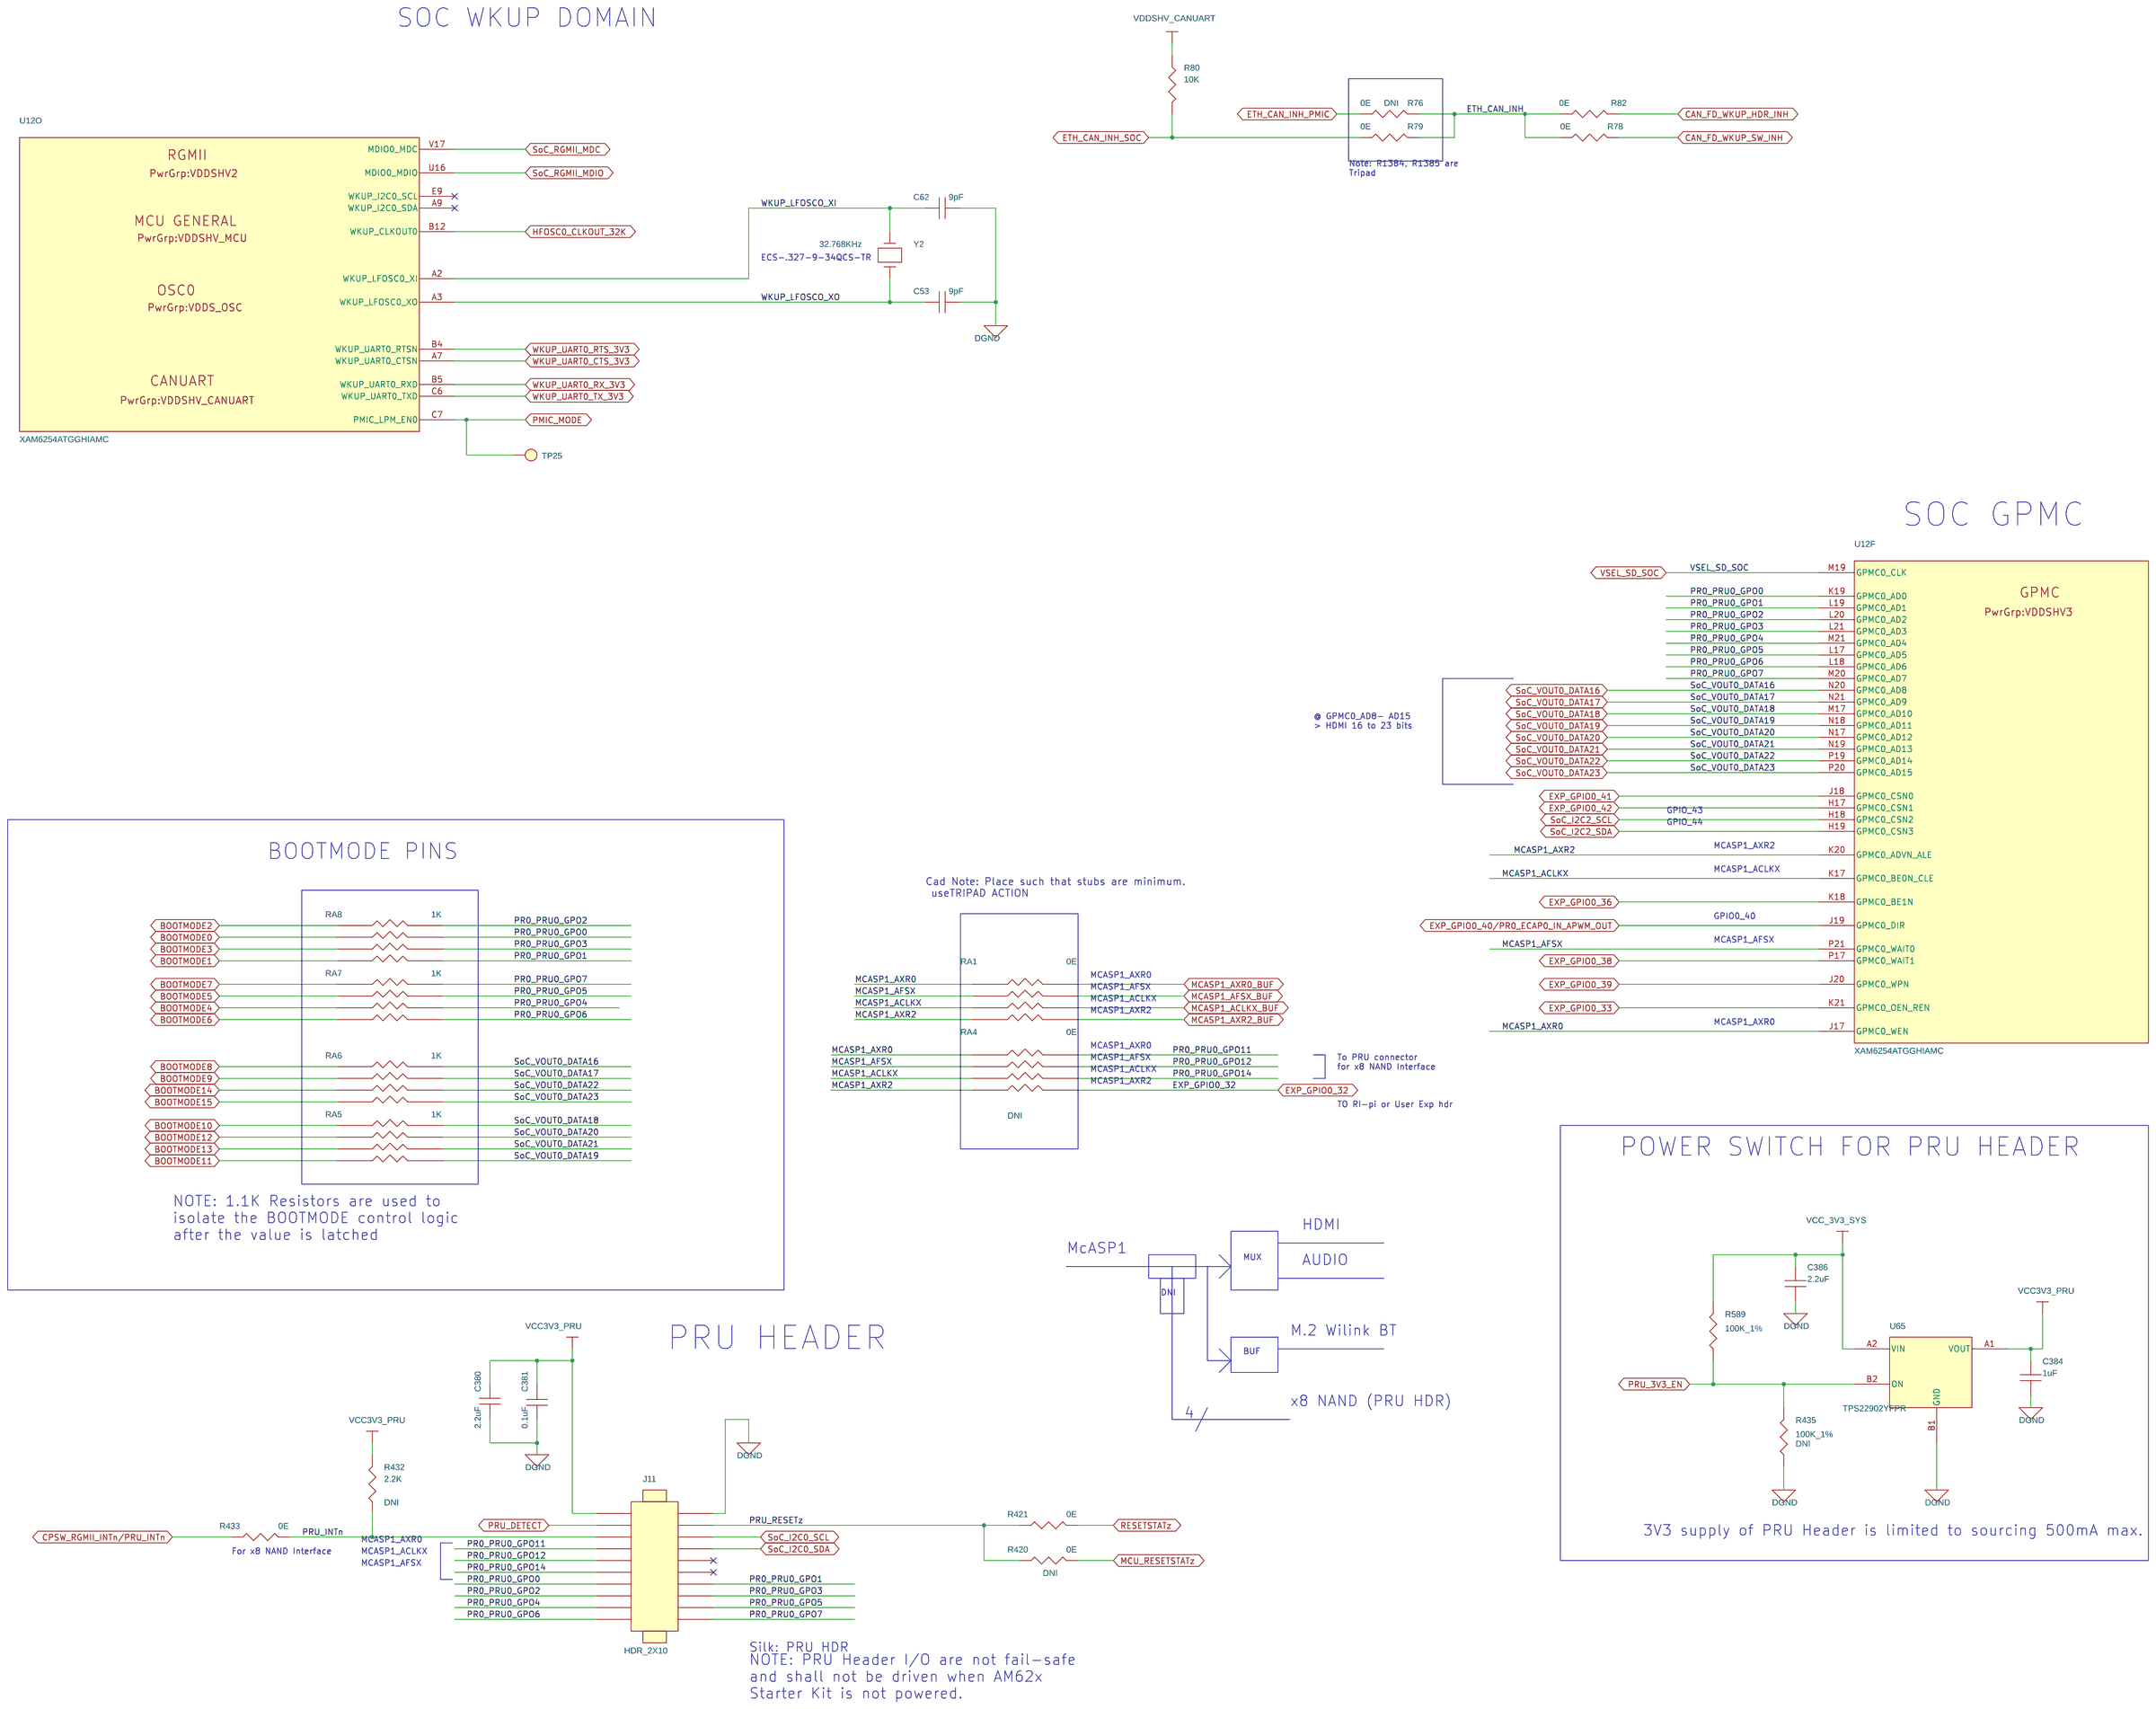
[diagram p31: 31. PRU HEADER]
33 32. USER EXPANSION CONNECTOR: size C; title: USER EXPANSION CONNECTOR
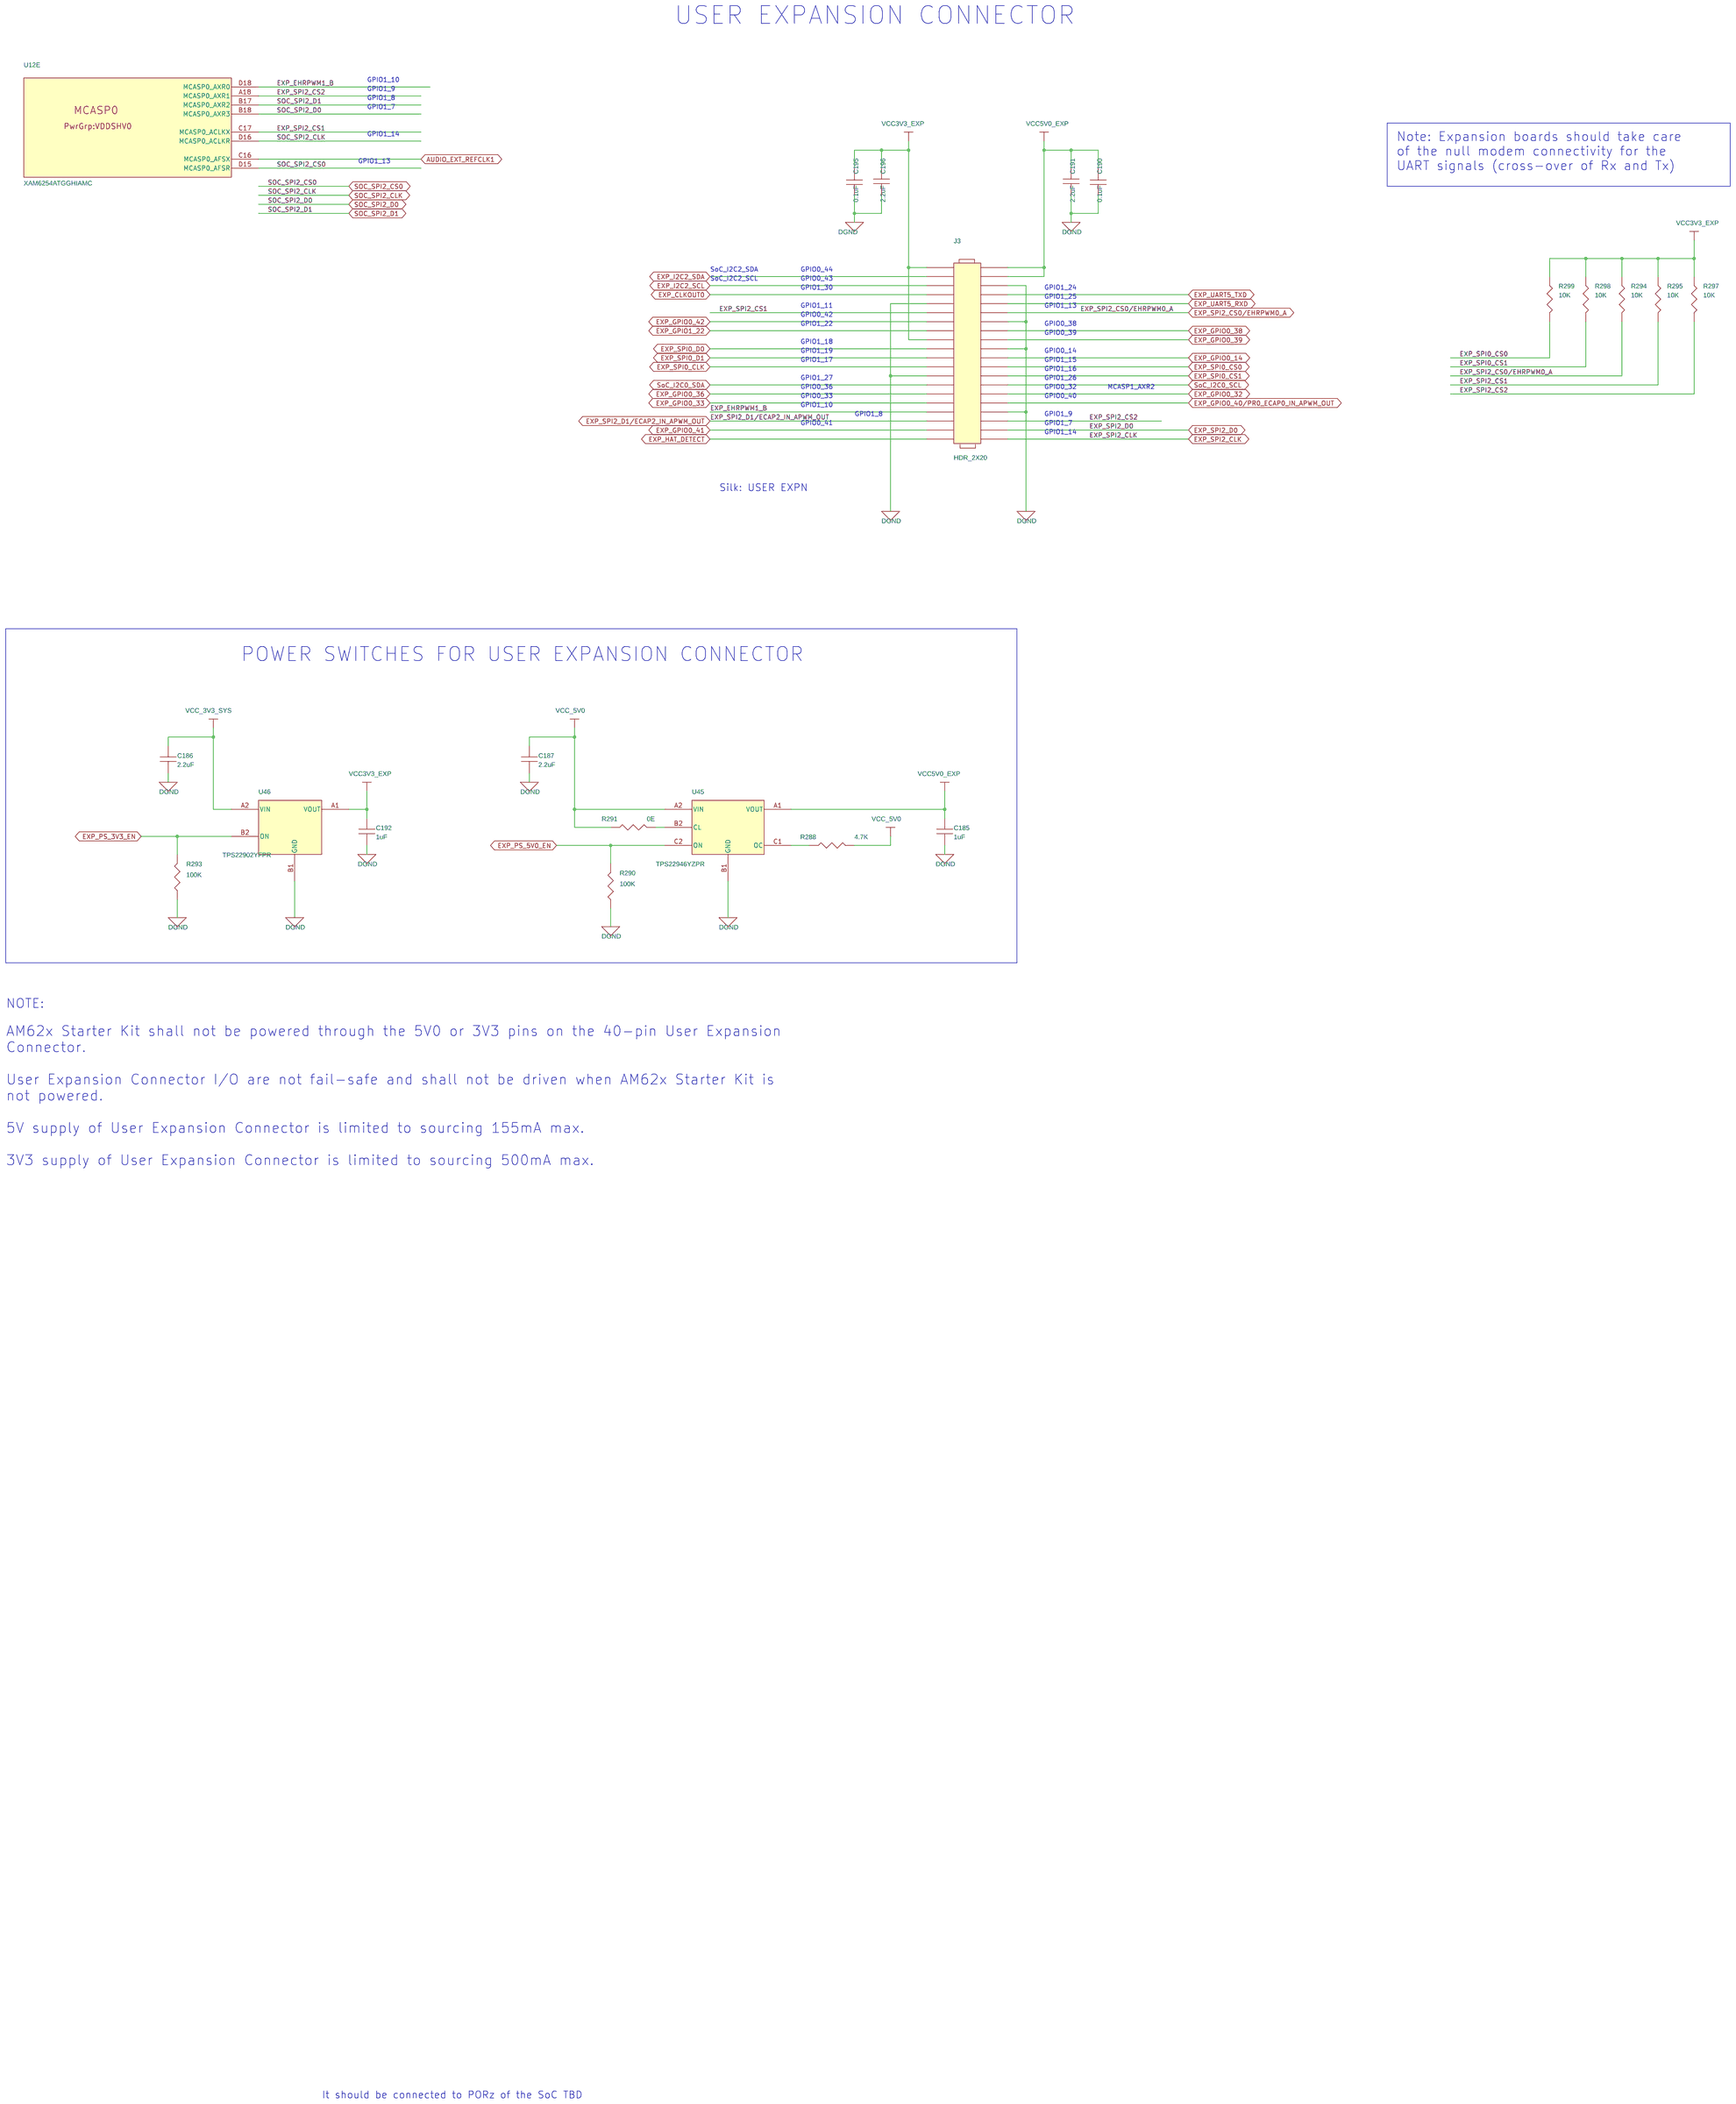
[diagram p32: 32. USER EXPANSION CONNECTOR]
34 33. MCU HEADER: size C; title: MCU HEADER

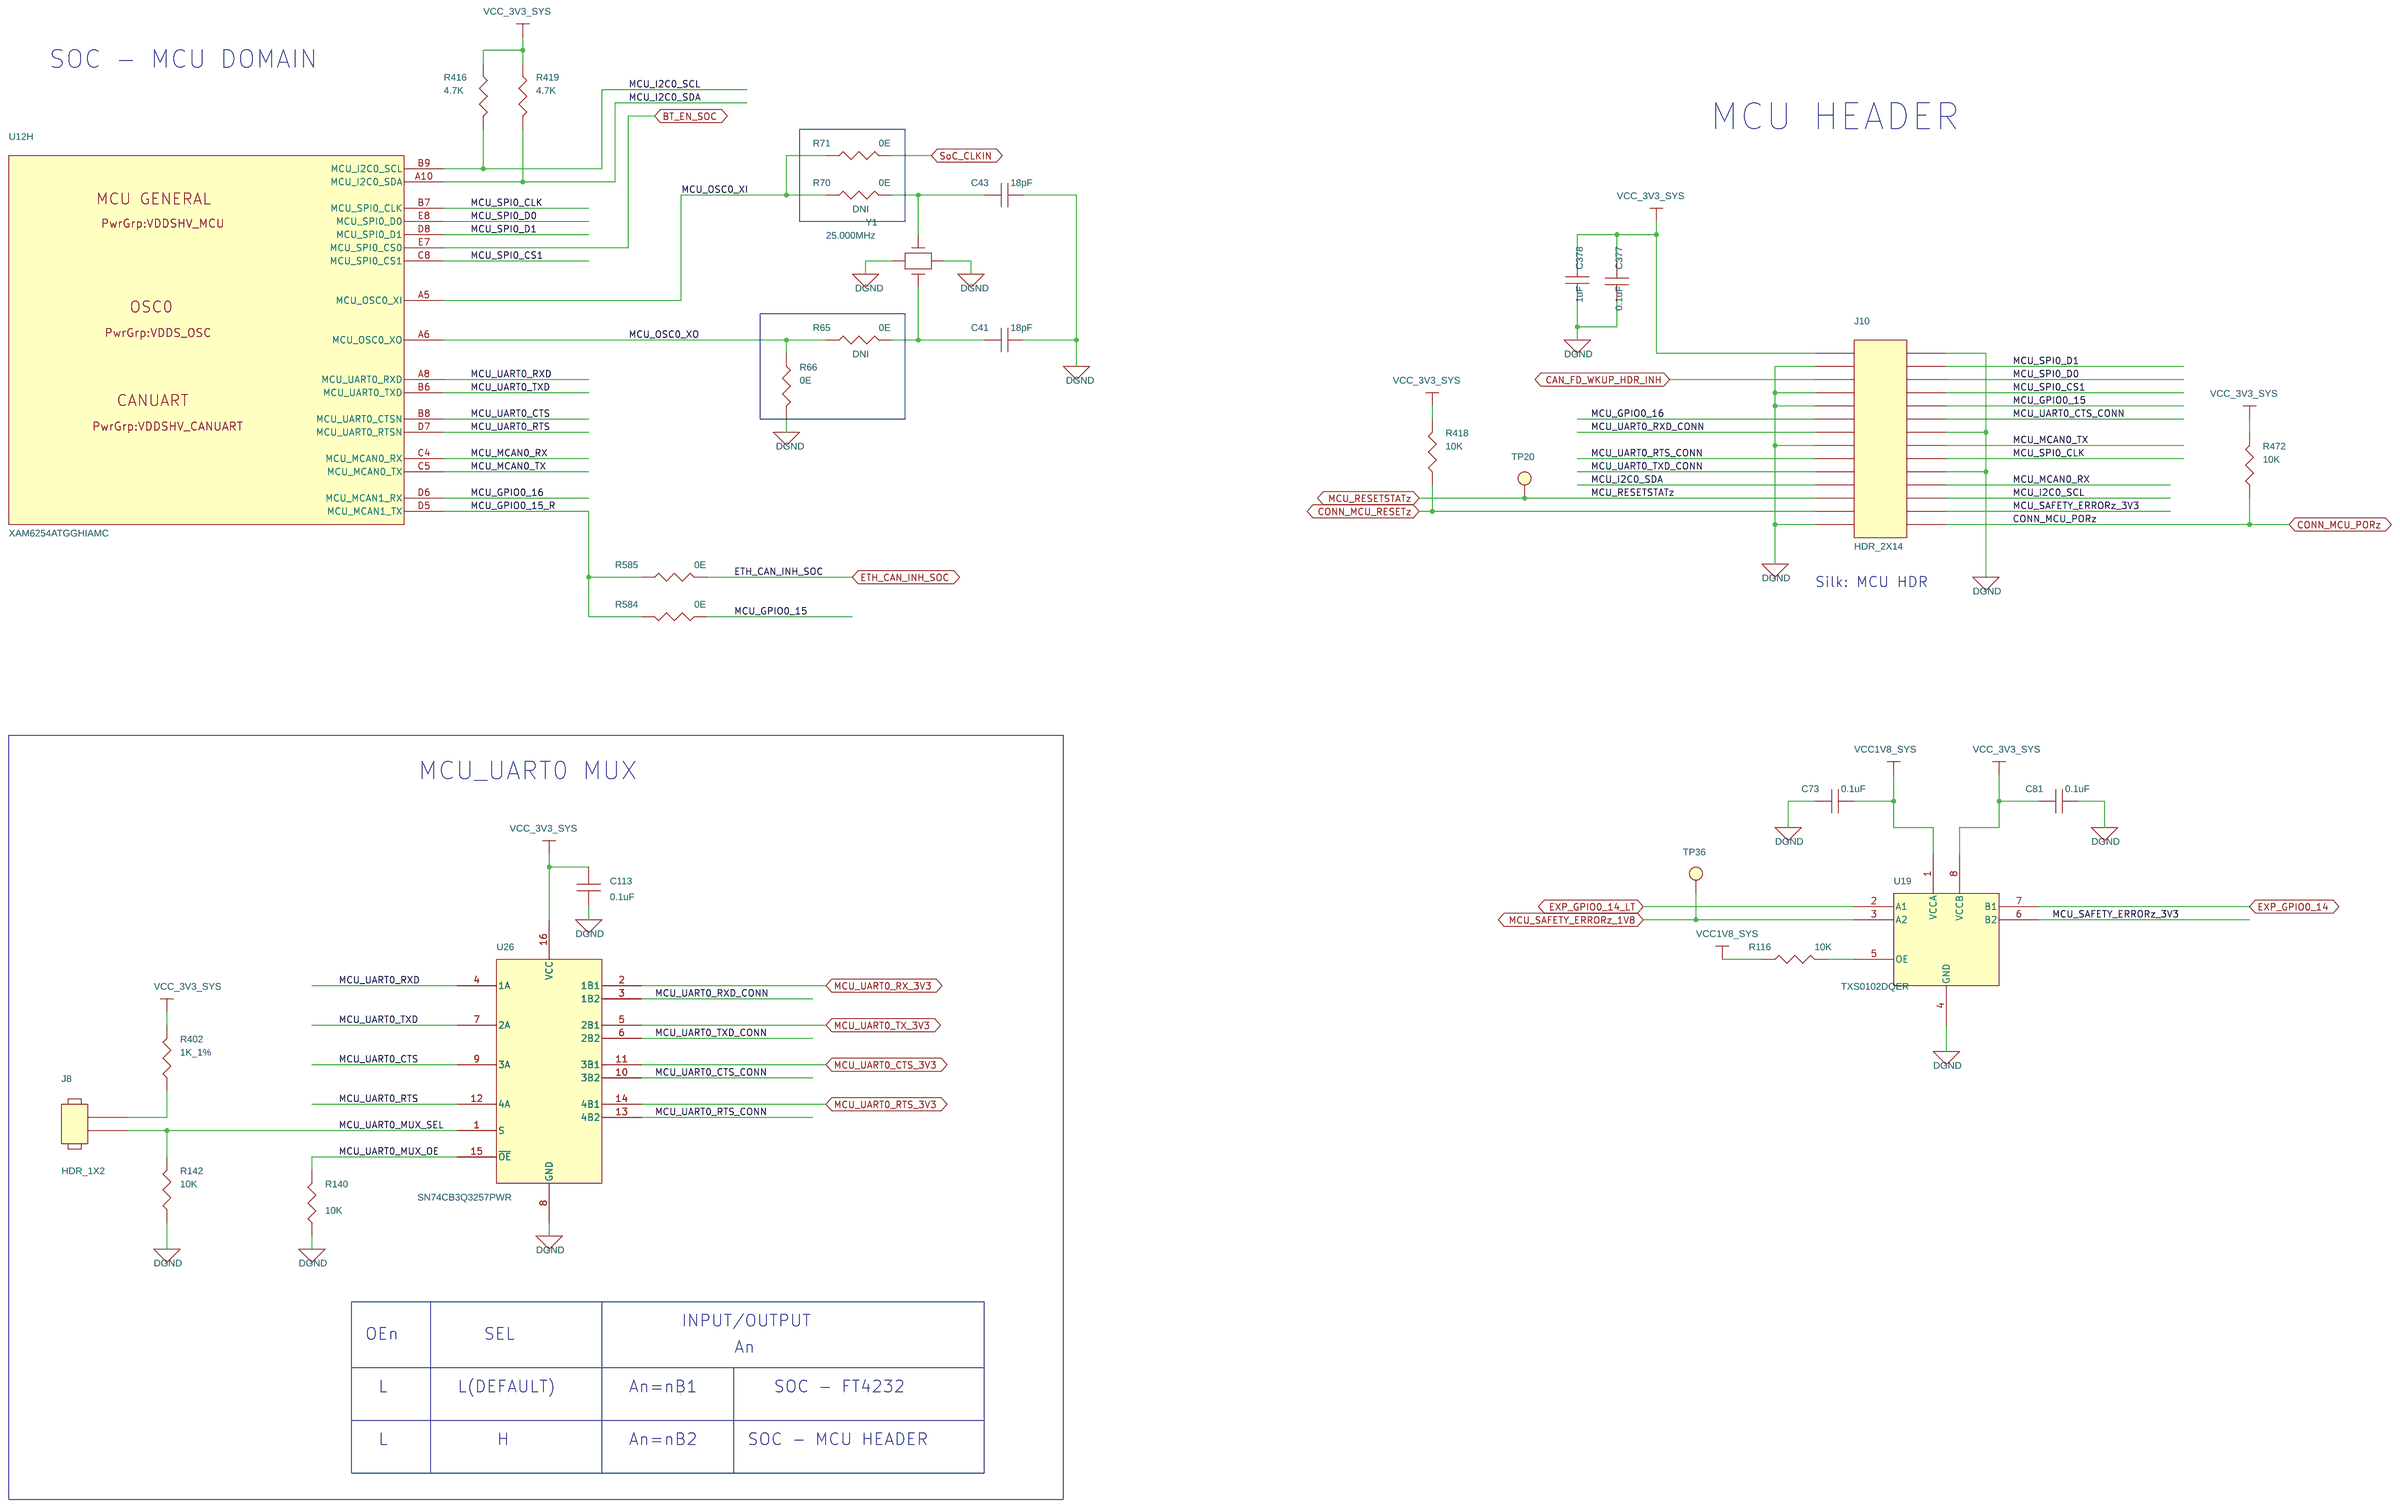
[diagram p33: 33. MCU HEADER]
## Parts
sheet 31. PRU HEADER
C53  9pF  [CAP0402_0-75]
C62  9pF  [CAP0402_0-75]
C380  2.2uF  [CAP0402_0-75]
C381  0.1uF  [CAP0201_0-5]
C384  1uF  [CAP0201_0-5]
C386  2.2uF  [CAP0402_0-75]
J11  HDR_2X10  [HDR_2X10_PREC010DAAN_S_T_8-4]
R76  0E  [RES0201_0-5]
R78  0E  [RES0201_0-5]
R79  0E  [RES0201_0-5]
R80  10K  [RES0201_0-5]
R82  0E  [RES0201_0-5]
R420  0E  [RES0201_0-5]
R421  0E  [RES0201_0-5]
R432  2.2K  [RES0201_0-5]
R433  0E  [RES0201_0-5]
R435  100K_1%  [RES0402_0-5]
R589  100K_1%  [RES0402_0-5]
RA1  0E  [RESA_EXB_0201-4_0-5]
RA4  0E  [RESA_EXB_0201-4_0-5]
RA5  1K  [RESA_EXB_0201-4_0-5]
RA6  1K  [RESA_EXB_0201-4_0-5]
RA7  1K  [RESA_EXB_0201-4_0-5]
RA8  1K  [RESA_EXB_0201-4_0-5]
TP25  TP20_SMD  [TP20_SMD]
U12  XAM6254ATGGHIAMC  [FCBGA441_31-49_680X680_2-6]  (sections A,B,C,D,E,F,G,H,I,J,K,L,M,N,O,P,Q,R)
U65  TPS22902YFPR  [DSBGA4_15-74_30X30_0-5]
Y2  32.768KHz  [XTAL_ECS-32_130X60_SMD_0-9]
sheet 32. USER EXPANSION CONNECTOR
C185  1uF  [CAP0201_0-5]
C186  2.2uF  [CAP0402_0-75]
C187  2.2uF  [CAP0402_0-75]
C190  0.1uF  [CAP0402_0-75]
C191  2.2uF  [CAP0402_0-75]
C192  1uF  [CAP0201_0-5]
C195  0.1uF  [CAP0402_0-75]
C196  2.2uF  [CAP0402_0-75]
J3  HDR_2X20  [HDR_2X20_PEC20DAAN_S_T_8-6]
R288  4.7K  [RES0201_0-5]
R290  100K  [RES0201_0-5]
R291  0E  [RES0201_0-5]
R293  100K  [RES0201_0-5]
R294  10K  [RES0201_0-5]
R295  10K  [RES0201_0-5]
R297  10K  [RES0201_0-5]
R298  10K  [RES0201_0-5]
R299  10K  [RES0201_0-5]
U45  TPS22946YZPR  [DSBGA6_19-68_40X60_0-5]
U46  TPS22902YFPR  [DSBGA4_15-74_30X30_0-5]
sheet 33. MCU HEADER
C41  18pF  [CAP0402_0-75]
C43  18pF  [CAP0402_0-75]
C73  0.1uF  [CAP0201_0-5]
C81  0.1uF  [CAP0201_0-5]
C113  0.1uF  [CAP0402_0-75]
C377  0.1uF  [CAP0402_0-75]
C378  1uF  [CAP0201_0-5]
J8  HDR_1X2  [HDR_1X2_90120-0122_S_T_5-6]
J10  HDR_2X14  [HDR_14X2_100_S_T]
R65  0E  [RES0201_0-5]
R66  0E  [RES0201_0-5]
R70  0E  [RES0201_0-5]
R71  0E  [RES0201_0-5]
R116  10K  [RES0201_0-5]
R140  10K  [RES0201_0-5]
R142  10K  [RES0201_0-5]
R402  1K_1%  [RES0201_0-5]
R416  4.7K  [RES0201_0-5]
R418  10K  [RES0201_0-5]
R419  4.7K  [RES0201_0-5]
R472  10K  [RES0201_0-5]
R584  0E  [RES0201_0-5]
R585  0E  [RES0201_0-5]
TP20  TP20_SMD  [TP20_SMD]
TP36  TP20_SMD  [TP20_SMD]
U19  TXS0102DQER  [X2SON8_TXS0102_40X60_0-4]
U26  SN74CB3Q3257PWR  [TSSOP16_25-59_205X180]
Y1  25.000MHz  [XTAL4_XRCGB-FM_80X60_SMD_0-7]

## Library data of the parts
C53 C62 = CAP: CAP CERAMIC 9pF 50V 0.5pF HI-Q C0G(NP0) 0402; Chkd/date: MANIRAJA/160921; Crtd /date: ALVY/150921; Custom_Duty: 15%; Customs_HS_Code: 85322990; Distributor_name: DIGIKEY; Distributor_part_number: 490-14793-1-ND; Footprint Path: Y:\MIS_DATABASE\Library\ALTIUM_TOOL\PCB_FOOTPRINTS\Altium_Footprint_Lib.PcbLib; Height: 0.55MM; Library Path: Y:\MIS_DATABASE\Library\ALTIUM_TOOL\SCHEMATICS_PARTS\MS_DISCRETE_Library.schlib; Mfr_name: MURATA; Mfr_part_number: GJM1555C1H9R0DB01D; Mistral Part No: 120021090005-R; Package: 0402; Part_type: CAPACITORS\CERAMIC; Project: TI_AM62x SKEVM_BRD; RoHS: RoHS; Temperature: -55°C+125°C; Tolerance: 0.5pF%; Voltage: 50V; Wattage: NA; Weight: 1.5mg; Datasheet: Y:\MIS_DATABASE\DATASHEETS\CAPACITORS\GJM1555C1H9R0DB01.PDF
C186 C187 C191 C196 C380 C386 = CAP: CAP CERAMIC 2.2uF 25V 10% X5R 0402; Chkd/date: ALVY/010721; Crtd /date: MANIRAJA/010721; Custom_Duty: 15%; Customs_HS_Code: 85322990; Distributor_name: DIGIKEY; Distributor_part_number: 490-12703-1-ND; Footprint Path: Y:\MIS_DATABASE\Library\ALTIUM_TOOL\PCB_FOOTPRINTS\Altium_Footprint_Lib.PcbLib; Height: 0.70MM; Library Path: Y:\MIS_DATABASE\Library\ALTIUM_TOOL\SCHEMATICS_PARTS\MS_DISCRETE_Library.schlib; Mfr_name: MURATA; Mfr_part_number: GRM155R61E225KE11D; Mistral Part No: 120015120001-R; Package: 0402; Part_type: CAPACITORS\CERAMIC; Project: TI_AM263X_CC; RoHS: RoHS; Temperature: -55°C+85°C; Tolerance: 10%; Voltage: 25V; Wattage: NA; Weight: 1.5mg; Datasheet: Y:\MIS_DATABASE\DATASHEETS\CAPACITORS\GRM155R61E225KE11.PDF
C73 C81 C381 = CAP: CAP CERAMIC 0.1uF 16V 10% X5R 0201; Alt_Mfr_name: YAGEO AMERICA; Alt_Mfr_part_number: CC0402KRX5R8BB104; Chkd/date: MANIRAJA/230118; Crtd /date: MANIRAJA/230118; Custom_Duty: 15%; Customs_HS_Code: 85322990; Distributor_name: DIGIKEY; Distributor_part_number: 490-14305-1-ND; Footprint Path: Y:\MIS_DATABASE\Library\ALTIUM_TOOL\PCB_FOOTPRINTS\Altium_Footprint_Lib.PcbLib; Height: 0.33MM; Library Path: Y:\MIS_DATABASE\Library\ALTIUM_TOOL\SCHEMATICS_PARTS\MS_DISCRETE_Library.schlib; Mfr_name: MURATA; Mfr_part_number: GRM033R61C104KE14D; Mistral Part No: 120009030072-R; Package: 0201; Part_type: CAPACITORS\CERAMIC; Project: TI_MAXIE_CPB; RoHS: RoHS; Temperature: -55°C+85°C; Tolerance: 10%; Voltage: 16V; Wattage: NA; Weight: 0.33mg; Datasheet: Y:\MIS_DATABASE\DATASHEETS\CAPACITORS\GRM033R61C104KE14.PDF
C185 C192 C378 C384 = CAP: CAP CERAMIC 1uF 16V 20% X5R 0201; Chkd/date: MANIRAJA/300520; Crtd /date: ALVY/260520; Custom_Duty: 15%; Customs_HS_Code: 85322990; Distributor_name: DIGIKEY; Distributor_part_number: 490-18654-1-ND; Footprint Path: Y:\MIS_DATABASE\Library\ALTIUM_TOOL\PCB_FOOTPRINTS\Altium_Footprint_Lib.PcbLib; Height: 0.39MM; Library Path: Y:\MIS_DATABASE\Library\ALTIUM_TOOL\SCHEMATICS_PARTS\MS_DISCRETE_Library.schlib; Mfr_name: MURATA; Mfr_part_number: GRM033R61C105ME15D; Mistral Part No: 120018090038-R; Package: 0201; Part_type: CAPACITORS\CERAMIC; Project: QCS610_NANOSOM; RoHS: RoHS; Temperature: -55°C+85°C; Tolerance: 20%; Voltage: 16V; Wattage: NA; Weight: 0.33mg; Datasheet: Y:\MIS_DATABASE\DATASHEETS\CAPACITORS\GRM033R61C105ME15.PDF
J11 = HEADER_10X2: CON HDR 2X10 2.54MM PITCH ST TH; Chkd/date: MANIRAJA/270721; Crtd /date: ALVY/260721; Custom_Duty: 24%; Customs_HS_Code: 85369090; Distributor_name: DIGIKEY; Distributor_part_number: S2012EC-10-ND; Footprint Path: Y:\MIS_DATABASE\Library\ALTIUM_TOOL\PCB_FOOTPRINTS\Altium_Footprint_Lib.PcbLib; Height: 8.34MM; Library Path: Y:\MIS_DATABASE\Library\ALTIUM_TOOL\SCHEMATICS_PARTS\MS_CONNECTOR_Library.schlib; Mfr_name: SULLINS CONNECTOR; Mfr_part_number: PREC010DAAN-RC; Mistral Part No: 150021070022-R; Package: THRU-HOLE; Part_type: CONNECTOR\HEADERS; Project: TI_AM335x SK_BRD; RoHS: RoHS; Temperature: -40°C+105°C; Tolerance: NA; Voltage: NA; Wattage: NA; Weight: NA; Datasheet: Y:\MIS_DATABASE\DATASHEETS\CONNECTORS\PRPCXXDXXN-SER.PDF
R76 = RESISTOR: RES 0E 1/20W 5% 0201; Assembly_Instruction: DNI; Chkd/date: NAVEED/301214; Crtd /date: MUDDU/120710; Custom_Duty: 15%; Customs_HS_Code: 85332119; Distributor_name: DIGIKEY; Distributor_part_number: 311-0.0NCT-ND; Footprint Path: Y:\MIS_DATABASE\Library\ALTIUM_TOOL\PCB_FOOTPRINTS\Altium_Footprint_Lib.PcbLib; Height: 0.26MM; Library Path: Y:\MIS_DATABASE\Library\ALTIUM_TOOL\SCHEMATICS_PARTS\MS_DISCRETE_Library.schlib; Manufacturer: YAGEO AMERICA; Mfr_name: YAGEO AMERICA; Mfr_part_number: RC0201JR-070RL; Mistral Part No: 110010070067-R; Package: 0201; Part_type: RESISTORS\FIXED; Project: PB_BUGBASE; RoHS: RoHS; Temperature: -55°C+125°C; Tolerance: 5%; Voltage: NA; Wattage: 1/20W; Weight: 0.17mg; Datasheet: Y:\MIS_DATABASE\DATASHEETS\RESISTORS\RCXXXXL-SER_MAR18.PDF
R78 = RESISTOR: RES 0E 1/20W 5% 0201; Chkd/date: NAVEED/301214; Crtd /date: MUDDU/120710; Custom_Duty: 15%; Customs_HS_Code: 85332119; Distributor_name: DIGIKEY; Distributor_part_number: 311-0.0NCT-ND; Footprint Path: Y:\MIS_DATABASE\Library\ALTIUM_TOOL\PCB_FOOTPRINTS\Altium_Footprint_Lib.PcbLib; Height: 0.26MM; Library Path: Y:\MIS_DATABASE\Library\ALTIUM_TOOL\SCHEMATICS_PARTS\MS_DISCRETE_Library.schlib; Manufacturer: YAGEO AMERICA; Mfr_name: YAGEO AMERICA; Mfr_part_number: RC0201JR-070RL; Mistral Part No: 110010070067-R; Package: 0201; Part_type: RESISTORS\FIXED; Project: PB_BUGBASE; RoHS: RoHS; Temperature: -55°C+125°C; Tolerance: 5%; Voltage: NA; Wattage: 1/20W; Weight: 0.17mg; Datasheet: Y:\MIS_DATABASE\DATASHEETS\RESISTORS\RCXXXXL-SER_MAR18.PDF
R66 R71 R79 R82 R291 R421 R433 R584 R585 = RESISTOR: RES 0E 1/20W 5% 0201; Chkd/date: NAVEED/301214; Crtd /date: MUDDU/120710; Custom_Duty: 15%; Customs_HS_Code: 85332119; Distributor_name: DIGIKEY; Distributor_part_number: 311-0.0NCT-ND; Footprint Path: Y:\MIS_DATABASE\Library\ALTIUM_TOOL\PCB_FOOTPRINTS\Altium_Footprint_Lib.PcbLib; Height: 0.26MM; Library Path: Y:\MIS_DATABASE\Library\ALTIUM_TOOL\SCHEMATICS_PARTS\MS_DISCRETE_Library.schlib; Mfr_name: YAGEO AMERICA; Mfr_part_number: RC0201JR-070RL; Mistral Part No: 110010070067-R; Package: 0201; Part_type: RESISTORS\FIXED; Project: PB_BUGBASE; RoHS: RoHS; Temperature: -55°C+125°C; Tolerance: 5%; Voltage: NA; Wattage: 1/20W; Weight: 0.17mg; Datasheet: Y:\MIS_DATABASE\DATASHEETS\RESISTORS\RCXXXXL-SER_MAR18.PDF
R80 R116 R140 R142 R294 R295 R297-R299 R418 R472 = RESISTOR: RES 10K 1/20W 5% 0201; Chkd/date: MANIRAJA/050517; Crtd /date: MANIRAJA/050517; Custom_Duty: 15%; Customs_HS_Code: 85332119; Distributor_name: DIGIKEY; Distributor_part_number: 311-10KNCT-ND; Footprint Path: Y:\MIS_DATABASE\Library\ALTIUM_TOOL\PCB_FOOTPRINTS\Altium_Footprint_Lib.PcbLib; Height: 0.26MM; Library Path: Y:\MIS_DATABASE\Library\ALTIUM_TOOL\SCHEMATICS_PARTS\MS_DISCRETE_Library.schlib; Mfr_name: YAGEO AMERICA; Mfr_part_number: RC0201JR-0710KL; Mistral Part No: 110010070051-R; Package: 0201; Part_type: RESISTORS\FIXED; Project: GOLDEN-I LITE; RoHS: RoHS; Temperature: -55°C+125°C; Tolerance: 5%; Voltage: NA; Wattage: 1/20W; Weight: 0.17mg; Datasheet: Y:\MIS_DATABASE\DATASHEETS\RESISTORS\RCXXXXL-SER_MAR18.PDF
R65 R70 R420 = RESISTOR: RES 0E 1/20W 5% 0201; Assembly_Instruction: DNI; Chkd/date: NAVEED/301214; Crtd /date: MUDDU/120710; Custom_Duty: 15%; Customs_HS_Code: 85332119; Distributor_name: DIGIKEY; Distributor_part_number: 311-0.0NCT-ND; Footprint Path: Y:\MIS_DATABASE\Library\ALTIUM_TOOL\PCB_FOOTPRINTS\Altium_Footprint_Lib.PcbLib; Height: 0.26MM; Library Path: Y:\MIS_DATABASE\Library\ALTIUM_TOOL\SCHEMATICS_PARTS\MS_DISCRETE_Library.schlib; Mfr_name: YAGEO AMERICA; Mfr_part_number: RC0201JR-070RL; Mistral Part No: 110010070067-R; Package: 0201; Part_type: RESISTORS\FIXED; Project: PB_BUGBASE; RoHS: RoHS; Temperature: -55°C+125°C; Tolerance: 5%; Voltage: NA; Wattage: 1/20W; Weight: 0.17mg; Datasheet: Y:\MIS_DATABASE\DATASHEETS\RESISTORS\RCXXXXL-SER_MAR18.PDF
R432 = RESISTOR: RES 2.2K 1/20W 5% 0201; Assembly_Instruction: DNI; Chkd/date: MANIRAJA/310821; Crtd /date: ALVY/310821; Custom_Duty: 15%; Customs_HS_Code: 85332119; Distributor_name: DIGIKEY; Distributor_part_number: P123277CT-ND; Footprint Path: Y:\MIS_DATABASE\Library\ALTIUM_TOOL\PCB_FOOTPRINTS\Altium_Footprint_Lib.PcbLib; Height: 0.26MM; Library Path: Y:\MIS_DATABASE\Library\ALTIUM_TOOL\SCHEMATICS_PARTS\MS_DISCRETE_Library.schlib; Mfr_name: PANASONIC-ECG; Mfr_part_number: ERJ-1GNJ222C; Mistral Part No: 110009030427-R; Package: 0201; Part_type: RESISTORS\FIXED; Project: TI_AM335x SK_BRD; RoHS: RoHS; Temperature: -55°C+125°C; Tolerance: 5%; Voltage: NA; Wattage: 1/20W; Weight: 0.15mg; Datasheet: Y:\MIS_DATABASE\DATASHEETS\RESISTORS\PAN-ERJSER_NOV17.PDF
R435 = RESISTOR: RES 100K 1/10W 1% 0402; Assembly_Instruction: DNI; Chkd/date: VASANTHA/201216; Crtd /date: MAZHAR/130306; Custom_Duty: 15%; Customs_HS_Code: 85332119; Distributor_name: DIGIKEY; Distributor_part_number: P100KLCT-ND; Footprint Path: Y:\MIS_DATABASE\Library\ALTIUM_TOOL\PCB_FOOTPRINTS\Altium_Footprint_Lib.PcbLib; Height: 0.40MM; Library Path: Y:\MIS_DATABASE\Library\ALTIUM_TOOL\SCHEMATICS_PARTS\MS_DISCRETE_Library.schlib; Mfr_name: PANASONIC-ECG; Mfr_part_number: ERJ-2RKF1003X; Mistral Part No: 110009030187-R; Package: 0402; Part_type: RESISTORS\FIXED; Project: J32; RoHS: RoHS; Temperature: -55°C+155°C; Tolerance: 1%; Voltage: NA; Wattage: 1/10W; Weight: 0.8mg; Datasheet: Y:\MIS_DATABASE\DATASHEETS\RESISTORS\PAN-ERJSER_NOV17.PDF
R589 = RESISTOR: RES 100K 1/10W 1% 0402; Chkd/date: VASANTHA/201216; Crtd /date: MAZHAR/130306; Custom_Duty: 15%; Customs_HS_Code: 85332119; Distributor_name: DIGIKEY; Distributor_part_number: P100KLCT-ND; Footprint Path: Y:\MIS_DATABASE\Library\ALTIUM_TOOL\PCB_FOOTPRINTS\Altium_Footprint_Lib.PcbLib; Height: 0.40MM; Library Path: Y:\MIS_DATABASE\Library\ALTIUM_TOOL\SCHEMATICS_PARTS\MS_DISCRETE_Library.schlib; Mfr_name: PANASONIC-ECG; Mfr_part_number: ERJ-2RKF1003X; Mistral Part No: 110009030187-R; Package: 0402; Part_type: RESISTORS\FIXED; Project: J32; RoHS: RoHS; Temperature: -55°C+155°C; Tolerance: 1%; Voltage: NA; Wattage: 1/10W; Weight: 0.8mg; Datasheet: Y:\MIS_DATABASE\DATASHEETS\RESISTORS\PAN-ERJSER_NOV17.PDF
RA1 = RESARR_ISO4: RES ARRAY 0E 31mW JUMPER 0201-4; Chkd/date: MANIRAJA/290918; Crtd /date: MANIRAJA/290918; Custom_Duty: 15%; Customs_HS_Code: 85332119; Distributor_name: DIGIKEY; Distributor_part_number: Y6000CT-ND; Footprint Path: Y:\MIS_DATABASE\Library\ALTIUM_TOOL\PCB_FOOTPRINTS\Altium_Footprint_Lib.PcbLib; Height: 0.45MM; Library Path: Y:\MIS_DATABASE\Library\ALTIUM_TOOL\SCHEMATICS_PARTS\MS_DISCRETE_Library.schlib; Manufacturer: PANASONIC-ECG; Mfr_name: PANASONIC-ECG; Mfr_part_number: EXB-18VR000X; Mistral Part No: 110018090033-R; Package: 0201-4; Part_type: RESISTORS\ARRAY; Project: TI_60GHz-AOP; RoHS: RoHS; Temperature: -55°C+125°C; Tolerance: NA; Voltage: NA; Wattage: 31mW; Weight: 1mg; Datasheet: Y:\MIS_DATABASE\DATASHEETS\RESISTORS\EXB-18V.PDF
RA4 = RESARR_ISO4: RES ARRAY 0E 31mW JUMPER 0201-4; Assembly_Instruction: DNI; Chkd/date: MANIRAJA/290918; Crtd /date: MANIRAJA/290918; Custom_Duty: 15%; Customs_HS_Code: 85332119; Distributor_name: DIGIKEY; Distributor_part_number: Y6000CT-ND; Footprint Path: Y:\MIS_DATABASE\Library\ALTIUM_TOOL\PCB_FOOTPRINTS\Altium_Footprint_Lib.PcbLib; Height: 0.45MM; Library Path: Y:\MIS_DATABASE\Library\ALTIUM_TOOL\SCHEMATICS_PARTS\MS_DISCRETE_Library.schlib; Manufacturer: PANASONIC-ECG; Mfr_name: PANASONIC-ECG; Mfr_part_number: EXB-18VR000X; Mistral Part No: 110018090033-R; Package: 0201-4; Part_type: RESISTORS\ARRAY; Project: TI_60GHz-AOP; RoHS: RoHS; Temperature: -55°C+125°C; Tolerance: NA; Voltage: NA; Wattage: 31mW; Weight: 1mg; Datasheet: Y:\MIS_DATABASE\DATASHEETS\RESISTORS\EXB-18V.PDF
RA5-RA8 = RESARR_ISO4: RES ARRAY 1K 31mW 5% 0201-4; Chkd/date: NAVEED/110515; Crtd /date: VASANTHA/080515; Custom_Duty: 15%; Customs_HS_Code: 85332119; Distributor_name: DIGIKEY; Distributor_part_number: Y6102CT-ND; Footprint Path: Y:\MIS_DATABASE\Library\ALTIUM_TOOL\PCB_FOOTPRINTS\Altium_Footprint_Lib.PcbLib; Height: 0.45MM; Library Path: Y:\MIS_DATABASE\Library\ALTIUM_TOOL\SCHEMATICS_PARTS\MS_DISCRETE_Library.schlib; Mfr_name: PANASONIC-ECG; Mfr_part_number: EXB-18V102JX; Mistral Part No: 110015050003-R; Package: 0201-4; Part_type: RESISTORS\ARRAY; Project: FREE SCALE NANO; RoHS: RoHS; Temperature: -55°C+125°C; Tolerance: 5%; Voltage: NA; Wattage: 31mW; Weight: 1mg; Datasheet: Y:\MIS_DATABASE\DATASHEETS\RESISTORS\EXB-18V.PDF
TP20 TP25 TP36 = TESTPOINT: TESTPOINT CIR 20 SMD; Chkd/date: SHREESHAIL/171006; Crtd /date: MAZHAR/171006; Custom_Duty: NA; Customs_HS_Code: NA; Distributor_name: NA; Distributor_part_number: NA; Footprint Path: Y:\MIS_DATABASE\Library\ALTIUM_TOOL\PCB_FOOTPRINTS\Altium_Footprint_Lib.PcbLib; Height: NA; Library Path: Y:\MIS_DATABASE\Library\ALTIUM_TOOL\SCHEMATICS_PARTS\MS_DISCRETE_Library.schlib; MECHANICAL 3D STEP FILE: NA; Mfr_name: LOCAL; Mistral Part No: NA; Package: SMD; Project: BT MODULE_CSRBC04; RoHS: NA; Temperature: NA; Tolerance: NA; Voltage: NA; Wattage: NA; Weight: NA; Datasheet: NA
U12 = AM62Q_SoC_FCBGA441: IC AM62Q SoC MICROPROCESSOR FCBGA441; Chkd/date: MANIRAJA/211021; Crtd /date: ALVY/211021; Custom_Duty: 15%; Customs_HS_Code: 85423100; Distributor_name: NA; Distributor_part_number: NA; Footprint Path: Y:\MIS_DATABASE\Library\ALTIUM_TOOL\PCB_FOOTPRINTS\Altium_Footprint_Lib.PcbLib; Height: 2.57MM; Library Path: Y:\MIS_DATABASE\Library\ALTIUM_TOOL\SCHEMATICS_PARTS\MS_MICROPROCESSOR_Library.schlib; Mfr_name: TEXAS INSTRUMENTS; Mistral Part No: 141221100001; Package: FCBGA441; Part_type: ICS\DIGITAL\MICROPROCESSOR; Project: TI_AM62Q_BRD; RoHS: NA; Temperature: NA; Tolerance: NA; Voltage: NA; Wattage: NA; Weight: NA; Datasheet: Y:\MIS_DATABASE\DATASHEETS\ICS\DIGITAL\MICROCONTROLLER\AM62Q-SoC.PDF
U46 U65 = TPS22912CYZVR_DSBGA4: IC 3.6V 500mA 78mE ON-RESISTANCE LOAD SWITCH WITH CONTROLLED TURNON DSBGA4; Chkd/date: MANIRAJA/170920; Crtd /date: ALVY/160920; Custom_Duty: 15%; Customs_HS_Code: 85423100; Distributor_name: DIGIKEY; Distributor_part_number: 296-24472-1-ND; Footprint Path: Y:\MIS_DATABASE\Library\ALTIUM_TOOL\PCB_FOOTPRINTS\Altium_Footprint_Lib.PcbLib; Height: 0.50MM; Library Path: Y:\MIS_DATABASE\Library\ALTIUM_TOOL\SCHEMATICS_PARTS\MS_MISCPOWER_Library.schlib; Mfr_name: TEXAS INSTRUMENTS; Mistral Part No: 142020090007-R; Package: DSBGA4; Part_type: ICS\POWER; Project: AM64X_SKEVM; RoHS: RoHS; Temperature: -40°C+85°C; Tolerance: NA; Voltage: NA; Wattage: NA; Weight: 0.7mg; Datasheet: Y:\MIS_DATABASE\DATASHEETS\ICS\POWER\TPS22901-2-3.PDF
Y2 = CRY: CRY 32.768KHz 9pF SMD; Chkd/date: VASANTHA/090419; Crtd /date: ALVY/090419; Custom_Duty: 24%; Customs_HS_Code: 85439000; Distributor_name: DIGIKEY; Distributor_part_number: XC2160CT-ND; Footprint Path: Y:\MIS_DATABASE\Library\ALTIUM_TOOL\PCB_FOOTPRINTS\Altium_Footprint_Lib.PcbLib; Height: 0.90MM; Library Path: Y:\MIS_DATABASE\Library\ALTIUM_TOOL\SCHEMATICS_PARTS\MS_DISCRETE_Library.schlib; Mfr_name: ECS INC; Mfr_part_number: ECS-.327-9-34QCS-TR; Mistral Part No: 130019040003-R; Package: SMD; Part_type: CRYSTAL; Project: J7ES_SOM_DUAL-LEO_PMIC; RoHS: RoHS; Temperature: -40°C+125°C; Tolerance: NA; Voltage: NA; Wattage: NA; Weight: 16mg; Datasheet: Y:\MIS_DATABASE\DATASHEETS\MISC\CRY_OSC\ECS-34Q.PDF
C113 C190 C195 C377 = CAP: CAP CERAMIC 0.1uF 50V 10% X7R 0402; Alt_Mfr_name: YAGEO AMERICA; Alt_Mfr_part_number: CC0402KRX5R8BB104; Chkd/date: MANIRAJA/261020; Crtd /date: ALVY/211020; Custom_Duty: 15%; Customs_HS_Code: 85322990; Distributor_name: DIGIKEY; Distributor_part_number: 490-10700-1-ND; Footprint Path: Y:\MIS_DATABASE\Library\ALTIUM_TOOL\PCB_FOOTPRINTS\Altium_Footprint_Lib.PcbLib; Height: 0.55MM; Library Path: Y:\MIS_DATABASE\Library\ALTIUM_TOOL\SCHEMATICS_PARTS\MS_DISCRETE_Library.schlib; Mfr_name: MURATA; Mfr_part_number: GRM155R71H104KE14D; Mistral Part No: 120011100014-R; Package: 0402; Part_type: CAPACITORS\CERAMIC; Project: J7_CP; RoHS: RoHS; Temperature: -55°C+125°C; Tolerance: 10%; Voltage: 50V; Wattage: NA; Weight: 3.1mg; Datasheet: Y:\MIS_DATABASE\DATASHEETS\CAPACITORS\GRM155R71H104KE14.PDF
J3 = HEADER_20X2: CON HDR 2X20 2.54MM PITCH ST TH; Chkd/date: MANIRAJA/261020; Crtd /date: MANIRAJA/261020; Custom_Duty: 24%; Customs_HS_Code: 85369090; Distributor_name: DIGIKEY; Distributor_part_number: S2012E-20-ND; Footprint Path: Y:\MIS_DATABASE\Library\ALTIUM_TOOL\PCB_FOOTPRINTS\Altium_Footprint_Lib.PcbLib; Height: 8.58MM; Library Path: Y:\MIS_DATABASE\Library\ALTIUM_TOOL\SCHEMATICS_PARTS\MS_CONNECTOR_Library.schlib; Mfr_name: SULLINS CONNECTOR; Mfr_part_number: PEC20DAAN; Mistral Part No: 150020100013-R; Package: THRU-HOLE; Part_type: CONNECTOR\HEADERS; Project: AM64X_SKEVM; RoHS: RoHS; Temperature: -65°C+125°C; Tolerance: NA; Voltage: NA; Wattage: NA; Weight: NA; Datasheet: Y:\MIS_DATABASE\DATASHEETS\CONNECTORS\XXCXXDXXN.PDF
R288 R416 R419 = RESISTOR: RES 4.7K 1/20W 5% 0201; Chkd/date: MANIRAJA/200921; Crtd /date: ALVY/200921; Custom_Duty: 15%; Customs_HS_Code: 85332119; Distributor_name: DIGIKEY; Distributor_part_number: 311-4.7KNCT-ND; Footprint Path: Y:\MIS_DATABASE\Library\ALTIUM_TOOL\PCB_FOOTPRINTS\Altium_Footprint_Lib.PcbLib; Height: 0.26MM; Library Path: Y:\MIS_DATABASE\Library\ALTIUM_TOOL\SCHEMATICS_PARTS\MS_DISCRETE_Library.schlib; Mfr_name: YAGEO AMERICA; Mfr_part_number: RC0201JR-074K7L; Mistral Part No: 110021090007-R; Package: 0201; Part_type: RESISTORS\FIXED; Project: TI_AM62x SKEVM_BRD; RoHS: RoHS; Temperature: -55°C+125°C; Tolerance: 5%; Voltage: NA; Wattage: 1/20W; Weight: 0.17mg; Datasheet: Y:\MIS_DATABASE\DATASHEETS\RESISTORS\RCXXXXL-SER_MAR18.PDF
R290 R293 = RESISTOR: RES 100K 1/20W 5% 0201; Chkd/date: PRAVEEN/080922; Crtd /date: TAMILARASU/080922; Custom_Duty: 15%; Customs_HS_Code: 85332119; Distributor_name: DIGIKEY; Distributor_part_number: P123223CT-ND; Footprint Path: Y:\MIS_DATABASE\Library\ALTIUM_TOOL\PCB_FOOTPRINTS\Altium_Footprint_Lib.PcbLib; Height: 0.26MM; Library Path: Y:\MIS_DATABASE\Library\ALTIUM_TOOL\SCHEMATICS_PARTS\MS_DISCRETE_Library.schlib; Mfr_name: PANASONIC-ECG; Mfr_part_number: ERJ-1GNJ104C; Mistral Part No: 110022090005-R; Package: 0201; Part_type: RESISTORS\FIXED; Project: SK AM62Q LP EVM BRD; RoHS: RoHS; Temperature: -55°C+125°C; Tolerance: 5%; Voltage: NA; Wattage: 1/20W; Weight: 0.15mg; Datasheet: Y:\MIS_DATABASE\DATASHEETS\RESISTORS\PAN-ERJSER_NOV17.PDF
U45 = TPS22946_DSBGA6: IC CURRENT-LIMITED LOAD SWITCH WITH SHUTOFF AUTO-RESTART AND OVERCURRENT CONDITION TIME-OUT DSBGA6; Chkd/date: MANIRAJA/220121; Crtd /date: ALVY/220121; Custom_Duty: 15%; Customs_HS_Code: 85423100; Distributor_name: DIGIKEY; Distributor_part_number: 296-25219-1-ND; Footprint Path: Y:\MIS_DATABASE\Library\ALTIUM_TOOL\PCB_FOOTPRINTS\Altium_Footprint_Lib.PcbLib; Height: 0.50MM; Library Path: Y:\MIS_DATABASE\Library\ALTIUM_TOOL\SCHEMATICS_PARTS\MS_MISCPOWER_Library.schlib; Mfr_name: TEXAS INSTRUMENTS; Mistral Part No: 142021010016-R; Package: DSBGA6; Part_type: ICS\POWER\MANAGEMENT; Project: AM64X_SKEVM; RoHS: RoHS; Temperature: -40°C+85°C; Tolerance: NA; Voltage: NA; Wattage: NA; Weight: 1.7mg; Datasheet: Y:\MIS_DATABASE\DATASHEETS\ICS\POWER\TPS22946.PDF
C41 C43 = CAP: CAP CERAMIC 18pF 50V 5% HI-Q C0G(NP0) 0402; Chkd/date: VASANTHA/030315; Crtd /date: NAVEED/271014; Custom_Duty: 15%; Customs_HS_Code: 85322990; Distributor_name: DIGIKEY; Distributor_part_number: 490-3119-1-ND; Footprint Path: Y:\MIS_DATABASE\Library\ALTIUM_TOOL\PCB_FOOTPRINTS\Altium_Footprint_Lib.PcbLib; Height: 0.55MM; Library Path: Y:\MIS_DATABASE\Library\ALTIUM_TOOL\SCHEMATICS_PARTS\MS_DISCRETE_Library.schlib; Mfr_name: MURATA; Mfr_part_number: GJM1555C1H180JB01D; Mistral Part No: 120014100019-R; Package: 0402; Part_type: CAPACITORS\CERAMIC; Project: DC_MIST_RDC; RoHS: RoHS; Temperature: -55°C+125°C; Tolerance: 5%; Voltage: 50V; Wattage: NA; Weight: 6mg; Datasheet: Y:\MIS_DATABASE\DATASHEETS\CAPACITORS\MURATA-GXX-SER_NOV17.PDF
J8 = HEADER_2X1: CON HDR 1X2 2.54MM PITCH ST TH; Chkd/date: NAVEED/210714; Crtd /date: USMAN/031012; Custom_Duty: 24%; Customs_HS_Code: 85369090; Distributor_name: DIGIKEY; Distributor_part_number: WM8072-ND; Footprint Path: Y:\MIS_DATABASE\Library\ALTIUM_TOOL\PCB_FOOTPRINTS\Altium_Footprint_Lib.PcbLib; Height: 5.60MM; Library Path: Y:\MIS_DATABASE\Library\ALTIUM_TOOL\SCHEMATICS_PARTS\MS_CONNECTOR_Library.schlib; Mfr_name: MOLEX; Mfr_part_number: 90120-0122; Mistral Part No: 150012100005-R; Package: THRU-HOLE; Part_type: CONNECTOR\HEADERS; Project: NPOL_FEP; RoHS: RoHS; Temperature: -55°C+125°C; Tolerance: NA; Voltage: NA; Wattage: NA; Weight: 122mg; Datasheet: Y:\MIS_DATABASE\DATASHEETS\CONNECTORS\90120-XX.PDF
J10 = HEADER_14x2: CON HDR 2X14 2.54MM PITCH ST TH; Chkd/date: NAVEED/280515; Crtd /date: VASANTHA/111114; Custom_Duty: 0.24; Customs_HS_Code: 85369090; Distributor_name: DIGIKEY; Distributor_part_number: S2012EC-14-ND; Height: 8.34MM; Mfr_name: SULLINS; Mfr_part_number: PREC014DAAN-RC; Mistral Part No: 150014110005-R; Package: THRU-HOLE; Part_type: CONNECTOR\HEADERS; Project: GALILEO_EVM; RoHS: RoHS; Temperature: -40°C+105°C; Tolerance: NA; Voltage: NA; Wattage: NA; Weight: NA; Datasheet: Y:\MIS_DATABASE\DATASHEETS\CONNECTORS\PRXXXN-RC.PDF
R402 = RESISTOR: RES 1K 1/20W 1% 0201; Chkd/date: JEBRAN/110815; Crtd /date: JEBRAN/110815; Custom_Duty: 15%; Customs_HS_Code: 85332119; Distributor_name: DIGIKEY; Distributor_part_number: 541-1.00KAABCT-ND; Footprint Path: Y:\MIS_DATABASE\Library\ALTIUM_TOOL\PCB_FOOTPRINTS\Altium_Footprint_Lib.PcbLib; Height: 0.28MM; Library Path: Y:\MIS_DATABASE\Library\ALTIUM_TOOL\SCHEMATICS_PARTS\MS_DISCRETE_Library.schlib; Mfr_name: VISHAY; Mfr_part_number: CRCW02011K00FKED; Mistral Part No: 110015080014-R; Package: 0201; Part_type: RESISTORS\FIXED; Project: OCTASIC_3000; RoHS: RoHS; Temperature: -55°C+155°C; Tolerance: 1%; Voltage: NA; Wattage: 1/20W; Weight: 0.17mg; Datasheet: Y:\MIS_DATABASE\DATASHEETS\RESISTORS\CRCW0201.PDF
U19 = TXS0102DQX_SON8: IC 2-BIT BI-DIR VOLTAGE-LEVEL TRANSLATOR FOR OPEN-DRAIN AND PUSH-PULL X2SON8; Chkd/date: MANIRAJA/010719; Crtd /date: CHAITHANYA230512; Custom_Duty: 15%; Customs_HS_Code: 85423100; Distributor_name: DIGIKEY; Distributor_part_number: 296-28368-1-ND; Footprint Path: Y:\MIS_DATABASE\Library\ALTIUM_TOOL\PCB_FOOTPRINTS\Altium_Footprint_Lib.PcbLib; Height: 0.40MM; Library Path: Y:\MIS_DATABASE\Library\ALTIUM_TOOL\SCHEMATICS_PARTS\MS_MISCINTERFACE_Library.schlib; Mfr_name: TEXAS INSTRUMENTS; Mistral Part No: 141012050010-R; Package: X2SON8; Part_type: ICS\INTERFACE\LEVEL TRANSLATOR; Project: GEN_3-8_DB; RoHS: RoHS; Temperature: -40°C+85°C; Tolerance: NA; Voltage: NA; Wattage: NA; Weight: 1.2mg; Datasheet: Y:\MIS_DATABASE\DATASHEETS\ICS\INTERFACE\TXS0102-SER.PDF
U26 = SN74CB3Q3257PWR_TSSOP16: IC 4BIT 1-OF-2 FET MULTIPLEXER/DEMULTIPLEXER TSSOP16; Chkd/date: SUHAS/251010; Crtd /date: USMAN/060109; Custom_Duty: 15%; Customs_HS_Code: 85423100; Distributor_name: DIGIKEY; Distributor_part_number: 296-19138-1-ND; Footprint Path: Y:\MIS_DATABASE\Library\ALTIUM_TOOL\PCB_FOOTPRINTS\Altium_Footprint_Lib.PcbLib; Footprint Ref: TSSOP16_25-59_205X180_1-2; Height: 1.20MM; Library Path: Y:\MIS_DATABASE\Library\ALTIUM_TOOL\SCHEMATICS_PARTS\MS_COMBINATIONAL_Library.schlib; MECHANICAL 3D STEP FILE: TSSOP16_25-59_205X180_1-2; Mfr_name: TEXAS INSTRUMENTS; Mistral Part No: 141009030117-R; Package: TSSOP16; Part_type: ICS\DIGITAL\COMBINATIONAL; Project: OMAP_EVM; RoHS: Sb/ Br FREE; Temperature: -40°C+85°C; Datasheet: Y:\MIS_DATABASE\DATASHEETS\ICS\DIGITAL\COMBINATIONAL\SN74CB3Q3257.PDF
Y1 = CRY4_13: CRY 25.000MHz 6pF SMD; Chkd/date: MANIRAJA/151020; Crtd /date: ALVY/151020; Custom_Duty: 24%; Customs_HS_Code: 85439000; Distributor_name: DIGIKEY; Distributor_part_number: 490-5578-1-ND; Footprint Path: Y:\MIS_DATABASE\Library\ALTIUM_TOOL\PCB_FOOTPRINTS\Altium_Footprint_Lib.PcbLib; Height: 0.70MM; Library Path: Y:\MIS_DATABASE\Library\ALTIUM_TOOL\SCHEMATICS_PARTS\MS_DISCRETE_Library.schlib; Mfr_name: MURATA; Mfr_part_number: XRCGB25M000F3M00R0; Mistral Part No: 130020100043-R; Package: SMD; Part_type: CRYSTAL; Project: AM64X_SKEVM; RoHS: RoHS; Temperature: -30°C+85°C; Tolerance: NA; Voltage: NA; Wattage: NA; Weight: 23mg; Datasheet: Y:\MIS_DATABASE\DATASHEETS\MISC\CRY_OSC\XRCGB.PDF

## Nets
DGND: C41.1 C43.1 C53.2 C62.2 C73.2 C81.1 C113.1 C185.2 C186.2 C187.2 C190.1 C191.2 C192.2 C195.1 C196.2 C377.1 C378.2 C380.2 C381.1 C384.2 C386.2 J3.6 J3.9 J3.14 J3.20 J3.25 J3.34 J10.2 J10.3 J10.7 J10.9 J10.14 J10.15 J10.20 J10.27 J11.2 R66.1 R140.2 R142.1 R290.1 R293.1 R435.1 U19.4(GND) U26.8(GND) U45.B1(GND) U46.B1(GND) U65.B1(GND) Y1.2 Y1.4 ; also on sheet 1 2 3 4 13 14 15 16 17 18 19 20 21 22 23 24 25 26 27 28 29 30 31 35 36 37 38 39 40 41 42 43
VCC1V8_SYS: C73.1 R116.1 U19.1(VCCA) ; also on sheet 4 16 19 20 22 25 37 39 40 42
VCC3V3_EXP: C192.1 C195.2 C196.1 J3.1 J3.17 R294.1 R295.1 R297.1 R298.1 R299.1 U46.A1(VOUT)
VCC3V3_PRU: C380.1 C381.2 C384.1 J11.1 R432.1 U65.A1(VOUT)
VCC5V0_EXP: C185.1 C190.2 C191.1 J3.2 J3.4 U45.A1(VOUT)
VCC_3V3_SYS: C81.2 C113.2 C186.1 C377.2 C378.1 C386.1 J10.1 R402.2 R416.1 R418.2 R419.1 R472.2 R589.2 U19.8(VCCB) U26.16(VCC) U46.A2(VIN) U65.A2(VIN) ; also on sheet 1 4 15 16 19 20 21 23 24 26 27 29 30 31 36 37 38 39 40 41 42 43
VCC_5V0: C187.1 R288.2 R291.1 U45.A2(VIN) ; also on sheet 13 14 35 38 41
VDDSHV_CANUART: R80.1 ; also on sheet 2 4 17 31
AUDIO_EXT_REFCLK1: U12.C16(MCASP0_AFSX) ; also on sheet 41
BOOTMODE0: RA8.2 ; also on sheet 27
BOOTMODE1: RA8.4 ; also on sheet 27
BOOTMODE2: RA8.1 ; also on sheet 27
BOOTMODE3: RA8.3 ; also on sheet 27
BOOTMODE4: RA7.3 ; also on sheet 27
BOOTMODE5: RA7.2 ; also on sheet 27
BOOTMODE6: RA7.4 ; also on sheet 27
BOOTMODE7: RA7.1 ; also on sheet 27
BOOTMODE8: RA6.1 ; also on sheet 27
BOOTMODE9: RA6.2 ; also on sheet 27
BOOTMODE10: RA5.1 ; also on sheet 27
BOOTMODE11: RA5.4 ; also on sheet 27
BOOTMODE12: RA5.2 ; also on sheet 27
BOOTMODE13: RA5.3 ; also on sheet 27
BOOTMODE14: RA6.3 ; also on sheet 27
BOOTMODE15: RA6.4 ; also on sheet 27
BT_EN_SOC: U12.E7(MCU_SPI0_CS0) ; also on sheet 19
CAN_FD_WKUP_HDR_INH: J10.5 R82.1
CAN_FD_WKUP_SW_INH: R78.2 ; also on sheet 2
CONN_MCU_PORz: J10.28 R472.1 ; also on sheet 42
CONN_MCU_RESETz: J10.25 R418.1 ; also on sheet 43
CPSW_RGMII_INTn/PRU_INTn: R433.1 ; also on sheet 24 42
ETH_CAN_INH: R76.2 R78.1 R79.2 R82.2
ETH_CAN_INH_PMIC: R76.1 ; also on sheet 4
ETH_CAN_INH_SOC: R79.1 R80.2 R585.1
EXP_CLKOUT0: J3.7 ; also on sheet 42
EXP_EHRPWM1_B: J3.33 U12.D18(MCASP0_AXR0)
EXP_GPIO0_14: J3.22 U19.7(B1)
EXP_GPIO0_14_LT: U19.2(A1) ; also on sheet 22
EXP_GPIO0_32: J3.30 RA4.5
EXP_GPIO0_33: J3.31 U12.K21(GPMC0_OEN_REN)
EXP_GPIO0_36: J3.29 U12.K18(GPMC0_BE1N)
EXP_GPIO0_38: J3.16 U12.P17(GPMC0_WAIT1)
EXP_GPIO0_39: J3.18 U12.J20(GPMC0_WPN)
EXP_GPIO0_40/PR0_ECAP0_IN_APWM_OUT: J3.32 U12.J19(GPMC0_DIR)
EXP_GPIO0_41: J3.37 U12.J18(GPMC0_CSN0)
EXP_GPIO0_42: J3.13 U12.H17(GPMC0_CSN1)
EXP_GPIO1_22: J3.15 ; also on sheet 42
EXP_HAT_DETECT: J3.39 ; also on sheet 39
EXP_I2C2_SCL: J3.5 ; also on sheet 38
EXP_I2C2_SDA: J3.3 ; also on sheet 38
EXP_PS_3V3_EN: R293.2 U46.B2(ON) ; also on sheet 39
EXP_PS_5V0_EN: R290.2 U45.C2(ON) ; also on sheet 39
EXP_SPI0_CLK: J3.23 ; also on sheet 42
EXP_SPI0_CS0: J3.24 R299.2 ; also on sheet 42
EXP_SPI0_CS1: J3.26 R298.2 ; also on sheet 42
EXP_SPI0_D0: J3.19 ; also on sheet 42
EXP_SPI0_D1: J3.21 ; also on sheet 42
EXP_SPI2_CLK: J3.40 ; also on sheet 37
EXP_SPI2_CS0/EHRPWM0_A: J3.12 R294.2 ; also on sheet 37
EXP_SPI2_CS1: J3.11 R295.2 U12.C17(MCASP0_ACLKX)
EXP_SPI2_CS2: J3.36 R297.2 U12.A18(MCASP0_AXR1)
EXP_SPI2_D0: J3.38 ; also on sheet 37
EXP_SPI2_D1/ECAP2_IN_APWM_OUT: J3.35 ; also on sheet 37
EXP_UART5_RXD: J3.10 ; also on sheet 42
EXP_UART5_TXD: J3.8 ; also on sheet 42
HFOSC0_CLKOUT_32K: U12.B12(WKUP_CLKOUT0) ; also on sheet 19
MCASP1_ACLKX: RA1.3 RA4.3 U12.K17(GPMC0_BE0N_CLE)
MCASP1_ACLKX_BUF: RA1.6 ; also on sheet 39
MCASP1_AFSX: RA1.2 RA4.2 U12.P21(GPMC0_WAIT0)
MCASP1_AFSX_BUF: RA1.7 ; also on sheet 39
MCASP1_AXR0: RA1.1 RA4.1 U12.J17(GPMC0_WEN)
MCASP1_AXR0_BUF: RA1.8 ; also on sheet 39
MCASP1_AXR2: RA1.4 RA4.4 U12.K20(GPMC0_ADVN_ALE)
MCASP1_AXR2_BUF: RA1.5 ; also on sheet 39
MCU_GPIO0_15: J10.10 R584.2
MCU_GPIO0_15_R: R584.1 R585.2 U12.D5(MCU_MCAN1_TX)
MCU_GPIO0_16: J10.11 U12.D6(MCU_MCAN1_RX)
MCU_I2C0_SCL: J10.24 R416.2 U12.B9(MCU_I2C0_SCL)
MCU_I2C0_SDA: J10.21 R419.2 U12.A10(MCU_I2C0_SDA)
MCU_MCAN0_RX: J10.22 U12.C4(MCU_MCAN0_RX)
MCU_MCAN0_TX: J10.16 U12.C5(MCU_MCAN0_TX)
MCU_OSC0_XI: R70.2 R71.2 U12.A5(MCU_OSC0_XI)
MCU_OSC0_XO: R65.2 R66.2 U12.A6(MCU_OSC0_XO)
MCU_RESETSTATz: J10.23 R420.1 TP20.1(TP) ; also on sheet 42
MCU_SAFETY_ERRORz_1V8: TP36.1(TP) U19.3(A2) ; also on sheet 42
MCU_SAFETY_ERRORz_3V3: J10.26 U19.6(B2)
MCU_SPI0_CLK: J10.18 U12.B7(MCU_SPI0_CLK)
MCU_SPI0_CS1: J10.8 U12.C8(MCU_SPI0_CS1)
MCU_SPI0_D0: J10.6 U12.E8(MCU_SPI0_D0)
MCU_SPI0_D1: J10.4 U12.D8(MCU_SPI0_D1)
MCU_UART0_CTS: U12.B8(MCU_UART0_CTSN) U26.9(3A)
MCU_UART0_CTS_3V3: U26.11(3B1) ; also on sheet 31
MCU_UART0_CTS_CONN: J10.12 U26.10(3B2)
MCU_UART0_MUX_OE: R140.1 U26.15(~{OE})
MCU_UART0_MUX_SEL: J8.2 R142.2 U26.1(S)
MCU_UART0_RTS: U12.D7(MCU_UART0_RTSN) U26.12(4A)
MCU_UART0_RTS_3V3: U26.14(4B1) ; also on sheet 31
MCU_UART0_RTS_CONN: J10.17 U26.13(4B2)
MCU_UART0_RX_3V3: U26.2(1B1) ; also on sheet 31
MCU_UART0_RXD: U12.A8(MCU_UART0_RXD) U26.4(1A)
MCU_UART0_RXD_CONN: J10.13 U26.3(1B2)
MCU_UART0_TX_3V3: U26.5(2B1) ; also on sheet 31
MCU_UART0_TXD: U12.B6(MCU_UART0_TXD) U26.7(2A)
MCU_UART0_TXD_CONN: J10.19 U26.6(2B2)
PMIC_MODE: TP25.1(TP) U12.C7(PMIC_LPM_EN0) ; also on sheet 4
PR0_PRU0_GPO0: J11.13 RA8.7 U12.K19(GPMC0_AD0)
PR0_PRU0_GPO1: J11.14 RA8.5 U12.L19(GPMC0_AD1)
PR0_PRU0_GPO2: J11.15 RA8.8 U12.L20(GPMC0_AD2)
PR0_PRU0_GPO3: J11.16 RA8.6 U12.L21(GPMC0_AD3)
PR0_PRU0_GPO4: J11.17 RA7.6 U12.M21(GPMC0_AD4)
PR0_PRU0_GPO5: J11.18 RA7.7 U12.L17(GPMC0_AD5)
PR0_PRU0_GPO6: J11.19 RA7.5 U12.L18(GPMC0_AD6)
PR0_PRU0_GPO7: J11.20 RA7.8 U12.M20(GPMC0_AD7)
PR0_PRU0_GPO11: J11.7 RA4.8
PR0_PRU0_GPO12: J11.9 RA4.7
PR0_PRU0_GPO14: J11.11 RA4.6
PRU_3V3_EN: R435.2 R589.1 U65.B2(ON) ; also on sheet 39
PRU_DETECT: J11.3 ; also on sheet 39
PRU_INTn: J11.5 R432.2 R433.2
PRU_RESETz: J11.4 R420.2 R421.2
RESETSTATz: R421.1 ; also on sheet 1 4 20 21 22 24 27 37 38 39 40 41 42
SoC_CLKIN: R71.1 ; also on sheet 25
SoC_I2C0_SCL: J3.28 J11.6 ; also on sheet 4 13 23 37 42
SoC_I2C0_SDA: J3.27 J11.8 ; also on sheet 4 13 23 37 42
SoC_I2C2_SCL: U12.H18(GPMC0_CSN2) ; also on sheet 38
SoC_I2C2_SDA: U12.H19(GPMC0_CSN3) ; also on sheet 38
SoC_RGMII_MDC: U12.V17(MDIO0_MDC) ; also on sheet 1 24
SoC_RGMII_MDIO: U12.U16(MDIO0_MDIO) ; also on sheet 1 24
SOC_SPI2_CLK: U12.D16(MCASP0_ACLKR) ; also on sheet 37
SOC_SPI2_CS0: U12.D15(MCASP0_AFSR) ; also on sheet 37
SOC_SPI2_D0: U12.B18(MCASP0_AXR3) ; also on sheet 37
SOC_SPI2_D1: U12.B17(MCASP0_AXR2) ; also on sheet 37
SoC_VOUT0_DATA16: RA6.8 U12.N20(GPMC0_AD8) ; also on sheet 41
SoC_VOUT0_DATA17: RA6.7 U12.N21(GPMC0_AD9) ; also on sheet 41
SoC_VOUT0_DATA18: RA5.8 U12.M17(GPMC0_AD10) ; also on sheet 41
SoC_VOUT0_DATA19: RA5.5 U12.N18(GPMC0_AD11) ; also on sheet 41
SoC_VOUT0_DATA20: RA5.7 U12.N17(GPMC0_AD12) ; also on sheet 41
SoC_VOUT0_DATA21: RA5.6 U12.N19(GPMC0_AD13) ; also on sheet 41
SoC_VOUT0_DATA22: RA6.6 U12.P19(GPMC0_AD14) ; also on sheet 41
SoC_VOUT0_DATA23: RA6.5 U12.P20(GPMC0_AD15) ; also on sheet 41
VSEL_SD_SOC: U12.M19(GPMC0_CLK) ; also on sheet 4
WKUP_LFOSCO_XI: C62.1 U12.A2(WKUP_LFOSC0_XI) Y2.1
WKUP_LFOSCO_XO: C53.1 U12.A3(WKUP_LFOSC0_XO) Y2.2
WKUP_UART0_CTS_3V3: U12.A7(WKUP_UART0_CTSN) ; also on sheet 31
WKUP_UART0_RTS_3V3: U12.B4(WKUP_UART0_RTSN) ; also on sheet 31
WKUP_UART0_RX_3V3: U12.B5(WKUP_UART0_RXD) ; also on sheet 31
WKUP_UART0_TX_3V3: U12.C6(WKUP_UART0_TXD) ; also on sheet 31
N16906426: C43.2 R70.1 Y1.1
N16906432: C41.2 R65.1 Y1.3
N16931396: R291.2 U45.B2(CL)
N16931420: R288.1 U45.C1(OC)
N17492093: R116.2 U19.5(OE)
N17492111: J8.1 R402.1

Not connected (* = marked no-connect by the designer): J11 10* 12*; U12 A9(WKUP_I2C0_SDA)* E9(WKUP_I2C0_SCL)*

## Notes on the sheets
sheet 32
- SOC WKUP DOMAIN
- Note: R1384, R1385 are
  Tripad
- ECS-.327-9-34QCS-TR
- SOC GPMC
- @ GPMC0_AD8- AD15
  > HDMI 16 to 23 bits
- GPIO_43
- GPIO_44
- BOOTMODE PINS
- MCASP1_AXR2
- MCASP1_ACLKX
- Cad Note: Place such that stubs are minimum.
   useTRIPAD ACTION
- GPIO0_40
- MCASP1_AFSX
- MCASP1_AXR0
- MCASP1_AFSX
- MCASP1_ACLKX
- MCASP1_AXR2
- MCASP1_AXR0
- MCASP1_AXR0
- MCASP1_AFSX
- To PRU connector
  for x8 NAND Interface
- MCASP1_ACLKX
- MCASP1_AXR2
- TO RI-pi or User Exp hdr
- POWER SWITCH FOR PRU HEADER
- NOTE: 1.1K Resistors are used to
  isolate the BOOTMODE control logic
  after the value is latched
- HDMI
- McASP1
- MUX
- AUDIO
- DNI
- PRU HEADER
- M.2 Wilink BT
- BUF
- x8 NAND (PRU HDR)
- 4
- 3V3 supply of PRU Header is limited to sourcing 500mA max.
- For x8 NAND Interface
- MCASP1_ACLKX
- MCASP1_AXR0
- MCASP1_AFSX
- Silk: PRU HDR
- NOTE: PRU Header I/O are not fail-safe
  and shall not be driven when AM62x
  Starter Kit is not powered.
sheet 33
- USER EXPANSION CONNECTOR
- GPIO1_10
- GPIO1_9
- GPIO1_7
- GPIO1_8
- GPIO1_14
- Note: Expansion boards should take care
  of the null modem connectivity for the
  UART signals (cross-over of Rx and Tx)
- GPIO1_13
- SoC_I2C2_SDA
- GPIO0_44
- SoC_I2C2_SCL
- GPIO0_43
- GPIO1_30
- GPIO1_24
- GPIO1_25
- GPIO1_11
- GPIO1_13
- GPIO0_42
- GPIO1_22
- GPIO0_38
- GPIO1_18
- GPIO0_39
- GPIO1_19
- GPIO0_14
- GPIO1_17
- GPIO1_15
- GPIO1_16
- GPIO1_27
- GPIO1_26
- GPIO0_36
- GPIO0_32
- MCASP1_AXR2
- GPIO0_33
- GPIO1_10
- GPIO0_40
- GPIO1_8
- GPIO1_9
- GPIO0_41
- GPIO1_7
- GPIO1_14
- Silk: USER EXPN
- POWER SWITCHES FOR USER EXPANSION CONNECTOR
- NOTE:
- AM62x Starter Kit shall not be powered through the 5V0 or 3V3 pins on the 40-pin User Expansion
  Connector.
  User Expansion Connector I/O are not fail-safe and shall not be driven when AM62x Starter Kit is
  not powered.
  5V supply of User Expansion Connector is limited to sourcing 155mA max.
  3V3 supply of User Expansion Connector is limited to sourcing 500mA max.
- It should be connected to PORz of the SoC TBD
sheet 34
- SOC - MCU DOMAIN
- MCU HEADER
- Silk: MCU HDR
- MCU_UART0 MUX
- INPUT/OUTPUT
- OEn
- SEL
- An
- L
- L(DEFAULT)
- An=nB1
- SOC - FT4232
- L
- H
- An=nB2
- SOC - MCU HEADER
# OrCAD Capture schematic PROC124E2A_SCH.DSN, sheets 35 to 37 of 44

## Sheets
35 34. USB 2.0 TYPE-A: size B; title: USB 2.0 TYPE-A
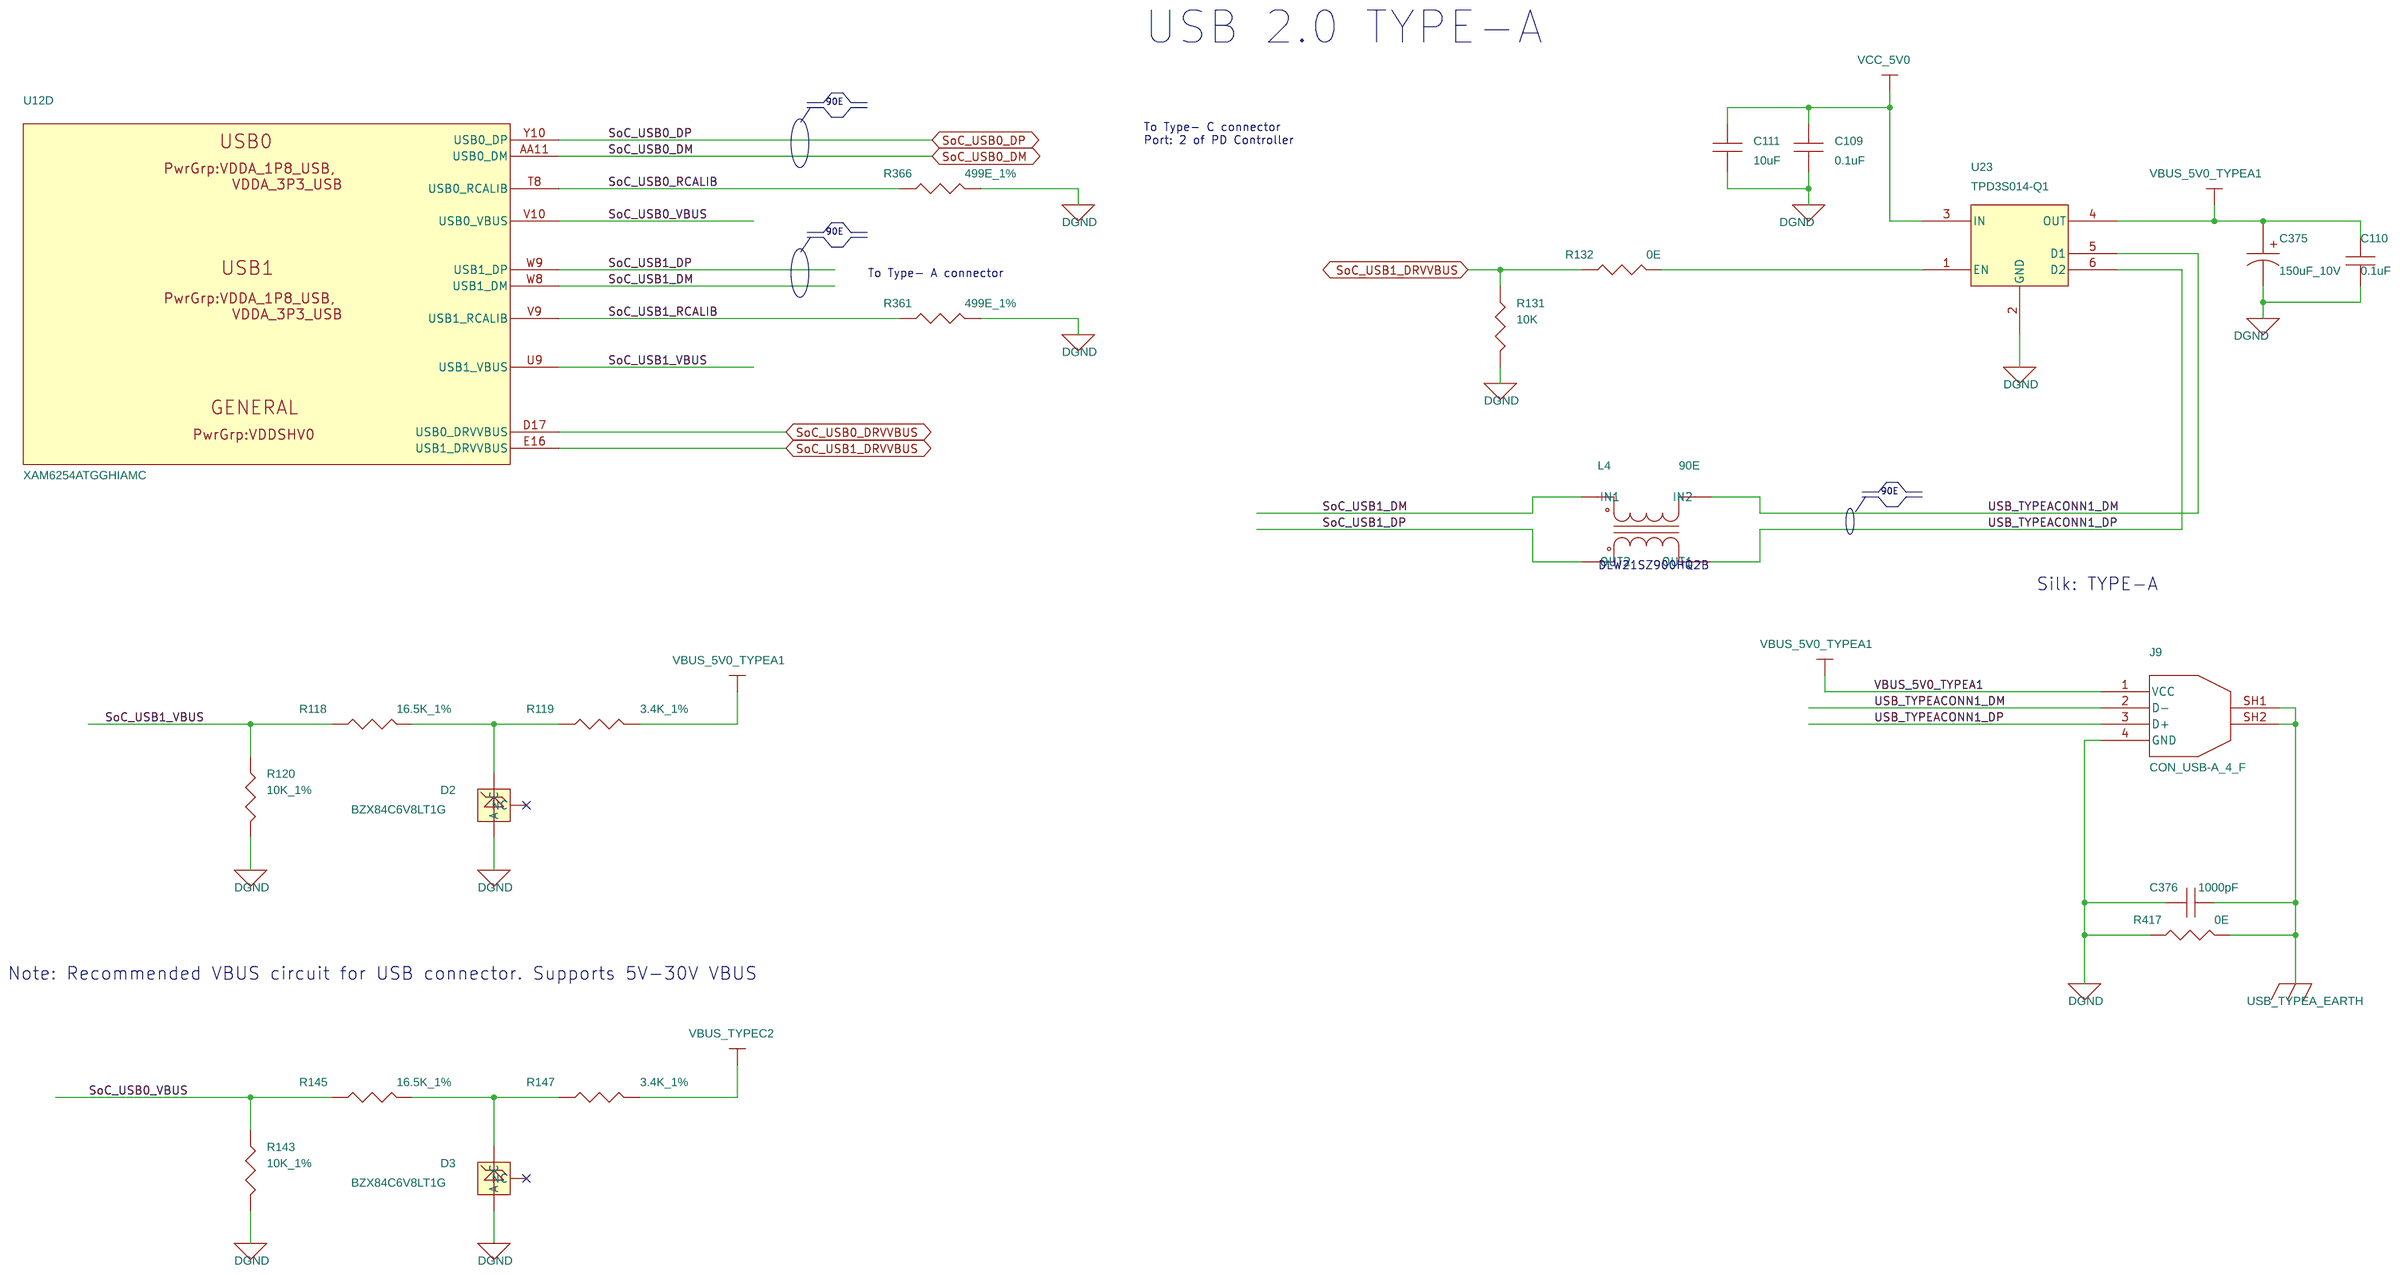
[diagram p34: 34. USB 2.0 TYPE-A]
36 35. USB 2.0 TYPE-C DRP: size C; title: USB TYPE-C DRP
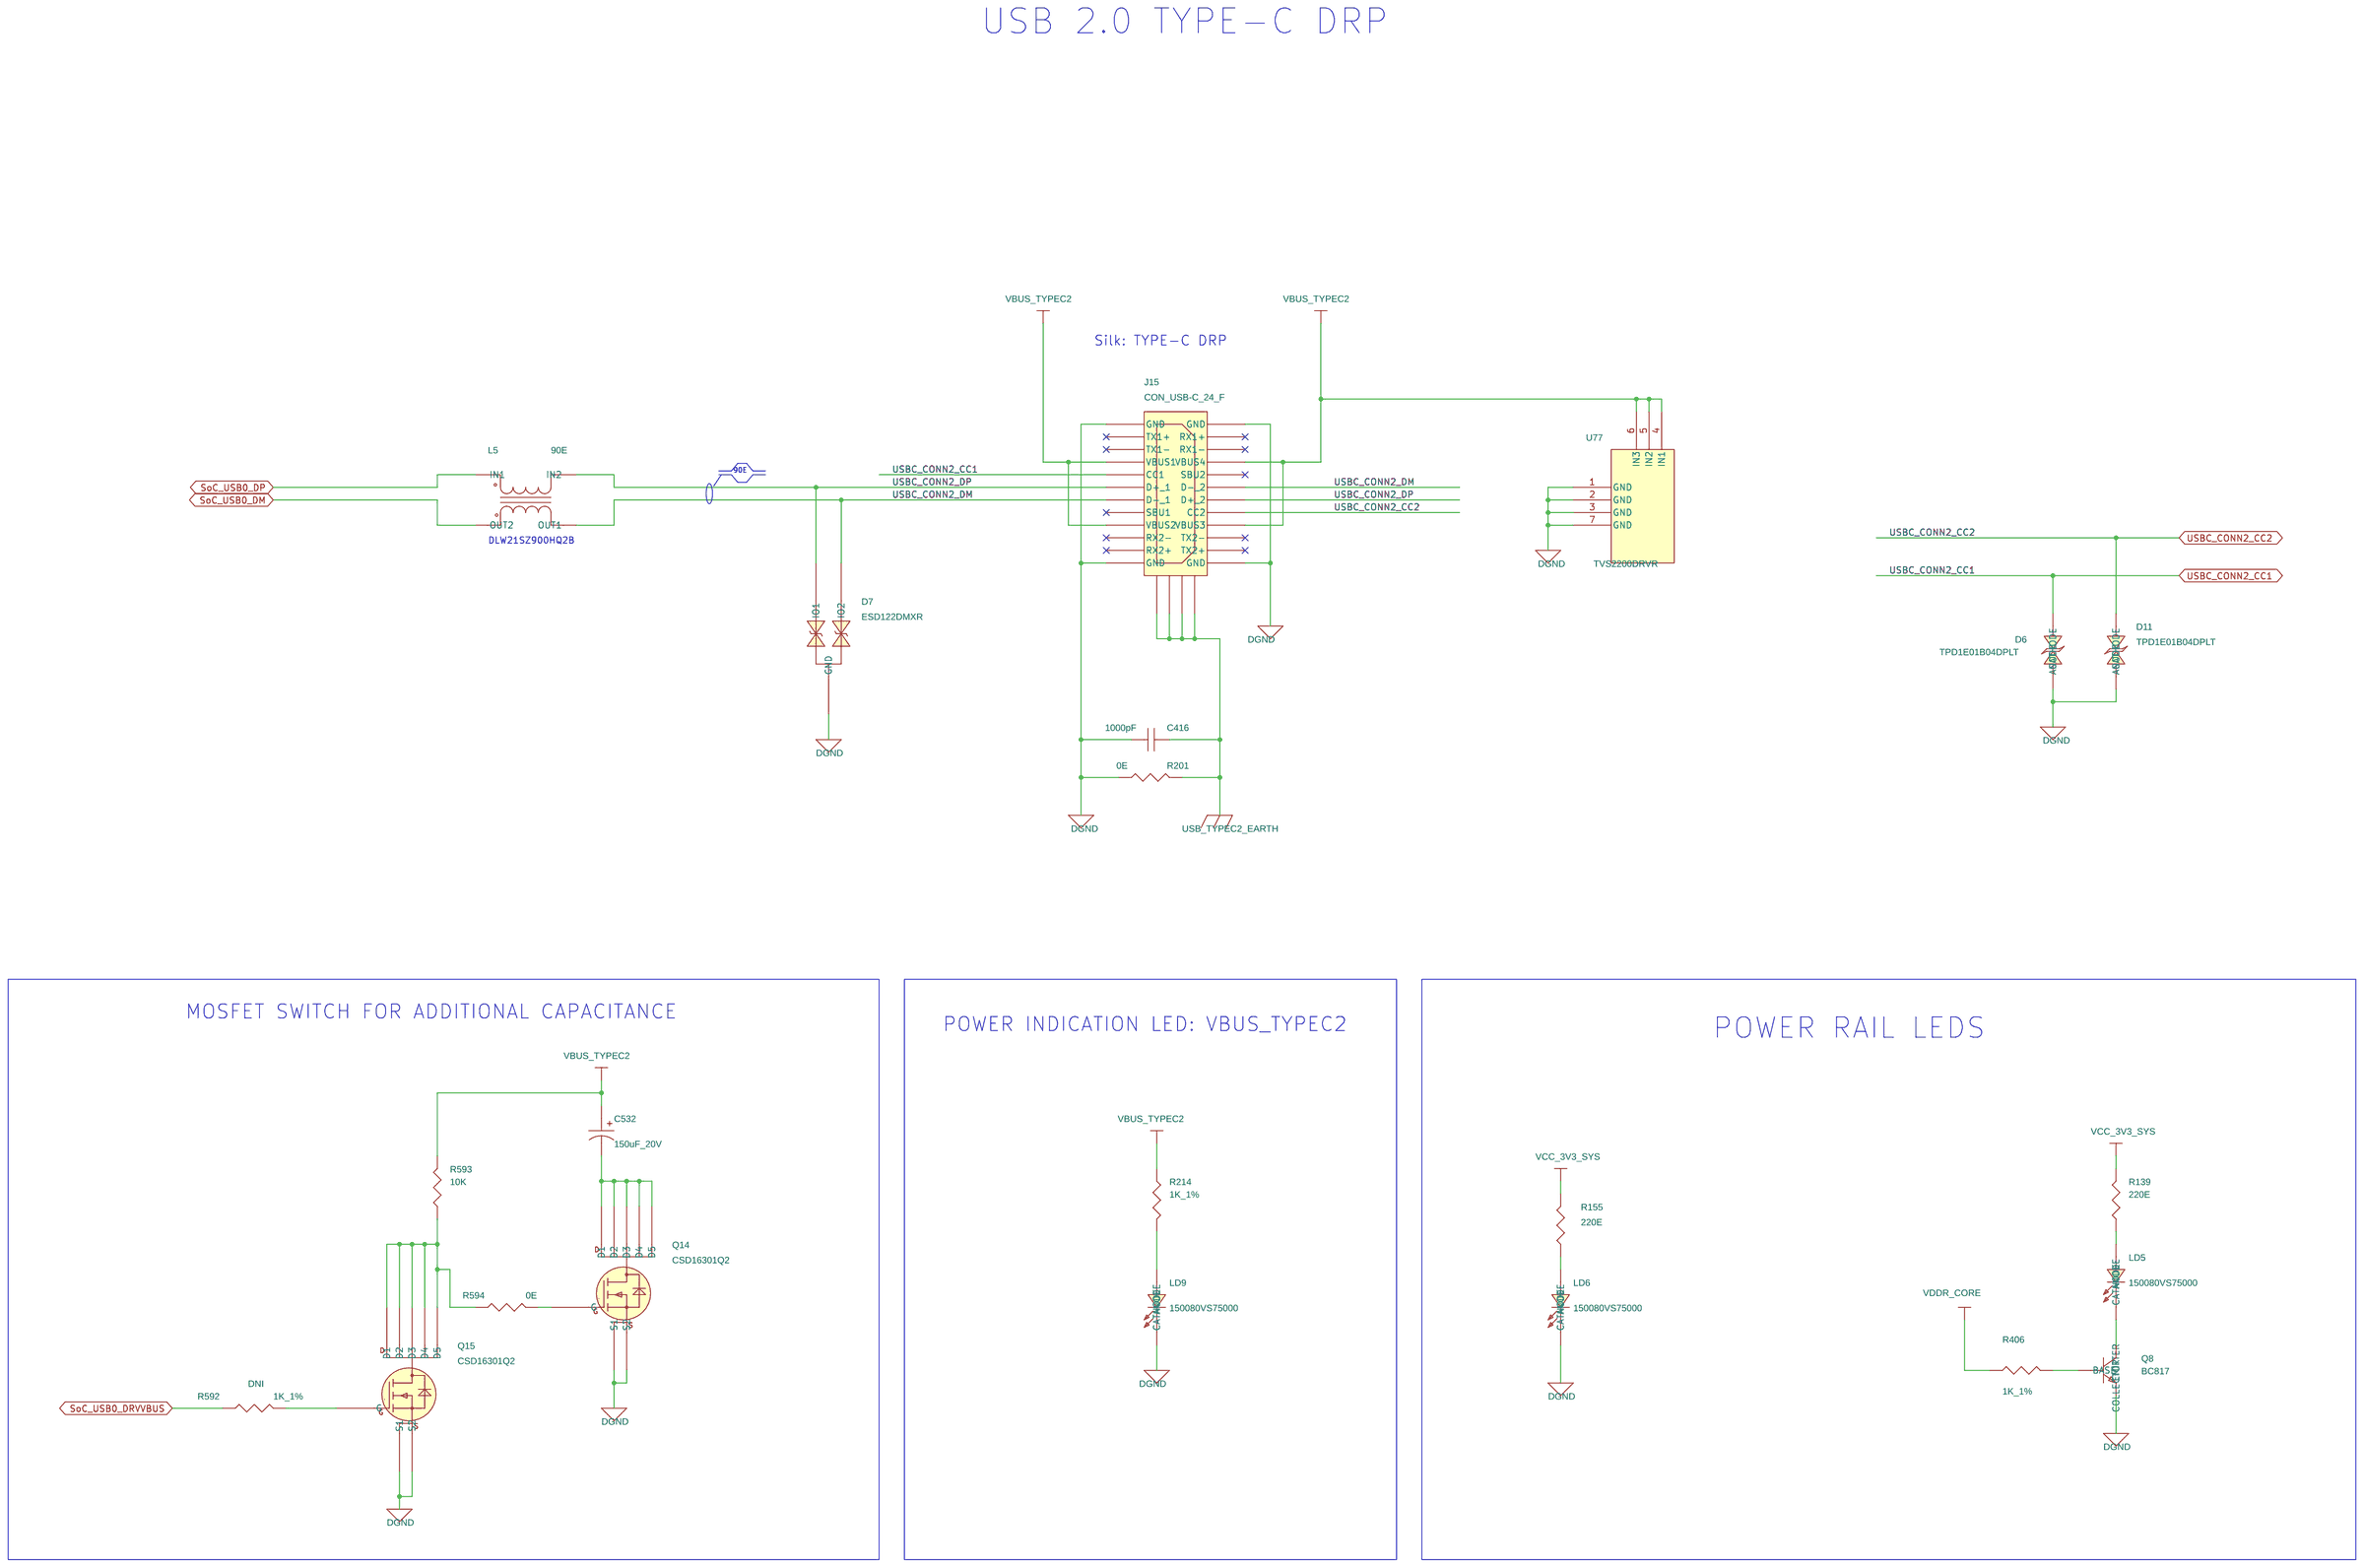
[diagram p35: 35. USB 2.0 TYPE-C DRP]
37 36. OLDI DISPLAY INTERFACE: size C; title: OLDI DISPLAY INTERFACE

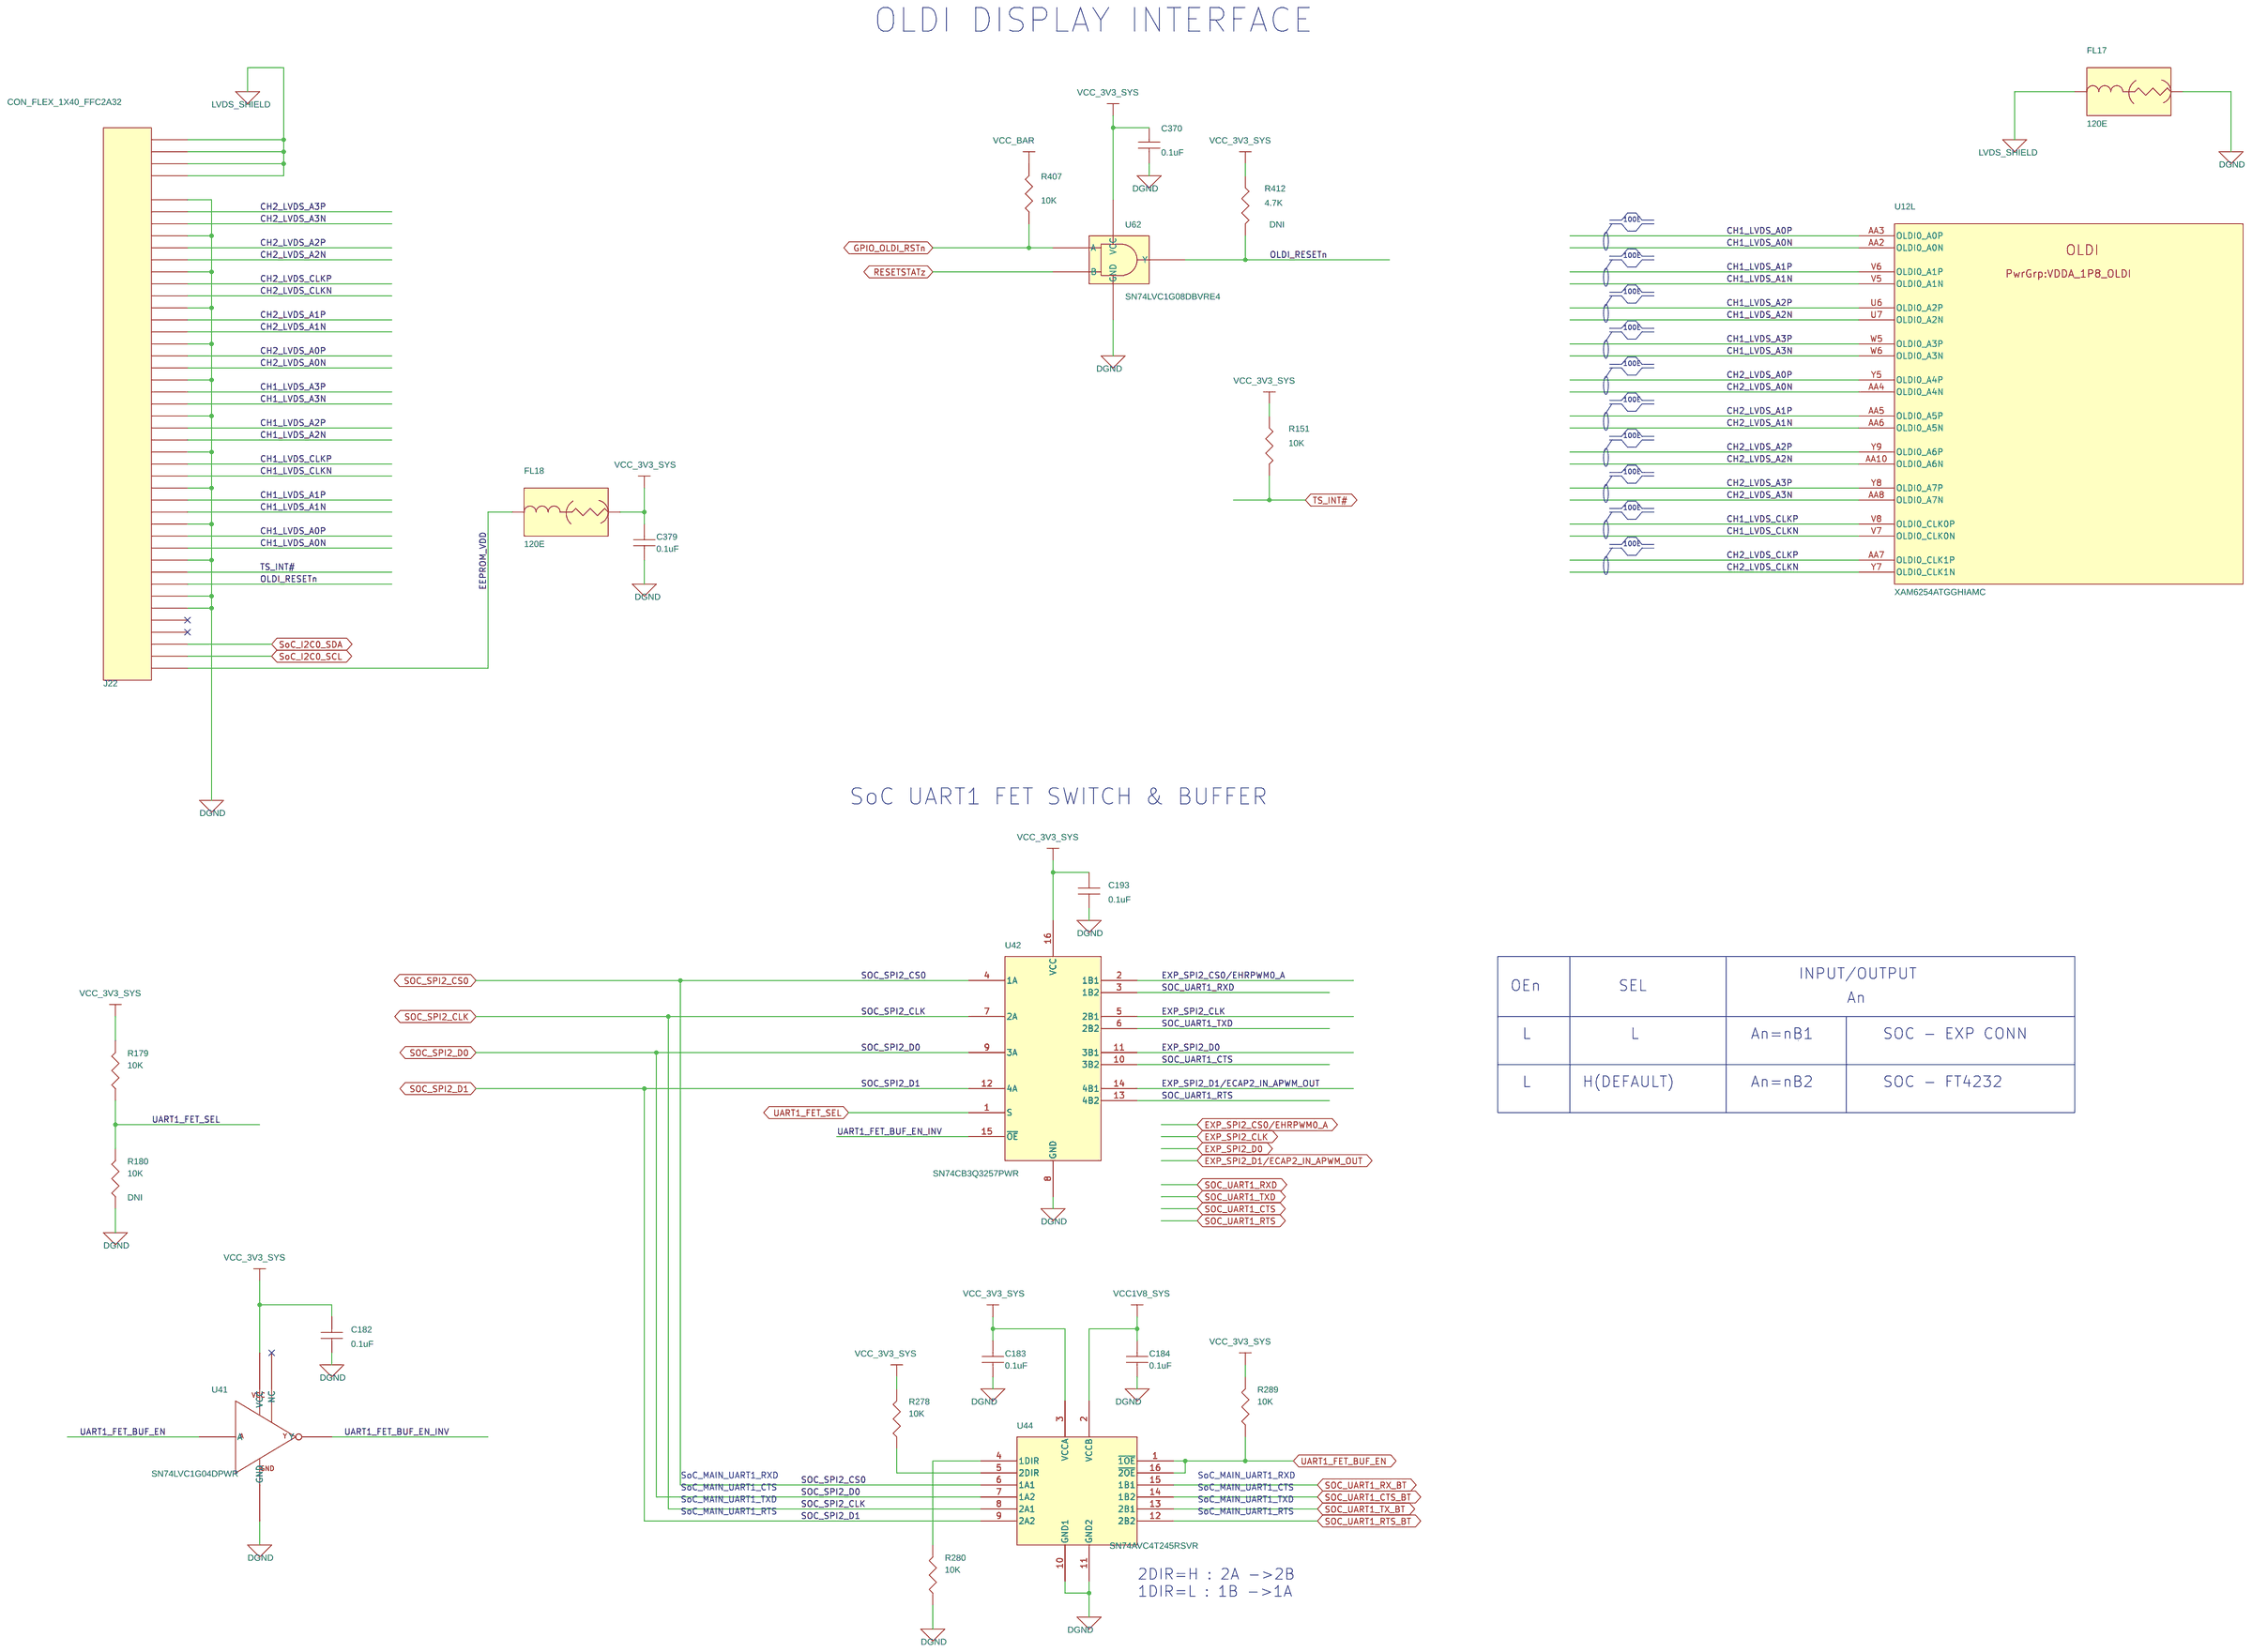
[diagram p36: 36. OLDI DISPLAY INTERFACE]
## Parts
sheet 31. PRU HEADER
U12  XAM6254ATGGHIAMC  [FCBGA441_31-49_680X680_2-6]  (sections A,B,C,D,E,F,G,H,I,J,K,L,M,N,O,P,Q,R)
sheet 34. USB 2.0 TYPE-A
C109  0.1uF  [CAP0201_0-5]
C110  0.1uF  [CAP0201_0-5]
C111  10uF  [CAP0805_1-5]
C375  150uF_10V  [CAPT7343D_3-25]
C376  1000pF  [CAP1206_1-75]
D2  BZX84C6V8LT1G  [SOT23-123_1-2]
D3  BZX84C6V8LT1G  [SOT23-123_1-2]
J9  CON_USB-A_4_F  [CON_USBA4_629104151_S_R_S_7-4]
L4  90E  [IND4_DLW21H_90X60_SMD_1-4]
R118  16.5K_1%  [RES0402_0-5]
R119  3.4K_1%  [RES0201_0-5]
R120  10K_1%  [RES0201_0-5]
R131  10K  [RES0201_0-5]
R132  0E  [RES0201_0-5]
R143  10K_1%  [RES0201_0-5]
R145  16.5K_1%  [RES0402_0-5]
R147  3.4K_1%  [RES0201_0-5]
R361  499E_1%  [RES0402_0-5]
R366  499E_1%  [RES0402_0-5]
R417  0E  [RES0603_0-75]
U23  TPD3S014-Q1  [SOT23-6_1-5]
sheet 35. USB 2.0 TYPE-C DRP
C416  1000pF  [CAP1206_1-75]
C532  150uF_20V  [CAPT7343X_4-3]
D6  TPD1E01B04DPLT  [DIO_DFN0201_0-4]
D7  ESD122DMXR  [X2SON3_ESD122DMX_30X40_0-4]
D11  TPD1E01B04DPLT  [DIO_DFN0201_0-4]
J15  CON_USB-C_24_F  [CON_USBC24_2012670_S_R_S_3-9]
L5  90E  [IND4_DLW21H_90X60_SMD_1-4]
LD5  150080VS75000  [LED_150080VS75000_80X50_SMD_0-8]
LD6  150080VS75000  [LED_150080VS75000_80X50_SMD_0-8]
LD9  150080VS75000  [LED_150080VS75000_80X50_SMD_0-8]
Q8  BC817  [TO_SOT23-123]
Q14  CSD16301Q2  [WSON6_CSD13202Q2_80X80_0-8]
Q15  CSD16301Q2  [WSON6_CSD13202Q2_80X80_0-8]
R139  220E  [RES0402_0-5]
R155  220E  [RES0402_0-5]
R201  0E  [RES0603_0-75]
R214  1K_1%  [RES0402_0-5]
R406  1K_1%  [RES0402_0-5]
R592  1K_1%  [RES0201_0-5]
R593  10K  [RES0201_0-5]
R594  0E  [RES0201_0-5]
U77  TVS2200DRVR  [SON6_25-59_85X85_0-8]
sheet 36. OLDI DISPLAY INTERFACE
C182  0.1uF  [CAP0201_0-5]
C183  0.1uF  [CAP0201_0-5]
C184  0.1uF  [CAP0201_0-5]
C193  0.1uF  [CAP0402_0-75]
C370  0.1uF  [CAP0402_0-75]
C379  0.1uF  [CAP0201_0-5]
FL17  120E  [EMIFIL_BLM15A_0402_0-6]
FL18  120E  [EMIFIL_BLM15A_0402_0-6]
J22  CON_FLEX_1X40_FFC2A32  [CON_FLEX1X40_FFC2A32-40-T_S_S_S_4-3]
R151  10K  [RES0201_0-5]
R179  10K  [RES0201_0-5]
R180  10K  [RES0201_0-5]
R278  10K  [RES0201_0-5]
R280  10K  [RES0201_0-5]
R289  10K  [RES0201_0-5]
R407  10K  [RES0201_0-5]
R412  4.7K  [RES0201_0-5]
U41  SN74LVC1G04DPWR  [X2SON5_TLV7021_30X30_0-4]
U42  SN74CB3Q3257PWR  [TSSOP16_25-59_205X180]
U44  SN74AVC4T245RSVR  [UQFN16_TMUX1574_70X100_0-6]
U62  SN74LVC1G08DBVRE4  [SOT23-5]

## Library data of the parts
U12 = AM62Q_SoC_FCBGA441: IC AM62Q SoC MICROPROCESSOR FCBGA441; Chkd/date: MANIRAJA/211021; Crtd /date: ALVY/211021; Custom_Duty: 15%; Customs_HS_Code: 85423100; Distributor_name: NA; Distributor_part_number: NA; Footprint Path: Y:\MIS_DATABASE\Library\ALTIUM_TOOL\PCB_FOOTPRINTS\Altium_Footprint_Lib.PcbLib; Height: 2.57MM; Library Path: Y:\MIS_DATABASE\Library\ALTIUM_TOOL\SCHEMATICS_PARTS\MS_MICROPROCESSOR_Library.schlib; Mfr_name: TEXAS INSTRUMENTS; Mistral Part No: 141221100001; Package: FCBGA441; Part_type: ICS\DIGITAL\MICROPROCESSOR; Project: TI_AM62Q_BRD; RoHS: NA; Temperature: NA; Tolerance: NA; Voltage: NA; Wattage: NA; Weight: NA; Datasheet: Y:\MIS_DATABASE\DATASHEETS\ICS\DIGITAL\MICROCONTROLLER\AM62Q-SoC.PDF
C109 C110 = CAP: CAP CERAMIC 0.1uF 16V 10% X5R 0201; Chkd/date: MANIRAJA/230118; Crtd /date: MANIRAJA/230118; Custom_Duty: 15%; Customs_HS_Code: 85322990; Distributor_name: DIGIKEY; Distributor_part_number: 490-14305-1-ND; Footprint Path: Y:\MIS_DATABASE\Library\ALTIUM_TOOL\PCB_FOOTPRINTS\Altium_Footprint_Lib.PcbLib; Height: 0.33MM; Library Path: Y:\MIS_DATABASE\Library\ALTIUM_TOOL\SCHEMATICS_PARTS\MS_DISCRETE_Library.schlib; Mfr_name: MURATA; Mfr_part_number: GRM033R61C104KE14D; Mistral Part No: 120009030072-R; Package: 0201; Part_type: CAPACITORS\CERAMIC; Project: TI_MAXIE_CPB; RoHS: RoHS; Temperature: -55°C+85°C; Tolerance: 10%; Voltage: 16V; Wattage: NA; Weight: 0.33mg; Datasheet: Y:\MIS_DATABASE\DATASHEETS\CAPACITORS\GRM033R61C104KE14.PDF
C111 = CAP: CAP CERAMIC 10uF 50V 10% X5R 0805; Chkd/date: MANIRAJA/010321; Crtd /date: ALVY/010321; Custom_Duty: 15%; Customs_HS_Code: 85322990; Distributor_name: DIGIKEY; Distributor_part_number: 490-18663-1-ND; Footprint Path: Y:\MIS_DATABASE\Library\ALTIUM_TOOL\PCB_FOOTPRINTS\Altium_Footprint_Lib.PcbLib; Height: 1.45MM; Library Path: Y:\MIS_DATABASE\Library\ALTIUM_TOOL\SCHEMATICS_PARTS\MS_DISCRETE_Library.schlib; Mfr_name: MURATA; Mfr_part_number: GRM21BR61H106KE43L; Mistral Part No: 120021030002-R; Package: 0805; Part_type: CAPACITORS\CERAMIC; Project: J7ES_SK_BRD; RoHS: RoHS; Temperature: -55°C+85°C; Tolerance: 10%; Voltage: 50V; Wattage: NA; Weight: 6.4mg; Datasheet: Y:\MIS_DATABASE\DATASHEETS\CAPACITORS\GRM21BR61H106KE43.PDF
C375 = CAP_POL: CAP TANTALUM 150uF 10V 10% ESR 600mE D7343; Chkd/date: ALVY/200921; Crtd /date: MANIRAJA/200921; Custom_Duty: 15%; Customs_HS_Code: 85322990; Distributor_name: DIGIKEY; Distributor_part_number: 718-1960-1-ND; Footprint Path: Y:\MIS_DATABASE\Library\ALTIUM_TOOL\PCB_FOOTPRINTS\Altium_Footprint_Lib.PcbLib; Height: 3.10MM; Library Path: Y:\MIS_DATABASE\Library\ALTIUM_TOOL\SCHEMATICS_PARTS\MS_DISCRETE_Library.schlib; Mfr_name: VISHAY; Mfr_part_number: 293D157X9010D2TE3; Mistral Part No: 120021090007-R; Package: D7343; Part_type: CAPACITORS\TANTALUM; Project: TI_AM62x SKEVM_BRD; RoHS: RoHS; Temperature: -55°C+125°C; Tolerance: 10%; Voltage: 10V; Wattage: NA; Weight: 400mg; Datasheet: Y:\MIS_DATABASE\DATASHEETS\CAPACITORS\293D_SER_MAR20.PDF
C376 C416 = CAP: CAP CERAMIC 1000pF 2KV 10% X7R 1206; Chkd/date: SHREESHAIL/291106; Crtd /date: MAZHAR/281106; Custom_Duty: 15%; Customs_HS_Code: 85322990; Distributor_name: DIGIKEY; Distributor_part_number: 478-2956-1-ND; Footprint Path: Y:\MIS_DATABASE\Library\ALTIUM_TOOL\PCB_FOOTPRINTS\Altium_Footprint_Lib.PcbLib; Height: 1.52MM; Library Path: Y:\MIS_DATABASE\Library\ALTIUM_TOOL\SCHEMATICS_PARTS\MS_DISCRETE_Library.schlib; Mfr_name: AVX CORPORATION; Mfr_part_number: 1206GC102KAT1A; Mistral Part No: 120015080006-R; Package: 1206; Part_type: CAPACITORS\CERAMIC; Project: ADR1B; RoHS: RoHS; Temperature: -55°C+125°C; Tolerance: 10%; Voltage: 2KV; Wattage: NA; Weight: 16.2mg; Datasheet: Y:\MIS_DATABASE\DATASHEETS\CAPACITORS\AVX_HV-MLC.PDF
D2 D3 = DIODE_ZENER_SOT23_13: DIODE ZENER 250mW 6.8V SOT23-123; Chkd/date: MANIRAJA/031017; Crtd /date: MANIRAJA/031017; Custom_Duty: 15%; Customs_HS_Code: 85412900; Distributor_name: DIGIKEY; Distributor_part_number: BZX84C6V8LT1GOSCT-ND; Height: 1.11MM; Mfr_name: ON SEMICONDUCTOR; Mistral Part No: 130017100002-R; Package: SOT23-123; Part_type: DIODE\ZENER; Project: TI_MAXIE_CPB; RoHS: RoHS; Temperature: -65°C+150°C; Tolerance: NA; Voltage: 6.8V; Wattage: NA; Weight: 8mg; Datasheet: Y:\MIS_DATABASE\DATASHEETS\DISCRETES\DIODES\BZX84XX.PDF
J9 = CON_USB-A_4_2SH: CON USB-A TYPE 4POS FEMALE RT SMD; Chkd/date: MANIRAJA/271017; Crtd /date: MANIRAJA/271017; Custom_Duty: 24%; Customs_HS_Code: 85369090; Distributor_name: DIGIKEY; Distributor_part_number: 732-5969-1-ND; Height: 7.35MM; Manufacturer: WURTH ELECTRONICS; Mfr_name: WURTH ELECTRONICS; Mfr_part_number: 629104151021; Mistral Part No: 150017100042-R; Package: SMD; Part_type: CONNECTOR\USB; Project: TI_SVB_MAXWELL_SPM; RoHS: RoHS; Temperature: -40°C+85°C; Tolerance: NA; Voltage: NA; Wattage: NA; Weight: NA; Datasheet: Y:\MIS_DATABASE\DATASHEETS\CONNECTORS\629104151021.PDF
L4 L5 = INDUCTOR_DLW31S: IND COMMON MODE CHOKE 90E 280mA SMD; Chkd/date: MANIRAJA/270619; Crtd /date: MANIRAJA/270619; Custom_Duty: 24%; Customs_HS_Code: 85437099; Distributor_name: NA; Distributor_part_number: NA; Footprint Path: Y:\MIS_DATABASE\Library\ALTIUM_TOOL\PCB_FOOTPRINTS\Altium_Footprint_Lib.PcbLib; Height: 1.40MM; Library Path: Y:\MIS_DATABASE\Library\ALTIUM_TOOL\SCHEMATICS_PARTS\MS_DISCRETE_Library.schlib; Mfr_name: MURATA; Mfr_part_number: DLW21SZ900HQ2B; Mistral Part No: 130019060035-R; Package: SMD; Part_type: INDUCTOR; Project: TI_J7ES_CP; RoHS: RoHS; Temperature: -40°C+105°C; Tolerance: NA; Voltage: NA; Wattage: NA; Weight: 11mg; Datasheet: Y:\MIS_DATABASE\DATASHEETS\DISCRETES\INDUCTORS\DLW21SZ900HQ2B.PDF
R118 R145 = RESISTOR: RES 16.5K 1/16W 1% 0402; Chkd/date: ALVY/091220; Crtd /date: MANIRAJA/091220; Custom_Duty: 15%; Customs_HS_Code: 85332119; Distributor_name: DIGIKEY; Distributor_part_number: YAG3002CT-ND; Footprint Path: Y:\MIS_DATABASE\Library\ALTIUM_TOOL\PCB_FOOTPRINTS\Altium_Footprint_Lib.PcbLib; Height: 0.40MM; Library Path: Y:\MIS_DATABASE\Library\ALTIUM_TOOL\SCHEMATICS_PARTS\MS_DISCRETE_Library.schlib; Mfr_name: YAGEO AMERICA; Mfr_part_number: RC0402FR-0716K5L; Mistral Part No: 110020120011-R; Package: 0402; Part_type: RESISTORS\FIXED; Project: TI_AM243x LP EVM; RoHS: RoHS; Temperature: -55°C+155°C; Tolerance: 1%; Voltage: NA; Wattage: 1/16W; Weight: 0.65mg; Datasheet: Y:\MIS_DATABASE\DATASHEETS\RESISTORS\RCXXXXL-SER_MAR18.PDF
R119 R147 = RESISTOR: RES 3.4K 1/20W 1% 0201; Chkd/date: VASANTHA/250116; Crtd /date: VASANTHA/250116; Custom_Duty: 15%; Customs_HS_Code: 85332119; Distributor_name: DIGIKEY; Distributor_part_number: ERJ-1GNF3401C-ND; Footprint Path: Y:\MIS_DATABASE\Library\ALTIUM_TOOL\PCB_FOOTPRINTS\Altium_Footprint_Lib.PcbLib; Height: 0.26MM; Library Path: Y:\MIS_DATABASE\Library\ALTIUM_TOOL\SCHEMATICS_PARTS\MS_DISCRETE_Library.schlib; Mfr_name: PANASONIC-ECG; Mfr_part_number: ERJ-1GNF3401C; Mistral Part No: 110016010003-R; Package: 0201; Part_type: RESISTORS\FIXED; Project: QUADIO; RoHS: RoHS; Temperature: -55°C+125°C; Tolerance: 1%; Voltage: NA; Wattage: 1/20W; Weight: 0.15mg; Datasheet: Y:\MIS_DATABASE\DATASHEETS\RESISTORS\PAN-ERJSER_NOV17.PDF
R120 R143 = RESISTOR: RES 10K 1/20W 1% 0201; Chkd/date: VASANTHA/270117; Crtd /date: MANIRAJA/270117; Custom_Duty: 15%; Customs_HS_Code: 85332119; Distributor_name: DIGIKEY; Distributor_part_number: 311-10.0KMCT-ND; Footprint Path: Y:\MIS_DATABASE\Library\ALTIUM_TOOL\PCB_FOOTPRINTS\Altium_Footprint_Lib.PcbLib; Height: 0.26MM; Library Path: Y:\MIS_DATABASE\Library\ALTIUM_TOOL\SCHEMATICS_PARTS\MS_DISCRETE_Library.schlib; Mfr_name: YAGEO AMERICA; Mfr_part_number: RC0201FR-0710KL; Mistral Part No: 110011040018-R; Package: 0201; Part_type: RESISTORS\FIXED; Project: GOLDEN-I LITE; RoHS: RoHS; Temperature: -55°C+125°C; Tolerance: 1%; Voltage: NA; Wattage: 1/20W; Weight: 0.17mg; Datasheet: Y:\MIS_DATABASE\DATASHEETS\RESISTORS\RCXXXXL-SER_MAR18.PDF
R131 R151 R179 R278 R280 R289 R407 R593 = RESISTOR: RES 10K 1/20W 5% 0201; Chkd/date: MANIRAJA/050517; Crtd /date: MANIRAJA/050517; Custom_Duty: 15%; Customs_HS_Code: 85332119; Distributor_name: DIGIKEY; Distributor_part_number: 311-10KNCT-ND; Footprint Path: Y:\MIS_DATABASE\Library\ALTIUM_TOOL\PCB_FOOTPRINTS\Altium_Footprint_Lib.PcbLib; Height: 0.26MM; Library Path: Y:\MIS_DATABASE\Library\ALTIUM_TOOL\SCHEMATICS_PARTS\MS_DISCRETE_Library.schlib; Mfr_name: YAGEO AMERICA; Mfr_part_number: RC0201JR-0710KL; Mistral Part No: 110010070051-R; Package: 0201; Part_type: RESISTORS\FIXED; Project: GOLDEN-I LITE; RoHS: RoHS; Temperature: -55°C+125°C; Tolerance: 5%; Voltage: NA; Wattage: 1/20W; Weight: 0.17mg; Datasheet: Y:\MIS_DATABASE\DATASHEETS\RESISTORS\RCXXXXL-SER_MAR18.PDF
R132 R594 = RESISTOR: RES 0E 1/20W 5% 0201; Chkd/date: NAVEED/301214; Crtd /date: MUDDU/120710; Custom_Duty: 15%; Customs_HS_Code: 85332119; Distributor_name: DIGIKEY; Distributor_part_number: 311-0.0NCT-ND; Footprint Path: Y:\MIS_DATABASE\Library\ALTIUM_TOOL\PCB_FOOTPRINTS\Altium_Footprint_Lib.PcbLib; Height: 0.26MM; Library Path: Y:\MIS_DATABASE\Library\ALTIUM_TOOL\SCHEMATICS_PARTS\MS_DISCRETE_Library.schlib; Mfr_name: YAGEO AMERICA; Mfr_part_number: RC0201JR-070RL; Mistral Part No: 110010070067-R; Package: 0201; Part_type: RESISTORS\FIXED; Project: PB_BUGBASE; RoHS: RoHS; Temperature: -55°C+125°C; Tolerance: 5%; Voltage: NA; Wattage: 1/20W; Weight: 0.17mg; Datasheet: Y:\MIS_DATABASE\DATASHEETS\RESISTORS\RCXXXXL-SER_MAR18.PDF
R361 R366 = RESISTOR: RES 499E 1/16W 1% 0402; Chkd/date: MANIRAJA/051020; Crtd /date: ALVY/051020; Custom_Duty: 15%; Customs_HS_Code: 85332119; Distributor_name: DIGIKEY; Distributor_part_number: 311-499LRCT-ND; Footprint Path: Y:\MIS_DATABASE\Library\ALTIUM_TOOL\PCB_FOOTPRINTS\Altium_Footprint_Lib.PcbLib; Height: 0.40MM; Library Path: Y:\MIS_DATABASE\Library\ALTIUM_TOOL\SCHEMATICS_PARTS\MS_DISCRETE_Library.schlib; Mfr_name: YAGEO AMERICA; Mfr_part_number: RC0402FR-07499RL; Mistral Part No: 110020080006-R; Package: 0402; Part_type: RESISTORS\FIXED; Project: AM64XX_EVM; RoHS: RoHS; Temperature: -55°C+155°C; Tolerance: 1%; Voltage: NA; Wattage: 1/16W; Weight: 0.65mg; Datasheet: Y:\MIS_DATABASE\DATASHEETS\RESISTORS\RCXXXXL-SER_MAR18.PDF
R201 R417 = RESISTOR: RES 0E 1/10W 5% 0603; Chkd/date: MANIRAJA/051217; Crtd /date: BAVISH/180211; Custom_Duty: 15%; Customs_HS_Code: 85332119; Distributor_name: DIGIKEY; Distributor_part_number: 311-0.0GRCT-ND; Footprint Path: Y:\MIS_DATABASE\Library\ALTIUM_TOOL\PCB_FOOTPRINTS\Altium_Footprint_Lib.PcbLib; Height: 0.55MM; Library Path: Y:\MIS_DATABASE\Library\ALTIUM_TOOL\SCHEMATICS_PARTS\MS_DISCRETE_Library.schlib; Mfr_name: YAGEO AMERICA; Mfr_part_number: RC0603JR-070RL; Mistral Part No: 110011020013-R; Package: 0603; Part_type: RESISTORS\FIXED; Project: KENNEL; RoHS: RoHS; Temperature: -55°C+155°C; Tolerance: 5%; Voltage: NA; Wattage: 1/10W; Weight: 2mg; Datasheet: Y:\MIS_DATABASE\DATASHEETS\RESISTORS\RCXXXXL-SER_MAR18.PDF
U23 = TPD3S014D_SOT23-6: IC ESD PROTECTION FOR AUTO USB PORT WITH CURRENT LIMIT SWITCH SOT23-6; Chkd/date: MANIRAJA/180918; Crtd /date: ALVY/180918; Custom_Duty: 15%; Customs_HS_Code: 85423100; Distributor_name: DIGIKEY; Distributor_part_number: 296-44163-1-ND; Footprint Path: Y:\MIS_DATABASE\Library\ALTIUM_TOOL\PCB_FOOTPRINTS\Altium_Footprint_Lib.PcbLib; Height: 1.45MM; Library Path: Y:\MIS_DATABASE\Library\ALTIUM_TOOL\SCHEMATICS_PARTS\MS_MISCINTERFACE_Library.schlib; Mfr_name: TEXAS INSTRUMENTS; Mfr_part_number: TPD3S014TDBVRQ1; Mistral Part No: 141018090014-R; Package: SOT23-6; Part_type: ICS\INTERFACE; Project: TI_J7ES_EVM_CP; RoHS: RoHS; Temperature: -40°C+105°C; Tolerance: NA; Voltage: NA; Wattage: NA; Weight: NA; Datasheet: Y:\MIS_DATABASE\DATASHEETS\ICS\INTERFACE\TPD3S014-Q1.PDF
C532 = CAP_POL: CAP TANTALUM 150uF 20V 10% ESR 0.5E X7343; Chkd/date: PRAVEEN/291122; Crtd /date: PRAVEEN/291122; Custom_Duty: 15%; Customs_HS_Code: 85322990; Distributor_name: DIGIKEY; Distributor_part_number: 399-4794-1-ND; Footprint Path: Y:\MIS_DATABASE\Library\ALTIUM_TOOL\PCB_FOOTPRINTS\Altium_Footprint_Lib.PcbLib; Height: 4.30MM; Library Path: Y:\MIS_DATABASE\Library\ALTIUM_TOOL\SCHEMATICS_PARTS\MS_DISCRETE_Library.schlib; Mfr_name: KEMET; Mfr_part_number: T491X157K020AT; Mistral Part No: 120022110050-R; Package: X7343; Part_type: CAPACITORS\TANTALUM; Project: SK-AM62Q-LP_EVM; RoHS: RoHS; Temperature: -55°C+125°C; Tolerance: 10%; Voltage: 20V; Wattage: NA; Weight: 600mg; Datasheet: Y:\MIS_DATABASE\DATASHEETS\CAPACITORS\KEMET_T491_MAR18.PDF
D6 D11 = DIODE_TVS_DUAL: DIODE 1CH ESD PROTECTION FOR USB TYPE-C AND THUNDERBOLT3 X2SON2; Chkd/date: MANIRAJA/230920; Crtd /date: ALVY/230920; Custom_Duty: 15%; Customs_HS_Code: 85412900; Distributor_name: DIGIKEY; Distributor_part_number: 296-44484-1-ND; Footprint Path: Y:\MIS_DATABASE\Library\ALTIUM_TOOL\PCB_FOOTPRINTS\Altium_Footprint_Lib.PcbLib; Height: 0.32MM; Library Path: Y:\MIS_DATABASE\Library\ALTIUM_TOOL\SCHEMATICS_PARTS\MS_DISCRETE_Library.schlib; Mfr_name: TEXAS INSTRUMENTS; Mistral Part No: 130020090037-R; Package: X2SON2; Part_type: DIODE\TVS; Project: AM64X_SKEVM; RoHS: RoHS; Temperature: -40°C+125°C; Tolerance: NA; Voltage: NA; Wattage: NA; Weight: 0.2mg; Datasheet: Y:\MIS_DATABASE\DATASHEETS\DISCRETES\DIODES\TPD1E01B04.PDF
D7 = DIODE_ESD122DMXR: DIODE 2-CH ESD PROTECTION FOR USB TYPE-C AND HDMI 2.0 X2SON-3; Chkd/date: MANIRAJA/140817; Crtd /date: MANIRAJA/140817; Custom_Duty: 15%; Customs_HS_Code: 85412900; Distributor_name: DIGIKEY; Distributor_part_number: ESD122DMXR-ND; Height: 0.40MM; Mfr_name: TEXAS INSTRUMENTS; Mistral Part No: 130017080015-R; Package: X2SON-3; Part_type: DIODE\TVS; Project: TI_SVB_CONTROLLER CARD; RoHS: RoHS; Temperature: -40°C+125°C; Tolerance: NA; Voltage: NA; Wattage: NA; Weight: NA; Datasheet: Y:\MIS_DATABASE\DATASHEETS\DISCRETES\DIODES\ESD122XX.PDF
J15 = CON_USB-C_24_1240183621: CON USB-C TYPE 24POS FEMALE RT SMD; Chkd/date: MANIRAJA/050618; Crtd /date: ALVY/040618; Custom_Duty: 24%; Customs_HS_Code: 85369090; Distributor_name: DIGIKEY; Distributor_part_number: WM17992CT-ND; Footprint Path: Y:\MIS_DATABASE\Library\ALTIUM_TOOL\PCB_FOOTPRINTS\Altium_Footprint_Lib.PcbLib; Height: 3.86MM; Library Path: Y:\MIS_DATABASE\Library\ALTIUM_TOOL\SCHEMATICS_PARTS\MS_CONNECTOR_Library.schlib; Mfr_name: MOLEX; Mfr_part_number: 2012670005; Mistral Part No: 150018060002-R; Package: SMD; Part_type: CONNECTOR\USB; Project: TI_J7SVB_USB_ADD-ON-CARD; RoHS: RoHS; Temperature: -40°C+105°C; Tolerance: NA; Voltage: NA; Wattage: NA; Weight: 0.686g; Datasheet: Y:\MIS_DATABASE\DATASHEETS\CONNECTORS\2012670X.PDF
LD5 LD6 LD9 = DIODE_LED: DIODE LED BRIGHT GREEN SMD; Chkd/date: MANIRAJA/180820; Crtd /date: ALVY/180820; Custom_Duty: 24%; Customs_HS_Code: 85439000; Distributor_name: DIGIKEY; Distributor_part_number: 732-4986-1-ND; Footprint Path: Y:\MIS_DATABASE\Library\ALTIUM_TOOL\PCB_FOOTPRINTS\Altium_Footprint_Lib.PcbLib; Height: 0.80MM; Library Path: Y:\MIS_DATABASE\Library\ALTIUM_TOOL\SCHEMATICS_PARTS\MS_OPTO_Library.schlib; Mfr_name: WURTH ELECTRONICS; Mistral Part No: 130020080012-R; Package: SMD; Part_type: OPTO\LED; Project: AM64x_EVM_BRD; RoHS: RoHS; Temperature: -40°C+85°C; Tolerance: NA; Voltage: NA; Wattage: NA; Weight: 10mg; Datasheet: Y:\MIS_DATABASE\DATASHEETS\DISCRETES\LEDS\150080VS75000.PDF
Q8 = NPN_BEC: TRANSISTOR NPN SOT23-3; Alternate_mfr_name_A: FAIRCHILD SEMICONDUCTOR; Alternate_mfr_name_B: PHILIPS; Alternate_mfr_name_C: ZETEX; Alternate_mfr_name_D: ST MICROELECTRONICS / PHILIPS SEMICONDUCTORS; Alternate_mfr_part_number_A: BC846B; Alternate_mfr_part_number_C: FMMT2369; Alternate_mfr_part_number_D: MMBT3904; Chkd/date: SHREESHAIL/020206; Crtd /date: MAZHAR/140505; Custom_Duty: 15%; Customs_HS_Code: 85412900; Distributor_name: DIGIKEY; Distributor_part_number: 568-1631-1-ND; Height: 1.14MM; Manufacturer: FAIRCHILD; Mfr_name: FAIRCHILD; Mfr_part_number: BC817-40; Mistral Part No: 130009031166-R; Package: SOT23-3; Part_type: TRANSISTOR\BIPOLAR; Project: G4_SVGA; RoHS: RoHS; Temperature: -65°C+150°C; Datasheet: Y:\MIS_DATABASE\DATASHEETS\DISCRETES\TRANSISTORS_FETS\BC817.PDF
Q14 Q15 = MOSFET_CSD17313Q2: IC MOSFET N-CHANNEL NEXFET 25V WSON6; Chkd/date: ALVY/071220; Crtd /date: MANIRAJA/071220; Custom_Duty: 15%; Customs_HS_Code: 85423100; Distributor_name: DIGIKEY; Distributor_part_number: 296-25260-1-ND; Footprint Path: Y:\MIS_DATABASE\Library\ALTIUM_TOOL\PCB_FOOTPRINTS\Altium_Footprint_Lib.PcbLib; Height: 0.80MM; Library Path: Y:\MIS_DATABASE\Library\ALTIUM_TOOL\SCHEMATICS_PARTS\MS_MOSFET_Library.schlib; Manufacturer: TEXAS INSTRUMENTS; Mfr_name: TEXAS INSTRUMENTS; Mistral Part No: 142020120008-R; Package: WSON6; Part_type: ICS\POWER\MOSFET; Project: TI_AM243x LP EVM; RoHS: RoHS; Temperature: -55°C+150°C; Tolerance: NA; Voltage: NA; Wattage: NA; Weight: 8.7mg; Datasheet: Y:\MIS_DATABASE\DATASHEETS\ICS\POWER\CSD16301Q2.PDF
R139 R155 = RESISTOR: RES 220E 1/10W 5% 0402; Chkd/date: VASANTHA/291216; Crtd /date: GEETHA/260406; Custom_Duty: 15%; Customs_HS_Code: 85332119; Distributor_name: DIGIKEY; Distributor_part_number: P220JCT-ND; Footprint Path: Y:\MIS_DATABASE\Library\ALTIUM_TOOL\PCB_FOOTPRINTS\Altium_Footprint_Lib.PcbLib; Height: 0.40MM; Library Path: Y:\MIS_DATABASE\Library\ALTIUM_TOOL\SCHEMATICS_PARTS\MS_DISCRETE_Library.schlib; Mfr_name: PANASONIC-ECG; Mfr_part_number: ERJ-2GEJ221X; Mistral Part No: 110009030506-R; Package: 0402; Part_type: RESISTORS\FIXED; Project: RED EYE; RoHS: RoHS; Temperature: -55°C+155°C; Tolerance: 5%; Voltage: NA; Wattage: 1/10W; Weight: 0.8mg; Datasheet: Y:\MIS_DATABASE\DATASHEETS\RESISTORS\PAN-ERJSER_NOV17.PDF
R214 R406 = RESISTOR: RES 1K 1/10W 1% 0402; Chkd/date: VASANTHA/281216; Crtd /date: MAZHAR/150506; Custom_Duty: 15%; Customs_HS_Code: 85332119; Distributor_name: DIGIKEY; Distributor_part_number: P1.00KLCT-ND; Footprint Path: Y:\MIS_DATABASE\Library\ALTIUM_TOOL\PCB_FOOTPRINTS\Altium_Footprint_Lib.PcbLib; Height: 0.40MM; Library Path: Y:\MIS_DATABASE\Library\ALTIUM_TOOL\SCHEMATICS_PARTS\MS_DISCRETE_Library.schlib; Mfr_name: PANASONIC-ECG; Mfr_part_number: ERJ-2RKF1001X; Mistral Part No: 110009030411-R; Package: 0402; Part_type: RESISTORS\FIXED; Project: VOCERA; RoHS: RoHS; Temperature: -55°C+155°C; Tolerance: 1%; Voltage: NA; Wattage: 1/10W; Weight: 0.8mg; Datasheet: Y:\MIS_DATABASE\DATASHEETS\RESISTORS\PAN-ERJSER_NOV17.PDF
R592 = RESISTOR: RES 1K 1/20W 1% 0201; Assembly_Instruction: DNI; Chkd/date: JEBRAN/110815; Crtd /date: JEBRAN/110815; Custom_Duty: 15%; Customs_HS_Code: 85332119; Distributor_name: DIGIKEY; Distributor_part_number: 541-1.00KAABCT-ND; Footprint Path: Y:\MIS_DATABASE\Library\ALTIUM_TOOL\PCB_FOOTPRINTS\Altium_Footprint_Lib.PcbLib; Height: 0.28MM; Library Path: Y:\MIS_DATABASE\Library\ALTIUM_TOOL\SCHEMATICS_PARTS\MS_DISCRETE_Library.schlib; Mfr_name: VISHAY; Mfr_part_number: CRCW02011K00FKED; Mistral Part No: 110015080014-R; Package: 0201; Part_type: RESISTORS\FIXED; Project: OCTASIC_3000; RoHS: RoHS; Temperature: -55°C+155°C; Tolerance: 1%; Voltage: NA; Wattage: 1/20W; Weight: 0.17mg; Datasheet: Y:\MIS_DATABASE\DATASHEETS\RESISTORS\CRCW0201.PDF
U77 = TVS2200_WSON6: IC 22V FLAT-CLAMP SURGE PROTECTION DEVICE WSON6; Chkd/date: MANIRAJA/011021; Crtd /date: ALVY/011021; Custom_Duty: 15%; Customs_HS_Code: 85423100; Distributor_name: DIGIKEY; Distributor_part_number: 296-52187-1-ND; Footprint Path: Y:\MIS_DATABASE\Library\ALTIUM_TOOL\PCB_FOOTPRINTS\Altium_Footprint_Lib.PcbLib; Height: 0.80MM; Library Path: Y:\MIS_DATABASE\Library\ALTIUM_TOOL\SCHEMATICS_PARTS\MS_MISCPOWER_Library.schlib; Mfr_name: TEXAS INSTRUMENTS; Mistral Part No: 142021100001-R; Package: WSON6; Part_type: ICS\POWER; Project: TI_AM62x SKEVM_BRD; RoHS: RoHS; Temperature: -40°C+125°C; Tolerance: NA; Voltage: NA; Wattage: NA; Weight: 12mg; Datasheet: Y:\MIS_DATABASE\DATASHEETS\ICS\POWER\TVS2200.PDF
C182-C184 C379 = CAP: CAP CERAMIC 0.1uF 16V 10% X5R 0201; Alt_Mfr_name: YAGEO AMERICA; Alt_Mfr_part_number: CC0402KRX5R8BB104; Chkd/date: MANIRAJA/230118; Crtd /date: MANIRAJA/230118; Custom_Duty: 15%; Customs_HS_Code: 85322990; Distributor_name: DIGIKEY; Distributor_part_number: 490-14305-1-ND; Footprint Path: Y:\MIS_DATABASE\Library\ALTIUM_TOOL\PCB_FOOTPRINTS\Altium_Footprint_Lib.PcbLib; Height: 0.33MM; Library Path: Y:\MIS_DATABASE\Library\ALTIUM_TOOL\SCHEMATICS_PARTS\MS_DISCRETE_Library.schlib; Mfr_name: MURATA; Mfr_part_number: GRM033R61C104KE14D; Mistral Part No: 120009030072-R; Package: 0201; Part_type: CAPACITORS\CERAMIC; Project: TI_MAXIE_CPB; RoHS: RoHS; Temperature: -55°C+85°C; Tolerance: 10%; Voltage: 16V; Wattage: NA; Weight: 0.33mg; Datasheet: Y:\MIS_DATABASE\DATASHEETS\CAPACITORS\GRM033R61C104KE14.PDF
C193 C370 = CAP: CAP CERAMIC 0.1uF 50V 10% X7R 0402; Alt_Mfr_name: YAGEO AMERICA; Alt_Mfr_part_number: CC0402KRX5R8BB104; Chkd/date: MANIRAJA/261020; Crtd /date: ALVY/211020; Custom_Duty: 15%; Customs_HS_Code: 85322990; Distributor_name: DIGIKEY; Distributor_part_number: 490-10700-1-ND; Footprint Path: Y:\MIS_DATABASE\Library\ALTIUM_TOOL\PCB_FOOTPRINTS\Altium_Footprint_Lib.PcbLib; Height: 0.55MM; Library Path: Y:\MIS_DATABASE\Library\ALTIUM_TOOL\SCHEMATICS_PARTS\MS_DISCRETE_Library.schlib; Mfr_name: MURATA; Mfr_part_number: GRM155R71H104KE14D; Mistral Part No: 120011100014-R; Package: 0402; Part_type: CAPACITORS\CERAMIC; Project: J7_CP; RoHS: RoHS; Temperature: -55°C+125°C; Tolerance: 10%; Voltage: 50V; Wattage: NA; Weight: 3.1mg; Datasheet: Y:\MIS_DATABASE\DATASHEETS\CAPACITORS\GRM155R71H104KE14.PDF
FL17 FL18 = EMIFILTER_IND: IND FERRITE BEAD CHIP 120E 2A 0402; Chkd/date: NAVEED/241114; Crtd /date: USMAN/170613; Custom_Duty: 24%; Customs_HS_Code: 85369090; Distributor_name: DIGIKEY; Distributor_part_number: 490-9656-1-ND; Footprint Path: Y:\MIS_DATABASE\Library\ALTIUM_TOOL\PCB_FOOTPRINTS\Altium_Footprint_Lib.PcbLib; Height: 0.55MM; Library Path: Y:\MIS_DATABASE\Library\ALTIUM_TOOL\SCHEMATICS_PARTS\MS_FILTER_Library.schlib; Mfr_name: MURATA; Mfr_part_number: BLM15PX121SN1D; Mistral Part No: 130013060022-R; Package: 0402; Part_type: INDUCTOR; Project: GEN_3-8; RoHS: RoHS; Temperature: -55°C+125°C; Tolerance: 25%; Voltage: NA; Wattage: NA; Weight: 1mg; Datasheet: Y:\MIS_DATABASE\DATASHEETS\DISCRETES\INDUCTORS\BLM15-SN1-SER.PDF
J22 = CON_FLEX_40X1_SH4: CON FPC 1X40 0.50MM PITCH FEMALE ST SMD; Chkd/date: MANIRAJA/061021; Crtd /date: ALVY/041021; Custom_Duty: 24%; Customs_HS_Code: 85369090; Distributor_name: DIGIKEY; Distributor_part_number: 2073-FFC2A32-40-TCT-ND; Footprint Path: Y:\MIS_DATABASE\Library\ALTIUM_TOOL\PCB_FOOTPRINTS\Altium_Footprint_Lib.PcbLib; Height: 4.25MM; Library Path: Y:\MIS_DATABASE\Library\ALTIUM_TOOL\SCHEMATICS_PARTS\MS_CONNECTOR_Library.schlib; Mfr_name: GCT; Mfr_part_number: FFC2A32-40-T; Mistral Part No: 150021100004-R; Package: SMD; Part_type: CONNECTOR\FPC; Project: TI_AM62x SKEVM_BRD; RoHS: RoHS; Temperature: -25°C+85°C; Tolerance: NA; Voltage: NA; Wattage: NA; Weight: 710mg; Datasheet: Y:\MIS_DATABASE\DATASHEETS\CONNECTORS\FFC2A32.PDF
R180 = RESISTOR: RES 10K 1/20W 5% 0201; Assembly_Instruction: DNI; Chkd/date: MANIRAJA/050517; Crtd /date: MANIRAJA/050517; Custom_Duty: 15%; Customs_HS_Code: 85332119; Distributor_name: DIGIKEY; Distributor_part_number: 311-10KNCT-ND; Footprint Path: Y:\MIS_DATABASE\Library\ALTIUM_TOOL\PCB_FOOTPRINTS\Altium_Footprint_Lib.PcbLib; Height: 0.26MM; Library Path: Y:\MIS_DATABASE\Library\ALTIUM_TOOL\SCHEMATICS_PARTS\MS_DISCRETE_Library.schlib; Mfr_name: YAGEO AMERICA; Mfr_part_number: RC0201JR-0710KL; Mistral Part No: 110010070051-R; Package: 0201; Part_type: RESISTORS\FIXED; Project: GOLDEN-I LITE; RoHS: RoHS; Temperature: -55°C+125°C; Tolerance: 5%; Voltage: NA; Wattage: 1/20W; Weight: 0.17mg; Datasheet: Y:\MIS_DATABASE\DATASHEETS\RESISTORS\RCXXXXL-SER_MAR18.PDF
R412 = RESISTOR: RES 4.7K 1/20W 5% 0201; Assembly_Instruction: DNI; Chkd/date: MANIRAJA/200921; Crtd /date: ALVY/200921; Custom_Duty: 15%; Customs_HS_Code: 85332119; Distributor_name: DIGIKEY; Distributor_part_number: 311-4.7KNCT-ND; Footprint Path: Y:\MIS_DATABASE\Library\ALTIUM_TOOL\PCB_FOOTPRINTS\Altium_Footprint_Lib.PcbLib; Height: 0.26MM; Library Path: Y:\MIS_DATABASE\Library\ALTIUM_TOOL\SCHEMATICS_PARTS\MS_DISCRETE_Library.schlib; Mfr_name: YAGEO AMERICA; Mfr_part_number: RC0201JR-074K7L; Mistral Part No: 110021090007-R; Package: 0201; Part_type: RESISTORS\FIXED; Project: TI_AM62x SKEVM_BRD; RoHS: RoHS; Temperature: -55°C+125°C; Tolerance: 5%; Voltage: NA; Wattage: 1/20W; Weight: 0.17mg; Datasheet: Y:\MIS_DATABASE\DATASHEETS\RESISTORS\RCXXXXL-SER_MAR18.PDF
U41 = SN74LVC1G04DCKR_SC70-5: IC SINGLE INVERTER GATE X2SON5; Chkd/date: MANIRAJA/141020; Crtd /date: ALVY/131020; Custom_Duty: 15%; Customs_HS_Code: 85423100; Distributor_name: DIGIKEY; Distributor_part_number: 296-37758-1-ND; Footprint Path: Y:\MIS_DATABASE\Library\ALTIUM_TOOL\PCB_FOOTPRINTS\Altium_Footprint_Lib.PcbLib; Height: 0.40MM; Library Path: Y:\MIS_DATABASE\Library\ALTIUM_TOOL\SCHEMATICS_PARTS\MS_GATE_Library.schlib; Mfr_name: TEXAS INSTRUMENTS; Mistral Part No: 141020100010-R; Package: X2SON5; Part_type: ICS\DIGITAL\GATES; Project: AM64X_SKEVM; RoHS: RoHS; Temperature: -40°C+125°C; Tolerance: NA; Voltage: NA; Wattage: NA; Weight: 0.6mg; Datasheet: Y:\MIS_DATABASE\DATASHEETS\ICS\DIGITAL\GATES\SN74LVC1G04XX.PDF
U42 = SN74CB3Q3257PWR_TSSOP16: IC 4BIT 1-OF-2 FET MULTIPLEXER/DEMULTIPLEXER TSSOP16; Chkd/date: SUHAS/251010; Crtd /date: USMAN/060109; Custom_Duty: 15%; Customs_HS_Code: 85423100; Distributor_name: DIGIKEY; Distributor_part_number: 296-19138-1-ND; Footprint Path: Y:\MIS_DATABASE\Library\ALTIUM_TOOL\PCB_FOOTPRINTS\Altium_Footprint_Lib.PcbLib; Footprint Ref: TSSOP16_25-59_205X180_1-2; Height: 1.20MM; Library Path: Y:\MIS_DATABASE\Library\ALTIUM_TOOL\SCHEMATICS_PARTS\MS_COMBINATIONAL_Library.schlib; MECHANICAL 3D STEP FILE: TSSOP16_25-59_205X180_1-2; Mfr_name: TEXAS INSTRUMENTS; Mistral Part No: 141009030117-R; Package: TSSOP16; Part_type: ICS\DIGITAL\COMBINATIONAL; Project: OMAP_EVM; RoHS: Sb/ Br FREE; Temperature: -40°C+85°C; Datasheet: Y:\MIS_DATABASE\DATASHEETS\ICS\DIGITAL\COMBINATIONAL\SN74CB3Q3257.PDF
U44 = SN74AVC4T245RSV_UQFN16: IC 2-BIT BUS TRANSCEIVER WITH CONFIGURABLE VOLTAGE TRANSLATION AND 3 STATE O/P UQFN16; Chkd/date: MANIRAJA/040520; Crtd /date: BAVISH/190411; Custom_Duty: 15%; Customs_HS_Code: 85423100; Distributor_name: DIGIKEY; Distributor_part_number: 296-24366-1-ND; Footprint Path: Y:\MIS_DATABASE\Library\ALTIUM_TOOL\PCB_FOOTPRINTS\Altium_Footprint_Lib.PcbLib; Height: 0.55MM; Library Path: Y:\MIS_DATABASE\Library\ALTIUM_TOOL\SCHEMATICS_PARTS\MS_BUSDRIVERTRANSCEIVER_Library.schlib; Mfr_name: TEXAS INSTRUMENTS; Mistral Part No: 141011040011-R; Package: UQFN16; Part_type: ICS\DIGITAL\BUSTRANSCEIVER; Project: HMC; RoHS: RoHS; Temperature: -40°C+85°C; Tolerance: NA; Voltage: NA; Wattage: NA; Weight: 41mg; Datasheet: Y:\MIS_DATABASE\DATASHEETS\ICS\DIGITAL\BUSTRANSCEIVER\SN74AVC4T245-SER.PDF
U62 = SN74LVC1G08DBVRE4_SOT23-5: IC SINGLE 2-INPUT POSITIVE AND GATE SOT23-5; Chkd/date: SUHAS/221010; Crtd /date: USMAN/151008; Custom_Duty: 15%; Customs_HS_Code: 85423100; Distributor_name: DIGIKEY; Distributor_part_number: SN74LVC1G08DBVRE4-ND; Height: 1.45MM; Mfr_name: TEXAS INSTRUMENTS; Mistral Part No: 141009060026-R; Part_type: ICS\DIGITAL\GATES; Project: KHAN_MAIN; RoHS: Sb/ Br FREE; Temperature: -40°C+85°C; Datasheet: Y:\MIS_DATABASE\DATASHEETS\ICS\DIGITAL\GATES\SN74LVC1G08.PDF

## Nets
DGND: C109.2 C110.2 C111.2 C182.1 C183.1 C184.1 C193.1 C370.2 C375.2 C376.2 C379.1 C416.2 D2.1(A) D3.1(A) D6.2(ANODE) D7.1(GND) D11.2(ANODE) FL17.2 J9.4(GND) J15.A1(GND) J15.A12(GND) J15.B1(GND) J15.B12(GND) J22.6 J22.7 J22.10 J22.13 J22.16 J22.19 J22.22 J22.25 J22.28 J22.31 J22.34 J22.37 J22.40 LD6.1(CATHODE) LD9.1(CATHODE) Q8.2(EMITTER) Q14.4(S1) Q14.7(S2) Q15.4(S1) Q15.7(S2) R120.2 R131.2 R143.2 R180.1 R201.2 R280.1 R361.2 R366.2 R417.2 U23.2(GND) U41.3(GND) U42.8(GND) U44.10(GND1) U44.11(GND2) U62.3(GND) U77.1(GND) U77.2(GND) U77.3(GND) U77.7(GND) ; also on sheet 1 2 3 4 13 14 15 16 17 18 19 20 21 22 23 24 25 26 27 28 29 30 31 32 33 34 38 39 40 41 42 43
VBUS_5V0_TYPEA1: C110.1 C375.1 J9.1(VCC) R119.2 U23.4(OUT)
VBUS_TYPEC2: C532.1 J15.A4(VBUS1) J15.A9(VBUS2) J15.B4(VBUS3) J15.B9(VBUS4) R147.2 R214.1 R593.2 U77.4(IN1) U77.5(IN2) U77.6(IN3) ; also on sheet 13
VCC1V8_SYS: C184.2 U44.2(VCCB) ; also on sheet 4 16 19 20 22 25 34 39 40 42
VCC_3V3_SYS: C182.2 C183.2 C193.2 C370.1 C379.2 FL18.2 R139.2 R151.1 R155.2 R179.2 R278.2 R289.2 R407.2 R412.1 U41.5(VCC) U42.16(VCC) U44.3(VCCA) U62.5(VCC) ; also on sheet 1 4 15 16 19 20 21 23 24 26 27 29 30 31 32 33 34 38 39 40 41 42 43
VCC_5V0: C109.1 C111.1 U23.3(IN) ; also on sheet 13 14 33 38 41
VDDR_CORE: R406.1 ; also on sheet 16 17 18
CH1_LVDS_A0N: J22.11 U12.AA2(OLDI0_A0N)
CH1_LVDS_A0P: J22.12 U12.AA3(OLDI0_A0P)
CH1_LVDS_A1N: J22.14 U12.V5(OLDI0_A1N)
CH1_LVDS_A1P: J22.15 U12.V6(OLDI0_A1P)
CH1_LVDS_A2N: J22.20 U12.U7(OLDI0_A2N)
CH1_LVDS_A2P: J22.21 U12.U6(OLDI0_A2P)
CH1_LVDS_A3N: J22.23 U12.W6(OLDI0_A3N)
CH1_LVDS_A3P: J22.24 U12.W5(OLDI0_A3P)
CH1_LVDS_CLKN: J22.17 U12.V7(OLDI0_CLK0N)
CH1_LVDS_CLKP: J22.18 U12.V8(OLDI0_CLK0P)
CH2_LVDS_A0N: J22.26 U12.AA4(OLDI0_A4N)
CH2_LVDS_A0P: J22.27 U12.Y5(OLDI0_A4P)
CH2_LVDS_A1N: J22.29 U12.AA6(OLDI0_A5N)
CH2_LVDS_A1P: J22.30 U12.AA5(OLDI0_A5P)
CH2_LVDS_A2N: J22.35 U12.AA10(OLDI0_A6N)
CH2_LVDS_A2P: J22.36 U12.Y9(OLDI0_A6P)
CH2_LVDS_A3N: J22.38 U12.AA8(OLDI0_A7N)
CH2_LVDS_A3P: J22.39 U12.Y8(OLDI0_A7P)
CH2_LVDS_CLKN: J22.32 U12.Y7(OLDI0_CLK1N)
CH2_LVDS_CLKP: J22.33 U12.AA7(OLDI0_CLK1P)
EEPROM_VDD: FL18.1 J22.1
EXP_SPI2_CLK: U42.5(2B1) ; also on sheet 33
EXP_SPI2_CS0/EHRPWM0_A: U42.2(1B1) ; also on sheet 33
EXP_SPI2_D0: U42.11(3B1) ; also on sheet 33
EXP_SPI2_D1/ECAP2_IN_APWM_OUT: U42.14(4B1) ; also on sheet 33
GPIO_OLDI_RSTn: R407.1 U62.1(A) ; also on sheet 39
LVDS_SHIELD: FL17.1 J22.SH1 J22.SH2 J22.SH3 J22.SH4
OLDI_RESETn: J22.8 R412.2 U62.4(Y)
RESETSTATz: U62.2(B) ; also on sheet 1 4 20 21 22 24 27 32 38 39 40 41 42
SoC_I2C0_SCL: J22.2 ; also on sheet 4 13 23 32 33 42
SoC_I2C0_SDA: J22.3 ; also on sheet 4 13 23 32 33 42
SOC_SPI2_CLK: U42.7(2A) U44.8(2A1) ; also on sheet 33
SOC_SPI2_CS0: U42.4(1A) U44.6(1A1) ; also on sheet 33
SOC_SPI2_D0: U42.9(3A) U44.7(1A2) ; also on sheet 33
SOC_SPI2_D1: U42.12(4A) U44.9(2A2) ; also on sheet 33
SOC_UART1_CTS: U42.10(3B2) ; also on sheet 31
SOC_UART1_CTS_BT: U44.14(1B2) ; also on sheet 19
SOC_UART1_RTS: U42.13(4B2) ; also on sheet 31
SOC_UART1_RTS_BT: U44.12(2B2) ; also on sheet 19
SOC_UART1_RX_BT: U44.15(1B1) ; also on sheet 19
SOC_UART1_RXD: U42.3(1B2) ; also on sheet 31
SOC_UART1_TX_BT: U44.13(2B1) ; also on sheet 19
SOC_UART1_TXD: U42.6(2B2) ; also on sheet 31
SoC_USB0_DM: L5.4(OUT2) U12.AA11(USB0_DM)
SoC_USB0_DP: L5.1(IN1) U12.Y10(USB0_DP)
SoC_USB0_DRVVBUS: R592.1 U12.D17(USB0_DRVVBUS) ; also on sheet 13
SoC_USB0_RCALIB: R366.1 U12.T8(USB0_RCALIB)
SoC_USB0_VBUS: R143.1 R145.1 U12.V10(USB0_VBUS)
SoC_USB1_DM: L4.1(IN1) U12.W8(USB1_DM)
SoC_USB1_DP: L4.4(OUT2) U12.W9(USB1_DP)
SoC_USB1_DRVVBUS: R131.1 R132.1 U12.E16(USB1_DRVVBUS)
SoC_USB1_RCALIB: R361.1 U12.V9(USB1_RCALIB)
SoC_USB1_VBUS: R118.1 R120.1 U12.U9(USB1_VBUS)
TS_INT#: J22.9 R151.2 ; also on sheet 39
UART1_FET_BUF_EN: R289.1 U41.2(A) U44.1(~{1OE}) U44.16(~{2OE}) ; also on sheet 39
UART1_FET_BUF_EN_INV: U41.4(Y) U42.15(~{OE})
UART1_FET_SEL: R179.1 R180.2 U42.1(S) ; also on sheet 39
USB_TYPEA_EARTH: C376.1 J9.SH1 J9.SH2 R417.1
USB_TYPEACONN1_DM: J9.2(D-) L4.2(IN2) U23.5(D1)
USB_TYPEACONN1_DP: J9.3(D+) L4.3(OUT1) U23.6(D2)
USB_TYPEC2_EARTH: C416.1 J15.SH1 J15.SH2 J15.SH3 J15.SH4 R201.1
USBC_CONN2_CC1: D6.1(CATHODE) J15.A5(CC1) ; also on sheet 13
USBC_CONN2_CC2: D11.1(CATHODE) J15.B5(CC2) ; also on sheet 13
USBC_CONN2_DM: D7.3(IO2) J15.A7(D-_1) J15.B7(D-_2) L5.3(OUT1)
USBC_CONN2_DP: D7.2(IO1) J15.A6(D+_1) J15.B6(D+_2) L5.2(IN2)
N17031262: LD9.2(ANODE) R214.2
N17726648: D3.3(C) R145.2 R147.1
N20199452: D2.3(C) R118.2 R119.1
N20933818: R280.2 U44.4(1DIR)
N20933822: R278.1 U44.5(2DIR)
N21030238: LD6.2(ANODE) R155.1
N21068099: R132.2 U23.1(EN)
N21117349: LD5.1(CATHODE) Q8.3(COLLECTOR)
N21117357: LD5.2(ANODE) R139.1
N21117537: Q8.1(BASE) R406.2
N22221349: Q15.3(G) R592.2
N22221705: C532.2 Q14.1(D1) Q14.2(D2) Q14.5(D3) Q14.6(D4) Q14.8(D5)
N22234960: Q15.1(D1) Q15.2(D2) Q15.5(D3) Q15.6(D4) Q15.8(D5) R593.1 R594.1
N22235133: Q14.3(G) R594.2

Not connected (* = marked no-connect by the designer): D2 2(NC)*; D3 2(NC)*; J15 A2(TX1+)* A3(TX1-)* A8(SBU1)* A10(RX2-)* A11(RX2+)* B2(TX2+)* B3(TX2-)* B8(SBU2)* B10(RX1-)* B11(RX1+)*; J22 4* 5*; U41 1(NC)*

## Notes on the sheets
sheet 35
- USB 2.0 TYPE-A
- 90E
- To Type- C connector
  Port: 2 of PD Controller
- 90E
- To Type- A connector
- 90E
- DLW21SZ900HQ2B
- Silk: TYPE-A
- Note: Recommended VBUS circuit for USB connector. Supports 5V-30V VBUS
sheet 36
- USB 2.0 TYPE-C DRP
- Silk: TYPE-C DRP
- 90E
- DLW21SZ900HQ2B
- MOSFET SWITCH FOR ADDITIONAL CAPACITANCE
- POWER INDICATION LED: VBUS_TYPEC2
- POWER RAIL LEDS
sheet 37
- OLDI DISPLAY INTERFACE
- 100E
- 100E
- 100E
- 100E
- 100E
- 100E
- 100E
- 100E
- 100E
- 100E
- SoC UART1 FET SWITCH & BUFFER
- INPUT/OUTPUT
- OEn
- SEL
- An
- L
- L
- An=nB1
- SOC - EXP CONN
- L
- H(DEFAULT)
- An=nB2
- SOC - FT4232
- SoC_MAIN_UART1_RXD
- SoC_MAIN_UART1_RXD
- SoC_MAIN_UART1_CTS
- SoC_MAIN_UART1_CTS
- SoC_MAIN_UART1_TXD
- SoC_MAIN_UART1_TXD
- SoC_MAIN_UART1_RTS
- SoC_MAIN_UART1_RTS
- 2DIR=H : 2A ->2B
  1DIR=L : 1B ->1A
